VERSION 5.8 ;
BUSBITCHARS "[]" ;
DIVIDERCHAR "/" ;
UNITS
    DATABASE MICRONS 1000 ;
END UNITS

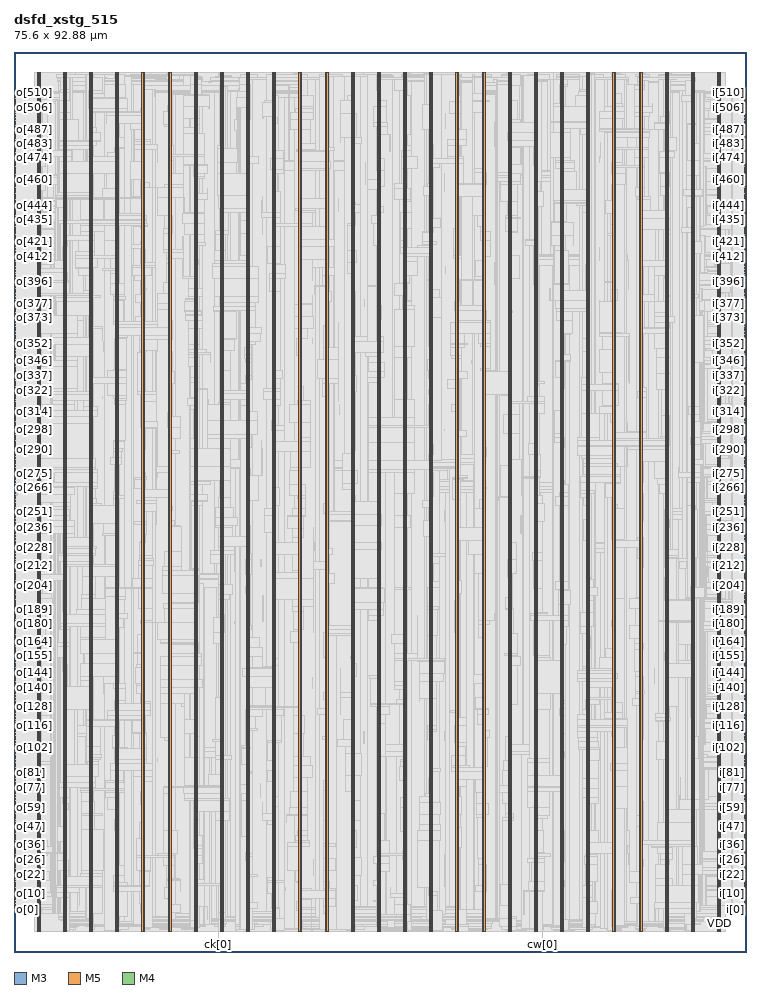
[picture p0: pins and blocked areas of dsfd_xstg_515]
MACRO dsfd_xstg_515
  FOREIGN dsfd_xstg_515 0 0 ;
  CLASS BLOCK ;
  SIZE 75.6 BY 92.88 ;
  PIN ck[0]
    DIRECTION INPUT ;
    USE SIGNAL ;
    PORT
      LAYER M3 ;
        RECT  21.06 0 21.078 0.144 ;
    END
  END ck[0]
  PIN cw[0]
    DIRECTION INPUT ;
    USE SIGNAL ;
    PORT
      LAYER M5 ;
        RECT  54.528 0 54.552 0.192 ;
    END
  END cw[0]
  PIN i[0]
    DIRECTION INPUT ;
    USE SIGNAL ;
    PORT
      LAYER M4 ;
        RECT  75.408 4.416 75.6 4.44 ;
    END
  END i[0]
  PIN i[100]
    DIRECTION INPUT ;
    USE SIGNAL ;
    PORT
      LAYER M4 ;
        RECT  75.408 20.784 75.6 20.808 ;
    END
  END i[100]
  PIN i[101]
    DIRECTION INPUT ;
    USE SIGNAL ;
    PORT
      LAYER M4 ;
        RECT  75.408 20.928 75.6 20.952 ;
    END
  END i[101]
  PIN i[102]
    DIRECTION INPUT ;
    USE SIGNAL ;
    PORT
      LAYER M4 ;
        RECT  75.408 21.12 75.6 21.144 ;
    END
  END i[102]
  PIN i[103]
    DIRECTION INPUT ;
    USE SIGNAL ;
    PORT
      LAYER M4 ;
        RECT  75.408 21.264 75.6 21.288 ;
    END
  END i[103]
  PIN i[104]
    DIRECTION INPUT ;
    USE SIGNAL ;
    PORT
      LAYER M4 ;
        RECT  75.408 21.408 75.6 21.432 ;
    END
  END i[104]
  PIN i[105]
    DIRECTION INPUT ;
    USE SIGNAL ;
    PORT
      LAYER M4 ;
        RECT  75.408 21.6 75.6 21.624 ;
    END
  END i[105]
  PIN i[106]
    DIRECTION INPUT ;
    USE SIGNAL ;
    PORT
      LAYER M4 ;
        RECT  75.408 21.744 75.6 21.768 ;
    END
  END i[106]
  PIN i[107]
    DIRECTION INPUT ;
    USE SIGNAL ;
    PORT
      LAYER M4 ;
        RECT  75.408 21.936 75.6 21.96 ;
    END
  END i[107]
  PIN i[108]
    DIRECTION INPUT ;
    USE SIGNAL ;
    PORT
      LAYER M4 ;
        RECT  75.408 22.08 75.6 22.104 ;
    END
  END i[108]
  PIN i[109]
    DIRECTION INPUT ;
    USE SIGNAL ;
    PORT
      LAYER M4 ;
        RECT  75.408 22.224 75.6 22.248 ;
    END
  END i[109]
  PIN i[10]
    DIRECTION INPUT ;
    USE SIGNAL ;
    PORT
      LAYER M4 ;
        RECT  75.408 6.048 75.6 6.072 ;
    END
  END i[10]
  PIN i[110]
    DIRECTION INPUT ;
    USE SIGNAL ;
    PORT
      LAYER M4 ;
        RECT  75.408 22.416 75.6 22.44 ;
    END
  END i[110]
  PIN i[111]
    DIRECTION INPUT ;
    USE SIGNAL ;
    PORT
      LAYER M4 ;
        RECT  75.408 22.56 75.6 22.584 ;
    END
  END i[111]
  PIN i[112]
    DIRECTION INPUT ;
    USE SIGNAL ;
    PORT
      LAYER M4 ;
        RECT  75.408 22.752 75.6 22.776 ;
    END
  END i[112]
  PIN i[113]
    DIRECTION INPUT ;
    USE SIGNAL ;
    PORT
      LAYER M4 ;
        RECT  75.408 22.896 75.6 22.92 ;
    END
  END i[113]
  PIN i[114]
    DIRECTION INPUT ;
    USE SIGNAL ;
    PORT
      LAYER M4 ;
        RECT  75.408 23.04 75.6 23.064 ;
    END
  END i[114]
  PIN i[115]
    DIRECTION INPUT ;
    USE SIGNAL ;
    PORT
      LAYER M4 ;
        RECT  75.408 23.232 75.6 23.256 ;
    END
  END i[115]
  PIN i[116]
    DIRECTION INPUT ;
    USE SIGNAL ;
    PORT
      LAYER M4 ;
        RECT  75.408 23.376 75.6 23.4 ;
    END
  END i[116]
  PIN i[117]
    DIRECTION INPUT ;
    USE SIGNAL ;
    PORT
      LAYER M4 ;
        RECT  75.408 23.568 75.6 23.592 ;
    END
  END i[117]
  PIN i[118]
    DIRECTION INPUT ;
    USE SIGNAL ;
    PORT
      LAYER M4 ;
        RECT  75.408 23.712 75.6 23.736 ;
    END
  END i[118]
  PIN i[119]
    DIRECTION INPUT ;
    USE SIGNAL ;
    PORT
      LAYER M4 ;
        RECT  75.408 23.856 75.6 23.88 ;
    END
  END i[119]
  PIN i[11]
    DIRECTION INPUT ;
    USE SIGNAL ;
    PORT
      LAYER M4 ;
        RECT  75.408 6.192 75.6 6.216 ;
    END
  END i[11]
  PIN i[120]
    DIRECTION INPUT ;
    USE SIGNAL ;
    PORT
      LAYER M4 ;
        RECT  75.408 24.048 75.6 24.072 ;
    END
  END i[120]
  PIN i[121]
    DIRECTION INPUT ;
    USE SIGNAL ;
    PORT
      LAYER M4 ;
        RECT  75.408 24.192 75.6 24.216 ;
    END
  END i[121]
  PIN i[122]
    DIRECTION INPUT ;
    USE SIGNAL ;
    PORT
      LAYER M4 ;
        RECT  75.408 24.384 75.6 24.408 ;
    END
  END i[122]
  PIN i[123]
    DIRECTION INPUT ;
    USE SIGNAL ;
    PORT
      LAYER M4 ;
        RECT  75.408 24.528 75.6 24.552 ;
    END
  END i[123]
  PIN i[124]
    DIRECTION INPUT ;
    USE SIGNAL ;
    PORT
      LAYER M4 ;
        RECT  75.408 24.72 75.6 24.744 ;
    END
  END i[124]
  PIN i[125]
    DIRECTION INPUT ;
    USE SIGNAL ;
    PORT
      LAYER M4 ;
        RECT  75.408 24.864 75.6 24.888 ;
    END
  END i[125]
  PIN i[126]
    DIRECTION INPUT ;
    USE SIGNAL ;
    PORT
      LAYER M4 ;
        RECT  75.408 25.008 75.6 25.032 ;
    END
  END i[126]
  PIN i[127]
    DIRECTION INPUT ;
    USE SIGNAL ;
    PORT
      LAYER M4 ;
        RECT  75.408 25.2 75.6 25.224 ;
    END
  END i[127]
  PIN i[128]
    DIRECTION INPUT ;
    USE SIGNAL ;
    PORT
      LAYER M4 ;
        RECT  75.408 25.344 75.6 25.368 ;
    END
  END i[128]
  PIN i[129]
    DIRECTION INPUT ;
    USE SIGNAL ;
    PORT
      LAYER M4 ;
        RECT  75.408 25.536 75.6 25.56 ;
    END
  END i[129]
  PIN i[12]
    DIRECTION INPUT ;
    USE SIGNAL ;
    PORT
      LAYER M4 ;
        RECT  75.408 6.384 75.6 6.408 ;
    END
  END i[12]
  PIN i[130]
    DIRECTION INPUT ;
    USE SIGNAL ;
    PORT
      LAYER M4 ;
        RECT  75.408 25.68 75.6 25.704 ;
    END
  END i[130]
  PIN i[131]
    DIRECTION INPUT ;
    USE SIGNAL ;
    PORT
      LAYER M4 ;
        RECT  75.408 25.824 75.6 25.848 ;
    END
  END i[131]
  PIN i[132]
    DIRECTION INPUT ;
    USE SIGNAL ;
    PORT
      LAYER M4 ;
        RECT  75.408 26.016 75.6 26.04 ;
    END
  END i[132]
  PIN i[133]
    DIRECTION INPUT ;
    USE SIGNAL ;
    PORT
      LAYER M4 ;
        RECT  75.408 26.16 75.6 26.184 ;
    END
  END i[133]
  PIN i[134]
    DIRECTION INPUT ;
    USE SIGNAL ;
    PORT
      LAYER M4 ;
        RECT  75.408 26.352 75.6 26.376 ;
    END
  END i[134]
  PIN i[135]
    DIRECTION INPUT ;
    USE SIGNAL ;
    PORT
      LAYER M4 ;
        RECT  75.408 26.496 75.6 26.52 ;
    END
  END i[135]
  PIN i[136]
    DIRECTION INPUT ;
    USE SIGNAL ;
    PORT
      LAYER M4 ;
        RECT  75.408 26.64 75.6 26.664 ;
    END
  END i[136]
  PIN i[137]
    DIRECTION INPUT ;
    USE SIGNAL ;
    PORT
      LAYER M4 ;
        RECT  75.408 26.832 75.6 26.856 ;
    END
  END i[137]
  PIN i[138]
    DIRECTION INPUT ;
    USE SIGNAL ;
    PORT
      LAYER M4 ;
        RECT  75.408 26.976 75.6 27 ;
    END
  END i[138]
  PIN i[139]
    DIRECTION INPUT ;
    USE SIGNAL ;
    PORT
      LAYER M4 ;
        RECT  75.408 27.168 75.6 27.192 ;
    END
  END i[139]
  PIN i[13]
    DIRECTION INPUT ;
    USE SIGNAL ;
    PORT
      LAYER M4 ;
        RECT  75.408 6.528 75.6 6.552 ;
    END
  END i[13]
  PIN i[140]
    DIRECTION INPUT ;
    USE SIGNAL ;
    PORT
      LAYER M4 ;
        RECT  75.408 27.312 75.6 27.336 ;
    END
  END i[140]
  PIN i[141]
    DIRECTION INPUT ;
    USE SIGNAL ;
    PORT
      LAYER M4 ;
        RECT  75.408 27.456 75.6 27.48 ;
    END
  END i[141]
  PIN i[142]
    DIRECTION INPUT ;
    USE SIGNAL ;
    PORT
      LAYER M4 ;
        RECT  75.408 27.648 75.6 27.672 ;
    END
  END i[142]
  PIN i[143]
    DIRECTION INPUT ;
    USE SIGNAL ;
    PORT
      LAYER M4 ;
        RECT  75.408 27.792 75.6 27.816 ;
    END
  END i[143]
  PIN i[144]
    DIRECTION INPUT ;
    USE SIGNAL ;
    PORT
      LAYER M4 ;
        RECT  75.408 27.984 75.6 28.008 ;
    END
  END i[144]
  PIN i[145]
    DIRECTION INPUT ;
    USE SIGNAL ;
    PORT
      LAYER M4 ;
        RECT  75.408 28.128 75.6 28.152 ;
    END
  END i[145]
  PIN i[146]
    DIRECTION INPUT ;
    USE SIGNAL ;
    PORT
      LAYER M4 ;
        RECT  75.408 28.272 75.6 28.296 ;
    END
  END i[146]
  PIN i[147]
    DIRECTION INPUT ;
    USE SIGNAL ;
    PORT
      LAYER M4 ;
        RECT  75.408 28.464 75.6 28.488 ;
    END
  END i[147]
  PIN i[148]
    DIRECTION INPUT ;
    USE SIGNAL ;
    PORT
      LAYER M4 ;
        RECT  75.408 28.608 75.6 28.632 ;
    END
  END i[148]
  PIN i[149]
    DIRECTION INPUT ;
    USE SIGNAL ;
    PORT
      LAYER M4 ;
        RECT  75.408 28.8 75.6 28.824 ;
    END
  END i[149]
  PIN i[14]
    DIRECTION INPUT ;
    USE SIGNAL ;
    PORT
      LAYER M4 ;
        RECT  75.408 6.72 75.6 6.744 ;
    END
  END i[14]
  PIN i[150]
    DIRECTION INPUT ;
    USE SIGNAL ;
    PORT
      LAYER M4 ;
        RECT  75.408 28.944 75.6 28.968 ;
    END
  END i[150]
  PIN i[151]
    DIRECTION INPUT ;
    USE SIGNAL ;
    PORT
      LAYER M4 ;
        RECT  75.408 29.136 75.6 29.16 ;
    END
  END i[151]
  PIN i[152]
    DIRECTION INPUT ;
    USE SIGNAL ;
    PORT
      LAYER M4 ;
        RECT  75.408 29.28 75.6 29.304 ;
    END
  END i[152]
  PIN i[153]
    DIRECTION INPUT ;
    USE SIGNAL ;
    PORT
      LAYER M4 ;
        RECT  75.408 29.424 75.6 29.448 ;
    END
  END i[153]
  PIN i[154]
    DIRECTION INPUT ;
    USE SIGNAL ;
    PORT
      LAYER M4 ;
        RECT  75.408 29.616 75.6 29.64 ;
    END
  END i[154]
  PIN i[155]
    DIRECTION INPUT ;
    USE SIGNAL ;
    PORT
      LAYER M4 ;
        RECT  75.408 29.76 75.6 29.784 ;
    END
  END i[155]
  PIN i[156]
    DIRECTION INPUT ;
    USE SIGNAL ;
    PORT
      LAYER M4 ;
        RECT  75.408 29.952 75.6 29.976 ;
    END
  END i[156]
  PIN i[157]
    DIRECTION INPUT ;
    USE SIGNAL ;
    PORT
      LAYER M4 ;
        RECT  75.408 30.096 75.6 30.12 ;
    END
  END i[157]
  PIN i[158]
    DIRECTION INPUT ;
    USE SIGNAL ;
    PORT
      LAYER M4 ;
        RECT  75.408 30.24 75.6 30.264 ;
    END
  END i[158]
  PIN i[159]
    DIRECTION INPUT ;
    USE SIGNAL ;
    PORT
      LAYER M4 ;
        RECT  75.408 30.432 75.6 30.456 ;
    END
  END i[159]
  PIN i[15]
    DIRECTION INPUT ;
    USE SIGNAL ;
    PORT
      LAYER M4 ;
        RECT  75.408 6.864 75.6 6.888 ;
    END
  END i[15]
  PIN i[160]
    DIRECTION INPUT ;
    USE SIGNAL ;
    PORT
      LAYER M4 ;
        RECT  75.408 30.576 75.6 30.6 ;
    END
  END i[160]
  PIN i[161]
    DIRECTION INPUT ;
    USE SIGNAL ;
    PORT
      LAYER M4 ;
        RECT  75.408 30.768 75.6 30.792 ;
    END
  END i[161]
  PIN i[162]
    DIRECTION INPUT ;
    USE SIGNAL ;
    PORT
      LAYER M4 ;
        RECT  75.408 30.912 75.6 30.936 ;
    END
  END i[162]
  PIN i[163]
    DIRECTION INPUT ;
    USE SIGNAL ;
    PORT
      LAYER M4 ;
        RECT  75.408 31.056 75.6 31.08 ;
    END
  END i[163]
  PIN i[164]
    DIRECTION INPUT ;
    USE SIGNAL ;
    PORT
      LAYER M4 ;
        RECT  75.408 31.248 75.6 31.272 ;
    END
  END i[164]
  PIN i[165]
    DIRECTION INPUT ;
    USE SIGNAL ;
    PORT
      LAYER M4 ;
        RECT  75.408 31.392 75.6 31.416 ;
    END
  END i[165]
  PIN i[166]
    DIRECTION INPUT ;
    USE SIGNAL ;
    PORT
      LAYER M4 ;
        RECT  75.408 31.584 75.6 31.608 ;
    END
  END i[166]
  PIN i[167]
    DIRECTION INPUT ;
    USE SIGNAL ;
    PORT
      LAYER M4 ;
        RECT  75.408 31.728 75.6 31.752 ;
    END
  END i[167]
  PIN i[168]
    DIRECTION INPUT ;
    USE SIGNAL ;
    PORT
      LAYER M4 ;
        RECT  75.408 31.872 75.6 31.896 ;
    END
  END i[168]
  PIN i[169]
    DIRECTION INPUT ;
    USE SIGNAL ;
    PORT
      LAYER M4 ;
        RECT  75.408 32.064 75.6 32.088 ;
    END
  END i[169]
  PIN i[16]
    DIRECTION INPUT ;
    USE SIGNAL ;
    PORT
      LAYER M4 ;
        RECT  75.408 7.008 75.6 7.032 ;
    END
  END i[16]
  PIN i[170]
    DIRECTION INPUT ;
    USE SIGNAL ;
    PORT
      LAYER M4 ;
        RECT  75.408 32.208 75.6 32.232 ;
    END
  END i[170]
  PIN i[171]
    DIRECTION INPUT ;
    USE SIGNAL ;
    PORT
      LAYER M4 ;
        RECT  75.408 32.4 75.6 32.424 ;
    END
  END i[171]
  PIN i[172]
    DIRECTION INPUT ;
    USE SIGNAL ;
    PORT
      LAYER M4 ;
        RECT  75.408 32.544 75.6 32.568 ;
    END
  END i[172]
  PIN i[173]
    DIRECTION INPUT ;
    USE SIGNAL ;
    PORT
      LAYER M4 ;
        RECT  75.408 32.688 75.6 32.712 ;
    END
  END i[173]
  PIN i[174]
    DIRECTION INPUT ;
    USE SIGNAL ;
    PORT
      LAYER M4 ;
        RECT  75.408 32.88 75.6 32.904 ;
    END
  END i[174]
  PIN i[175]
    DIRECTION INPUT ;
    USE SIGNAL ;
    PORT
      LAYER M4 ;
        RECT  75.408 33.024 75.6 33.048 ;
    END
  END i[175]
  PIN i[176]
    DIRECTION INPUT ;
    USE SIGNAL ;
    PORT
      LAYER M4 ;
        RECT  75.408 33.216 75.6 33.24 ;
    END
  END i[176]
  PIN i[177]
    DIRECTION INPUT ;
    USE SIGNAL ;
    PORT
      LAYER M4 ;
        RECT  75.408 33.36 75.6 33.384 ;
    END
  END i[177]
  PIN i[178]
    DIRECTION INPUT ;
    USE SIGNAL ;
    PORT
      LAYER M4 ;
        RECT  75.408 33.552 75.6 33.576 ;
    END
  END i[178]
  PIN i[179]
    DIRECTION INPUT ;
    USE SIGNAL ;
    PORT
      LAYER M4 ;
        RECT  75.408 33.696 75.6 33.72 ;
    END
  END i[179]
  PIN i[17]
    DIRECTION INPUT ;
    USE SIGNAL ;
    PORT
      LAYER M4 ;
        RECT  75.408 7.2 75.6 7.224 ;
    END
  END i[17]
  PIN i[180]
    DIRECTION INPUT ;
    USE SIGNAL ;
    PORT
      LAYER M4 ;
        RECT  75.408 33.84 75.6 33.864 ;
    END
  END i[180]
  PIN i[181]
    DIRECTION INPUT ;
    USE SIGNAL ;
    PORT
      LAYER M4 ;
        RECT  75.408 34.032 75.6 34.056 ;
    END
  END i[181]
  PIN i[182]
    DIRECTION INPUT ;
    USE SIGNAL ;
    PORT
      LAYER M4 ;
        RECT  75.408 34.176 75.6 34.2 ;
    END
  END i[182]
  PIN i[183]
    DIRECTION INPUT ;
    USE SIGNAL ;
    PORT
      LAYER M4 ;
        RECT  75.408 34.368 75.6 34.392 ;
    END
  END i[183]
  PIN i[184]
    DIRECTION INPUT ;
    USE SIGNAL ;
    PORT
      LAYER M4 ;
        RECT  75.408 34.512 75.6 34.536 ;
    END
  END i[184]
  PIN i[185]
    DIRECTION INPUT ;
    USE SIGNAL ;
    PORT
      LAYER M4 ;
        RECT  75.408 34.656 75.6 34.68 ;
    END
  END i[185]
  PIN i[186]
    DIRECTION INPUT ;
    USE SIGNAL ;
    PORT
      LAYER M4 ;
        RECT  75.408 34.848 75.6 34.872 ;
    END
  END i[186]
  PIN i[187]
    DIRECTION INPUT ;
    USE SIGNAL ;
    PORT
      LAYER M4 ;
        RECT  75.408 34.992 75.6 35.016 ;
    END
  END i[187]
  PIN i[188]
    DIRECTION INPUT ;
    USE SIGNAL ;
    PORT
      LAYER M4 ;
        RECT  75.408 35.184 75.6 35.208 ;
    END
  END i[188]
  PIN i[189]
    DIRECTION INPUT ;
    USE SIGNAL ;
    PORT
      LAYER M4 ;
        RECT  75.408 35.328 75.6 35.352 ;
    END
  END i[189]
  PIN i[18]
    DIRECTION INPUT ;
    USE SIGNAL ;
    PORT
      LAYER M4 ;
        RECT  75.408 7.344 75.6 7.368 ;
    END
  END i[18]
  PIN i[190]
    DIRECTION INPUT ;
    USE SIGNAL ;
    PORT
      LAYER M4 ;
        RECT  75.408 35.472 75.6 35.496 ;
    END
  END i[190]
  PIN i[191]
    DIRECTION INPUT ;
    USE SIGNAL ;
    PORT
      LAYER M4 ;
        RECT  75.408 35.664 75.6 35.688 ;
    END
  END i[191]
  PIN i[192]
    DIRECTION INPUT ;
    USE SIGNAL ;
    PORT
      LAYER M4 ;
        RECT  75.408 35.808 75.6 35.832 ;
    END
  END i[192]
  PIN i[193]
    DIRECTION INPUT ;
    USE SIGNAL ;
    PORT
      LAYER M4 ;
        RECT  75.408 36 75.6 36.024 ;
    END
  END i[193]
  PIN i[194]
    DIRECTION INPUT ;
    USE SIGNAL ;
    PORT
      LAYER M4 ;
        RECT  75.408 36.144 75.6 36.168 ;
    END
  END i[194]
  PIN i[195]
    DIRECTION INPUT ;
    USE SIGNAL ;
    PORT
      LAYER M4 ;
        RECT  75.408 36.288 75.6 36.312 ;
    END
  END i[195]
  PIN i[196]
    DIRECTION INPUT ;
    USE SIGNAL ;
    PORT
      LAYER M4 ;
        RECT  75.408 36.48 75.6 36.504 ;
    END
  END i[196]
  PIN i[197]
    DIRECTION INPUT ;
    USE SIGNAL ;
    PORT
      LAYER M4 ;
        RECT  75.408 36.624 75.6 36.648 ;
    END
  END i[197]
  PIN i[198]
    DIRECTION INPUT ;
    USE SIGNAL ;
    PORT
      LAYER M4 ;
        RECT  75.408 36.816 75.6 36.84 ;
    END
  END i[198]
  PIN i[199]
    DIRECTION INPUT ;
    USE SIGNAL ;
    PORT
      LAYER M4 ;
        RECT  75.408 36.96 75.6 36.984 ;
    END
  END i[199]
  PIN i[19]
    DIRECTION INPUT ;
    USE SIGNAL ;
    PORT
      LAYER M4 ;
        RECT  75.408 7.536 75.6 7.56 ;
    END
  END i[19]
  PIN i[1]
    DIRECTION INPUT ;
    USE SIGNAL ;
    PORT
      LAYER M4 ;
        RECT  75.408 4.56 75.6 4.584 ;
    END
  END i[1]
  PIN i[200]
    DIRECTION INPUT ;
    USE SIGNAL ;
    PORT
      LAYER M4 ;
        RECT  75.408 37.152 75.6 37.176 ;
    END
  END i[200]
  PIN i[201]
    DIRECTION INPUT ;
    USE SIGNAL ;
    PORT
      LAYER M4 ;
        RECT  75.408 37.296 75.6 37.32 ;
    END
  END i[201]
  PIN i[202]
    DIRECTION INPUT ;
    USE SIGNAL ;
    PORT
      LAYER M4 ;
        RECT  75.408 37.44 75.6 37.464 ;
    END
  END i[202]
  PIN i[203]
    DIRECTION INPUT ;
    USE SIGNAL ;
    PORT
      LAYER M4 ;
        RECT  75.408 37.632 75.6 37.656 ;
    END
  END i[203]
  PIN i[204]
    DIRECTION INPUT ;
    USE SIGNAL ;
    PORT
      LAYER M4 ;
        RECT  75.408 37.776 75.6 37.8 ;
    END
  END i[204]
  PIN i[205]
    DIRECTION INPUT ;
    USE SIGNAL ;
    PORT
      LAYER M4 ;
        RECT  75.408 37.968 75.6 37.992 ;
    END
  END i[205]
  PIN i[206]
    DIRECTION INPUT ;
    USE SIGNAL ;
    PORT
      LAYER M4 ;
        RECT  75.408 38.112 75.6 38.136 ;
    END
  END i[206]
  PIN i[207]
    DIRECTION INPUT ;
    USE SIGNAL ;
    PORT
      LAYER M4 ;
        RECT  75.408 38.256 75.6 38.28 ;
    END
  END i[207]
  PIN i[208]
    DIRECTION INPUT ;
    USE SIGNAL ;
    PORT
      LAYER M4 ;
        RECT  75.408 38.448 75.6 38.472 ;
    END
  END i[208]
  PIN i[209]
    DIRECTION INPUT ;
    USE SIGNAL ;
    PORT
      LAYER M4 ;
        RECT  75.408 38.592 75.6 38.616 ;
    END
  END i[209]
  PIN i[20]
    DIRECTION INPUT ;
    USE SIGNAL ;
    PORT
      LAYER M4 ;
        RECT  75.408 7.68 75.6 7.704 ;
    END
  END i[20]
  PIN i[210]
    DIRECTION INPUT ;
    USE SIGNAL ;
    PORT
      LAYER M4 ;
        RECT  75.408 38.784 75.6 38.808 ;
    END
  END i[210]
  PIN i[211]
    DIRECTION INPUT ;
    USE SIGNAL ;
    PORT
      LAYER M4 ;
        RECT  75.408 38.928 75.6 38.952 ;
    END
  END i[211]
  PIN i[212]
    DIRECTION INPUT ;
    USE SIGNAL ;
    PORT
      LAYER M4 ;
        RECT  75.408 39.072 75.6 39.096 ;
    END
  END i[212]
  PIN i[213]
    DIRECTION INPUT ;
    USE SIGNAL ;
    PORT
      LAYER M4 ;
        RECT  75.408 39.264 75.6 39.288 ;
    END
  END i[213]
  PIN i[214]
    DIRECTION INPUT ;
    USE SIGNAL ;
    PORT
      LAYER M4 ;
        RECT  75.408 39.408 75.6 39.432 ;
    END
  END i[214]
  PIN i[215]
    DIRECTION INPUT ;
    USE SIGNAL ;
    PORT
      LAYER M4 ;
        RECT  75.408 39.6 75.6 39.624 ;
    END
  END i[215]
  PIN i[216]
    DIRECTION INPUT ;
    USE SIGNAL ;
    PORT
      LAYER M4 ;
        RECT  75.408 39.744 75.6 39.768 ;
    END
  END i[216]
  PIN i[217]
    DIRECTION INPUT ;
    USE SIGNAL ;
    PORT
      LAYER M4 ;
        RECT  75.408 39.888 75.6 39.912 ;
    END
  END i[217]
  PIN i[218]
    DIRECTION INPUT ;
    USE SIGNAL ;
    PORT
      LAYER M4 ;
        RECT  75.408 40.08 75.6 40.104 ;
    END
  END i[218]
  PIN i[219]
    DIRECTION INPUT ;
    USE SIGNAL ;
    PORT
      LAYER M4 ;
        RECT  75.408 40.224 75.6 40.248 ;
    END
  END i[219]
  PIN i[21]
    DIRECTION INPUT ;
    USE SIGNAL ;
    PORT
      LAYER M4 ;
        RECT  75.408 7.872 75.6 7.896 ;
    END
  END i[21]
  PIN i[220]
    DIRECTION INPUT ;
    USE SIGNAL ;
    PORT
      LAYER M4 ;
        RECT  75.408 40.416 75.6 40.44 ;
    END
  END i[220]
  PIN i[221]
    DIRECTION INPUT ;
    USE SIGNAL ;
    PORT
      LAYER M4 ;
        RECT  75.408 40.56 75.6 40.584 ;
    END
  END i[221]
  PIN i[222]
    DIRECTION INPUT ;
    USE SIGNAL ;
    PORT
      LAYER M4 ;
        RECT  75.408 40.704 75.6 40.728 ;
    END
  END i[222]
  PIN i[223]
    DIRECTION INPUT ;
    USE SIGNAL ;
    PORT
      LAYER M4 ;
        RECT  75.408 40.896 75.6 40.92 ;
    END
  END i[223]
  PIN i[224]
    DIRECTION INPUT ;
    USE SIGNAL ;
    PORT
      LAYER M4 ;
        RECT  75.408 41.04 75.6 41.064 ;
    END
  END i[224]
  PIN i[225]
    DIRECTION INPUT ;
    USE SIGNAL ;
    PORT
      LAYER M4 ;
        RECT  75.408 41.232 75.6 41.256 ;
    END
  END i[225]
  PIN i[226]
    DIRECTION INPUT ;
    USE SIGNAL ;
    PORT
      LAYER M4 ;
        RECT  75.408 41.376 75.6 41.4 ;
    END
  END i[226]
  PIN i[227]
    DIRECTION INPUT ;
    USE SIGNAL ;
    PORT
      LAYER M4 ;
        RECT  75.408 41.568 75.6 41.592 ;
    END
  END i[227]
  PIN i[228]
    DIRECTION INPUT ;
    USE SIGNAL ;
    PORT
      LAYER M4 ;
        RECT  75.408 41.712 75.6 41.736 ;
    END
  END i[228]
  PIN i[229]
    DIRECTION INPUT ;
    USE SIGNAL ;
    PORT
      LAYER M4 ;
        RECT  75.408 41.856 75.6 41.88 ;
    END
  END i[229]
  PIN i[22]
    DIRECTION INPUT ;
    USE SIGNAL ;
    PORT
      LAYER M4 ;
        RECT  75.408 8.016 75.6 8.04 ;
    END
  END i[22]
  PIN i[230]
    DIRECTION INPUT ;
    USE SIGNAL ;
    PORT
      LAYER M4 ;
        RECT  75.408 42.048 75.6 42.072 ;
    END
  END i[230]
  PIN i[231]
    DIRECTION INPUT ;
    USE SIGNAL ;
    PORT
      LAYER M4 ;
        RECT  75.408 42.192 75.6 42.216 ;
    END
  END i[231]
  PIN i[232]
    DIRECTION INPUT ;
    USE SIGNAL ;
    PORT
      LAYER M4 ;
        RECT  75.408 42.384 75.6 42.408 ;
    END
  END i[232]
  PIN i[233]
    DIRECTION INPUT ;
    USE SIGNAL ;
    PORT
      LAYER M4 ;
        RECT  75.408 42.528 75.6 42.552 ;
    END
  END i[233]
  PIN i[234]
    DIRECTION INPUT ;
    USE SIGNAL ;
    PORT
      LAYER M4 ;
        RECT  75.408 42.672 75.6 42.696 ;
    END
  END i[234]
  PIN i[235]
    DIRECTION INPUT ;
    USE SIGNAL ;
    PORT
      LAYER M4 ;
        RECT  75.408 42.864 75.6 42.888 ;
    END
  END i[235]
  PIN i[236]
    DIRECTION INPUT ;
    USE SIGNAL ;
    PORT
      LAYER M4 ;
        RECT  75.408 43.008 75.6 43.032 ;
    END
  END i[236]
  PIN i[237]
    DIRECTION INPUT ;
    USE SIGNAL ;
    PORT
      LAYER M4 ;
        RECT  75.408 43.2 75.6 43.224 ;
    END
  END i[237]
  PIN i[238]
    DIRECTION INPUT ;
    USE SIGNAL ;
    PORT
      LAYER M4 ;
        RECT  75.408 43.344 75.6 43.368 ;
    END
  END i[238]
  PIN i[239]
    DIRECTION INPUT ;
    USE SIGNAL ;
    PORT
      LAYER M4 ;
        RECT  75.408 43.488 75.6 43.512 ;
    END
  END i[239]
  PIN i[23]
    DIRECTION INPUT ;
    USE SIGNAL ;
    PORT
      LAYER M4 ;
        RECT  75.408 8.16 75.6 8.184 ;
    END
  END i[23]
  PIN i[240]
    DIRECTION INPUT ;
    USE SIGNAL ;
    PORT
      LAYER M4 ;
        RECT  75.408 43.68 75.6 43.704 ;
    END
  END i[240]
  PIN i[241]
    DIRECTION INPUT ;
    USE SIGNAL ;
    PORT
      LAYER M4 ;
        RECT  75.408 43.824 75.6 43.848 ;
    END
  END i[241]
  PIN i[242]
    DIRECTION INPUT ;
    USE SIGNAL ;
    PORT
      LAYER M4 ;
        RECT  75.408 44.016 75.6 44.04 ;
    END
  END i[242]
  PIN i[243]
    DIRECTION INPUT ;
    USE SIGNAL ;
    PORT
      LAYER M4 ;
        RECT  75.408 44.16 75.6 44.184 ;
    END
  END i[243]
  PIN i[244]
    DIRECTION INPUT ;
    USE SIGNAL ;
    PORT
      LAYER M4 ;
        RECT  75.408 44.304 75.6 44.328 ;
    END
  END i[244]
  PIN i[245]
    DIRECTION INPUT ;
    USE SIGNAL ;
    PORT
      LAYER M4 ;
        RECT  75.408 44.496 75.6 44.52 ;
    END
  END i[245]
  PIN i[246]
    DIRECTION INPUT ;
    USE SIGNAL ;
    PORT
      LAYER M4 ;
        RECT  75.408 44.64 75.6 44.664 ;
    END
  END i[246]
  PIN i[247]
    DIRECTION INPUT ;
    USE SIGNAL ;
    PORT
      LAYER M4 ;
        RECT  75.408 44.832 75.6 44.856 ;
    END
  END i[247]
  PIN i[248]
    DIRECTION INPUT ;
    USE SIGNAL ;
    PORT
      LAYER M4 ;
        RECT  75.408 44.976 75.6 45 ;
    END
  END i[248]
  PIN i[249]
    DIRECTION INPUT ;
    USE SIGNAL ;
    PORT
      LAYER M4 ;
        RECT  75.408 45.12 75.6 45.144 ;
    END
  END i[249]
  PIN i[24]
    DIRECTION INPUT ;
    USE SIGNAL ;
    PORT
      LAYER M4 ;
        RECT  75.408 8.352 75.6 8.376 ;
    END
  END i[24]
  PIN i[250]
    DIRECTION INPUT ;
    USE SIGNAL ;
    PORT
      LAYER M4 ;
        RECT  75.408 45.312 75.6 45.336 ;
    END
  END i[250]
  PIN i[251]
    DIRECTION INPUT ;
    USE SIGNAL ;
    PORT
      LAYER M4 ;
        RECT  75.408 45.456 75.6 45.48 ;
    END
  END i[251]
  PIN i[252]
    DIRECTION INPUT ;
    USE SIGNAL ;
    PORT
      LAYER M4 ;
        RECT  75.408 45.648 75.6 45.672 ;
    END
  END i[252]
  PIN i[253]
    DIRECTION INPUT ;
    USE SIGNAL ;
    PORT
      LAYER M4 ;
        RECT  75.408 45.792 75.6 45.816 ;
    END
  END i[253]
  PIN i[254]
    DIRECTION INPUT ;
    USE SIGNAL ;
    PORT
      LAYER M4 ;
        RECT  75.408 45.984 75.6 46.008 ;
    END
  END i[254]
  PIN i[255]
    DIRECTION INPUT ;
    USE SIGNAL ;
    PORT
      LAYER M4 ;
        RECT  75.408 46.128 75.6 46.152 ;
    END
  END i[255]
  PIN i[256]
    DIRECTION INPUT ;
    USE SIGNAL ;
    PORT
      LAYER M4 ;
        RECT  75.408 46.272 75.6 46.296 ;
    END
  END i[256]
  PIN i[257]
    DIRECTION INPUT ;
    USE SIGNAL ;
    PORT
      LAYER M4 ;
        RECT  75.408 46.464 75.6 46.488 ;
    END
  END i[257]
  PIN i[258]
    DIRECTION INPUT ;
    USE SIGNAL ;
    PORT
      LAYER M4 ;
        RECT  75.408 46.608 75.6 46.632 ;
    END
  END i[258]
  PIN i[259]
    DIRECTION INPUT ;
    USE SIGNAL ;
    PORT
      LAYER M4 ;
        RECT  75.408 46.8 75.6 46.824 ;
    END
  END i[259]
  PIN i[25]
    DIRECTION INPUT ;
    USE SIGNAL ;
    PORT
      LAYER M4 ;
        RECT  75.408 8.496 75.6 8.52 ;
    END
  END i[25]
  PIN i[260]
    DIRECTION INPUT ;
    USE SIGNAL ;
    PORT
      LAYER M4 ;
        RECT  75.408 46.944 75.6 46.968 ;
    END
  END i[260]
  PIN i[261]
    DIRECTION INPUT ;
    USE SIGNAL ;
    PORT
      LAYER M4 ;
        RECT  75.408 47.088 75.6 47.112 ;
    END
  END i[261]
  PIN i[262]
    DIRECTION INPUT ;
    USE SIGNAL ;
    PORT
      LAYER M4 ;
        RECT  75.408 47.28 75.6 47.304 ;
    END
  END i[262]
  PIN i[263]
    DIRECTION INPUT ;
    USE SIGNAL ;
    PORT
      LAYER M4 ;
        RECT  75.408 47.424 75.6 47.448 ;
    END
  END i[263]
  PIN i[264]
    DIRECTION INPUT ;
    USE SIGNAL ;
    PORT
      LAYER M4 ;
        RECT  75.408 47.616 75.6 47.64 ;
    END
  END i[264]
  PIN i[265]
    DIRECTION INPUT ;
    USE SIGNAL ;
    PORT
      LAYER M4 ;
        RECT  75.408 47.76 75.6 47.784 ;
    END
  END i[265]
  PIN i[266]
    DIRECTION INPUT ;
    USE SIGNAL ;
    PORT
      LAYER M4 ;
        RECT  75.408 47.904 75.6 47.928 ;
    END
  END i[266]
  PIN i[267]
    DIRECTION INPUT ;
    USE SIGNAL ;
    PORT
      LAYER M4 ;
        RECT  75.408 48.096 75.6 48.12 ;
    END
  END i[267]
  PIN i[268]
    DIRECTION INPUT ;
    USE SIGNAL ;
    PORT
      LAYER M4 ;
        RECT  75.408 48.24 75.6 48.264 ;
    END
  END i[268]
  PIN i[269]
    DIRECTION INPUT ;
    USE SIGNAL ;
    PORT
      LAYER M4 ;
        RECT  75.408 48.432 75.6 48.456 ;
    END
  END i[269]
  PIN i[26]
    DIRECTION INPUT ;
    USE SIGNAL ;
    PORT
      LAYER M4 ;
        RECT  75.408 8.688 75.6 8.712 ;
    END
  END i[26]
  PIN i[270]
    DIRECTION INPUT ;
    USE SIGNAL ;
    PORT
      LAYER M4 ;
        RECT  75.408 48.576 75.6 48.6 ;
    END
  END i[270]
  PIN i[271]
    DIRECTION INPUT ;
    USE SIGNAL ;
    PORT
      LAYER M4 ;
        RECT  75.408 48.72 75.6 48.744 ;
    END
  END i[271]
  PIN i[272]
    DIRECTION INPUT ;
    USE SIGNAL ;
    PORT
      LAYER M4 ;
        RECT  75.408 48.912 75.6 48.936 ;
    END
  END i[272]
  PIN i[273]
    DIRECTION INPUT ;
    USE SIGNAL ;
    PORT
      LAYER M4 ;
        RECT  75.408 49.056 75.6 49.08 ;
    END
  END i[273]
  PIN i[274]
    DIRECTION INPUT ;
    USE SIGNAL ;
    PORT
      LAYER M4 ;
        RECT  75.408 49.248 75.6 49.272 ;
    END
  END i[274]
  PIN i[275]
    DIRECTION INPUT ;
    USE SIGNAL ;
    PORT
      LAYER M4 ;
        RECT  75.408 49.392 75.6 49.416 ;
    END
  END i[275]
  PIN i[276]
    DIRECTION INPUT ;
    USE SIGNAL ;
    PORT
      LAYER M4 ;
        RECT  75.408 49.536 75.6 49.56 ;
    END
  END i[276]
  PIN i[277]
    DIRECTION INPUT ;
    USE SIGNAL ;
    PORT
      LAYER M4 ;
        RECT  75.408 49.728 75.6 49.752 ;
    END
  END i[277]
  PIN i[278]
    DIRECTION INPUT ;
    USE SIGNAL ;
    PORT
      LAYER M4 ;
        RECT  75.408 49.872 75.6 49.896 ;
    END
  END i[278]
  PIN i[279]
    DIRECTION INPUT ;
    USE SIGNAL ;
    PORT
      LAYER M4 ;
        RECT  75.408 50.064 75.6 50.088 ;
    END
  END i[279]
  PIN i[27]
    DIRECTION INPUT ;
    USE SIGNAL ;
    PORT
      LAYER M4 ;
        RECT  75.408 8.832 75.6 8.856 ;
    END
  END i[27]
  PIN i[280]
    DIRECTION INPUT ;
    USE SIGNAL ;
    PORT
      LAYER M4 ;
        RECT  75.408 50.208 75.6 50.232 ;
    END
  END i[280]
  PIN i[281]
    DIRECTION INPUT ;
    USE SIGNAL ;
    PORT
      LAYER M4 ;
        RECT  75.408 50.4 75.6 50.424 ;
    END
  END i[281]
  PIN i[282]
    DIRECTION INPUT ;
    USE SIGNAL ;
    PORT
      LAYER M4 ;
        RECT  75.408 50.544 75.6 50.568 ;
    END
  END i[282]
  PIN i[283]
    DIRECTION INPUT ;
    USE SIGNAL ;
    PORT
      LAYER M4 ;
        RECT  75.408 50.688 75.6 50.712 ;
    END
  END i[283]
  PIN i[284]
    DIRECTION INPUT ;
    USE SIGNAL ;
    PORT
      LAYER M4 ;
        RECT  75.408 50.88 75.6 50.904 ;
    END
  END i[284]
  PIN i[285]
    DIRECTION INPUT ;
    USE SIGNAL ;
    PORT
      LAYER M4 ;
        RECT  75.408 51.024 75.6 51.048 ;
    END
  END i[285]
  PIN i[286]
    DIRECTION INPUT ;
    USE SIGNAL ;
    PORT
      LAYER M4 ;
        RECT  75.408 51.216 75.6 51.24 ;
    END
  END i[286]
  PIN i[287]
    DIRECTION INPUT ;
    USE SIGNAL ;
    PORT
      LAYER M4 ;
        RECT  75.408 51.36 75.6 51.384 ;
    END
  END i[287]
  PIN i[288]
    DIRECTION INPUT ;
    USE SIGNAL ;
    PORT
      LAYER M4 ;
        RECT  75.408 51.504 75.6 51.528 ;
    END
  END i[288]
  PIN i[289]
    DIRECTION INPUT ;
    USE SIGNAL ;
    PORT
      LAYER M4 ;
        RECT  75.408 51.696 75.6 51.72 ;
    END
  END i[289]
  PIN i[28]
    DIRECTION INPUT ;
    USE SIGNAL ;
    PORT
      LAYER M4 ;
        RECT  75.408 8.976 75.6 9 ;
    END
  END i[28]
  PIN i[290]
    DIRECTION INPUT ;
    USE SIGNAL ;
    PORT
      LAYER M4 ;
        RECT  75.408 51.84 75.6 51.864 ;
    END
  END i[290]
  PIN i[291]
    DIRECTION INPUT ;
    USE SIGNAL ;
    PORT
      LAYER M4 ;
        RECT  75.408 52.032 75.6 52.056 ;
    END
  END i[291]
  PIN i[292]
    DIRECTION INPUT ;
    USE SIGNAL ;
    PORT
      LAYER M4 ;
        RECT  75.408 52.176 75.6 52.2 ;
    END
  END i[292]
  PIN i[293]
    DIRECTION INPUT ;
    USE SIGNAL ;
    PORT
      LAYER M4 ;
        RECT  75.408 52.32 75.6 52.344 ;
    END
  END i[293]
  PIN i[294]
    DIRECTION INPUT ;
    USE SIGNAL ;
    PORT
      LAYER M4 ;
        RECT  75.408 52.512 75.6 52.536 ;
    END
  END i[294]
  PIN i[295]
    DIRECTION INPUT ;
    USE SIGNAL ;
    PORT
      LAYER M4 ;
        RECT  75.408 52.656 75.6 52.68 ;
    END
  END i[295]
  PIN i[296]
    DIRECTION INPUT ;
    USE SIGNAL ;
    PORT
      LAYER M4 ;
        RECT  75.408 52.848 75.6 52.872 ;
    END
  END i[296]
  PIN i[297]
    DIRECTION INPUT ;
    USE SIGNAL ;
    PORT
      LAYER M4 ;
        RECT  75.408 52.992 75.6 53.016 ;
    END
  END i[297]
  PIN i[298]
    DIRECTION INPUT ;
    USE SIGNAL ;
    PORT
      LAYER M4 ;
        RECT  75.408 53.136 75.6 53.16 ;
    END
  END i[298]
  PIN i[299]
    DIRECTION INPUT ;
    USE SIGNAL ;
    PORT
      LAYER M4 ;
        RECT  75.408 53.328 75.6 53.352 ;
    END
  END i[299]
  PIN i[29]
    DIRECTION INPUT ;
    USE SIGNAL ;
    PORT
      LAYER M4 ;
        RECT  75.408 9.168 75.6 9.192 ;
    END
  END i[29]
  PIN i[2]
    DIRECTION INPUT ;
    USE SIGNAL ;
    PORT
      LAYER M4 ;
        RECT  75.408 4.752 75.6 4.776 ;
    END
  END i[2]
  PIN i[300]
    DIRECTION INPUT ;
    USE SIGNAL ;
    PORT
      LAYER M4 ;
        RECT  75.408 53.472 75.6 53.496 ;
    END
  END i[300]
  PIN i[301]
    DIRECTION INPUT ;
    USE SIGNAL ;
    PORT
      LAYER M4 ;
        RECT  75.408 53.664 75.6 53.688 ;
    END
  END i[301]
  PIN i[302]
    DIRECTION INPUT ;
    USE SIGNAL ;
    PORT
      LAYER M4 ;
        RECT  75.408 53.808 75.6 53.832 ;
    END
  END i[302]
  PIN i[303]
    DIRECTION INPUT ;
    USE SIGNAL ;
    PORT
      LAYER M4 ;
        RECT  75.408 54 75.6 54.024 ;
    END
  END i[303]
  PIN i[304]
    DIRECTION INPUT ;
    USE SIGNAL ;
    PORT
      LAYER M4 ;
        RECT  75.408 54.144 75.6 54.168 ;
    END
  END i[304]
  PIN i[305]
    DIRECTION INPUT ;
    USE SIGNAL ;
    PORT
      LAYER M4 ;
        RECT  75.408 54.288 75.6 54.312 ;
    END
  END i[305]
  PIN i[306]
    DIRECTION INPUT ;
    USE SIGNAL ;
    PORT
      LAYER M4 ;
        RECT  75.408 54.48 75.6 54.504 ;
    END
  END i[306]
  PIN i[307]
    DIRECTION INPUT ;
    USE SIGNAL ;
    PORT
      LAYER M4 ;
        RECT  75.408 54.624 75.6 54.648 ;
    END
  END i[307]
  PIN i[308]
    DIRECTION INPUT ;
    USE SIGNAL ;
    PORT
      LAYER M4 ;
        RECT  75.408 54.816 75.6 54.84 ;
    END
  END i[308]
  PIN i[309]
    DIRECTION INPUT ;
    USE SIGNAL ;
    PORT
      LAYER M4 ;
        RECT  75.408 54.96 75.6 54.984 ;
    END
  END i[309]
  PIN i[30]
    DIRECTION INPUT ;
    USE SIGNAL ;
    PORT
      LAYER M4 ;
        RECT  75.408 9.312 75.6 9.336 ;
    END
  END i[30]
  PIN i[310]
    DIRECTION INPUT ;
    USE SIGNAL ;
    PORT
      LAYER M4 ;
        RECT  75.408 55.104 75.6 55.128 ;
    END
  END i[310]
  PIN i[311]
    DIRECTION INPUT ;
    USE SIGNAL ;
    PORT
      LAYER M4 ;
        RECT  75.408 55.296 75.6 55.32 ;
    END
  END i[311]
  PIN i[312]
    DIRECTION INPUT ;
    USE SIGNAL ;
    PORT
      LAYER M4 ;
        RECT  75.408 55.44 75.6 55.464 ;
    END
  END i[312]
  PIN i[313]
    DIRECTION INPUT ;
    USE SIGNAL ;
    PORT
      LAYER M4 ;
        RECT  75.408 55.632 75.6 55.656 ;
    END
  END i[313]
  PIN i[314]
    DIRECTION INPUT ;
    USE SIGNAL ;
    PORT
      LAYER M4 ;
        RECT  75.408 55.776 75.6 55.8 ;
    END
  END i[314]
  PIN i[315]
    DIRECTION INPUT ;
    USE SIGNAL ;
    PORT
      LAYER M4 ;
        RECT  75.408 55.92 75.6 55.944 ;
    END
  END i[315]
  PIN i[316]
    DIRECTION INPUT ;
    USE SIGNAL ;
    PORT
      LAYER M4 ;
        RECT  75.408 56.112 75.6 56.136 ;
    END
  END i[316]
  PIN i[317]
    DIRECTION INPUT ;
    USE SIGNAL ;
    PORT
      LAYER M4 ;
        RECT  75.408 56.256 75.6 56.28 ;
    END
  END i[317]
  PIN i[318]
    DIRECTION INPUT ;
    USE SIGNAL ;
    PORT
      LAYER M4 ;
        RECT  75.408 56.448 75.6 56.472 ;
    END
  END i[318]
  PIN i[319]
    DIRECTION INPUT ;
    USE SIGNAL ;
    PORT
      LAYER M4 ;
        RECT  75.408 56.592 75.6 56.616 ;
    END
  END i[319]
  PIN i[31]
    DIRECTION INPUT ;
    USE SIGNAL ;
    PORT
      LAYER M4 ;
        RECT  75.408 9.504 75.6 9.528 ;
    END
  END i[31]
  PIN i[320]
    DIRECTION INPUT ;
    USE SIGNAL ;
    PORT
      LAYER M4 ;
        RECT  75.408 56.736 75.6 56.76 ;
    END
  END i[320]
  PIN i[321]
    DIRECTION INPUT ;
    USE SIGNAL ;
    PORT
      LAYER M4 ;
        RECT  75.408 56.928 75.6 56.952 ;
    END
  END i[321]
  PIN i[322]
    DIRECTION INPUT ;
    USE SIGNAL ;
    PORT
      LAYER M4 ;
        RECT  75.408 57.072 75.6 57.096 ;
    END
  END i[322]
  PIN i[323]
    DIRECTION INPUT ;
    USE SIGNAL ;
    PORT
      LAYER M4 ;
        RECT  75.408 57.264 75.6 57.288 ;
    END
  END i[323]
  PIN i[324]
    DIRECTION INPUT ;
    USE SIGNAL ;
    PORT
      LAYER M4 ;
        RECT  75.408 57.408 75.6 57.432 ;
    END
  END i[324]
  PIN i[325]
    DIRECTION INPUT ;
    USE SIGNAL ;
    PORT
      LAYER M4 ;
        RECT  75.408 57.552 75.6 57.576 ;
    END
  END i[325]
  PIN i[326]
    DIRECTION INPUT ;
    USE SIGNAL ;
    PORT
      LAYER M4 ;
        RECT  75.408 57.744 75.6 57.768 ;
    END
  END i[326]
  PIN i[327]
    DIRECTION INPUT ;
    USE SIGNAL ;
    PORT
      LAYER M4 ;
        RECT  75.408 57.888 75.6 57.912 ;
    END
  END i[327]
  PIN i[328]
    DIRECTION INPUT ;
    USE SIGNAL ;
    PORT
      LAYER M4 ;
        RECT  75.408 58.08 75.6 58.104 ;
    END
  END i[328]
  PIN i[329]
    DIRECTION INPUT ;
    USE SIGNAL ;
    PORT
      LAYER M4 ;
        RECT  75.408 58.224 75.6 58.248 ;
    END
  END i[329]
  PIN i[32]
    DIRECTION INPUT ;
    USE SIGNAL ;
    PORT
      LAYER M4 ;
        RECT  75.408 9.648 75.6 9.672 ;
    END
  END i[32]
  PIN i[330]
    DIRECTION INPUT ;
    USE SIGNAL ;
    PORT
      LAYER M4 ;
        RECT  75.408 58.416 75.6 58.44 ;
    END
  END i[330]
  PIN i[331]
    DIRECTION INPUT ;
    USE SIGNAL ;
    PORT
      LAYER M4 ;
        RECT  75.408 58.56 75.6 58.584 ;
    END
  END i[331]
  PIN i[332]
    DIRECTION INPUT ;
    USE SIGNAL ;
    PORT
      LAYER M4 ;
        RECT  75.408 58.704 75.6 58.728 ;
    END
  END i[332]
  PIN i[333]
    DIRECTION INPUT ;
    USE SIGNAL ;
    PORT
      LAYER M4 ;
        RECT  75.408 58.896 75.6 58.92 ;
    END
  END i[333]
  PIN i[334]
    DIRECTION INPUT ;
    USE SIGNAL ;
    PORT
      LAYER M4 ;
        RECT  75.408 59.04 75.6 59.064 ;
    END
  END i[334]
  PIN i[335]
    DIRECTION INPUT ;
    USE SIGNAL ;
    PORT
      LAYER M4 ;
        RECT  75.408 59.232 75.6 59.256 ;
    END
  END i[335]
  PIN i[336]
    DIRECTION INPUT ;
    USE SIGNAL ;
    PORT
      LAYER M4 ;
        RECT  75.408 59.376 75.6 59.4 ;
    END
  END i[336]
  PIN i[337]
    DIRECTION INPUT ;
    USE SIGNAL ;
    PORT
      LAYER M4 ;
        RECT  75.408 59.52 75.6 59.544 ;
    END
  END i[337]
  PIN i[338]
    DIRECTION INPUT ;
    USE SIGNAL ;
    PORT
      LAYER M4 ;
        RECT  75.408 59.712 75.6 59.736 ;
    END
  END i[338]
  PIN i[339]
    DIRECTION INPUT ;
    USE SIGNAL ;
    PORT
      LAYER M4 ;
        RECT  75.408 59.856 75.6 59.88 ;
    END
  END i[339]
  PIN i[33]
    DIRECTION INPUT ;
    USE SIGNAL ;
    PORT
      LAYER M4 ;
        RECT  75.408 9.792 75.6 9.816 ;
    END
  END i[33]
  PIN i[340]
    DIRECTION INPUT ;
    USE SIGNAL ;
    PORT
      LAYER M4 ;
        RECT  75.408 60.048 75.6 60.072 ;
    END
  END i[340]
  PIN i[341]
    DIRECTION INPUT ;
    USE SIGNAL ;
    PORT
      LAYER M4 ;
        RECT  75.408 60.192 75.6 60.216 ;
    END
  END i[341]
  PIN i[342]
    DIRECTION INPUT ;
    USE SIGNAL ;
    PORT
      LAYER M4 ;
        RECT  75.408 60.336 75.6 60.36 ;
    END
  END i[342]
  PIN i[343]
    DIRECTION INPUT ;
    USE SIGNAL ;
    PORT
      LAYER M4 ;
        RECT  75.408 60.528 75.6 60.552 ;
    END
  END i[343]
  PIN i[344]
    DIRECTION INPUT ;
    USE SIGNAL ;
    PORT
      LAYER M4 ;
        RECT  75.408 60.672 75.6 60.696 ;
    END
  END i[344]
  PIN i[345]
    DIRECTION INPUT ;
    USE SIGNAL ;
    PORT
      LAYER M4 ;
        RECT  75.408 60.864 75.6 60.888 ;
    END
  END i[345]
  PIN i[346]
    DIRECTION INPUT ;
    USE SIGNAL ;
    PORT
      LAYER M4 ;
        RECT  75.408 61.008 75.6 61.032 ;
    END
  END i[346]
  PIN i[347]
    DIRECTION INPUT ;
    USE SIGNAL ;
    PORT
      LAYER M4 ;
        RECT  75.408 61.152 75.6 61.176 ;
    END
  END i[347]
  PIN i[348]
    DIRECTION INPUT ;
    USE SIGNAL ;
    PORT
      LAYER M4 ;
        RECT  75.408 61.344 75.6 61.368 ;
    END
  END i[348]
  PIN i[349]
    DIRECTION INPUT ;
    USE SIGNAL ;
    PORT
      LAYER M4 ;
        RECT  75.408 61.488 75.6 61.512 ;
    END
  END i[349]
  PIN i[34]
    DIRECTION INPUT ;
    USE SIGNAL ;
    PORT
      LAYER M4 ;
        RECT  75.408 9.984 75.6 10.008 ;
    END
  END i[34]
  PIN i[350]
    DIRECTION INPUT ;
    USE SIGNAL ;
    PORT
      LAYER M4 ;
        RECT  75.408 61.68 75.6 61.704 ;
    END
  END i[350]
  PIN i[351]
    DIRECTION INPUT ;
    USE SIGNAL ;
    PORT
      LAYER M4 ;
        RECT  75.408 61.824 75.6 61.848 ;
    END
  END i[351]
  PIN i[352]
    DIRECTION INPUT ;
    USE SIGNAL ;
    PORT
      LAYER M4 ;
        RECT  75.408 61.968 75.6 61.992 ;
    END
  END i[352]
  PIN i[353]
    DIRECTION INPUT ;
    USE SIGNAL ;
    PORT
      LAYER M4 ;
        RECT  75.408 62.16 75.6 62.184 ;
    END
  END i[353]
  PIN i[354]
    DIRECTION INPUT ;
    USE SIGNAL ;
    PORT
      LAYER M4 ;
        RECT  75.408 62.304 75.6 62.328 ;
    END
  END i[354]
  PIN i[355]
    DIRECTION INPUT ;
    USE SIGNAL ;
    PORT
      LAYER M4 ;
        RECT  75.408 62.496 75.6 62.52 ;
    END
  END i[355]
  PIN i[356]
    DIRECTION INPUT ;
    USE SIGNAL ;
    PORT
      LAYER M4 ;
        RECT  75.408 62.64 75.6 62.664 ;
    END
  END i[356]
  PIN i[357]
    DIRECTION INPUT ;
    USE SIGNAL ;
    PORT
      LAYER M4 ;
        RECT  75.408 62.832 75.6 62.856 ;
    END
  END i[357]
  PIN i[358]
    DIRECTION INPUT ;
    USE SIGNAL ;
    PORT
      LAYER M4 ;
        RECT  75.408 62.976 75.6 63 ;
    END
  END i[358]
  PIN i[359]
    DIRECTION INPUT ;
    USE SIGNAL ;
    PORT
      LAYER M4 ;
        RECT  75.408 63.12 75.6 63.144 ;
    END
  END i[359]
  PIN i[35]
    DIRECTION INPUT ;
    USE SIGNAL ;
    PORT
      LAYER M4 ;
        RECT  75.408 10.128 75.6 10.152 ;
    END
  END i[35]
  PIN i[360]
    DIRECTION INPUT ;
    USE SIGNAL ;
    PORT
      LAYER M4 ;
        RECT  75.408 63.312 75.6 63.336 ;
    END
  END i[360]
  PIN i[361]
    DIRECTION INPUT ;
    USE SIGNAL ;
    PORT
      LAYER M4 ;
        RECT  75.408 63.456 75.6 63.48 ;
    END
  END i[361]
  PIN i[362]
    DIRECTION INPUT ;
    USE SIGNAL ;
    PORT
      LAYER M4 ;
        RECT  75.408 63.648 75.6 63.672 ;
    END
  END i[362]
  PIN i[363]
    DIRECTION INPUT ;
    USE SIGNAL ;
    PORT
      LAYER M4 ;
        RECT  75.408 63.792 75.6 63.816 ;
    END
  END i[363]
  PIN i[364]
    DIRECTION INPUT ;
    USE SIGNAL ;
    PORT
      LAYER M4 ;
        RECT  75.408 63.936 75.6 63.96 ;
    END
  END i[364]
  PIN i[365]
    DIRECTION INPUT ;
    USE SIGNAL ;
    PORT
      LAYER M4 ;
        RECT  75.408 64.128 75.6 64.152 ;
    END
  END i[365]
  PIN i[366]
    DIRECTION INPUT ;
    USE SIGNAL ;
    PORT
      LAYER M4 ;
        RECT  75.408 64.272 75.6 64.296 ;
    END
  END i[366]
  PIN i[367]
    DIRECTION INPUT ;
    USE SIGNAL ;
    PORT
      LAYER M4 ;
        RECT  75.408 64.464 75.6 64.488 ;
    END
  END i[367]
  PIN i[368]
    DIRECTION INPUT ;
    USE SIGNAL ;
    PORT
      LAYER M4 ;
        RECT  75.408 64.608 75.6 64.632 ;
    END
  END i[368]
  PIN i[369]
    DIRECTION INPUT ;
    USE SIGNAL ;
    PORT
      LAYER M4 ;
        RECT  75.408 64.752 75.6 64.776 ;
    END
  END i[369]
  PIN i[36]
    DIRECTION INPUT ;
    USE SIGNAL ;
    PORT
      LAYER M4 ;
        RECT  75.408 10.32 75.6 10.344 ;
    END
  END i[36]
  PIN i[370]
    DIRECTION INPUT ;
    USE SIGNAL ;
    PORT
      LAYER M4 ;
        RECT  75.408 64.944 75.6 64.968 ;
    END
  END i[370]
  PIN i[371]
    DIRECTION INPUT ;
    USE SIGNAL ;
    PORT
      LAYER M4 ;
        RECT  75.408 65.088 75.6 65.112 ;
    END
  END i[371]
  PIN i[372]
    DIRECTION INPUT ;
    USE SIGNAL ;
    PORT
      LAYER M4 ;
        RECT  75.408 65.28 75.6 65.304 ;
    END
  END i[372]
  PIN i[373]
    DIRECTION INPUT ;
    USE SIGNAL ;
    PORT
      LAYER M4 ;
        RECT  75.408 65.424 75.6 65.448 ;
    END
  END i[373]
  PIN i[374]
    DIRECTION INPUT ;
    USE SIGNAL ;
    PORT
      LAYER M4 ;
        RECT  75.408 65.568 75.6 65.592 ;
    END
  END i[374]
  PIN i[375]
    DIRECTION INPUT ;
    USE SIGNAL ;
    PORT
      LAYER M4 ;
        RECT  75.408 65.76 75.6 65.784 ;
    END
  END i[375]
  PIN i[376]
    DIRECTION INPUT ;
    USE SIGNAL ;
    PORT
      LAYER M4 ;
        RECT  75.408 65.904 75.6 65.928 ;
    END
  END i[376]
  PIN i[377]
    DIRECTION INPUT ;
    USE SIGNAL ;
    PORT
      LAYER M4 ;
        RECT  75.408 66.096 75.6 66.12 ;
    END
  END i[377]
  PIN i[378]
    DIRECTION INPUT ;
    USE SIGNAL ;
    PORT
      LAYER M4 ;
        RECT  75.408 66.24 75.6 66.264 ;
    END
  END i[378]
  PIN i[379]
    DIRECTION INPUT ;
    USE SIGNAL ;
    PORT
      LAYER M4 ;
        RECT  75.408 66.384 75.6 66.408 ;
    END
  END i[379]
  PIN i[37]
    DIRECTION INPUT ;
    USE SIGNAL ;
    PORT
      LAYER M4 ;
        RECT  75.408 10.464 75.6 10.488 ;
    END
  END i[37]
  PIN i[380]
    DIRECTION INPUT ;
    USE SIGNAL ;
    PORT
      LAYER M4 ;
        RECT  75.408 66.576 75.6 66.6 ;
    END
  END i[380]
  PIN i[381]
    DIRECTION INPUT ;
    USE SIGNAL ;
    PORT
      LAYER M4 ;
        RECT  75.408 66.72 75.6 66.744 ;
    END
  END i[381]
  PIN i[382]
    DIRECTION INPUT ;
    USE SIGNAL ;
    PORT
      LAYER M4 ;
        RECT  75.408 66.912 75.6 66.936 ;
    END
  END i[382]
  PIN i[383]
    DIRECTION INPUT ;
    USE SIGNAL ;
    PORT
      LAYER M4 ;
        RECT  75.408 67.056 75.6 67.08 ;
    END
  END i[383]
  PIN i[384]
    DIRECTION INPUT ;
    USE SIGNAL ;
    PORT
      LAYER M4 ;
        RECT  75.408 67.248 75.6 67.272 ;
    END
  END i[384]
  PIN i[385]
    DIRECTION INPUT ;
    USE SIGNAL ;
    PORT
      LAYER M4 ;
        RECT  75.408 67.392 75.6 67.416 ;
    END
  END i[385]
  PIN i[386]
    DIRECTION INPUT ;
    USE SIGNAL ;
    PORT
      LAYER M4 ;
        RECT  75.408 67.536 75.6 67.56 ;
    END
  END i[386]
  PIN i[387]
    DIRECTION INPUT ;
    USE SIGNAL ;
    PORT
      LAYER M4 ;
        RECT  75.408 67.728 75.6 67.752 ;
    END
  END i[387]
  PIN i[388]
    DIRECTION INPUT ;
    USE SIGNAL ;
    PORT
      LAYER M4 ;
        RECT  75.408 67.872 75.6 67.896 ;
    END
  END i[388]
  PIN i[389]
    DIRECTION INPUT ;
    USE SIGNAL ;
    PORT
      LAYER M4 ;
        RECT  75.408 68.064 75.6 68.088 ;
    END
  END i[389]
  PIN i[38]
    DIRECTION INPUT ;
    USE SIGNAL ;
    PORT
      LAYER M4 ;
        RECT  75.408 10.608 75.6 10.632 ;
    END
  END i[38]
  PIN i[390]
    DIRECTION INPUT ;
    USE SIGNAL ;
    PORT
      LAYER M4 ;
        RECT  75.408 68.208 75.6 68.232 ;
    END
  END i[390]
  PIN i[391]
    DIRECTION INPUT ;
    USE SIGNAL ;
    PORT
      LAYER M4 ;
        RECT  75.408 68.352 75.6 68.376 ;
    END
  END i[391]
  PIN i[392]
    DIRECTION INPUT ;
    USE SIGNAL ;
    PORT
      LAYER M4 ;
        RECT  75.408 68.544 75.6 68.568 ;
    END
  END i[392]
  PIN i[393]
    DIRECTION INPUT ;
    USE SIGNAL ;
    PORT
      LAYER M4 ;
        RECT  75.408 68.688 75.6 68.712 ;
    END
  END i[393]
  PIN i[394]
    DIRECTION INPUT ;
    USE SIGNAL ;
    PORT
      LAYER M4 ;
        RECT  75.408 68.88 75.6 68.904 ;
    END
  END i[394]
  PIN i[395]
    DIRECTION INPUT ;
    USE SIGNAL ;
    PORT
      LAYER M4 ;
        RECT  75.408 69.024 75.6 69.048 ;
    END
  END i[395]
  PIN i[396]
    DIRECTION INPUT ;
    USE SIGNAL ;
    PORT
      LAYER M4 ;
        RECT  75.408 69.168 75.6 69.192 ;
    END
  END i[396]
  PIN i[397]
    DIRECTION INPUT ;
    USE SIGNAL ;
    PORT
      LAYER M4 ;
        RECT  75.408 69.36 75.6 69.384 ;
    END
  END i[397]
  PIN i[398]
    DIRECTION INPUT ;
    USE SIGNAL ;
    PORT
      LAYER M4 ;
        RECT  75.408 69.504 75.6 69.528 ;
    END
  END i[398]
  PIN i[399]
    DIRECTION INPUT ;
    USE SIGNAL ;
    PORT
      LAYER M4 ;
        RECT  75.408 69.696 75.6 69.72 ;
    END
  END i[399]
  PIN i[39]
    DIRECTION INPUT ;
    USE SIGNAL ;
    PORT
      LAYER M4 ;
        RECT  75.408 10.8 75.6 10.824 ;
    END
  END i[39]
  PIN i[3]
    DIRECTION INPUT ;
    USE SIGNAL ;
    PORT
      LAYER M4 ;
        RECT  75.408 4.896 75.6 4.92 ;
    END
  END i[3]
  PIN i[400]
    DIRECTION INPUT ;
    USE SIGNAL ;
    PORT
      LAYER M4 ;
        RECT  75.408 69.84 75.6 69.864 ;
    END
  END i[400]
  PIN i[401]
    DIRECTION INPUT ;
    USE SIGNAL ;
    PORT
      LAYER M4 ;
        RECT  75.408 69.984 75.6 70.008 ;
    END
  END i[401]
  PIN i[402]
    DIRECTION INPUT ;
    USE SIGNAL ;
    PORT
      LAYER M4 ;
        RECT  75.408 70.176 75.6 70.2 ;
    END
  END i[402]
  PIN i[403]
    DIRECTION INPUT ;
    USE SIGNAL ;
    PORT
      LAYER M4 ;
        RECT  75.408 70.32 75.6 70.344 ;
    END
  END i[403]
  PIN i[404]
    DIRECTION INPUT ;
    USE SIGNAL ;
    PORT
      LAYER M4 ;
        RECT  75.408 70.512 75.6 70.536 ;
    END
  END i[404]
  PIN i[405]
    DIRECTION INPUT ;
    USE SIGNAL ;
    PORT
      LAYER M4 ;
        RECT  75.408 70.656 75.6 70.68 ;
    END
  END i[405]
  PIN i[406]
    DIRECTION INPUT ;
    USE SIGNAL ;
    PORT
      LAYER M4 ;
        RECT  75.408 70.848 75.6 70.872 ;
    END
  END i[406]
  PIN i[407]
    DIRECTION INPUT ;
    USE SIGNAL ;
    PORT
      LAYER M4 ;
        RECT  75.408 70.992 75.6 71.016 ;
    END
  END i[407]
  PIN i[408]
    DIRECTION INPUT ;
    USE SIGNAL ;
    PORT
      LAYER M4 ;
        RECT  75.408 71.136 75.6 71.16 ;
    END
  END i[408]
  PIN i[409]
    DIRECTION INPUT ;
    USE SIGNAL ;
    PORT
      LAYER M4 ;
        RECT  75.408 71.328 75.6 71.352 ;
    END
  END i[409]
  PIN i[40]
    DIRECTION INPUT ;
    USE SIGNAL ;
    PORT
      LAYER M4 ;
        RECT  75.408 10.944 75.6 10.968 ;
    END
  END i[40]
  PIN i[410]
    DIRECTION INPUT ;
    USE SIGNAL ;
    PORT
      LAYER M4 ;
        RECT  75.408 71.472 75.6 71.496 ;
    END
  END i[410]
  PIN i[411]
    DIRECTION INPUT ;
    USE SIGNAL ;
    PORT
      LAYER M4 ;
        RECT  75.408 71.664 75.6 71.688 ;
    END
  END i[411]
  PIN i[412]
    DIRECTION INPUT ;
    USE SIGNAL ;
    PORT
      LAYER M4 ;
        RECT  75.408 71.808 75.6 71.832 ;
    END
  END i[412]
  PIN i[413]
    DIRECTION INPUT ;
    USE SIGNAL ;
    PORT
      LAYER M4 ;
        RECT  75.408 71.952 75.6 71.976 ;
    END
  END i[413]
  PIN i[414]
    DIRECTION INPUT ;
    USE SIGNAL ;
    PORT
      LAYER M4 ;
        RECT  75.408 72.144 75.6 72.168 ;
    END
  END i[414]
  PIN i[415]
    DIRECTION INPUT ;
    USE SIGNAL ;
    PORT
      LAYER M4 ;
        RECT  75.408 72.288 75.6 72.312 ;
    END
  END i[415]
  PIN i[416]
    DIRECTION INPUT ;
    USE SIGNAL ;
    PORT
      LAYER M4 ;
        RECT  75.408 72.48 75.6 72.504 ;
    END
  END i[416]
  PIN i[417]
    DIRECTION INPUT ;
    USE SIGNAL ;
    PORT
      LAYER M4 ;
        RECT  75.408 72.624 75.6 72.648 ;
    END
  END i[417]
  PIN i[418]
    DIRECTION INPUT ;
    USE SIGNAL ;
    PORT
      LAYER M4 ;
        RECT  75.408 72.768 75.6 72.792 ;
    END
  END i[418]
  PIN i[419]
    DIRECTION INPUT ;
    USE SIGNAL ;
    PORT
      LAYER M4 ;
        RECT  75.408 72.96 75.6 72.984 ;
    END
  END i[419]
  PIN i[41]
    DIRECTION INPUT ;
    USE SIGNAL ;
    PORT
      LAYER M4 ;
        RECT  75.408 11.136 75.6 11.16 ;
    END
  END i[41]
  PIN i[420]
    DIRECTION INPUT ;
    USE SIGNAL ;
    PORT
      LAYER M4 ;
        RECT  75.408 73.104 75.6 73.128 ;
    END
  END i[420]
  PIN i[421]
    DIRECTION INPUT ;
    USE SIGNAL ;
    PORT
      LAYER M4 ;
        RECT  75.408 73.296 75.6 73.32 ;
    END
  END i[421]
  PIN i[422]
    DIRECTION INPUT ;
    USE SIGNAL ;
    PORT
      LAYER M4 ;
        RECT  75.408 73.44 75.6 73.464 ;
    END
  END i[422]
  PIN i[423]
    DIRECTION INPUT ;
    USE SIGNAL ;
    PORT
      LAYER M4 ;
        RECT  75.408 73.584 75.6 73.608 ;
    END
  END i[423]
  PIN i[424]
    DIRECTION INPUT ;
    USE SIGNAL ;
    PORT
      LAYER M4 ;
        RECT  75.408 73.776 75.6 73.8 ;
    END
  END i[424]
  PIN i[425]
    DIRECTION INPUT ;
    USE SIGNAL ;
    PORT
      LAYER M4 ;
        RECT  75.408 73.92 75.6 73.944 ;
    END
  END i[425]
  PIN i[426]
    DIRECTION INPUT ;
    USE SIGNAL ;
    PORT
      LAYER M4 ;
        RECT  75.408 74.112 75.6 74.136 ;
    END
  END i[426]
  PIN i[427]
    DIRECTION INPUT ;
    USE SIGNAL ;
    PORT
      LAYER M4 ;
        RECT  75.408 74.256 75.6 74.28 ;
    END
  END i[427]
  PIN i[428]
    DIRECTION INPUT ;
    USE SIGNAL ;
    PORT
      LAYER M4 ;
        RECT  75.408 74.4 75.6 74.424 ;
    END
  END i[428]
  PIN i[429]
    DIRECTION INPUT ;
    USE SIGNAL ;
    PORT
      LAYER M4 ;
        RECT  75.408 74.592 75.6 74.616 ;
    END
  END i[429]
  PIN i[42]
    DIRECTION INPUT ;
    USE SIGNAL ;
    PORT
      LAYER M4 ;
        RECT  75.408 11.28 75.6 11.304 ;
    END
  END i[42]
  PIN i[430]
    DIRECTION INPUT ;
    USE SIGNAL ;
    PORT
      LAYER M4 ;
        RECT  75.408 74.736 75.6 74.76 ;
    END
  END i[430]
  PIN i[431]
    DIRECTION INPUT ;
    USE SIGNAL ;
    PORT
      LAYER M4 ;
        RECT  75.408 74.928 75.6 74.952 ;
    END
  END i[431]
  PIN i[432]
    DIRECTION INPUT ;
    USE SIGNAL ;
    PORT
      LAYER M4 ;
        RECT  75.408 75.072 75.6 75.096 ;
    END
  END i[432]
  PIN i[433]
    DIRECTION INPUT ;
    USE SIGNAL ;
    PORT
      LAYER M4 ;
        RECT  75.408 75.264 75.6 75.288 ;
    END
  END i[433]
  PIN i[434]
    DIRECTION INPUT ;
    USE SIGNAL ;
    PORT
      LAYER M4 ;
        RECT  75.408 75.408 75.6 75.432 ;
    END
  END i[434]
  PIN i[435]
    DIRECTION INPUT ;
    USE SIGNAL ;
    PORT
      LAYER M4 ;
        RECT  75.408 75.552 75.6 75.576 ;
    END
  END i[435]
  PIN i[436]
    DIRECTION INPUT ;
    USE SIGNAL ;
    PORT
      LAYER M4 ;
        RECT  75.408 75.744 75.6 75.768 ;
    END
  END i[436]
  PIN i[437]
    DIRECTION INPUT ;
    USE SIGNAL ;
    PORT
      LAYER M4 ;
        RECT  75.408 75.888 75.6 75.912 ;
    END
  END i[437]
  PIN i[438]
    DIRECTION INPUT ;
    USE SIGNAL ;
    PORT
      LAYER M4 ;
        RECT  75.408 76.08 75.6 76.104 ;
    END
  END i[438]
  PIN i[439]
    DIRECTION INPUT ;
    USE SIGNAL ;
    PORT
      LAYER M4 ;
        RECT  75.408 76.224 75.6 76.248 ;
    END
  END i[439]
  PIN i[43]
    DIRECTION INPUT ;
    USE SIGNAL ;
    PORT
      LAYER M4 ;
        RECT  75.408 11.424 75.6 11.448 ;
    END
  END i[43]
  PIN i[440]
    DIRECTION INPUT ;
    USE SIGNAL ;
    PORT
      LAYER M4 ;
        RECT  75.408 76.368 75.6 76.392 ;
    END
  END i[440]
  PIN i[441]
    DIRECTION INPUT ;
    USE SIGNAL ;
    PORT
      LAYER M4 ;
        RECT  75.408 76.56 75.6 76.584 ;
    END
  END i[441]
  PIN i[442]
    DIRECTION INPUT ;
    USE SIGNAL ;
    PORT
      LAYER M4 ;
        RECT  75.408 76.704 75.6 76.728 ;
    END
  END i[442]
  PIN i[443]
    DIRECTION INPUT ;
    USE SIGNAL ;
    PORT
      LAYER M4 ;
        RECT  75.408 76.896 75.6 76.92 ;
    END
  END i[443]
  PIN i[444]
    DIRECTION INPUT ;
    USE SIGNAL ;
    PORT
      LAYER M4 ;
        RECT  75.408 77.04 75.6 77.064 ;
    END
  END i[444]
  PIN i[445]
    DIRECTION INPUT ;
    USE SIGNAL ;
    PORT
      LAYER M4 ;
        RECT  75.408 77.184 75.6 77.208 ;
    END
  END i[445]
  PIN i[446]
    DIRECTION INPUT ;
    USE SIGNAL ;
    PORT
      LAYER M4 ;
        RECT  75.408 77.376 75.6 77.4 ;
    END
  END i[446]
  PIN i[447]
    DIRECTION INPUT ;
    USE SIGNAL ;
    PORT
      LAYER M4 ;
        RECT  75.408 77.52 75.6 77.544 ;
    END
  END i[447]
  PIN i[448]
    DIRECTION INPUT ;
    USE SIGNAL ;
    PORT
      LAYER M4 ;
        RECT  75.408 77.712 75.6 77.736 ;
    END
  END i[448]
  PIN i[449]
    DIRECTION INPUT ;
    USE SIGNAL ;
    PORT
      LAYER M4 ;
        RECT  75.408 77.856 75.6 77.88 ;
    END
  END i[449]
  PIN i[44]
    DIRECTION INPUT ;
    USE SIGNAL ;
    PORT
      LAYER M4 ;
        RECT  75.408 11.616 75.6 11.64 ;
    END
  END i[44]
  PIN i[450]
    DIRECTION INPUT ;
    USE SIGNAL ;
    PORT
      LAYER M4 ;
        RECT  75.408 78 75.6 78.024 ;
    END
  END i[450]
  PIN i[451]
    DIRECTION INPUT ;
    USE SIGNAL ;
    PORT
      LAYER M4 ;
        RECT  75.408 78.192 75.6 78.216 ;
    END
  END i[451]
  PIN i[452]
    DIRECTION INPUT ;
    USE SIGNAL ;
    PORT
      LAYER M4 ;
        RECT  75.408 78.336 75.6 78.36 ;
    END
  END i[452]
  PIN i[453]
    DIRECTION INPUT ;
    USE SIGNAL ;
    PORT
      LAYER M4 ;
        RECT  75.408 78.528 75.6 78.552 ;
    END
  END i[453]
  PIN i[454]
    DIRECTION INPUT ;
    USE SIGNAL ;
    PORT
      LAYER M4 ;
        RECT  75.408 78.672 75.6 78.696 ;
    END
  END i[454]
  PIN i[455]
    DIRECTION INPUT ;
    USE SIGNAL ;
    PORT
      LAYER M4 ;
        RECT  75.408 78.816 75.6 78.84 ;
    END
  END i[455]
  PIN i[456]
    DIRECTION INPUT ;
    USE SIGNAL ;
    PORT
      LAYER M4 ;
        RECT  75.408 79.008 75.6 79.032 ;
    END
  END i[456]
  PIN i[457]
    DIRECTION INPUT ;
    USE SIGNAL ;
    PORT
      LAYER M4 ;
        RECT  75.408 79.152 75.6 79.176 ;
    END
  END i[457]
  PIN i[458]
    DIRECTION INPUT ;
    USE SIGNAL ;
    PORT
      LAYER M4 ;
        RECT  75.408 79.344 75.6 79.368 ;
    END
  END i[458]
  PIN i[459]
    DIRECTION INPUT ;
    USE SIGNAL ;
    PORT
      LAYER M4 ;
        RECT  75.408 79.488 75.6 79.512 ;
    END
  END i[459]
  PIN i[45]
    DIRECTION INPUT ;
    USE SIGNAL ;
    PORT
      LAYER M4 ;
        RECT  75.408 11.76 75.6 11.784 ;
    END
  END i[45]
  PIN i[460]
    DIRECTION INPUT ;
    USE SIGNAL ;
    PORT
      LAYER M4 ;
        RECT  75.408 79.68 75.6 79.704 ;
    END
  END i[460]
  PIN i[461]
    DIRECTION INPUT ;
    USE SIGNAL ;
    PORT
      LAYER M4 ;
        RECT  75.408 79.824 75.6 79.848 ;
    END
  END i[461]
  PIN i[462]
    DIRECTION INPUT ;
    USE SIGNAL ;
    PORT
      LAYER M4 ;
        RECT  75.408 79.968 75.6 79.992 ;
    END
  END i[462]
  PIN i[463]
    DIRECTION INPUT ;
    USE SIGNAL ;
    PORT
      LAYER M4 ;
        RECT  75.408 80.16 75.6 80.184 ;
    END
  END i[463]
  PIN i[464]
    DIRECTION INPUT ;
    USE SIGNAL ;
    PORT
      LAYER M4 ;
        RECT  75.408 80.304 75.6 80.328 ;
    END
  END i[464]
  PIN i[465]
    DIRECTION INPUT ;
    USE SIGNAL ;
    PORT
      LAYER M4 ;
        RECT  75.408 80.496 75.6 80.52 ;
    END
  END i[465]
  PIN i[466]
    DIRECTION INPUT ;
    USE SIGNAL ;
    PORT
      LAYER M4 ;
        RECT  75.408 80.64 75.6 80.664 ;
    END
  END i[466]
  PIN i[467]
    DIRECTION INPUT ;
    USE SIGNAL ;
    PORT
      LAYER M4 ;
        RECT  75.408 80.784 75.6 80.808 ;
    END
  END i[467]
  PIN i[468]
    DIRECTION INPUT ;
    USE SIGNAL ;
    PORT
      LAYER M4 ;
        RECT  75.408 80.976 75.6 81 ;
    END
  END i[468]
  PIN i[469]
    DIRECTION INPUT ;
    USE SIGNAL ;
    PORT
      LAYER M4 ;
        RECT  75.408 81.12 75.6 81.144 ;
    END
  END i[469]
  PIN i[46]
    DIRECTION INPUT ;
    USE SIGNAL ;
    PORT
      LAYER M4 ;
        RECT  75.408 11.952 75.6 11.976 ;
    END
  END i[46]
  PIN i[470]
    DIRECTION INPUT ;
    USE SIGNAL ;
    PORT
      LAYER M4 ;
        RECT  75.408 81.312 75.6 81.336 ;
    END
  END i[470]
  PIN i[471]
    DIRECTION INPUT ;
    USE SIGNAL ;
    PORT
      LAYER M4 ;
        RECT  75.408 81.456 75.6 81.48 ;
    END
  END i[471]
  PIN i[472]
    DIRECTION INPUT ;
    USE SIGNAL ;
    PORT
      LAYER M4 ;
        RECT  75.408 81.6 75.6 81.624 ;
    END
  END i[472]
  PIN i[473]
    DIRECTION INPUT ;
    USE SIGNAL ;
    PORT
      LAYER M4 ;
        RECT  75.408 81.792 75.6 81.816 ;
    END
  END i[473]
  PIN i[474]
    DIRECTION INPUT ;
    USE SIGNAL ;
    PORT
      LAYER M4 ;
        RECT  75.408 81.936 75.6 81.96 ;
    END
  END i[474]
  PIN i[475]
    DIRECTION INPUT ;
    USE SIGNAL ;
    PORT
      LAYER M4 ;
        RECT  75.408 82.128 75.6 82.152 ;
    END
  END i[475]
  PIN i[476]
    DIRECTION INPUT ;
    USE SIGNAL ;
    PORT
      LAYER M4 ;
        RECT  75.408 82.272 75.6 82.296 ;
    END
  END i[476]
  PIN i[477]
    DIRECTION INPUT ;
    USE SIGNAL ;
    PORT
      LAYER M4 ;
        RECT  75.408 82.416 75.6 82.44 ;
    END
  END i[477]
  PIN i[478]
    DIRECTION INPUT ;
    USE SIGNAL ;
    PORT
      LAYER M4 ;
        RECT  75.408 82.608 75.6 82.632 ;
    END
  END i[478]
  PIN i[479]
    DIRECTION INPUT ;
    USE SIGNAL ;
    PORT
      LAYER M4 ;
        RECT  75.408 82.752 75.6 82.776 ;
    END
  END i[479]
  PIN i[47]
    DIRECTION INPUT ;
    USE SIGNAL ;
    PORT
      LAYER M4 ;
        RECT  75.408 12.096 75.6 12.12 ;
    END
  END i[47]
  PIN i[480]
    DIRECTION INPUT ;
    USE SIGNAL ;
    PORT
      LAYER M4 ;
        RECT  75.408 82.944 75.6 82.968 ;
    END
  END i[480]
  PIN i[481]
    DIRECTION INPUT ;
    USE SIGNAL ;
    PORT
      LAYER M4 ;
        RECT  75.408 83.088 75.6 83.112 ;
    END
  END i[481]
  PIN i[482]
    DIRECTION INPUT ;
    USE SIGNAL ;
    PORT
      LAYER M4 ;
        RECT  75.408 83.232 75.6 83.256 ;
    END
  END i[482]
  PIN i[483]
    DIRECTION INPUT ;
    USE SIGNAL ;
    PORT
      LAYER M4 ;
        RECT  75.408 83.424 75.6 83.448 ;
    END
  END i[483]
  PIN i[484]
    DIRECTION INPUT ;
    USE SIGNAL ;
    PORT
      LAYER M4 ;
        RECT  75.408 83.568 75.6 83.592 ;
    END
  END i[484]
  PIN i[485]
    DIRECTION INPUT ;
    USE SIGNAL ;
    PORT
      LAYER M4 ;
        RECT  75.408 83.76 75.6 83.784 ;
    END
  END i[485]
  PIN i[486]
    DIRECTION INPUT ;
    USE SIGNAL ;
    PORT
      LAYER M4 ;
        RECT  75.408 83.904 75.6 83.928 ;
    END
  END i[486]
  PIN i[487]
    DIRECTION INPUT ;
    USE SIGNAL ;
    PORT
      LAYER M4 ;
        RECT  75.408 84.096 75.6 84.12 ;
    END
  END i[487]
  PIN i[488]
    DIRECTION INPUT ;
    USE SIGNAL ;
    PORT
      LAYER M4 ;
        RECT  75.408 84.24 75.6 84.264 ;
    END
  END i[488]
  PIN i[489]
    DIRECTION INPUT ;
    USE SIGNAL ;
    PORT
      LAYER M4 ;
        RECT  75.408 84.384 75.6 84.408 ;
    END
  END i[489]
  PIN i[48]
    DIRECTION INPUT ;
    USE SIGNAL ;
    PORT
      LAYER M4 ;
        RECT  75.408 12.288 75.6 12.312 ;
    END
  END i[48]
  PIN i[490]
    DIRECTION INPUT ;
    USE SIGNAL ;
    PORT
      LAYER M4 ;
        RECT  75.408 84.576 75.6 84.6 ;
    END
  END i[490]
  PIN i[491]
    DIRECTION INPUT ;
    USE SIGNAL ;
    PORT
      LAYER M4 ;
        RECT  75.408 84.72 75.6 84.744 ;
    END
  END i[491]
  PIN i[492]
    DIRECTION INPUT ;
    USE SIGNAL ;
    PORT
      LAYER M4 ;
        RECT  75.408 84.912 75.6 84.936 ;
    END
  END i[492]
  PIN i[493]
    DIRECTION INPUT ;
    USE SIGNAL ;
    PORT
      LAYER M4 ;
        RECT  75.408 85.056 75.6 85.08 ;
    END
  END i[493]
  PIN i[494]
    DIRECTION INPUT ;
    USE SIGNAL ;
    PORT
      LAYER M4 ;
        RECT  75.408 85.2 75.6 85.224 ;
    END
  END i[494]
  PIN i[495]
    DIRECTION INPUT ;
    USE SIGNAL ;
    PORT
      LAYER M4 ;
        RECT  75.408 85.392 75.6 85.416 ;
    END
  END i[495]
  PIN i[496]
    DIRECTION INPUT ;
    USE SIGNAL ;
    PORT
      LAYER M4 ;
        RECT  75.408 85.536 75.6 85.56 ;
    END
  END i[496]
  PIN i[497]
    DIRECTION INPUT ;
    USE SIGNAL ;
    PORT
      LAYER M4 ;
        RECT  75.408 85.728 75.6 85.752 ;
    END
  END i[497]
  PIN i[498]
    DIRECTION INPUT ;
    USE SIGNAL ;
    PORT
      LAYER M4 ;
        RECT  75.408 85.872 75.6 85.896 ;
    END
  END i[498]
  PIN i[499]
    DIRECTION INPUT ;
    USE SIGNAL ;
    PORT
      LAYER M4 ;
        RECT  75.408 86.016 75.6 86.04 ;
    END
  END i[499]
  PIN i[49]
    DIRECTION INPUT ;
    USE SIGNAL ;
    PORT
      LAYER M4 ;
        RECT  75.408 12.432 75.6 12.456 ;
    END
  END i[49]
  PIN i[4]
    DIRECTION INPUT ;
    USE SIGNAL ;
    PORT
      LAYER M4 ;
        RECT  75.408 5.088 75.6 5.112 ;
    END
  END i[4]
  PIN i[500]
    DIRECTION INPUT ;
    USE SIGNAL ;
    PORT
      LAYER M4 ;
        RECT  75.408 86.208 75.6 86.232 ;
    END
  END i[500]
  PIN i[501]
    DIRECTION INPUT ;
    USE SIGNAL ;
    PORT
      LAYER M4 ;
        RECT  75.408 86.352 75.6 86.376 ;
    END
  END i[501]
  PIN i[502]
    DIRECTION INPUT ;
    USE SIGNAL ;
    PORT
      LAYER M4 ;
        RECT  75.408 86.544 75.6 86.568 ;
    END
  END i[502]
  PIN i[503]
    DIRECTION INPUT ;
    USE SIGNAL ;
    PORT
      LAYER M4 ;
        RECT  75.408 86.688 75.6 86.712 ;
    END
  END i[503]
  PIN i[504]
    DIRECTION INPUT ;
    USE SIGNAL ;
    PORT
      LAYER M4 ;
        RECT  75.408 86.832 75.6 86.856 ;
    END
  END i[504]
  PIN i[505]
    DIRECTION INPUT ;
    USE SIGNAL ;
    PORT
      LAYER M4 ;
        RECT  75.408 87.024 75.6 87.048 ;
    END
  END i[505]
  PIN i[506]
    DIRECTION INPUT ;
    USE SIGNAL ;
    PORT
      LAYER M4 ;
        RECT  75.408 87.168 75.6 87.192 ;
    END
  END i[506]
  PIN i[507]
    DIRECTION INPUT ;
    USE SIGNAL ;
    PORT
      LAYER M4 ;
        RECT  75.408 87.36 75.6 87.384 ;
    END
  END i[507]
  PIN i[508]
    DIRECTION INPUT ;
    USE SIGNAL ;
    PORT
      LAYER M4 ;
        RECT  75.408 87.504 75.6 87.528 ;
    END
  END i[508]
  PIN i[509]
    DIRECTION INPUT ;
    USE SIGNAL ;
    PORT
      LAYER M4 ;
        RECT  75.408 87.696 75.6 87.72 ;
    END
  END i[509]
  PIN i[50]
    DIRECTION INPUT ;
    USE SIGNAL ;
    PORT
      LAYER M4 ;
        RECT  75.408 12.576 75.6 12.6 ;
    END
  END i[50]
  PIN i[510]
    DIRECTION INPUT ;
    USE SIGNAL ;
    PORT
      LAYER M4 ;
        RECT  75.408 87.84 75.6 87.864 ;
    END
  END i[510]
  PIN i[511]
    DIRECTION INPUT ;
    USE SIGNAL ;
    PORT
      LAYER M4 ;
        RECT  75.408 87.984 75.6 88.008 ;
    END
  END i[511]
  PIN i[512]
    DIRECTION INPUT ;
    USE SIGNAL ;
    PORT
      LAYER M4 ;
        RECT  75.408 88.176 75.6 88.2 ;
    END
  END i[512]
  PIN i[513]
    DIRECTION INPUT ;
    USE SIGNAL ;
    PORT
      LAYER M4 ;
        RECT  75.408 88.32 75.6 88.344 ;
    END
  END i[513]
  PIN i[514]
    DIRECTION INPUT ;
    USE SIGNAL ;
    PORT
      LAYER M4 ;
        RECT  75.408 88.512 75.6 88.536 ;
    END
  END i[514]
  PIN i[51]
    DIRECTION INPUT ;
    USE SIGNAL ;
    PORT
      LAYER M4 ;
        RECT  75.408 12.768 75.6 12.792 ;
    END
  END i[51]
  PIN i[52]
    DIRECTION INPUT ;
    USE SIGNAL ;
    PORT
      LAYER M4 ;
        RECT  75.408 12.912 75.6 12.936 ;
    END
  END i[52]
  PIN i[53]
    DIRECTION INPUT ;
    USE SIGNAL ;
    PORT
      LAYER M4 ;
        RECT  75.408 13.104 75.6 13.128 ;
    END
  END i[53]
  PIN i[54]
    DIRECTION INPUT ;
    USE SIGNAL ;
    PORT
      LAYER M4 ;
        RECT  75.408 13.248 75.6 13.272 ;
    END
  END i[54]
  PIN i[55]
    DIRECTION INPUT ;
    USE SIGNAL ;
    PORT
      LAYER M4 ;
        RECT  75.408 13.392 75.6 13.416 ;
    END
  END i[55]
  PIN i[56]
    DIRECTION INPUT ;
    USE SIGNAL ;
    PORT
      LAYER M4 ;
        RECT  75.408 13.584 75.6 13.608 ;
    END
  END i[56]
  PIN i[57]
    DIRECTION INPUT ;
    USE SIGNAL ;
    PORT
      LAYER M4 ;
        RECT  75.408 13.728 75.6 13.752 ;
    END
  END i[57]
  PIN i[58]
    DIRECTION INPUT ;
    USE SIGNAL ;
    PORT
      LAYER M4 ;
        RECT  75.408 13.92 75.6 13.944 ;
    END
  END i[58]
  PIN i[59]
    DIRECTION INPUT ;
    USE SIGNAL ;
    PORT
      LAYER M4 ;
        RECT  75.408 14.064 75.6 14.088 ;
    END
  END i[59]
  PIN i[5]
    DIRECTION INPUT ;
    USE SIGNAL ;
    PORT
      LAYER M4 ;
        RECT  75.408 5.232 75.6 5.256 ;
    END
  END i[5]
  PIN i[60]
    DIRECTION INPUT ;
    USE SIGNAL ;
    PORT
      LAYER M4 ;
        RECT  75.408 14.208 75.6 14.232 ;
    END
  END i[60]
  PIN i[61]
    DIRECTION INPUT ;
    USE SIGNAL ;
    PORT
      LAYER M4 ;
        RECT  75.408 14.4 75.6 14.424 ;
    END
  END i[61]
  PIN i[62]
    DIRECTION INPUT ;
    USE SIGNAL ;
    PORT
      LAYER M4 ;
        RECT  75.408 14.544 75.6 14.568 ;
    END
  END i[62]
  PIN i[63]
    DIRECTION INPUT ;
    USE SIGNAL ;
    PORT
      LAYER M4 ;
        RECT  75.408 14.736 75.6 14.76 ;
    END
  END i[63]
  PIN i[64]
    DIRECTION INPUT ;
    USE SIGNAL ;
    PORT
      LAYER M4 ;
        RECT  75.408 14.88 75.6 14.904 ;
    END
  END i[64]
  PIN i[65]
    DIRECTION INPUT ;
    USE SIGNAL ;
    PORT
      LAYER M4 ;
        RECT  75.408 15.024 75.6 15.048 ;
    END
  END i[65]
  PIN i[66]
    DIRECTION INPUT ;
    USE SIGNAL ;
    PORT
      LAYER M4 ;
        RECT  75.408 15.216 75.6 15.24 ;
    END
  END i[66]
  PIN i[67]
    DIRECTION INPUT ;
    USE SIGNAL ;
    PORT
      LAYER M4 ;
        RECT  75.408 15.36 75.6 15.384 ;
    END
  END i[67]
  PIN i[68]
    DIRECTION INPUT ;
    USE SIGNAL ;
    PORT
      LAYER M4 ;
        RECT  75.408 15.552 75.6 15.576 ;
    END
  END i[68]
  PIN i[69]
    DIRECTION INPUT ;
    USE SIGNAL ;
    PORT
      LAYER M4 ;
        RECT  75.408 15.696 75.6 15.72 ;
    END
  END i[69]
  PIN i[6]
    DIRECTION INPUT ;
    USE SIGNAL ;
    PORT
      LAYER M4 ;
        RECT  75.408 5.376 75.6 5.4 ;
    END
  END i[6]
  PIN i[70]
    DIRECTION INPUT ;
    USE SIGNAL ;
    PORT
      LAYER M4 ;
        RECT  75.408 15.84 75.6 15.864 ;
    END
  END i[70]
  PIN i[71]
    DIRECTION INPUT ;
    USE SIGNAL ;
    PORT
      LAYER M4 ;
        RECT  75.408 16.032 75.6 16.056 ;
    END
  END i[71]
  PIN i[72]
    DIRECTION INPUT ;
    USE SIGNAL ;
    PORT
      LAYER M4 ;
        RECT  75.408 16.176 75.6 16.2 ;
    END
  END i[72]
  PIN i[73]
    DIRECTION INPUT ;
    USE SIGNAL ;
    PORT
      LAYER M4 ;
        RECT  75.408 16.368 75.6 16.392 ;
    END
  END i[73]
  PIN i[74]
    DIRECTION INPUT ;
    USE SIGNAL ;
    PORT
      LAYER M4 ;
        RECT  75.408 16.512 75.6 16.536 ;
    END
  END i[74]
  PIN i[75]
    DIRECTION INPUT ;
    USE SIGNAL ;
    PORT
      LAYER M4 ;
        RECT  75.408 16.704 75.6 16.728 ;
    END
  END i[75]
  PIN i[76]
    DIRECTION INPUT ;
    USE SIGNAL ;
    PORT
      LAYER M4 ;
        RECT  75.408 16.848 75.6 16.872 ;
    END
  END i[76]
  PIN i[77]
    DIRECTION INPUT ;
    USE SIGNAL ;
    PORT
      LAYER M4 ;
        RECT  75.408 16.992 75.6 17.016 ;
    END
  END i[77]
  PIN i[78]
    DIRECTION INPUT ;
    USE SIGNAL ;
    PORT
      LAYER M4 ;
        RECT  75.408 17.184 75.6 17.208 ;
    END
  END i[78]
  PIN i[79]
    DIRECTION INPUT ;
    USE SIGNAL ;
    PORT
      LAYER M4 ;
        RECT  75.408 17.328 75.6 17.352 ;
    END
  END i[79]
  PIN i[7]
    DIRECTION INPUT ;
    USE SIGNAL ;
    PORT
      LAYER M4 ;
        RECT  75.408 5.568 75.6 5.592 ;
    END
  END i[7]
  PIN i[80]
    DIRECTION INPUT ;
    USE SIGNAL ;
    PORT
      LAYER M4 ;
        RECT  75.408 17.52 75.6 17.544 ;
    END
  END i[80]
  PIN i[81]
    DIRECTION INPUT ;
    USE SIGNAL ;
    PORT
      LAYER M4 ;
        RECT  75.408 17.664 75.6 17.688 ;
    END
  END i[81]
  PIN i[82]
    DIRECTION INPUT ;
    USE SIGNAL ;
    PORT
      LAYER M4 ;
        RECT  75.408 17.808 75.6 17.832 ;
    END
  END i[82]
  PIN i[83]
    DIRECTION INPUT ;
    USE SIGNAL ;
    PORT
      LAYER M4 ;
        RECT  75.408 18 75.6 18.024 ;
    END
  END i[83]
  PIN i[84]
    DIRECTION INPUT ;
    USE SIGNAL ;
    PORT
      LAYER M4 ;
        RECT  75.408 18.144 75.6 18.168 ;
    END
  END i[84]
  PIN i[85]
    DIRECTION INPUT ;
    USE SIGNAL ;
    PORT
      LAYER M4 ;
        RECT  75.408 18.336 75.6 18.36 ;
    END
  END i[85]
  PIN i[86]
    DIRECTION INPUT ;
    USE SIGNAL ;
    PORT
      LAYER M4 ;
        RECT  75.408 18.48 75.6 18.504 ;
    END
  END i[86]
  PIN i[87]
    DIRECTION INPUT ;
    USE SIGNAL ;
    PORT
      LAYER M4 ;
        RECT  75.408 18.624 75.6 18.648 ;
    END
  END i[87]
  PIN i[88]
    DIRECTION INPUT ;
    USE SIGNAL ;
    PORT
      LAYER M4 ;
        RECT  75.408 18.816 75.6 18.84 ;
    END
  END i[88]
  PIN i[89]
    DIRECTION INPUT ;
    USE SIGNAL ;
    PORT
      LAYER M4 ;
        RECT  75.408 18.96 75.6 18.984 ;
    END
  END i[89]
  PIN i[8]
    DIRECTION INPUT ;
    USE SIGNAL ;
    PORT
      LAYER M4 ;
        RECT  75.408 5.712 75.6 5.736 ;
    END
  END i[8]
  PIN i[90]
    DIRECTION INPUT ;
    USE SIGNAL ;
    PORT
      LAYER M4 ;
        RECT  75.408 19.152 75.6 19.176 ;
    END
  END i[90]
  PIN i[91]
    DIRECTION INPUT ;
    USE SIGNAL ;
    PORT
      LAYER M4 ;
        RECT  75.408 19.296 75.6 19.32 ;
    END
  END i[91]
  PIN i[92]
    DIRECTION INPUT ;
    USE SIGNAL ;
    PORT
      LAYER M4 ;
        RECT  75.408 19.44 75.6 19.464 ;
    END
  END i[92]
  PIN i[93]
    DIRECTION INPUT ;
    USE SIGNAL ;
    PORT
      LAYER M4 ;
        RECT  75.408 19.632 75.6 19.656 ;
    END
  END i[93]
  PIN i[94]
    DIRECTION INPUT ;
    USE SIGNAL ;
    PORT
      LAYER M4 ;
        RECT  75.408 19.776 75.6 19.8 ;
    END
  END i[94]
  PIN i[95]
    DIRECTION INPUT ;
    USE SIGNAL ;
    PORT
      LAYER M4 ;
        RECT  75.408 19.968 75.6 19.992 ;
    END
  END i[95]
  PIN i[96]
    DIRECTION INPUT ;
    USE SIGNAL ;
    PORT
      LAYER M4 ;
        RECT  75.408 20.112 75.6 20.136 ;
    END
  END i[96]
  PIN i[97]
    DIRECTION INPUT ;
    USE SIGNAL ;
    PORT
      LAYER M4 ;
        RECT  75.408 20.304 75.6 20.328 ;
    END
  END i[97]
  PIN i[98]
    DIRECTION INPUT ;
    USE SIGNAL ;
    PORT
      LAYER M4 ;
        RECT  75.408 20.448 75.6 20.472 ;
    END
  END i[98]
  PIN i[99]
    DIRECTION INPUT ;
    USE SIGNAL ;
    PORT
      LAYER M4 ;
        RECT  75.408 20.592 75.6 20.616 ;
    END
  END i[99]
  PIN i[9]
    DIRECTION INPUT ;
    USE SIGNAL ;
    PORT
      LAYER M4 ;
        RECT  75.408 5.904 75.6 5.928 ;
    END
  END i[9]
  PIN o[0]
    DIRECTION OUTPUT ;
    USE SIGNAL ;
    PORT
      LAYER M4 ;
        RECT  0 4.416 0.192 4.44 ;
    END
  END o[0]
  PIN o[100]
    DIRECTION OUTPUT ;
    USE SIGNAL ;
    PORT
      LAYER M4 ;
        RECT  0 20.784 0.192 20.808 ;
    END
  END o[100]
  PIN o[101]
    DIRECTION OUTPUT ;
    USE SIGNAL ;
    PORT
      LAYER M4 ;
        RECT  0 20.928 0.192 20.952 ;
    END
  END o[101]
  PIN o[102]
    DIRECTION OUTPUT ;
    USE SIGNAL ;
    PORT
      LAYER M4 ;
        RECT  0 21.12 0.192 21.144 ;
    END
  END o[102]
  PIN o[103]
    DIRECTION OUTPUT ;
    USE SIGNAL ;
    PORT
      LAYER M4 ;
        RECT  0 21.264 0.192 21.288 ;
    END
  END o[103]
  PIN o[104]
    DIRECTION OUTPUT ;
    USE SIGNAL ;
    PORT
      LAYER M4 ;
        RECT  0 21.408 0.192 21.432 ;
    END
  END o[104]
  PIN o[105]
    DIRECTION OUTPUT ;
    USE SIGNAL ;
    PORT
      LAYER M4 ;
        RECT  0 21.6 0.192 21.624 ;
    END
  END o[105]
  PIN o[106]
    DIRECTION OUTPUT ;
    USE SIGNAL ;
    PORT
      LAYER M4 ;
        RECT  0 21.744 0.192 21.768 ;
    END
  END o[106]
  PIN o[107]
    DIRECTION OUTPUT ;
    USE SIGNAL ;
    PORT
      LAYER M4 ;
        RECT  0 21.936 0.192 21.96 ;
    END
  END o[107]
  PIN o[108]
    DIRECTION OUTPUT ;
    USE SIGNAL ;
    PORT
      LAYER M4 ;
        RECT  0 22.08 0.192 22.104 ;
    END
  END o[108]
  PIN o[109]
    DIRECTION OUTPUT ;
    USE SIGNAL ;
    PORT
      LAYER M4 ;
        RECT  0 22.224 0.192 22.248 ;
    END
  END o[109]
  PIN o[10]
    DIRECTION OUTPUT ;
    USE SIGNAL ;
    PORT
      LAYER M4 ;
        RECT  0 6.048 0.192 6.072 ;
    END
  END o[10]
  PIN o[110]
    DIRECTION OUTPUT ;
    USE SIGNAL ;
    PORT
      LAYER M4 ;
        RECT  0 22.416 0.192 22.44 ;
    END
  END o[110]
  PIN o[111]
    DIRECTION OUTPUT ;
    USE SIGNAL ;
    PORT
      LAYER M4 ;
        RECT  0 22.56 0.192 22.584 ;
    END
  END o[111]
  PIN o[112]
    DIRECTION OUTPUT ;
    USE SIGNAL ;
    PORT
      LAYER M4 ;
        RECT  0 22.752 0.192 22.776 ;
    END
  END o[112]
  PIN o[113]
    DIRECTION OUTPUT ;
    USE SIGNAL ;
    PORT
      LAYER M4 ;
        RECT  0 22.896 0.192 22.92 ;
    END
  END o[113]
  PIN o[114]
    DIRECTION OUTPUT ;
    USE SIGNAL ;
    PORT
      LAYER M4 ;
        RECT  0 23.04 0.192 23.064 ;
    END
  END o[114]
  PIN o[115]
    DIRECTION OUTPUT ;
    USE SIGNAL ;
    PORT
      LAYER M4 ;
        RECT  0 23.232 0.192 23.256 ;
    END
  END o[115]
  PIN o[116]
    DIRECTION OUTPUT ;
    USE SIGNAL ;
    PORT
      LAYER M4 ;
        RECT  0 23.376 0.192 23.4 ;
    END
  END o[116]
  PIN o[117]
    DIRECTION OUTPUT ;
    USE SIGNAL ;
    PORT
      LAYER M4 ;
        RECT  0 23.568 0.192 23.592 ;
    END
  END o[117]
  PIN o[118]
    DIRECTION OUTPUT ;
    USE SIGNAL ;
    PORT
      LAYER M4 ;
        RECT  0 23.712 0.192 23.736 ;
    END
  END o[118]
  PIN o[119]
    DIRECTION OUTPUT ;
    USE SIGNAL ;
    PORT
      LAYER M4 ;
        RECT  0 23.856 0.192 23.88 ;
    END
  END o[119]
  PIN o[11]
    DIRECTION OUTPUT ;
    USE SIGNAL ;
    PORT
      LAYER M4 ;
        RECT  0 6.192 0.192 6.216 ;
    END
  END o[11]
  PIN o[120]
    DIRECTION OUTPUT ;
    USE SIGNAL ;
    PORT
      LAYER M4 ;
        RECT  0 24.048 0.192 24.072 ;
    END
  END o[120]
  PIN o[121]
    DIRECTION OUTPUT ;
    USE SIGNAL ;
    PORT
      LAYER M4 ;
        RECT  0 24.192 0.192 24.216 ;
    END
  END o[121]
  PIN o[122]
    DIRECTION OUTPUT ;
    USE SIGNAL ;
    PORT
      LAYER M4 ;
        RECT  0 24.384 0.192 24.408 ;
    END
  END o[122]
  PIN o[123]
    DIRECTION OUTPUT ;
    USE SIGNAL ;
    PORT
      LAYER M4 ;
        RECT  0 24.528 0.192 24.552 ;
    END
  END o[123]
  PIN o[124]
    DIRECTION OUTPUT ;
    USE SIGNAL ;
    PORT
      LAYER M4 ;
        RECT  0 24.72 0.192 24.744 ;
    END
  END o[124]
  PIN o[125]
    DIRECTION OUTPUT ;
    USE SIGNAL ;
    PORT
      LAYER M4 ;
        RECT  0 24.864 0.192 24.888 ;
    END
  END o[125]
  PIN o[126]
    DIRECTION OUTPUT ;
    USE SIGNAL ;
    PORT
      LAYER M4 ;
        RECT  0 25.008 0.192 25.032 ;
    END
  END o[126]
  PIN o[127]
    DIRECTION OUTPUT ;
    USE SIGNAL ;
    PORT
      LAYER M4 ;
        RECT  0 25.2 0.192 25.224 ;
    END
  END o[127]
  PIN o[128]
    DIRECTION OUTPUT ;
    USE SIGNAL ;
    PORT
      LAYER M4 ;
        RECT  0 25.344 0.192 25.368 ;
    END
  END o[128]
  PIN o[129]
    DIRECTION OUTPUT ;
    USE SIGNAL ;
    PORT
      LAYER M4 ;
        RECT  0 25.536 0.192 25.56 ;
    END
  END o[129]
  PIN o[12]
    DIRECTION OUTPUT ;
    USE SIGNAL ;
    PORT
      LAYER M4 ;
        RECT  0 6.384 0.192 6.408 ;
    END
  END o[12]
  PIN o[130]
    DIRECTION OUTPUT ;
    USE SIGNAL ;
    PORT
      LAYER M4 ;
        RECT  0 25.68 0.192 25.704 ;
    END
  END o[130]
  PIN o[131]
    DIRECTION OUTPUT ;
    USE SIGNAL ;
    PORT
      LAYER M4 ;
        RECT  0 25.824 0.192 25.848 ;
    END
  END o[131]
  PIN o[132]
    DIRECTION OUTPUT ;
    USE SIGNAL ;
    PORT
      LAYER M4 ;
        RECT  0 26.016 0.192 26.04 ;
    END
  END o[132]
  PIN o[133]
    DIRECTION OUTPUT ;
    USE SIGNAL ;
    PORT
      LAYER M4 ;
        RECT  0 26.16 0.192 26.184 ;
    END
  END o[133]
  PIN o[134]
    DIRECTION OUTPUT ;
    USE SIGNAL ;
    PORT
      LAYER M4 ;
        RECT  0 26.352 0.192 26.376 ;
    END
  END o[134]
  PIN o[135]
    DIRECTION OUTPUT ;
    USE SIGNAL ;
    PORT
      LAYER M4 ;
        RECT  0 26.496 0.192 26.52 ;
    END
  END o[135]
  PIN o[136]
    DIRECTION OUTPUT ;
    USE SIGNAL ;
    PORT
      LAYER M4 ;
        RECT  0 26.64 0.192 26.664 ;
    END
  END o[136]
  PIN o[137]
    DIRECTION OUTPUT ;
    USE SIGNAL ;
    PORT
      LAYER M4 ;
        RECT  0 26.832 0.192 26.856 ;
    END
  END o[137]
  PIN o[138]
    DIRECTION OUTPUT ;
    USE SIGNAL ;
    PORT
      LAYER M4 ;
        RECT  0 26.976 0.192 27 ;
    END
  END o[138]
  PIN o[139]
    DIRECTION OUTPUT ;
    USE SIGNAL ;
    PORT
      LAYER M4 ;
        RECT  0 27.168 0.192 27.192 ;
    END
  END o[139]
  PIN o[13]
    DIRECTION OUTPUT ;
    USE SIGNAL ;
    PORT
      LAYER M4 ;
        RECT  0 6.528 0.192 6.552 ;
    END
  END o[13]
  PIN o[140]
    DIRECTION OUTPUT ;
    USE SIGNAL ;
    PORT
      LAYER M4 ;
        RECT  0 27.312 0.192 27.336 ;
    END
  END o[140]
  PIN o[141]
    DIRECTION OUTPUT ;
    USE SIGNAL ;
    PORT
      LAYER M4 ;
        RECT  0 27.456 0.192 27.48 ;
    END
  END o[141]
  PIN o[142]
    DIRECTION OUTPUT ;
    USE SIGNAL ;
    PORT
      LAYER M4 ;
        RECT  0 27.648 0.192 27.672 ;
    END
  END o[142]
  PIN o[143]
    DIRECTION OUTPUT ;
    USE SIGNAL ;
    PORT
      LAYER M4 ;
        RECT  0 27.792 0.192 27.816 ;
    END
  END o[143]
  PIN o[144]
    DIRECTION OUTPUT ;
    USE SIGNAL ;
    PORT
      LAYER M4 ;
        RECT  0 27.984 0.192 28.008 ;
    END
  END o[144]
  PIN o[145]
    DIRECTION OUTPUT ;
    USE SIGNAL ;
    PORT
      LAYER M4 ;
        RECT  0 28.128 0.192 28.152 ;
    END
  END o[145]
  PIN o[146]
    DIRECTION OUTPUT ;
    USE SIGNAL ;
    PORT
      LAYER M4 ;
        RECT  0 28.272 0.192 28.296 ;
    END
  END o[146]
  PIN o[147]
    DIRECTION OUTPUT ;
    USE SIGNAL ;
    PORT
      LAYER M4 ;
        RECT  0 28.464 0.192 28.488 ;
    END
  END o[147]
  PIN o[148]
    DIRECTION OUTPUT ;
    USE SIGNAL ;
    PORT
      LAYER M4 ;
        RECT  0 28.608 0.192 28.632 ;
    END
  END o[148]
  PIN o[149]
    DIRECTION OUTPUT ;
    USE SIGNAL ;
    PORT
      LAYER M4 ;
        RECT  0 28.8 0.192 28.824 ;
    END
  END o[149]
  PIN o[14]
    DIRECTION OUTPUT ;
    USE SIGNAL ;
    PORT
      LAYER M4 ;
        RECT  0 6.72 0.192 6.744 ;
    END
  END o[14]
  PIN o[150]
    DIRECTION OUTPUT ;
    USE SIGNAL ;
    PORT
      LAYER M4 ;
        RECT  0 28.944 0.192 28.968 ;
    END
  END o[150]
  PIN o[151]
    DIRECTION OUTPUT ;
    USE SIGNAL ;
    PORT
      LAYER M4 ;
        RECT  0 29.136 0.192 29.16 ;
    END
  END o[151]
  PIN o[152]
    DIRECTION OUTPUT ;
    USE SIGNAL ;
    PORT
      LAYER M4 ;
        RECT  0 29.28 0.192 29.304 ;
    END
  END o[152]
  PIN o[153]
    DIRECTION OUTPUT ;
    USE SIGNAL ;
    PORT
      LAYER M4 ;
        RECT  0 29.424 0.192 29.448 ;
    END
  END o[153]
  PIN o[154]
    DIRECTION OUTPUT ;
    USE SIGNAL ;
    PORT
      LAYER M4 ;
        RECT  0 29.616 0.192 29.64 ;
    END
  END o[154]
  PIN o[155]
    DIRECTION OUTPUT ;
    USE SIGNAL ;
    PORT
      LAYER M4 ;
        RECT  0 29.76 0.192 29.784 ;
    END
  END o[155]
  PIN o[156]
    DIRECTION OUTPUT ;
    USE SIGNAL ;
    PORT
      LAYER M4 ;
        RECT  0 29.952 0.192 29.976 ;
    END
  END o[156]
  PIN o[157]
    DIRECTION OUTPUT ;
    USE SIGNAL ;
    PORT
      LAYER M4 ;
        RECT  0 30.096 0.192 30.12 ;
    END
  END o[157]
  PIN o[158]
    DIRECTION OUTPUT ;
    USE SIGNAL ;
    PORT
      LAYER M4 ;
        RECT  0 30.24 0.192 30.264 ;
    END
  END o[158]
  PIN o[159]
    DIRECTION OUTPUT ;
    USE SIGNAL ;
    PORT
      LAYER M4 ;
        RECT  0 30.432 0.192 30.456 ;
    END
  END o[159]
  PIN o[15]
    DIRECTION OUTPUT ;
    USE SIGNAL ;
    PORT
      LAYER M4 ;
        RECT  0 6.864 0.192 6.888 ;
    END
  END o[15]
  PIN o[160]
    DIRECTION OUTPUT ;
    USE SIGNAL ;
    PORT
      LAYER M4 ;
        RECT  0 30.576 0.192 30.6 ;
    END
  END o[160]
  PIN o[161]
    DIRECTION OUTPUT ;
    USE SIGNAL ;
    PORT
      LAYER M4 ;
        RECT  0 30.768 0.192 30.792 ;
    END
  END o[161]
  PIN o[162]
    DIRECTION OUTPUT ;
    USE SIGNAL ;
    PORT
      LAYER M4 ;
        RECT  0 30.912 0.192 30.936 ;
    END
  END o[162]
  PIN o[163]
    DIRECTION OUTPUT ;
    USE SIGNAL ;
    PORT
      LAYER M4 ;
        RECT  0 31.056 0.192 31.08 ;
    END
  END o[163]
  PIN o[164]
    DIRECTION OUTPUT ;
    USE SIGNAL ;
    PORT
      LAYER M4 ;
        RECT  0 31.248 0.192 31.272 ;
    END
  END o[164]
  PIN o[165]
    DIRECTION OUTPUT ;
    USE SIGNAL ;
    PORT
      LAYER M4 ;
        RECT  0 31.392 0.192 31.416 ;
    END
  END o[165]
  PIN o[166]
    DIRECTION OUTPUT ;
    USE SIGNAL ;
    PORT
      LAYER M4 ;
        RECT  0 31.584 0.192 31.608 ;
    END
  END o[166]
  PIN o[167]
    DIRECTION OUTPUT ;
    USE SIGNAL ;
    PORT
      LAYER M4 ;
        RECT  0 31.728 0.192 31.752 ;
    END
  END o[167]
  PIN o[168]
    DIRECTION OUTPUT ;
    USE SIGNAL ;
    PORT
      LAYER M4 ;
        RECT  0 31.872 0.192 31.896 ;
    END
  END o[168]
  PIN o[169]
    DIRECTION OUTPUT ;
    USE SIGNAL ;
    PORT
      LAYER M4 ;
        RECT  0 32.064 0.192 32.088 ;
    END
  END o[169]
  PIN o[16]
    DIRECTION OUTPUT ;
    USE SIGNAL ;
    PORT
      LAYER M4 ;
        RECT  0 7.008 0.192 7.032 ;
    END
  END o[16]
  PIN o[170]
    DIRECTION OUTPUT ;
    USE SIGNAL ;
    PORT
      LAYER M4 ;
        RECT  0 32.208 0.192 32.232 ;
    END
  END o[170]
  PIN o[171]
    DIRECTION OUTPUT ;
    USE SIGNAL ;
    PORT
      LAYER M4 ;
        RECT  0 32.4 0.192 32.424 ;
    END
  END o[171]
  PIN o[172]
    DIRECTION OUTPUT ;
    USE SIGNAL ;
    PORT
      LAYER M4 ;
        RECT  0 32.544 0.192 32.568 ;
    END
  END o[172]
  PIN o[173]
    DIRECTION OUTPUT ;
    USE SIGNAL ;
    PORT
      LAYER M4 ;
        RECT  0 32.688 0.192 32.712 ;
    END
  END o[173]
  PIN o[174]
    DIRECTION OUTPUT ;
    USE SIGNAL ;
    PORT
      LAYER M4 ;
        RECT  0 32.88 0.192 32.904 ;
    END
  END o[174]
  PIN o[175]
    DIRECTION OUTPUT ;
    USE SIGNAL ;
    PORT
      LAYER M4 ;
        RECT  0 33.024 0.192 33.048 ;
    END
  END o[175]
  PIN o[176]
    DIRECTION OUTPUT ;
    USE SIGNAL ;
    PORT
      LAYER M4 ;
        RECT  0 33.216 0.192 33.24 ;
    END
  END o[176]
  PIN o[177]
    DIRECTION OUTPUT ;
    USE SIGNAL ;
    PORT
      LAYER M4 ;
        RECT  0 33.36 0.192 33.384 ;
    END
  END o[177]
  PIN o[178]
    DIRECTION OUTPUT ;
    USE SIGNAL ;
    PORT
      LAYER M4 ;
        RECT  0 33.552 0.192 33.576 ;
    END
  END o[178]
  PIN o[179]
    DIRECTION OUTPUT ;
    USE SIGNAL ;
    PORT
      LAYER M4 ;
        RECT  0 33.696 0.192 33.72 ;
    END
  END o[179]
  PIN o[17]
    DIRECTION OUTPUT ;
    USE SIGNAL ;
    PORT
      LAYER M4 ;
        RECT  0 7.2 0.192 7.224 ;
    END
  END o[17]
  PIN o[180]
    DIRECTION OUTPUT ;
    USE SIGNAL ;
    PORT
      LAYER M4 ;
        RECT  0 33.84 0.192 33.864 ;
    END
  END o[180]
  PIN o[181]
    DIRECTION OUTPUT ;
    USE SIGNAL ;
    PORT
      LAYER M4 ;
        RECT  0 34.032 0.192 34.056 ;
    END
  END o[181]
  PIN o[182]
    DIRECTION OUTPUT ;
    USE SIGNAL ;
    PORT
      LAYER M4 ;
        RECT  0 34.176 0.192 34.2 ;
    END
  END o[182]
  PIN o[183]
    DIRECTION OUTPUT ;
    USE SIGNAL ;
    PORT
      LAYER M4 ;
        RECT  0 34.368 0.192 34.392 ;
    END
  END o[183]
  PIN o[184]
    DIRECTION OUTPUT ;
    USE SIGNAL ;
    PORT
      LAYER M4 ;
        RECT  0 34.512 0.192 34.536 ;
    END
  END o[184]
  PIN o[185]
    DIRECTION OUTPUT ;
    USE SIGNAL ;
    PORT
      LAYER M4 ;
        RECT  0 34.656 0.192 34.68 ;
    END
  END o[185]
  PIN o[186]
    DIRECTION OUTPUT ;
    USE SIGNAL ;
    PORT
      LAYER M4 ;
        RECT  0 34.848 0.192 34.872 ;
    END
  END o[186]
  PIN o[187]
    DIRECTION OUTPUT ;
    USE SIGNAL ;
    PORT
      LAYER M4 ;
        RECT  0 34.992 0.192 35.016 ;
    END
  END o[187]
  PIN o[188]
    DIRECTION OUTPUT ;
    USE SIGNAL ;
    PORT
      LAYER M4 ;
        RECT  0 35.184 0.192 35.208 ;
    END
  END o[188]
  PIN o[189]
    DIRECTION OUTPUT ;
    USE SIGNAL ;
    PORT
      LAYER M4 ;
        RECT  0 35.328 0.192 35.352 ;
    END
  END o[189]
  PIN o[18]
    DIRECTION OUTPUT ;
    USE SIGNAL ;
    PORT
      LAYER M4 ;
        RECT  0 7.344 0.192 7.368 ;
    END
  END o[18]
  PIN o[190]
    DIRECTION OUTPUT ;
    USE SIGNAL ;
    PORT
      LAYER M4 ;
        RECT  0 35.472 0.192 35.496 ;
    END
  END o[190]
  PIN o[191]
    DIRECTION OUTPUT ;
    USE SIGNAL ;
    PORT
      LAYER M4 ;
        RECT  0 35.664 0.192 35.688 ;
    END
  END o[191]
  PIN o[192]
    DIRECTION OUTPUT ;
    USE SIGNAL ;
    PORT
      LAYER M4 ;
        RECT  0 35.808 0.192 35.832 ;
    END
  END o[192]
  PIN o[193]
    DIRECTION OUTPUT ;
    USE SIGNAL ;
    PORT
      LAYER M4 ;
        RECT  0 36 0.192 36.024 ;
    END
  END o[193]
  PIN o[194]
    DIRECTION OUTPUT ;
    USE SIGNAL ;
    PORT
      LAYER M4 ;
        RECT  0 36.144 0.192 36.168 ;
    END
  END o[194]
  PIN o[195]
    DIRECTION OUTPUT ;
    USE SIGNAL ;
    PORT
      LAYER M4 ;
        RECT  0 36.288 0.192 36.312 ;
    END
  END o[195]
  PIN o[196]
    DIRECTION OUTPUT ;
    USE SIGNAL ;
    PORT
      LAYER M4 ;
        RECT  0 36.48 0.192 36.504 ;
    END
  END o[196]
  PIN o[197]
    DIRECTION OUTPUT ;
    USE SIGNAL ;
    PORT
      LAYER M4 ;
        RECT  0 36.624 0.192 36.648 ;
    END
  END o[197]
  PIN o[198]
    DIRECTION OUTPUT ;
    USE SIGNAL ;
    PORT
      LAYER M4 ;
        RECT  0 36.816 0.192 36.84 ;
    END
  END o[198]
  PIN o[199]
    DIRECTION OUTPUT ;
    USE SIGNAL ;
    PORT
      LAYER M4 ;
        RECT  0 36.96 0.192 36.984 ;
    END
  END o[199]
  PIN o[19]
    DIRECTION OUTPUT ;
    USE SIGNAL ;
    PORT
      LAYER M4 ;
        RECT  0 7.536 0.192 7.56 ;
    END
  END o[19]
  PIN o[1]
    DIRECTION OUTPUT ;
    USE SIGNAL ;
    PORT
      LAYER M4 ;
        RECT  0 4.56 0.192 4.584 ;
    END
  END o[1]
  PIN o[200]
    DIRECTION OUTPUT ;
    USE SIGNAL ;
    PORT
      LAYER M4 ;
        RECT  0 37.152 0.192 37.176 ;
    END
  END o[200]
  PIN o[201]
    DIRECTION OUTPUT ;
    USE SIGNAL ;
    PORT
      LAYER M4 ;
        RECT  0 37.296 0.192 37.32 ;
    END
  END o[201]
  PIN o[202]
    DIRECTION OUTPUT ;
    USE SIGNAL ;
    PORT
      LAYER M4 ;
        RECT  0 37.44 0.192 37.464 ;
    END
  END o[202]
  PIN o[203]
    DIRECTION OUTPUT ;
    USE SIGNAL ;
    PORT
      LAYER M4 ;
        RECT  0 37.632 0.192 37.656 ;
    END
  END o[203]
  PIN o[204]
    DIRECTION OUTPUT ;
    USE SIGNAL ;
    PORT
      LAYER M4 ;
        RECT  0 37.776 0.192 37.8 ;
    END
  END o[204]
  PIN o[205]
    DIRECTION OUTPUT ;
    USE SIGNAL ;
    PORT
      LAYER M4 ;
        RECT  0 37.968 0.192 37.992 ;
    END
  END o[205]
  PIN o[206]
    DIRECTION OUTPUT ;
    USE SIGNAL ;
    PORT
      LAYER M4 ;
        RECT  0 38.112 0.192 38.136 ;
    END
  END o[206]
  PIN o[207]
    DIRECTION OUTPUT ;
    USE SIGNAL ;
    PORT
      LAYER M4 ;
        RECT  0 38.256 0.192 38.28 ;
    END
  END o[207]
  PIN o[208]
    DIRECTION OUTPUT ;
    USE SIGNAL ;
    PORT
      LAYER M4 ;
        RECT  0 38.448 0.192 38.472 ;
    END
  END o[208]
  PIN o[209]
    DIRECTION OUTPUT ;
    USE SIGNAL ;
    PORT
      LAYER M4 ;
        RECT  0 38.592 0.192 38.616 ;
    END
  END o[209]
  PIN o[20]
    DIRECTION OUTPUT ;
    USE SIGNAL ;
    PORT
      LAYER M4 ;
        RECT  0 7.68 0.192 7.704 ;
    END
  END o[20]
  PIN o[210]
    DIRECTION OUTPUT ;
    USE SIGNAL ;
    PORT
      LAYER M4 ;
        RECT  0 38.784 0.192 38.808 ;
    END
  END o[210]
  PIN o[211]
    DIRECTION OUTPUT ;
    USE SIGNAL ;
    PORT
      LAYER M4 ;
        RECT  0 38.928 0.192 38.952 ;
    END
  END o[211]
  PIN o[212]
    DIRECTION OUTPUT ;
    USE SIGNAL ;
    PORT
      LAYER M4 ;
        RECT  0 39.072 0.192 39.096 ;
    END
  END o[212]
  PIN o[213]
    DIRECTION OUTPUT ;
    USE SIGNAL ;
    PORT
      LAYER M4 ;
        RECT  0 39.264 0.192 39.288 ;
    END
  END o[213]
  PIN o[214]
    DIRECTION OUTPUT ;
    USE SIGNAL ;
    PORT
      LAYER M4 ;
        RECT  0 39.408 0.192 39.432 ;
    END
  END o[214]
  PIN o[215]
    DIRECTION OUTPUT ;
    USE SIGNAL ;
    PORT
      LAYER M4 ;
        RECT  0 39.6 0.192 39.624 ;
    END
  END o[215]
  PIN o[216]
    DIRECTION OUTPUT ;
    USE SIGNAL ;
    PORT
      LAYER M4 ;
        RECT  0 39.744 0.192 39.768 ;
    END
  END o[216]
  PIN o[217]
    DIRECTION OUTPUT ;
    USE SIGNAL ;
    PORT
      LAYER M4 ;
        RECT  0 39.888 0.192 39.912 ;
    END
  END o[217]
  PIN o[218]
    DIRECTION OUTPUT ;
    USE SIGNAL ;
    PORT
      LAYER M4 ;
        RECT  0 40.08 0.192 40.104 ;
    END
  END o[218]
  PIN o[219]
    DIRECTION OUTPUT ;
    USE SIGNAL ;
    PORT
      LAYER M4 ;
        RECT  0 40.224 0.192 40.248 ;
    END
  END o[219]
  PIN o[21]
    DIRECTION OUTPUT ;
    USE SIGNAL ;
    PORT
      LAYER M4 ;
        RECT  0 7.872 0.192 7.896 ;
    END
  END o[21]
  PIN o[220]
    DIRECTION OUTPUT ;
    USE SIGNAL ;
    PORT
      LAYER M4 ;
        RECT  0 40.416 0.192 40.44 ;
    END
  END o[220]
  PIN o[221]
    DIRECTION OUTPUT ;
    USE SIGNAL ;
    PORT
      LAYER M4 ;
        RECT  0 40.56 0.192 40.584 ;
    END
  END o[221]
  PIN o[222]
    DIRECTION OUTPUT ;
    USE SIGNAL ;
    PORT
      LAYER M4 ;
        RECT  0 40.704 0.192 40.728 ;
    END
  END o[222]
  PIN o[223]
    DIRECTION OUTPUT ;
    USE SIGNAL ;
    PORT
      LAYER M4 ;
        RECT  0 40.896 0.192 40.92 ;
    END
  END o[223]
  PIN o[224]
    DIRECTION OUTPUT ;
    USE SIGNAL ;
    PORT
      LAYER M4 ;
        RECT  0 41.04 0.192 41.064 ;
    END
  END o[224]
  PIN o[225]
    DIRECTION OUTPUT ;
    USE SIGNAL ;
    PORT
      LAYER M4 ;
        RECT  0 41.232 0.192 41.256 ;
    END
  END o[225]
  PIN o[226]
    DIRECTION OUTPUT ;
    USE SIGNAL ;
    PORT
      LAYER M4 ;
        RECT  0 41.376 0.192 41.4 ;
    END
  END o[226]
  PIN o[227]
    DIRECTION OUTPUT ;
    USE SIGNAL ;
    PORT
      LAYER M4 ;
        RECT  0 41.568 0.192 41.592 ;
    END
  END o[227]
  PIN o[228]
    DIRECTION OUTPUT ;
    USE SIGNAL ;
    PORT
      LAYER M4 ;
        RECT  0 41.712 0.192 41.736 ;
    END
  END o[228]
  PIN o[229]
    DIRECTION OUTPUT ;
    USE SIGNAL ;
    PORT
      LAYER M4 ;
        RECT  0 41.856 0.192 41.88 ;
    END
  END o[229]
  PIN o[22]
    DIRECTION OUTPUT ;
    USE SIGNAL ;
    PORT
      LAYER M4 ;
        RECT  0 8.016 0.192 8.04 ;
    END
  END o[22]
  PIN o[230]
    DIRECTION OUTPUT ;
    USE SIGNAL ;
    PORT
      LAYER M4 ;
        RECT  0 42.048 0.192 42.072 ;
    END
  END o[230]
  PIN o[231]
    DIRECTION OUTPUT ;
    USE SIGNAL ;
    PORT
      LAYER M4 ;
        RECT  0 42.192 0.192 42.216 ;
    END
  END o[231]
  PIN o[232]
    DIRECTION OUTPUT ;
    USE SIGNAL ;
    PORT
      LAYER M4 ;
        RECT  0 42.384 0.192 42.408 ;
    END
  END o[232]
  PIN o[233]
    DIRECTION OUTPUT ;
    USE SIGNAL ;
    PORT
      LAYER M4 ;
        RECT  0 42.528 0.192 42.552 ;
    END
  END o[233]
  PIN o[234]
    DIRECTION OUTPUT ;
    USE SIGNAL ;
    PORT
      LAYER M4 ;
        RECT  0 42.672 0.192 42.696 ;
    END
  END o[234]
  PIN o[235]
    DIRECTION OUTPUT ;
    USE SIGNAL ;
    PORT
      LAYER M4 ;
        RECT  0 42.864 0.192 42.888 ;
    END
  END o[235]
  PIN o[236]
    DIRECTION OUTPUT ;
    USE SIGNAL ;
    PORT
      LAYER M4 ;
        RECT  0 43.008 0.192 43.032 ;
    END
  END o[236]
  PIN o[237]
    DIRECTION OUTPUT ;
    USE SIGNAL ;
    PORT
      LAYER M4 ;
        RECT  0 43.2 0.192 43.224 ;
    END
  END o[237]
  PIN o[238]
    DIRECTION OUTPUT ;
    USE SIGNAL ;
    PORT
      LAYER M4 ;
        RECT  0 43.344 0.192 43.368 ;
    END
  END o[238]
  PIN o[239]
    DIRECTION OUTPUT ;
    USE SIGNAL ;
    PORT
      LAYER M4 ;
        RECT  0 43.488 0.192 43.512 ;
    END
  END o[239]
  PIN o[23]
    DIRECTION OUTPUT ;
    USE SIGNAL ;
    PORT
      LAYER M4 ;
        RECT  0 8.16 0.192 8.184 ;
    END
  END o[23]
  PIN o[240]
    DIRECTION OUTPUT ;
    USE SIGNAL ;
    PORT
      LAYER M4 ;
        RECT  0 43.68 0.192 43.704 ;
    END
  END o[240]
  PIN o[241]
    DIRECTION OUTPUT ;
    USE SIGNAL ;
    PORT
      LAYER M4 ;
        RECT  0 43.824 0.192 43.848 ;
    END
  END o[241]
  PIN o[242]
    DIRECTION OUTPUT ;
    USE SIGNAL ;
    PORT
      LAYER M4 ;
        RECT  0 44.016 0.192 44.04 ;
    END
  END o[242]
  PIN o[243]
    DIRECTION OUTPUT ;
    USE SIGNAL ;
    PORT
      LAYER M4 ;
        RECT  0 44.16 0.192 44.184 ;
    END
  END o[243]
  PIN o[244]
    DIRECTION OUTPUT ;
    USE SIGNAL ;
    PORT
      LAYER M4 ;
        RECT  0 44.304 0.192 44.328 ;
    END
  END o[244]
  PIN o[245]
    DIRECTION OUTPUT ;
    USE SIGNAL ;
    PORT
      LAYER M4 ;
        RECT  0 44.496 0.192 44.52 ;
    END
  END o[245]
  PIN o[246]
    DIRECTION OUTPUT ;
    USE SIGNAL ;
    PORT
      LAYER M4 ;
        RECT  0 44.64 0.192 44.664 ;
    END
  END o[246]
  PIN o[247]
    DIRECTION OUTPUT ;
    USE SIGNAL ;
    PORT
      LAYER M4 ;
        RECT  0 44.832 0.192 44.856 ;
    END
  END o[247]
  PIN o[248]
    DIRECTION OUTPUT ;
    USE SIGNAL ;
    PORT
      LAYER M4 ;
        RECT  0 44.976 0.192 45 ;
    END
  END o[248]
  PIN o[249]
    DIRECTION OUTPUT ;
    USE SIGNAL ;
    PORT
      LAYER M4 ;
        RECT  0 45.12 0.192 45.144 ;
    END
  END o[249]
  PIN o[24]
    DIRECTION OUTPUT ;
    USE SIGNAL ;
    PORT
      LAYER M4 ;
        RECT  0 8.352 0.192 8.376 ;
    END
  END o[24]
  PIN o[250]
    DIRECTION OUTPUT ;
    USE SIGNAL ;
    PORT
      LAYER M4 ;
        RECT  0 45.312 0.192 45.336 ;
    END
  END o[250]
  PIN o[251]
    DIRECTION OUTPUT ;
    USE SIGNAL ;
    PORT
      LAYER M4 ;
        RECT  0 45.456 0.192 45.48 ;
    END
  END o[251]
  PIN o[252]
    DIRECTION OUTPUT ;
    USE SIGNAL ;
    PORT
      LAYER M4 ;
        RECT  0 45.648 0.192 45.672 ;
    END
  END o[252]
  PIN o[253]
    DIRECTION OUTPUT ;
    USE SIGNAL ;
    PORT
      LAYER M4 ;
        RECT  0 45.792 0.192 45.816 ;
    END
  END o[253]
  PIN o[254]
    DIRECTION OUTPUT ;
    USE SIGNAL ;
    PORT
      LAYER M4 ;
        RECT  0 45.984 0.192 46.008 ;
    END
  END o[254]
  PIN o[255]
    DIRECTION OUTPUT ;
    USE SIGNAL ;
    PORT
      LAYER M4 ;
        RECT  0 46.128 0.192 46.152 ;
    END
  END o[255]
  PIN o[256]
    DIRECTION OUTPUT ;
    USE SIGNAL ;
    PORT
      LAYER M4 ;
        RECT  0 46.272 0.192 46.296 ;
    END
  END o[256]
  PIN o[257]
    DIRECTION OUTPUT ;
    USE SIGNAL ;
    PORT
      LAYER M4 ;
        RECT  0 46.464 0.192 46.488 ;
    END
  END o[257]
  PIN o[258]
    DIRECTION OUTPUT ;
    USE SIGNAL ;
    PORT
      LAYER M4 ;
        RECT  0 46.608 0.192 46.632 ;
    END
  END o[258]
  PIN o[259]
    DIRECTION OUTPUT ;
    USE SIGNAL ;
    PORT
      LAYER M4 ;
        RECT  0 46.8 0.192 46.824 ;
    END
  END o[259]
  PIN o[25]
    DIRECTION OUTPUT ;
    USE SIGNAL ;
    PORT
      LAYER M4 ;
        RECT  0 8.496 0.192 8.52 ;
    END
  END o[25]
  PIN o[260]
    DIRECTION OUTPUT ;
    USE SIGNAL ;
    PORT
      LAYER M4 ;
        RECT  0 46.944 0.192 46.968 ;
    END
  END o[260]
  PIN o[261]
    DIRECTION OUTPUT ;
    USE SIGNAL ;
    PORT
      LAYER M4 ;
        RECT  0 47.088 0.192 47.112 ;
    END
  END o[261]
  PIN o[262]
    DIRECTION OUTPUT ;
    USE SIGNAL ;
    PORT
      LAYER M4 ;
        RECT  0 47.28 0.192 47.304 ;
    END
  END o[262]
  PIN o[263]
    DIRECTION OUTPUT ;
    USE SIGNAL ;
    PORT
      LAYER M4 ;
        RECT  0 47.424 0.192 47.448 ;
    END
  END o[263]
  PIN o[264]
    DIRECTION OUTPUT ;
    USE SIGNAL ;
    PORT
      LAYER M4 ;
        RECT  0 47.616 0.192 47.64 ;
    END
  END o[264]
  PIN o[265]
    DIRECTION OUTPUT ;
    USE SIGNAL ;
    PORT
      LAYER M4 ;
        RECT  0 47.76 0.192 47.784 ;
    END
  END o[265]
  PIN o[266]
    DIRECTION OUTPUT ;
    USE SIGNAL ;
    PORT
      LAYER M4 ;
        RECT  0 47.904 0.192 47.928 ;
    END
  END o[266]
  PIN o[267]
    DIRECTION OUTPUT ;
    USE SIGNAL ;
    PORT
      LAYER M4 ;
        RECT  0 48.096 0.192 48.12 ;
    END
  END o[267]
  PIN o[268]
    DIRECTION OUTPUT ;
    USE SIGNAL ;
    PORT
      LAYER M4 ;
        RECT  0 48.24 0.192 48.264 ;
    END
  END o[268]
  PIN o[269]
    DIRECTION OUTPUT ;
    USE SIGNAL ;
    PORT
      LAYER M4 ;
        RECT  0 48.432 0.192 48.456 ;
    END
  END o[269]
  PIN o[26]
    DIRECTION OUTPUT ;
    USE SIGNAL ;
    PORT
      LAYER M4 ;
        RECT  0 8.688 0.192 8.712 ;
    END
  END o[26]
  PIN o[270]
    DIRECTION OUTPUT ;
    USE SIGNAL ;
    PORT
      LAYER M4 ;
        RECT  0 48.576 0.192 48.6 ;
    END
  END o[270]
  PIN o[271]
    DIRECTION OUTPUT ;
    USE SIGNAL ;
    PORT
      LAYER M4 ;
        RECT  0 48.72 0.192 48.744 ;
    END
  END o[271]
  PIN o[272]
    DIRECTION OUTPUT ;
    USE SIGNAL ;
    PORT
      LAYER M4 ;
        RECT  0 48.912 0.192 48.936 ;
    END
  END o[272]
  PIN o[273]
    DIRECTION OUTPUT ;
    USE SIGNAL ;
    PORT
      LAYER M4 ;
        RECT  0 49.056 0.192 49.08 ;
    END
  END o[273]
  PIN o[274]
    DIRECTION OUTPUT ;
    USE SIGNAL ;
    PORT
      LAYER M4 ;
        RECT  0 49.248 0.192 49.272 ;
    END
  END o[274]
  PIN o[275]
    DIRECTION OUTPUT ;
    USE SIGNAL ;
    PORT
      LAYER M4 ;
        RECT  0 49.392 0.192 49.416 ;
    END
  END o[275]
  PIN o[276]
    DIRECTION OUTPUT ;
    USE SIGNAL ;
    PORT
      LAYER M4 ;
        RECT  0 49.536 0.192 49.56 ;
    END
  END o[276]
  PIN o[277]
    DIRECTION OUTPUT ;
    USE SIGNAL ;
    PORT
      LAYER M4 ;
        RECT  0 49.728 0.192 49.752 ;
    END
  END o[277]
  PIN o[278]
    DIRECTION OUTPUT ;
    USE SIGNAL ;
    PORT
      LAYER M4 ;
        RECT  0 49.872 0.192 49.896 ;
    END
  END o[278]
  PIN o[279]
    DIRECTION OUTPUT ;
    USE SIGNAL ;
    PORT
      LAYER M4 ;
        RECT  0 50.064 0.192 50.088 ;
    END
  END o[279]
  PIN o[27]
    DIRECTION OUTPUT ;
    USE SIGNAL ;
    PORT
      LAYER M4 ;
        RECT  0 8.832 0.192 8.856 ;
    END
  END o[27]
  PIN o[280]
    DIRECTION OUTPUT ;
    USE SIGNAL ;
    PORT
      LAYER M4 ;
        RECT  0 50.208 0.192 50.232 ;
    END
  END o[280]
  PIN o[281]
    DIRECTION OUTPUT ;
    USE SIGNAL ;
    PORT
      LAYER M4 ;
        RECT  0 50.4 0.192 50.424 ;
    END
  END o[281]
  PIN o[282]
    DIRECTION OUTPUT ;
    USE SIGNAL ;
    PORT
      LAYER M4 ;
        RECT  0 50.544 0.192 50.568 ;
    END
  END o[282]
  PIN o[283]
    DIRECTION OUTPUT ;
    USE SIGNAL ;
    PORT
      LAYER M4 ;
        RECT  0 50.688 0.192 50.712 ;
    END
  END o[283]
  PIN o[284]
    DIRECTION OUTPUT ;
    USE SIGNAL ;
    PORT
      LAYER M4 ;
        RECT  0 50.88 0.192 50.904 ;
    END
  END o[284]
  PIN o[285]
    DIRECTION OUTPUT ;
    USE SIGNAL ;
    PORT
      LAYER M4 ;
        RECT  0 51.024 0.192 51.048 ;
    END
  END o[285]
  PIN o[286]
    DIRECTION OUTPUT ;
    USE SIGNAL ;
    PORT
      LAYER M4 ;
        RECT  0 51.216 0.192 51.24 ;
    END
  END o[286]
  PIN o[287]
    DIRECTION OUTPUT ;
    USE SIGNAL ;
    PORT
      LAYER M4 ;
        RECT  0 51.36 0.192 51.384 ;
    END
  END o[287]
  PIN o[288]
    DIRECTION OUTPUT ;
    USE SIGNAL ;
    PORT
      LAYER M4 ;
        RECT  0 51.504 0.192 51.528 ;
    END
  END o[288]
  PIN o[289]
    DIRECTION OUTPUT ;
    USE SIGNAL ;
    PORT
      LAYER M4 ;
        RECT  0 51.696 0.192 51.72 ;
    END
  END o[289]
  PIN o[28]
    DIRECTION OUTPUT ;
    USE SIGNAL ;
    PORT
      LAYER M4 ;
        RECT  0 8.976 0.192 9 ;
    END
  END o[28]
  PIN o[290]
    DIRECTION OUTPUT ;
    USE SIGNAL ;
    PORT
      LAYER M4 ;
        RECT  0 51.84 0.192 51.864 ;
    END
  END o[290]
  PIN o[291]
    DIRECTION OUTPUT ;
    USE SIGNAL ;
    PORT
      LAYER M4 ;
        RECT  0 52.032 0.192 52.056 ;
    END
  END o[291]
  PIN o[292]
    DIRECTION OUTPUT ;
    USE SIGNAL ;
    PORT
      LAYER M4 ;
        RECT  0 52.176 0.192 52.2 ;
    END
  END o[292]
  PIN o[293]
    DIRECTION OUTPUT ;
    USE SIGNAL ;
    PORT
      LAYER M4 ;
        RECT  0 52.32 0.192 52.344 ;
    END
  END o[293]
  PIN o[294]
    DIRECTION OUTPUT ;
    USE SIGNAL ;
    PORT
      LAYER M4 ;
        RECT  0 52.512 0.192 52.536 ;
    END
  END o[294]
  PIN o[295]
    DIRECTION OUTPUT ;
    USE SIGNAL ;
    PORT
      LAYER M4 ;
        RECT  0 52.656 0.192 52.68 ;
    END
  END o[295]
  PIN o[296]
    DIRECTION OUTPUT ;
    USE SIGNAL ;
    PORT
      LAYER M4 ;
        RECT  0 52.848 0.192 52.872 ;
    END
  END o[296]
  PIN o[297]
    DIRECTION OUTPUT ;
    USE SIGNAL ;
    PORT
      LAYER M4 ;
        RECT  0 52.992 0.192 53.016 ;
    END
  END o[297]
  PIN o[298]
    DIRECTION OUTPUT ;
    USE SIGNAL ;
    PORT
      LAYER M4 ;
        RECT  0 53.136 0.192 53.16 ;
    END
  END o[298]
  PIN o[299]
    DIRECTION OUTPUT ;
    USE SIGNAL ;
    PORT
      LAYER M4 ;
        RECT  0 53.328 0.192 53.352 ;
    END
  END o[299]
  PIN o[29]
    DIRECTION OUTPUT ;
    USE SIGNAL ;
    PORT
      LAYER M4 ;
        RECT  0 9.168 0.192 9.192 ;
    END
  END o[29]
  PIN o[2]
    DIRECTION OUTPUT ;
    USE SIGNAL ;
    PORT
      LAYER M4 ;
        RECT  0 4.752 0.192 4.776 ;
    END
  END o[2]
  PIN o[300]
    DIRECTION OUTPUT ;
    USE SIGNAL ;
    PORT
      LAYER M4 ;
        RECT  0 53.472 0.192 53.496 ;
    END
  END o[300]
  PIN o[301]
    DIRECTION OUTPUT ;
    USE SIGNAL ;
    PORT
      LAYER M4 ;
        RECT  0 53.664 0.192 53.688 ;
    END
  END o[301]
  PIN o[302]
    DIRECTION OUTPUT ;
    USE SIGNAL ;
    PORT
      LAYER M4 ;
        RECT  0 53.808 0.192 53.832 ;
    END
  END o[302]
  PIN o[303]
    DIRECTION OUTPUT ;
    USE SIGNAL ;
    PORT
      LAYER M4 ;
        RECT  0 54 0.192 54.024 ;
    END
  END o[303]
  PIN o[304]
    DIRECTION OUTPUT ;
    USE SIGNAL ;
    PORT
      LAYER M4 ;
        RECT  0 54.144 0.192 54.168 ;
    END
  END o[304]
  PIN o[305]
    DIRECTION OUTPUT ;
    USE SIGNAL ;
    PORT
      LAYER M4 ;
        RECT  0 54.288 0.192 54.312 ;
    END
  END o[305]
  PIN o[306]
    DIRECTION OUTPUT ;
    USE SIGNAL ;
    PORT
      LAYER M4 ;
        RECT  0 54.48 0.192 54.504 ;
    END
  END o[306]
  PIN o[307]
    DIRECTION OUTPUT ;
    USE SIGNAL ;
    PORT
      LAYER M4 ;
        RECT  0 54.624 0.192 54.648 ;
    END
  END o[307]
  PIN o[308]
    DIRECTION OUTPUT ;
    USE SIGNAL ;
    PORT
      LAYER M4 ;
        RECT  0 54.816 0.192 54.84 ;
    END
  END o[308]
  PIN o[309]
    DIRECTION OUTPUT ;
    USE SIGNAL ;
    PORT
      LAYER M4 ;
        RECT  0 54.96 0.192 54.984 ;
    END
  END o[309]
  PIN o[30]
    DIRECTION OUTPUT ;
    USE SIGNAL ;
    PORT
      LAYER M4 ;
        RECT  0 9.312 0.192 9.336 ;
    END
  END o[30]
  PIN o[310]
    DIRECTION OUTPUT ;
    USE SIGNAL ;
    PORT
      LAYER M4 ;
        RECT  0 55.104 0.192 55.128 ;
    END
  END o[310]
  PIN o[311]
    DIRECTION OUTPUT ;
    USE SIGNAL ;
    PORT
      LAYER M4 ;
        RECT  0 55.296 0.192 55.32 ;
    END
  END o[311]
  PIN o[312]
    DIRECTION OUTPUT ;
    USE SIGNAL ;
    PORT
      LAYER M4 ;
        RECT  0 55.44 0.192 55.464 ;
    END
  END o[312]
  PIN o[313]
    DIRECTION OUTPUT ;
    USE SIGNAL ;
    PORT
      LAYER M4 ;
        RECT  0 55.632 0.192 55.656 ;
    END
  END o[313]
  PIN o[314]
    DIRECTION OUTPUT ;
    USE SIGNAL ;
    PORT
      LAYER M4 ;
        RECT  0 55.776 0.192 55.8 ;
    END
  END o[314]
  PIN o[315]
    DIRECTION OUTPUT ;
    USE SIGNAL ;
    PORT
      LAYER M4 ;
        RECT  0 55.92 0.192 55.944 ;
    END
  END o[315]
  PIN o[316]
    DIRECTION OUTPUT ;
    USE SIGNAL ;
    PORT
      LAYER M4 ;
        RECT  0 56.112 0.192 56.136 ;
    END
  END o[316]
  PIN o[317]
    DIRECTION OUTPUT ;
    USE SIGNAL ;
    PORT
      LAYER M4 ;
        RECT  0 56.256 0.192 56.28 ;
    END
  END o[317]
  PIN o[318]
    DIRECTION OUTPUT ;
    USE SIGNAL ;
    PORT
      LAYER M4 ;
        RECT  0 56.448 0.192 56.472 ;
    END
  END o[318]
  PIN o[319]
    DIRECTION OUTPUT ;
    USE SIGNAL ;
    PORT
      LAYER M4 ;
        RECT  0 56.592 0.192 56.616 ;
    END
  END o[319]
  PIN o[31]
    DIRECTION OUTPUT ;
    USE SIGNAL ;
    PORT
      LAYER M4 ;
        RECT  0 9.504 0.192 9.528 ;
    END
  END o[31]
  PIN o[320]
    DIRECTION OUTPUT ;
    USE SIGNAL ;
    PORT
      LAYER M4 ;
        RECT  0 56.736 0.192 56.76 ;
    END
  END o[320]
  PIN o[321]
    DIRECTION OUTPUT ;
    USE SIGNAL ;
    PORT
      LAYER M4 ;
        RECT  0 56.928 0.192 56.952 ;
    END
  END o[321]
  PIN o[322]
    DIRECTION OUTPUT ;
    USE SIGNAL ;
    PORT
      LAYER M4 ;
        RECT  0 57.072 0.192 57.096 ;
    END
  END o[322]
  PIN o[323]
    DIRECTION OUTPUT ;
    USE SIGNAL ;
    PORT
      LAYER M4 ;
        RECT  0 57.264 0.192 57.288 ;
    END
  END o[323]
  PIN o[324]
    DIRECTION OUTPUT ;
    USE SIGNAL ;
    PORT
      LAYER M4 ;
        RECT  0 57.408 0.192 57.432 ;
    END
  END o[324]
  PIN o[325]
    DIRECTION OUTPUT ;
    USE SIGNAL ;
    PORT
      LAYER M4 ;
        RECT  0 57.552 0.192 57.576 ;
    END
  END o[325]
  PIN o[326]
    DIRECTION OUTPUT ;
    USE SIGNAL ;
    PORT
      LAYER M4 ;
        RECT  0 57.744 0.192 57.768 ;
    END
  END o[326]
  PIN o[327]
    DIRECTION OUTPUT ;
    USE SIGNAL ;
    PORT
      LAYER M4 ;
        RECT  0 57.888 0.192 57.912 ;
    END
  END o[327]
  PIN o[328]
    DIRECTION OUTPUT ;
    USE SIGNAL ;
    PORT
      LAYER M4 ;
        RECT  0 58.08 0.192 58.104 ;
    END
  END o[328]
  PIN o[329]
    DIRECTION OUTPUT ;
    USE SIGNAL ;
    PORT
      LAYER M4 ;
        RECT  0 58.224 0.192 58.248 ;
    END
  END o[329]
  PIN o[32]
    DIRECTION OUTPUT ;
    USE SIGNAL ;
    PORT
      LAYER M4 ;
        RECT  0 9.648 0.192 9.672 ;
    END
  END o[32]
  PIN o[330]
    DIRECTION OUTPUT ;
    USE SIGNAL ;
    PORT
      LAYER M4 ;
        RECT  0 58.416 0.192 58.44 ;
    END
  END o[330]
  PIN o[331]
    DIRECTION OUTPUT ;
    USE SIGNAL ;
    PORT
      LAYER M4 ;
        RECT  0 58.56 0.192 58.584 ;
    END
  END o[331]
  PIN o[332]
    DIRECTION OUTPUT ;
    USE SIGNAL ;
    PORT
      LAYER M4 ;
        RECT  0 58.704 0.192 58.728 ;
    END
  END o[332]
  PIN o[333]
    DIRECTION OUTPUT ;
    USE SIGNAL ;
    PORT
      LAYER M4 ;
        RECT  0 58.896 0.192 58.92 ;
    END
  END o[333]
  PIN o[334]
    DIRECTION OUTPUT ;
    USE SIGNAL ;
    PORT
      LAYER M4 ;
        RECT  0 59.04 0.192 59.064 ;
    END
  END o[334]
  PIN o[335]
    DIRECTION OUTPUT ;
    USE SIGNAL ;
    PORT
      LAYER M4 ;
        RECT  0 59.232 0.192 59.256 ;
    END
  END o[335]
  PIN o[336]
    DIRECTION OUTPUT ;
    USE SIGNAL ;
    PORT
      LAYER M4 ;
        RECT  0 59.376 0.192 59.4 ;
    END
  END o[336]
  PIN o[337]
    DIRECTION OUTPUT ;
    USE SIGNAL ;
    PORT
      LAYER M4 ;
        RECT  0 59.52 0.192 59.544 ;
    END
  END o[337]
  PIN o[338]
    DIRECTION OUTPUT ;
    USE SIGNAL ;
    PORT
      LAYER M4 ;
        RECT  0 59.712 0.192 59.736 ;
    END
  END o[338]
  PIN o[339]
    DIRECTION OUTPUT ;
    USE SIGNAL ;
    PORT
      LAYER M4 ;
        RECT  0 59.856 0.192 59.88 ;
    END
  END o[339]
  PIN o[33]
    DIRECTION OUTPUT ;
    USE SIGNAL ;
    PORT
      LAYER M4 ;
        RECT  0 9.792 0.192 9.816 ;
    END
  END o[33]
  PIN o[340]
    DIRECTION OUTPUT ;
    USE SIGNAL ;
    PORT
      LAYER M4 ;
        RECT  0 60.048 0.192 60.072 ;
    END
  END o[340]
  PIN o[341]
    DIRECTION OUTPUT ;
    USE SIGNAL ;
    PORT
      LAYER M4 ;
        RECT  0 60.192 0.192 60.216 ;
    END
  END o[341]
  PIN o[342]
    DIRECTION OUTPUT ;
    USE SIGNAL ;
    PORT
      LAYER M4 ;
        RECT  0 60.336 0.192 60.36 ;
    END
  END o[342]
  PIN o[343]
    DIRECTION OUTPUT ;
    USE SIGNAL ;
    PORT
      LAYER M4 ;
        RECT  0 60.528 0.192 60.552 ;
    END
  END o[343]
  PIN o[344]
    DIRECTION OUTPUT ;
    USE SIGNAL ;
    PORT
      LAYER M4 ;
        RECT  0 60.672 0.192 60.696 ;
    END
  END o[344]
  PIN o[345]
    DIRECTION OUTPUT ;
    USE SIGNAL ;
    PORT
      LAYER M4 ;
        RECT  0 60.864 0.192 60.888 ;
    END
  END o[345]
  PIN o[346]
    DIRECTION OUTPUT ;
    USE SIGNAL ;
    PORT
      LAYER M4 ;
        RECT  0 61.008 0.192 61.032 ;
    END
  END o[346]
  PIN o[347]
    DIRECTION OUTPUT ;
    USE SIGNAL ;
    PORT
      LAYER M4 ;
        RECT  0 61.152 0.192 61.176 ;
    END
  END o[347]
  PIN o[348]
    DIRECTION OUTPUT ;
    USE SIGNAL ;
    PORT
      LAYER M4 ;
        RECT  0 61.344 0.192 61.368 ;
    END
  END o[348]
  PIN o[349]
    DIRECTION OUTPUT ;
    USE SIGNAL ;
    PORT
      LAYER M4 ;
        RECT  0 61.488 0.192 61.512 ;
    END
  END o[349]
  PIN o[34]
    DIRECTION OUTPUT ;
    USE SIGNAL ;
    PORT
      LAYER M4 ;
        RECT  0 9.984 0.192 10.008 ;
    END
  END o[34]
  PIN o[350]
    DIRECTION OUTPUT ;
    USE SIGNAL ;
    PORT
      LAYER M4 ;
        RECT  0 61.68 0.192 61.704 ;
    END
  END o[350]
  PIN o[351]
    DIRECTION OUTPUT ;
    USE SIGNAL ;
    PORT
      LAYER M4 ;
        RECT  0 61.824 0.192 61.848 ;
    END
  END o[351]
  PIN o[352]
    DIRECTION OUTPUT ;
    USE SIGNAL ;
    PORT
      LAYER M4 ;
        RECT  0 61.968 0.192 61.992 ;
    END
  END o[352]
  PIN o[353]
    DIRECTION OUTPUT ;
    USE SIGNAL ;
    PORT
      LAYER M4 ;
        RECT  0 62.16 0.192 62.184 ;
    END
  END o[353]
  PIN o[354]
    DIRECTION OUTPUT ;
    USE SIGNAL ;
    PORT
      LAYER M4 ;
        RECT  0 62.304 0.192 62.328 ;
    END
  END o[354]
  PIN o[355]
    DIRECTION OUTPUT ;
    USE SIGNAL ;
    PORT
      LAYER M4 ;
        RECT  0 62.496 0.192 62.52 ;
    END
  END o[355]
  PIN o[356]
    DIRECTION OUTPUT ;
    USE SIGNAL ;
    PORT
      LAYER M4 ;
        RECT  0 62.64 0.192 62.664 ;
    END
  END o[356]
  PIN o[357]
    DIRECTION OUTPUT ;
    USE SIGNAL ;
    PORT
      LAYER M4 ;
        RECT  0 62.832 0.192 62.856 ;
    END
  END o[357]
  PIN o[358]
    DIRECTION OUTPUT ;
    USE SIGNAL ;
    PORT
      LAYER M4 ;
        RECT  0 62.976 0.192 63 ;
    END
  END o[358]
  PIN o[359]
    DIRECTION OUTPUT ;
    USE SIGNAL ;
    PORT
      LAYER M4 ;
        RECT  0 63.12 0.192 63.144 ;
    END
  END o[359]
  PIN o[35]
    DIRECTION OUTPUT ;
    USE SIGNAL ;
    PORT
      LAYER M4 ;
        RECT  0 10.128 0.192 10.152 ;
    END
  END o[35]
  PIN o[360]
    DIRECTION OUTPUT ;
    USE SIGNAL ;
    PORT
      LAYER M4 ;
        RECT  0 63.312 0.192 63.336 ;
    END
  END o[360]
  PIN o[361]
    DIRECTION OUTPUT ;
    USE SIGNAL ;
    PORT
      LAYER M4 ;
        RECT  0 63.456 0.192 63.48 ;
    END
  END o[361]
  PIN o[362]
    DIRECTION OUTPUT ;
    USE SIGNAL ;
    PORT
      LAYER M4 ;
        RECT  0 63.648 0.192 63.672 ;
    END
  END o[362]
  PIN o[363]
    DIRECTION OUTPUT ;
    USE SIGNAL ;
    PORT
      LAYER M4 ;
        RECT  0 63.792 0.192 63.816 ;
    END
  END o[363]
  PIN o[364]
    DIRECTION OUTPUT ;
    USE SIGNAL ;
    PORT
      LAYER M4 ;
        RECT  0 63.936 0.192 63.96 ;
    END
  END o[364]
  PIN o[365]
    DIRECTION OUTPUT ;
    USE SIGNAL ;
    PORT
      LAYER M4 ;
        RECT  0 64.128 0.192 64.152 ;
    END
  END o[365]
  PIN o[366]
    DIRECTION OUTPUT ;
    USE SIGNAL ;
    PORT
      LAYER M4 ;
        RECT  0 64.272 0.192 64.296 ;
    END
  END o[366]
  PIN o[367]
    DIRECTION OUTPUT ;
    USE SIGNAL ;
    PORT
      LAYER M4 ;
        RECT  0 64.464 0.192 64.488 ;
    END
  END o[367]
  PIN o[368]
    DIRECTION OUTPUT ;
    USE SIGNAL ;
    PORT
      LAYER M4 ;
        RECT  0 64.608 0.192 64.632 ;
    END
  END o[368]
  PIN o[369]
    DIRECTION OUTPUT ;
    USE SIGNAL ;
    PORT
      LAYER M4 ;
        RECT  0 64.752 0.192 64.776 ;
    END
  END o[369]
  PIN o[36]
    DIRECTION OUTPUT ;
    USE SIGNAL ;
    PORT
      LAYER M4 ;
        RECT  0 10.32 0.192 10.344 ;
    END
  END o[36]
  PIN o[370]
    DIRECTION OUTPUT ;
    USE SIGNAL ;
    PORT
      LAYER M4 ;
        RECT  0 64.944 0.192 64.968 ;
    END
  END o[370]
  PIN o[371]
    DIRECTION OUTPUT ;
    USE SIGNAL ;
    PORT
      LAYER M4 ;
        RECT  0 65.088 0.192 65.112 ;
    END
  END o[371]
  PIN o[372]
    DIRECTION OUTPUT ;
    USE SIGNAL ;
    PORT
      LAYER M4 ;
        RECT  0 65.28 0.192 65.304 ;
    END
  END o[372]
  PIN o[373]
    DIRECTION OUTPUT ;
    USE SIGNAL ;
    PORT
      LAYER M4 ;
        RECT  0 65.424 0.192 65.448 ;
    END
  END o[373]
  PIN o[374]
    DIRECTION OUTPUT ;
    USE SIGNAL ;
    PORT
      LAYER M4 ;
        RECT  0 65.568 0.192 65.592 ;
    END
  END o[374]
  PIN o[375]
    DIRECTION OUTPUT ;
    USE SIGNAL ;
    PORT
      LAYER M4 ;
        RECT  0 65.76 0.192 65.784 ;
    END
  END o[375]
  PIN o[376]
    DIRECTION OUTPUT ;
    USE SIGNAL ;
    PORT
      LAYER M4 ;
        RECT  0 65.904 0.192 65.928 ;
    END
  END o[376]
  PIN o[377]
    DIRECTION OUTPUT ;
    USE SIGNAL ;
    PORT
      LAYER M4 ;
        RECT  0 66.096 0.192 66.12 ;
    END
  END o[377]
  PIN o[378]
    DIRECTION OUTPUT ;
    USE SIGNAL ;
    PORT
      LAYER M4 ;
        RECT  0 66.24 0.192 66.264 ;
    END
  END o[378]
  PIN o[379]
    DIRECTION OUTPUT ;
    USE SIGNAL ;
    PORT
      LAYER M4 ;
        RECT  0 66.384 0.192 66.408 ;
    END
  END o[379]
  PIN o[37]
    DIRECTION OUTPUT ;
    USE SIGNAL ;
    PORT
      LAYER M4 ;
        RECT  0 10.464 0.192 10.488 ;
    END
  END o[37]
  PIN o[380]
    DIRECTION OUTPUT ;
    USE SIGNAL ;
    PORT
      LAYER M4 ;
        RECT  0 66.576 0.192 66.6 ;
    END
  END o[380]
  PIN o[381]
    DIRECTION OUTPUT ;
    USE SIGNAL ;
    PORT
      LAYER M4 ;
        RECT  0 66.72 0.192 66.744 ;
    END
  END o[381]
  PIN o[382]
    DIRECTION OUTPUT ;
    USE SIGNAL ;
    PORT
      LAYER M4 ;
        RECT  0 66.912 0.192 66.936 ;
    END
  END o[382]
  PIN o[383]
    DIRECTION OUTPUT ;
    USE SIGNAL ;
    PORT
      LAYER M4 ;
        RECT  0 67.056 0.192 67.08 ;
    END
  END o[383]
  PIN o[384]
    DIRECTION OUTPUT ;
    USE SIGNAL ;
    PORT
      LAYER M4 ;
        RECT  0 67.248 0.192 67.272 ;
    END
  END o[384]
  PIN o[385]
    DIRECTION OUTPUT ;
    USE SIGNAL ;
    PORT
      LAYER M4 ;
        RECT  0 67.392 0.192 67.416 ;
    END
  END o[385]
  PIN o[386]
    DIRECTION OUTPUT ;
    USE SIGNAL ;
    PORT
      LAYER M4 ;
        RECT  0 67.536 0.192 67.56 ;
    END
  END o[386]
  PIN o[387]
    DIRECTION OUTPUT ;
    USE SIGNAL ;
    PORT
      LAYER M4 ;
        RECT  0 67.728 0.192 67.752 ;
    END
  END o[387]
  PIN o[388]
    DIRECTION OUTPUT ;
    USE SIGNAL ;
    PORT
      LAYER M4 ;
        RECT  0 67.872 0.192 67.896 ;
    END
  END o[388]
  PIN o[389]
    DIRECTION OUTPUT ;
    USE SIGNAL ;
    PORT
      LAYER M4 ;
        RECT  0 68.064 0.192 68.088 ;
    END
  END o[389]
  PIN o[38]
    DIRECTION OUTPUT ;
    USE SIGNAL ;
    PORT
      LAYER M4 ;
        RECT  0 10.608 0.192 10.632 ;
    END
  END o[38]
  PIN o[390]
    DIRECTION OUTPUT ;
    USE SIGNAL ;
    PORT
      LAYER M4 ;
        RECT  0 68.208 0.192 68.232 ;
    END
  END o[390]
  PIN o[391]
    DIRECTION OUTPUT ;
    USE SIGNAL ;
    PORT
      LAYER M4 ;
        RECT  0 68.352 0.192 68.376 ;
    END
  END o[391]
  PIN o[392]
    DIRECTION OUTPUT ;
    USE SIGNAL ;
    PORT
      LAYER M4 ;
        RECT  0 68.544 0.192 68.568 ;
    END
  END o[392]
  PIN o[393]
    DIRECTION OUTPUT ;
    USE SIGNAL ;
    PORT
      LAYER M4 ;
        RECT  0 68.688 0.192 68.712 ;
    END
  END o[393]
  PIN o[394]
    DIRECTION OUTPUT ;
    USE SIGNAL ;
    PORT
      LAYER M4 ;
        RECT  0 68.88 0.192 68.904 ;
    END
  END o[394]
  PIN o[395]
    DIRECTION OUTPUT ;
    USE SIGNAL ;
    PORT
      LAYER M4 ;
        RECT  0 69.024 0.192 69.048 ;
    END
  END o[395]
  PIN o[396]
    DIRECTION OUTPUT ;
    USE SIGNAL ;
    PORT
      LAYER M4 ;
        RECT  0 69.168 0.192 69.192 ;
    END
  END o[396]
  PIN o[397]
    DIRECTION OUTPUT ;
    USE SIGNAL ;
    PORT
      LAYER M4 ;
        RECT  0 69.36 0.192 69.384 ;
    END
  END o[397]
  PIN o[398]
    DIRECTION OUTPUT ;
    USE SIGNAL ;
    PORT
      LAYER M4 ;
        RECT  0 69.504 0.192 69.528 ;
    END
  END o[398]
  PIN o[399]
    DIRECTION OUTPUT ;
    USE SIGNAL ;
    PORT
      LAYER M4 ;
        RECT  0 69.696 0.192 69.72 ;
    END
  END o[399]
  PIN o[39]
    DIRECTION OUTPUT ;
    USE SIGNAL ;
    PORT
      LAYER M4 ;
        RECT  0 10.8 0.192 10.824 ;
    END
  END o[39]
  PIN o[3]
    DIRECTION OUTPUT ;
    USE SIGNAL ;
    PORT
      LAYER M4 ;
        RECT  0 4.896 0.192 4.92 ;
    END
  END o[3]
  PIN o[400]
    DIRECTION OUTPUT ;
    USE SIGNAL ;
    PORT
      LAYER M4 ;
        RECT  0 69.84 0.192 69.864 ;
    END
  END o[400]
  PIN o[401]
    DIRECTION OUTPUT ;
    USE SIGNAL ;
    PORT
      LAYER M4 ;
        RECT  0 69.984 0.192 70.008 ;
    END
  END o[401]
  PIN o[402]
    DIRECTION OUTPUT ;
    USE SIGNAL ;
    PORT
      LAYER M4 ;
        RECT  0 70.176 0.192 70.2 ;
    END
  END o[402]
  PIN o[403]
    DIRECTION OUTPUT ;
    USE SIGNAL ;
    PORT
      LAYER M4 ;
        RECT  0 70.32 0.192 70.344 ;
    END
  END o[403]
  PIN o[404]
    DIRECTION OUTPUT ;
    USE SIGNAL ;
    PORT
      LAYER M4 ;
        RECT  0 70.512 0.192 70.536 ;
    END
  END o[404]
  PIN o[405]
    DIRECTION OUTPUT ;
    USE SIGNAL ;
    PORT
      LAYER M4 ;
        RECT  0 70.656 0.192 70.68 ;
    END
  END o[405]
  PIN o[406]
    DIRECTION OUTPUT ;
    USE SIGNAL ;
    PORT
      LAYER M4 ;
        RECT  0 70.848 0.192 70.872 ;
    END
  END o[406]
  PIN o[407]
    DIRECTION OUTPUT ;
    USE SIGNAL ;
    PORT
      LAYER M4 ;
        RECT  0 70.992 0.192 71.016 ;
    END
  END o[407]
  PIN o[408]
    DIRECTION OUTPUT ;
    USE SIGNAL ;
    PORT
      LAYER M4 ;
        RECT  0 71.136 0.192 71.16 ;
    END
  END o[408]
  PIN o[409]
    DIRECTION OUTPUT ;
    USE SIGNAL ;
    PORT
      LAYER M4 ;
        RECT  0 71.328 0.192 71.352 ;
    END
  END o[409]
  PIN o[40]
    DIRECTION OUTPUT ;
    USE SIGNAL ;
    PORT
      LAYER M4 ;
        RECT  0 10.944 0.192 10.968 ;
    END
  END o[40]
  PIN o[410]
    DIRECTION OUTPUT ;
    USE SIGNAL ;
    PORT
      LAYER M4 ;
        RECT  0 71.472 0.192 71.496 ;
    END
  END o[410]
  PIN o[411]
    DIRECTION OUTPUT ;
    USE SIGNAL ;
    PORT
      LAYER M4 ;
        RECT  0 71.664 0.192 71.688 ;
    END
  END o[411]
  PIN o[412]
    DIRECTION OUTPUT ;
    USE SIGNAL ;
    PORT
      LAYER M4 ;
        RECT  0 71.808 0.192 71.832 ;
    END
  END o[412]
  PIN o[413]
    DIRECTION OUTPUT ;
    USE SIGNAL ;
    PORT
      LAYER M4 ;
        RECT  0 71.952 0.192 71.976 ;
    END
  END o[413]
  PIN o[414]
    DIRECTION OUTPUT ;
    USE SIGNAL ;
    PORT
      LAYER M4 ;
        RECT  0 72.144 0.192 72.168 ;
    END
  END o[414]
  PIN o[415]
    DIRECTION OUTPUT ;
    USE SIGNAL ;
    PORT
      LAYER M4 ;
        RECT  0 72.288 0.192 72.312 ;
    END
  END o[415]
  PIN o[416]
    DIRECTION OUTPUT ;
    USE SIGNAL ;
    PORT
      LAYER M4 ;
        RECT  0 72.48 0.192 72.504 ;
    END
  END o[416]
  PIN o[417]
    DIRECTION OUTPUT ;
    USE SIGNAL ;
    PORT
      LAYER M4 ;
        RECT  0 72.624 0.192 72.648 ;
    END
  END o[417]
  PIN o[418]
    DIRECTION OUTPUT ;
    USE SIGNAL ;
    PORT
      LAYER M4 ;
        RECT  0 72.768 0.192 72.792 ;
    END
  END o[418]
  PIN o[419]
    DIRECTION OUTPUT ;
    USE SIGNAL ;
    PORT
      LAYER M4 ;
        RECT  0 72.96 0.192 72.984 ;
    END
  END o[419]
  PIN o[41]
    DIRECTION OUTPUT ;
    USE SIGNAL ;
    PORT
      LAYER M4 ;
        RECT  0 11.136 0.192 11.16 ;
    END
  END o[41]
  PIN o[420]
    DIRECTION OUTPUT ;
    USE SIGNAL ;
    PORT
      LAYER M4 ;
        RECT  0 73.104 0.192 73.128 ;
    END
  END o[420]
  PIN o[421]
    DIRECTION OUTPUT ;
    USE SIGNAL ;
    PORT
      LAYER M4 ;
        RECT  0 73.296 0.192 73.32 ;
    END
  END o[421]
  PIN o[422]
    DIRECTION OUTPUT ;
    USE SIGNAL ;
    PORT
      LAYER M4 ;
        RECT  0 73.44 0.192 73.464 ;
    END
  END o[422]
  PIN o[423]
    DIRECTION OUTPUT ;
    USE SIGNAL ;
    PORT
      LAYER M4 ;
        RECT  0 73.584 0.192 73.608 ;
    END
  END o[423]
  PIN o[424]
    DIRECTION OUTPUT ;
    USE SIGNAL ;
    PORT
      LAYER M4 ;
        RECT  0 73.776 0.192 73.8 ;
    END
  END o[424]
  PIN o[425]
    DIRECTION OUTPUT ;
    USE SIGNAL ;
    PORT
      LAYER M4 ;
        RECT  0 73.92 0.192 73.944 ;
    END
  END o[425]
  PIN o[426]
    DIRECTION OUTPUT ;
    USE SIGNAL ;
    PORT
      LAYER M4 ;
        RECT  0 74.112 0.192 74.136 ;
    END
  END o[426]
  PIN o[427]
    DIRECTION OUTPUT ;
    USE SIGNAL ;
    PORT
      LAYER M4 ;
        RECT  0 74.256 0.192 74.28 ;
    END
  END o[427]
  PIN o[428]
    DIRECTION OUTPUT ;
    USE SIGNAL ;
    PORT
      LAYER M4 ;
        RECT  0 74.4 0.192 74.424 ;
    END
  END o[428]
  PIN o[429]
    DIRECTION OUTPUT ;
    USE SIGNAL ;
    PORT
      LAYER M4 ;
        RECT  0 74.592 0.192 74.616 ;
    END
  END o[429]
  PIN o[42]
    DIRECTION OUTPUT ;
    USE SIGNAL ;
    PORT
      LAYER M4 ;
        RECT  0 11.28 0.192 11.304 ;
    END
  END o[42]
  PIN o[430]
    DIRECTION OUTPUT ;
    USE SIGNAL ;
    PORT
      LAYER M4 ;
        RECT  0 74.736 0.192 74.76 ;
    END
  END o[430]
  PIN o[431]
    DIRECTION OUTPUT ;
    USE SIGNAL ;
    PORT
      LAYER M4 ;
        RECT  0 74.928 0.192 74.952 ;
    END
  END o[431]
  PIN o[432]
    DIRECTION OUTPUT ;
    USE SIGNAL ;
    PORT
      LAYER M4 ;
        RECT  0 75.072 0.192 75.096 ;
    END
  END o[432]
  PIN o[433]
    DIRECTION OUTPUT ;
    USE SIGNAL ;
    PORT
      LAYER M4 ;
        RECT  0 75.264 0.192 75.288 ;
    END
  END o[433]
  PIN o[434]
    DIRECTION OUTPUT ;
    USE SIGNAL ;
    PORT
      LAYER M4 ;
        RECT  0 75.408 0.192 75.432 ;
    END
  END o[434]
  PIN o[435]
    DIRECTION OUTPUT ;
    USE SIGNAL ;
    PORT
      LAYER M4 ;
        RECT  0 75.552 0.192 75.576 ;
    END
  END o[435]
  PIN o[436]
    DIRECTION OUTPUT ;
    USE SIGNAL ;
    PORT
      LAYER M4 ;
        RECT  0 75.744 0.192 75.768 ;
    END
  END o[436]
  PIN o[437]
    DIRECTION OUTPUT ;
    USE SIGNAL ;
    PORT
      LAYER M4 ;
        RECT  0 75.888 0.192 75.912 ;
    END
  END o[437]
  PIN o[438]
    DIRECTION OUTPUT ;
    USE SIGNAL ;
    PORT
      LAYER M4 ;
        RECT  0 76.08 0.192 76.104 ;
    END
  END o[438]
  PIN o[439]
    DIRECTION OUTPUT ;
    USE SIGNAL ;
    PORT
      LAYER M4 ;
        RECT  0 76.224 0.192 76.248 ;
    END
  END o[439]
  PIN o[43]
    DIRECTION OUTPUT ;
    USE SIGNAL ;
    PORT
      LAYER M4 ;
        RECT  0 11.424 0.192 11.448 ;
    END
  END o[43]
  PIN o[440]
    DIRECTION OUTPUT ;
    USE SIGNAL ;
    PORT
      LAYER M4 ;
        RECT  0 76.368 0.192 76.392 ;
    END
  END o[440]
  PIN o[441]
    DIRECTION OUTPUT ;
    USE SIGNAL ;
    PORT
      LAYER M4 ;
        RECT  0 76.56 0.192 76.584 ;
    END
  END o[441]
  PIN o[442]
    DIRECTION OUTPUT ;
    USE SIGNAL ;
    PORT
      LAYER M4 ;
        RECT  0 76.704 0.192 76.728 ;
    END
  END o[442]
  PIN o[443]
    DIRECTION OUTPUT ;
    USE SIGNAL ;
    PORT
      LAYER M4 ;
        RECT  0 76.896 0.192 76.92 ;
    END
  END o[443]
  PIN o[444]
    DIRECTION OUTPUT ;
    USE SIGNAL ;
    PORT
      LAYER M4 ;
        RECT  0 77.04 0.192 77.064 ;
    END
  END o[444]
  PIN o[445]
    DIRECTION OUTPUT ;
    USE SIGNAL ;
    PORT
      LAYER M4 ;
        RECT  0 77.184 0.192 77.208 ;
    END
  END o[445]
  PIN o[446]
    DIRECTION OUTPUT ;
    USE SIGNAL ;
    PORT
      LAYER M4 ;
        RECT  0 77.376 0.192 77.4 ;
    END
  END o[446]
  PIN o[447]
    DIRECTION OUTPUT ;
    USE SIGNAL ;
    PORT
      LAYER M4 ;
        RECT  0 77.52 0.192 77.544 ;
    END
  END o[447]
  PIN o[448]
    DIRECTION OUTPUT ;
    USE SIGNAL ;
    PORT
      LAYER M4 ;
        RECT  0 77.712 0.192 77.736 ;
    END
  END o[448]
  PIN o[449]
    DIRECTION OUTPUT ;
    USE SIGNAL ;
    PORT
      LAYER M4 ;
        RECT  0 77.856 0.192 77.88 ;
    END
  END o[449]
  PIN o[44]
    DIRECTION OUTPUT ;
    USE SIGNAL ;
    PORT
      LAYER M4 ;
        RECT  0 11.616 0.192 11.64 ;
    END
  END o[44]
  PIN o[450]
    DIRECTION OUTPUT ;
    USE SIGNAL ;
    PORT
      LAYER M4 ;
        RECT  0 78 0.192 78.024 ;
    END
  END o[450]
  PIN o[451]
    DIRECTION OUTPUT ;
    USE SIGNAL ;
    PORT
      LAYER M4 ;
        RECT  0 78.192 0.192 78.216 ;
    END
  END o[451]
  PIN o[452]
    DIRECTION OUTPUT ;
    USE SIGNAL ;
    PORT
      LAYER M4 ;
        RECT  0 78.336 0.192 78.36 ;
    END
  END o[452]
  PIN o[453]
    DIRECTION OUTPUT ;
    USE SIGNAL ;
    PORT
      LAYER M4 ;
        RECT  0 78.528 0.192 78.552 ;
    END
  END o[453]
  PIN o[454]
    DIRECTION OUTPUT ;
    USE SIGNAL ;
    PORT
      LAYER M4 ;
        RECT  0 78.672 0.192 78.696 ;
    END
  END o[454]
  PIN o[455]
    DIRECTION OUTPUT ;
    USE SIGNAL ;
    PORT
      LAYER M4 ;
        RECT  0 78.816 0.192 78.84 ;
    END
  END o[455]
  PIN o[456]
    DIRECTION OUTPUT ;
    USE SIGNAL ;
    PORT
      LAYER M4 ;
        RECT  0 79.008 0.192 79.032 ;
    END
  END o[456]
  PIN o[457]
    DIRECTION OUTPUT ;
    USE SIGNAL ;
    PORT
      LAYER M4 ;
        RECT  0 79.152 0.192 79.176 ;
    END
  END o[457]
  PIN o[458]
    DIRECTION OUTPUT ;
    USE SIGNAL ;
    PORT
      LAYER M4 ;
        RECT  0 79.344 0.192 79.368 ;
    END
  END o[458]
  PIN o[459]
    DIRECTION OUTPUT ;
    USE SIGNAL ;
    PORT
      LAYER M4 ;
        RECT  0 79.488 0.192 79.512 ;
    END
  END o[459]
  PIN o[45]
    DIRECTION OUTPUT ;
    USE SIGNAL ;
    PORT
      LAYER M4 ;
        RECT  0 11.76 0.192 11.784 ;
    END
  END o[45]
  PIN o[460]
    DIRECTION OUTPUT ;
    USE SIGNAL ;
    PORT
      LAYER M4 ;
        RECT  0 79.68 0.192 79.704 ;
    END
  END o[460]
  PIN o[461]
    DIRECTION OUTPUT ;
    USE SIGNAL ;
    PORT
      LAYER M4 ;
        RECT  0 79.824 0.192 79.848 ;
    END
  END o[461]
  PIN o[462]
    DIRECTION OUTPUT ;
    USE SIGNAL ;
    PORT
      LAYER M4 ;
        RECT  0 79.968 0.192 79.992 ;
    END
  END o[462]
  PIN o[463]
    DIRECTION OUTPUT ;
    USE SIGNAL ;
    PORT
      LAYER M4 ;
        RECT  0 80.16 0.192 80.184 ;
    END
  END o[463]
  PIN o[464]
    DIRECTION OUTPUT ;
    USE SIGNAL ;
    PORT
      LAYER M4 ;
        RECT  0 80.304 0.192 80.328 ;
    END
  END o[464]
  PIN o[465]
    DIRECTION OUTPUT ;
    USE SIGNAL ;
    PORT
      LAYER M4 ;
        RECT  0 80.496 0.192 80.52 ;
    END
  END o[465]
  PIN o[466]
    DIRECTION OUTPUT ;
    USE SIGNAL ;
    PORT
      LAYER M4 ;
        RECT  0 80.64 0.192 80.664 ;
    END
  END o[466]
  PIN o[467]
    DIRECTION OUTPUT ;
    USE SIGNAL ;
    PORT
      LAYER M4 ;
        RECT  0 80.784 0.192 80.808 ;
    END
  END o[467]
  PIN o[468]
    DIRECTION OUTPUT ;
    USE SIGNAL ;
    PORT
      LAYER M4 ;
        RECT  0 80.976 0.192 81 ;
    END
  END o[468]
  PIN o[469]
    DIRECTION OUTPUT ;
    USE SIGNAL ;
    PORT
      LAYER M4 ;
        RECT  0 81.12 0.192 81.144 ;
    END
  END o[469]
  PIN o[46]
    DIRECTION OUTPUT ;
    USE SIGNAL ;
    PORT
      LAYER M4 ;
        RECT  0 11.952 0.192 11.976 ;
    END
  END o[46]
  PIN o[470]
    DIRECTION OUTPUT ;
    USE SIGNAL ;
    PORT
      LAYER M4 ;
        RECT  0 81.312 0.192 81.336 ;
    END
  END o[470]
  PIN o[471]
    DIRECTION OUTPUT ;
    USE SIGNAL ;
    PORT
      LAYER M4 ;
        RECT  0 81.456 0.192 81.48 ;
    END
  END o[471]
  PIN o[472]
    DIRECTION OUTPUT ;
    USE SIGNAL ;
    PORT
      LAYER M4 ;
        RECT  0 81.6 0.192 81.624 ;
    END
  END o[472]
  PIN o[473]
    DIRECTION OUTPUT ;
    USE SIGNAL ;
    PORT
      LAYER M4 ;
        RECT  0 81.792 0.192 81.816 ;
    END
  END o[473]
  PIN o[474]
    DIRECTION OUTPUT ;
    USE SIGNAL ;
    PORT
      LAYER M4 ;
        RECT  0 81.936 0.192 81.96 ;
    END
  END o[474]
  PIN o[475]
    DIRECTION OUTPUT ;
    USE SIGNAL ;
    PORT
      LAYER M4 ;
        RECT  0 82.128 0.192 82.152 ;
    END
  END o[475]
  PIN o[476]
    DIRECTION OUTPUT ;
    USE SIGNAL ;
    PORT
      LAYER M4 ;
        RECT  0 82.272 0.192 82.296 ;
    END
  END o[476]
  PIN o[477]
    DIRECTION OUTPUT ;
    USE SIGNAL ;
    PORT
      LAYER M4 ;
        RECT  0 82.416 0.192 82.44 ;
    END
  END o[477]
  PIN o[478]
    DIRECTION OUTPUT ;
    USE SIGNAL ;
    PORT
      LAYER M4 ;
        RECT  0 82.608 0.192 82.632 ;
    END
  END o[478]
  PIN o[479]
    DIRECTION OUTPUT ;
    USE SIGNAL ;
    PORT
      LAYER M4 ;
        RECT  0 82.752 0.192 82.776 ;
    END
  END o[479]
  PIN o[47]
    DIRECTION OUTPUT ;
    USE SIGNAL ;
    PORT
      LAYER M4 ;
        RECT  0 12.096 0.192 12.12 ;
    END
  END o[47]
  PIN o[480]
    DIRECTION OUTPUT ;
    USE SIGNAL ;
    PORT
      LAYER M4 ;
        RECT  0 82.944 0.192 82.968 ;
    END
  END o[480]
  PIN o[481]
    DIRECTION OUTPUT ;
    USE SIGNAL ;
    PORT
      LAYER M4 ;
        RECT  0 83.088 0.192 83.112 ;
    END
  END o[481]
  PIN o[482]
    DIRECTION OUTPUT ;
    USE SIGNAL ;
    PORT
      LAYER M4 ;
        RECT  0 83.232 0.192 83.256 ;
    END
  END o[482]
  PIN o[483]
    DIRECTION OUTPUT ;
    USE SIGNAL ;
    PORT
      LAYER M4 ;
        RECT  0 83.424 0.192 83.448 ;
    END
  END o[483]
  PIN o[484]
    DIRECTION OUTPUT ;
    USE SIGNAL ;
    PORT
      LAYER M4 ;
        RECT  0 83.568 0.192 83.592 ;
    END
  END o[484]
  PIN o[485]
    DIRECTION OUTPUT ;
    USE SIGNAL ;
    PORT
      LAYER M4 ;
        RECT  0 83.76 0.192 83.784 ;
    END
  END o[485]
  PIN o[486]
    DIRECTION OUTPUT ;
    USE SIGNAL ;
    PORT
      LAYER M4 ;
        RECT  0 83.904 0.192 83.928 ;
    END
  END o[486]
  PIN o[487]
    DIRECTION OUTPUT ;
    USE SIGNAL ;
    PORT
      LAYER M4 ;
        RECT  0 84.096 0.192 84.12 ;
    END
  END o[487]
  PIN o[488]
    DIRECTION OUTPUT ;
    USE SIGNAL ;
    PORT
      LAYER M4 ;
        RECT  0 84.24 0.192 84.264 ;
    END
  END o[488]
  PIN o[489]
    DIRECTION OUTPUT ;
    USE SIGNAL ;
    PORT
      LAYER M4 ;
        RECT  0 84.384 0.192 84.408 ;
    END
  END o[489]
  PIN o[48]
    DIRECTION OUTPUT ;
    USE SIGNAL ;
    PORT
      LAYER M4 ;
        RECT  0 12.288 0.192 12.312 ;
    END
  END o[48]
  PIN o[490]
    DIRECTION OUTPUT ;
    USE SIGNAL ;
    PORT
      LAYER M4 ;
        RECT  0 84.576 0.192 84.6 ;
    END
  END o[490]
  PIN o[491]
    DIRECTION OUTPUT ;
    USE SIGNAL ;
    PORT
      LAYER M4 ;
        RECT  0 84.72 0.192 84.744 ;
    END
  END o[491]
  PIN o[492]
    DIRECTION OUTPUT ;
    USE SIGNAL ;
    PORT
      LAYER M4 ;
        RECT  0 84.912 0.192 84.936 ;
    END
  END o[492]
  PIN o[493]
    DIRECTION OUTPUT ;
    USE SIGNAL ;
    PORT
      LAYER M4 ;
        RECT  0 85.056 0.192 85.08 ;
    END
  END o[493]
  PIN o[494]
    DIRECTION OUTPUT ;
    USE SIGNAL ;
    PORT
      LAYER M4 ;
        RECT  0 85.2 0.192 85.224 ;
    END
  END o[494]
  PIN o[495]
    DIRECTION OUTPUT ;
    USE SIGNAL ;
    PORT
      LAYER M4 ;
        RECT  0 85.392 0.192 85.416 ;
    END
  END o[495]
  PIN o[496]
    DIRECTION OUTPUT ;
    USE SIGNAL ;
    PORT
      LAYER M4 ;
        RECT  0 85.536 0.192 85.56 ;
    END
  END o[496]
  PIN o[497]
    DIRECTION OUTPUT ;
    USE SIGNAL ;
    PORT
      LAYER M4 ;
        RECT  0 85.728 0.192 85.752 ;
    END
  END o[497]
  PIN o[498]
    DIRECTION OUTPUT ;
    USE SIGNAL ;
    PORT
      LAYER M4 ;
        RECT  0 85.872 0.192 85.896 ;
    END
  END o[498]
  PIN o[499]
    DIRECTION OUTPUT ;
    USE SIGNAL ;
    PORT
      LAYER M4 ;
        RECT  0 86.016 0.192 86.04 ;
    END
  END o[499]
  PIN o[49]
    DIRECTION OUTPUT ;
    USE SIGNAL ;
    PORT
      LAYER M4 ;
        RECT  0 12.432 0.192 12.456 ;
    END
  END o[49]
  PIN o[4]
    DIRECTION OUTPUT ;
    USE SIGNAL ;
    PORT
      LAYER M4 ;
        RECT  0 5.088 0.192 5.112 ;
    END
  END o[4]
  PIN o[500]
    DIRECTION OUTPUT ;
    USE SIGNAL ;
    PORT
      LAYER M4 ;
        RECT  0 86.208 0.192 86.232 ;
    END
  END o[500]
  PIN o[501]
    DIRECTION OUTPUT ;
    USE SIGNAL ;
    PORT
      LAYER M4 ;
        RECT  0 86.352 0.192 86.376 ;
    END
  END o[501]
  PIN o[502]
    DIRECTION OUTPUT ;
    USE SIGNAL ;
    PORT
      LAYER M4 ;
        RECT  0 86.544 0.192 86.568 ;
    END
  END o[502]
  PIN o[503]
    DIRECTION OUTPUT ;
    USE SIGNAL ;
    PORT
      LAYER M4 ;
        RECT  0 86.688 0.192 86.712 ;
    END
  END o[503]
  PIN o[504]
    DIRECTION OUTPUT ;
    USE SIGNAL ;
    PORT
      LAYER M4 ;
        RECT  0 86.832 0.192 86.856 ;
    END
  END o[504]
  PIN o[505]
    DIRECTION OUTPUT ;
    USE SIGNAL ;
    PORT
      LAYER M4 ;
        RECT  0 87.024 0.192 87.048 ;
    END
  END o[505]
  PIN o[506]
    DIRECTION OUTPUT ;
    USE SIGNAL ;
    PORT
      LAYER M4 ;
        RECT  0 87.168 0.192 87.192 ;
    END
  END o[506]
  PIN o[507]
    DIRECTION OUTPUT ;
    USE SIGNAL ;
    PORT
      LAYER M4 ;
        RECT  0 87.36 0.192 87.384 ;
    END
  END o[507]
  PIN o[508]
    DIRECTION OUTPUT ;
    USE SIGNAL ;
    PORT
      LAYER M4 ;
        RECT  0 87.504 0.192 87.528 ;
    END
  END o[508]
  PIN o[509]
    DIRECTION OUTPUT ;
    USE SIGNAL ;
    PORT
      LAYER M4 ;
        RECT  0 87.696 0.192 87.72 ;
    END
  END o[509]
  PIN o[50]
    DIRECTION OUTPUT ;
    USE SIGNAL ;
    PORT
      LAYER M4 ;
        RECT  0 12.576 0.192 12.6 ;
    END
  END o[50]
  PIN o[510]
    DIRECTION OUTPUT ;
    USE SIGNAL ;
    PORT
      LAYER M4 ;
        RECT  0 87.84 0.192 87.864 ;
    END
  END o[510]
  PIN o[511]
    DIRECTION OUTPUT ;
    USE SIGNAL ;
    PORT
      LAYER M4 ;
        RECT  0 87.984 0.192 88.008 ;
    END
  END o[511]
  PIN o[512]
    DIRECTION OUTPUT ;
    USE SIGNAL ;
    PORT
      LAYER M4 ;
        RECT  0 88.176 0.192 88.2 ;
    END
  END o[512]
  PIN o[513]
    DIRECTION OUTPUT ;
    USE SIGNAL ;
    PORT
      LAYER M4 ;
        RECT  0 88.32 0.192 88.344 ;
    END
  END o[513]
  PIN o[514]
    DIRECTION OUTPUT ;
    USE SIGNAL ;
    PORT
      LAYER M4 ;
        RECT  0 88.512 0.192 88.536 ;
    END
  END o[514]
  PIN o[51]
    DIRECTION OUTPUT ;
    USE SIGNAL ;
    PORT
      LAYER M4 ;
        RECT  0 12.768 0.192 12.792 ;
    END
  END o[51]
  PIN o[52]
    DIRECTION OUTPUT ;
    USE SIGNAL ;
    PORT
      LAYER M4 ;
        RECT  0 12.912 0.192 12.936 ;
    END
  END o[52]
  PIN o[53]
    DIRECTION OUTPUT ;
    USE SIGNAL ;
    PORT
      LAYER M4 ;
        RECT  0 13.104 0.192 13.128 ;
    END
  END o[53]
  PIN o[54]
    DIRECTION OUTPUT ;
    USE SIGNAL ;
    PORT
      LAYER M4 ;
        RECT  0 13.248 0.192 13.272 ;
    END
  END o[54]
  PIN o[55]
    DIRECTION OUTPUT ;
    USE SIGNAL ;
    PORT
      LAYER M4 ;
        RECT  0 13.392 0.192 13.416 ;
    END
  END o[55]
  PIN o[56]
    DIRECTION OUTPUT ;
    USE SIGNAL ;
    PORT
      LAYER M4 ;
        RECT  0 13.584 0.192 13.608 ;
    END
  END o[56]
  PIN o[57]
    DIRECTION OUTPUT ;
    USE SIGNAL ;
    PORT
      LAYER M4 ;
        RECT  0 13.728 0.192 13.752 ;
    END
  END o[57]
  PIN o[58]
    DIRECTION OUTPUT ;
    USE SIGNAL ;
    PORT
      LAYER M4 ;
        RECT  0 13.92 0.192 13.944 ;
    END
  END o[58]
  PIN o[59]
    DIRECTION OUTPUT ;
    USE SIGNAL ;
    PORT
      LAYER M4 ;
        RECT  0 14.064 0.192 14.088 ;
    END
  END o[59]
  PIN o[5]
    DIRECTION OUTPUT ;
    USE SIGNAL ;
    PORT
      LAYER M4 ;
        RECT  0 5.232 0.192 5.256 ;
    END
  END o[5]
  PIN o[60]
    DIRECTION OUTPUT ;
    USE SIGNAL ;
    PORT
      LAYER M4 ;
        RECT  0 14.208 0.192 14.232 ;
    END
  END o[60]
  PIN o[61]
    DIRECTION OUTPUT ;
    USE SIGNAL ;
    PORT
      LAYER M4 ;
        RECT  0 14.4 0.192 14.424 ;
    END
  END o[61]
  PIN o[62]
    DIRECTION OUTPUT ;
    USE SIGNAL ;
    PORT
      LAYER M4 ;
        RECT  0 14.544 0.192 14.568 ;
    END
  END o[62]
  PIN o[63]
    DIRECTION OUTPUT ;
    USE SIGNAL ;
    PORT
      LAYER M4 ;
        RECT  0 14.736 0.192 14.76 ;
    END
  END o[63]
  PIN o[64]
    DIRECTION OUTPUT ;
    USE SIGNAL ;
    PORT
      LAYER M4 ;
        RECT  0 14.88 0.192 14.904 ;
    END
  END o[64]
  PIN o[65]
    DIRECTION OUTPUT ;
    USE SIGNAL ;
    PORT
      LAYER M4 ;
        RECT  0 15.024 0.192 15.048 ;
    END
  END o[65]
  PIN o[66]
    DIRECTION OUTPUT ;
    USE SIGNAL ;
    PORT
      LAYER M4 ;
        RECT  0 15.216 0.192 15.24 ;
    END
  END o[66]
  PIN o[67]
    DIRECTION OUTPUT ;
    USE SIGNAL ;
    PORT
      LAYER M4 ;
        RECT  0 15.36 0.192 15.384 ;
    END
  END o[67]
  PIN o[68]
    DIRECTION OUTPUT ;
    USE SIGNAL ;
    PORT
      LAYER M4 ;
        RECT  0 15.552 0.192 15.576 ;
    END
  END o[68]
  PIN o[69]
    DIRECTION OUTPUT ;
    USE SIGNAL ;
    PORT
      LAYER M4 ;
        RECT  0 15.696 0.192 15.72 ;
    END
  END o[69]
  PIN o[6]
    DIRECTION OUTPUT ;
    USE SIGNAL ;
    PORT
      LAYER M4 ;
        RECT  0 5.376 0.192 5.4 ;
    END
  END o[6]
  PIN o[70]
    DIRECTION OUTPUT ;
    USE SIGNAL ;
    PORT
      LAYER M4 ;
        RECT  0 15.84 0.192 15.864 ;
    END
  END o[70]
  PIN o[71]
    DIRECTION OUTPUT ;
    USE SIGNAL ;
    PORT
      LAYER M4 ;
        RECT  0 16.032 0.192 16.056 ;
    END
  END o[71]
  PIN o[72]
    DIRECTION OUTPUT ;
    USE SIGNAL ;
    PORT
      LAYER M4 ;
        RECT  0 16.176 0.192 16.2 ;
    END
  END o[72]
  PIN o[73]
    DIRECTION OUTPUT ;
    USE SIGNAL ;
    PORT
      LAYER M4 ;
        RECT  0 16.368 0.192 16.392 ;
    END
  END o[73]
  PIN o[74]
    DIRECTION OUTPUT ;
    USE SIGNAL ;
    PORT
      LAYER M4 ;
        RECT  0 16.512 0.192 16.536 ;
    END
  END o[74]
  PIN o[75]
    DIRECTION OUTPUT ;
    USE SIGNAL ;
    PORT
      LAYER M4 ;
        RECT  0 16.704 0.192 16.728 ;
    END
  END o[75]
  PIN o[76]
    DIRECTION OUTPUT ;
    USE SIGNAL ;
    PORT
      LAYER M4 ;
        RECT  0 16.848 0.192 16.872 ;
    END
  END o[76]
  PIN o[77]
    DIRECTION OUTPUT ;
    USE SIGNAL ;
    PORT
      LAYER M4 ;
        RECT  0 16.992 0.192 17.016 ;
    END
  END o[77]
  PIN o[78]
    DIRECTION OUTPUT ;
    USE SIGNAL ;
    PORT
      LAYER M4 ;
        RECT  0 17.184 0.192 17.208 ;
    END
  END o[78]
  PIN o[79]
    DIRECTION OUTPUT ;
    USE SIGNAL ;
    PORT
      LAYER M4 ;
        RECT  0 17.328 0.192 17.352 ;
    END
  END o[79]
  PIN o[7]
    DIRECTION OUTPUT ;
    USE SIGNAL ;
    PORT
      LAYER M4 ;
        RECT  0 5.568 0.192 5.592 ;
    END
  END o[7]
  PIN o[80]
    DIRECTION OUTPUT ;
    USE SIGNAL ;
    PORT
      LAYER M4 ;
        RECT  0 17.52 0.192 17.544 ;
    END
  END o[80]
  PIN o[81]
    DIRECTION OUTPUT ;
    USE SIGNAL ;
    PORT
      LAYER M4 ;
        RECT  0 17.664 0.192 17.688 ;
    END
  END o[81]
  PIN o[82]
    DIRECTION OUTPUT ;
    USE SIGNAL ;
    PORT
      LAYER M4 ;
        RECT  0 17.808 0.192 17.832 ;
    END
  END o[82]
  PIN o[83]
    DIRECTION OUTPUT ;
    USE SIGNAL ;
    PORT
      LAYER M4 ;
        RECT  0 18 0.192 18.024 ;
    END
  END o[83]
  PIN o[84]
    DIRECTION OUTPUT ;
    USE SIGNAL ;
    PORT
      LAYER M4 ;
        RECT  0 18.144 0.192 18.168 ;
    END
  END o[84]
  PIN o[85]
    DIRECTION OUTPUT ;
    USE SIGNAL ;
    PORT
      LAYER M4 ;
        RECT  0 18.336 0.192 18.36 ;
    END
  END o[85]
  PIN o[86]
    DIRECTION OUTPUT ;
    USE SIGNAL ;
    PORT
      LAYER M4 ;
        RECT  0 18.48 0.192 18.504 ;
    END
  END o[86]
  PIN o[87]
    DIRECTION OUTPUT ;
    USE SIGNAL ;
    PORT
      LAYER M4 ;
        RECT  0 18.624 0.192 18.648 ;
    END
  END o[87]
  PIN o[88]
    DIRECTION OUTPUT ;
    USE SIGNAL ;
    PORT
      LAYER M4 ;
        RECT  0 18.816 0.192 18.84 ;
    END
  END o[88]
  PIN o[89]
    DIRECTION OUTPUT ;
    USE SIGNAL ;
    PORT
      LAYER M4 ;
        RECT  0 18.96 0.192 18.984 ;
    END
  END o[89]
  PIN o[8]
    DIRECTION OUTPUT ;
    USE SIGNAL ;
    PORT
      LAYER M4 ;
        RECT  0 5.712 0.192 5.736 ;
    END
  END o[8]
  PIN o[90]
    DIRECTION OUTPUT ;
    USE SIGNAL ;
    PORT
      LAYER M4 ;
        RECT  0 19.152 0.192 19.176 ;
    END
  END o[90]
  PIN o[91]
    DIRECTION OUTPUT ;
    USE SIGNAL ;
    PORT
      LAYER M4 ;
        RECT  0 19.296 0.192 19.32 ;
    END
  END o[91]
  PIN o[92]
    DIRECTION OUTPUT ;
    USE SIGNAL ;
    PORT
      LAYER M4 ;
        RECT  0 19.44 0.192 19.464 ;
    END
  END o[92]
  PIN o[93]
    DIRECTION OUTPUT ;
    USE SIGNAL ;
    PORT
      LAYER M4 ;
        RECT  0 19.632 0.192 19.656 ;
    END
  END o[93]
  PIN o[94]
    DIRECTION OUTPUT ;
    USE SIGNAL ;
    PORT
      LAYER M4 ;
        RECT  0 19.776 0.192 19.8 ;
    END
  END o[94]
  PIN o[95]
    DIRECTION OUTPUT ;
    USE SIGNAL ;
    PORT
      LAYER M4 ;
        RECT  0 19.968 0.192 19.992 ;
    END
  END o[95]
  PIN o[96]
    DIRECTION OUTPUT ;
    USE SIGNAL ;
    PORT
      LAYER M4 ;
        RECT  0 20.112 0.192 20.136 ;
    END
  END o[96]
  PIN o[97]
    DIRECTION OUTPUT ;
    USE SIGNAL ;
    PORT
      LAYER M4 ;
        RECT  0 20.304 0.192 20.328 ;
    END
  END o[97]
  PIN o[98]
    DIRECTION OUTPUT ;
    USE SIGNAL ;
    PORT
      LAYER M4 ;
        RECT  0 20.448 0.192 20.472 ;
    END
  END o[98]
  PIN o[99]
    DIRECTION OUTPUT ;
    USE SIGNAL ;
    PORT
      LAYER M4 ;
        RECT  0 20.592 0.192 20.616 ;
    END
  END o[99]
  PIN o[9]
    DIRECTION OUTPUT ;
    USE SIGNAL ;
    PORT
      LAYER M4 ;
        RECT  0 5.904 0.192 5.928 ;
    END
  END o[9]
  PIN VDD
    DIRECTION INOUT ;
    USE POWER ;
    PORT
      LAYER M5 ;
        RECT  72.792 2.151 72.912 90.729 ;
        RECT  70.092 2.151 70.212 90.729 ;
        RECT  67.392 2.151 67.512 90.729 ;
        RECT  64.692 2.151 64.812 90.729 ;
        RECT  61.992 2.151 62.112 90.729 ;
        RECT  59.292 2.151 59.412 90.729 ;
        RECT  56.592 2.151 56.712 90.729 ;
        RECT  53.892 2.151 54.012 90.729 ;
        RECT  51.192 2.151 51.312 90.729 ;
        RECT  48.492 2.151 48.612 90.729 ;
        RECT  45.792 2.151 45.912 90.729 ;
        RECT  43.092 2.151 43.212 90.729 ;
        RECT  40.392 2.151 40.512 90.729 ;
        RECT  37.692 2.151 37.812 90.729 ;
        RECT  34.992 2.151 35.112 90.729 ;
        RECT  32.292 2.151 32.412 90.729 ;
        RECT  29.592 2.151 29.712 90.729 ;
        RECT  26.892 2.151 27.012 90.729 ;
        RECT  24.192 2.151 24.312 90.729 ;
        RECT  21.492 2.151 21.612 90.729 ;
        RECT  18.792 2.151 18.912 90.729 ;
        RECT  16.092 2.151 16.212 90.729 ;
        RECT  13.392 2.151 13.512 90.729 ;
        RECT  10.692 2.151 10.812 90.729 ;
        RECT  7.992 2.151 8.112 90.729 ;
        RECT  5.292 2.151 5.412 90.729 ;
        RECT  2.592 2.151 2.712 90.729 ;
    END
  END VDD
  PIN VSS
    DIRECTION INOUT ;
    USE GROUND ;
    PORT
      LAYER M5 ;
        RECT  72.6 2.137 72.72 90.743 ;
        RECT  69.9 2.137 70.02 90.743 ;
        RECT  67.2 2.137 67.32 90.743 ;
        RECT  64.5 2.137 64.62 90.743 ;
        RECT  61.8 2.137 61.92 90.743 ;
        RECT  59.1 2.137 59.22 90.743 ;
        RECT  56.4 2.137 56.52 90.743 ;
        RECT  53.7 2.137 53.82 90.743 ;
        RECT  51 2.137 51.12 90.743 ;
        RECT  48.3 2.137 48.42 90.743 ;
        RECT  45.6 2.137 45.72 90.743 ;
        RECT  42.9 2.137 43.02 90.743 ;
        RECT  40.2 2.137 40.32 90.743 ;
        RECT  37.5 2.137 37.62 90.743 ;
        RECT  34.8 2.137 34.92 90.743 ;
        RECT  32.1 2.137 32.22 90.743 ;
        RECT  29.4 2.137 29.52 90.743 ;
        RECT  26.7 2.137 26.82 90.743 ;
        RECT  24 2.137 24.12 90.743 ;
        RECT  21.3 2.137 21.42 90.743 ;
        RECT  18.6 2.137 18.72 90.743 ;
        RECT  15.9 2.137 16.02 90.743 ;
        RECT  13.2 2.137 13.32 90.743 ;
        RECT  10.5 2.137 10.62 90.743 ;
        RECT  7.8 2.137 7.92 90.743 ;
        RECT  5.1 2.137 5.22 90.743 ;
        RECT  2.4 2.137 2.52 90.743 ;
    END
  END VSS
  OBS
    LAYER RVTN ;
     RECT  2.16 2.16 73.44 2.295 ;
     RECT  2.16 2.565 73.44 2.835 ;
     RECT  2.16 3.105 73.44 3.375 ;
     RECT  2.16 3.645 73.44 3.915 ;
     RECT  2.16 4.185 73.44 4.455 ;
     RECT  2.16 4.725 73.44 4.995 ;
     RECT  2.16 5.265 73.44 5.535 ;
     RECT  2.16 5.805 73.44 6.075 ;
     RECT  2.16 6.345 73.44 6.615 ;
     RECT  2.16 6.885 73.44 7.155 ;
     RECT  2.16 7.425 73.44 7.695 ;
     RECT  2.16 7.965 73.44 8.235 ;
     RECT  2.16 8.505 73.44 8.775 ;
     RECT  2.16 9.045 73.44 9.315 ;
     RECT  2.16 9.585 73.44 9.855 ;
     RECT  2.16 10.125 73.44 10.395 ;
     RECT  2.16 10.665 73.44 10.935 ;
     RECT  2.16 11.205 73.44 11.475 ;
     RECT  2.16 11.745 73.44 12.015 ;
     RECT  2.16 12.285 73.44 12.555 ;
     RECT  2.16 12.825 73.44 13.095 ;
     RECT  2.16 13.365 73.44 13.635 ;
     RECT  2.16 13.905 73.44 14.175 ;
     RECT  2.16 14.445 73.44 14.715 ;
     RECT  2.16 14.985 73.44 15.255 ;
     RECT  2.16 15.525 73.44 15.795 ;
     RECT  2.16 16.065 73.44 16.335 ;
     RECT  2.16 16.605 73.44 16.875 ;
     RECT  2.16 17.145 73.44 17.415 ;
     RECT  2.16 17.685 73.44 17.955 ;
     RECT  2.16 18.225 73.44 18.495 ;
     RECT  2.16 18.765 73.44 19.035 ;
     RECT  2.16 19.305 73.44 19.575 ;
     RECT  2.16 19.845 73.44 20.115 ;
     RECT  2.16 20.385 73.44 20.655 ;
     RECT  2.16 20.925 73.44 21.195 ;
     RECT  2.16 21.465 73.44 21.735 ;
     RECT  2.16 22.005 73.44 22.275 ;
     RECT  2.16 22.545 73.44 22.815 ;
     RECT  2.16 23.085 73.44 23.355 ;
     RECT  2.16 23.625 73.44 23.895 ;
     RECT  2.16 24.165 73.44 24.435 ;
     RECT  2.16 24.705 73.44 24.975 ;
     RECT  2.16 25.245 73.44 25.515 ;
     RECT  2.16 25.785 73.44 26.055 ;
     RECT  2.16 26.325 73.44 26.595 ;
     RECT  2.16 26.865 73.44 27.135 ;
     RECT  2.16 27.405 73.44 27.675 ;
     RECT  2.16 27.945 73.44 28.215 ;
     RECT  2.16 28.485 73.44 28.755 ;
     RECT  2.16 29.025 73.44 29.295 ;
     RECT  2.16 29.565 73.44 29.835 ;
     RECT  2.16 30.105 73.44 30.375 ;
     RECT  2.16 30.645 73.44 30.915 ;
     RECT  2.16 31.185 73.44 31.455 ;
     RECT  2.16 31.725 73.44 31.995 ;
     RECT  2.16 32.265 73.44 32.535 ;
     RECT  2.16 32.805 73.44 33.075 ;
     RECT  2.16 33.345 73.44 33.615 ;
     RECT  2.16 33.885 73.44 34.155 ;
     RECT  2.16 34.425 73.44 34.695 ;
     RECT  2.16 34.965 73.44 35.235 ;
     RECT  2.16 35.505 73.44 35.775 ;
     RECT  2.16 36.045 73.44 36.315 ;
     RECT  2.16 36.585 73.44 36.855 ;
     RECT  2.16 37.125 73.44 37.395 ;
     RECT  2.16 37.665 73.44 37.935 ;
     RECT  2.16 38.205 73.44 38.475 ;
     RECT  2.16 38.745 73.44 39.015 ;
     RECT  2.16 39.285 73.44 39.555 ;
     RECT  2.16 39.825 73.44 40.095 ;
     RECT  2.16 40.365 73.44 40.635 ;
     RECT  2.16 40.905 73.44 41.175 ;
     RECT  2.16 41.445 73.44 41.715 ;
     RECT  2.16 41.985 73.44 42.255 ;
     RECT  2.16 42.525 73.44 42.795 ;
     RECT  2.16 43.065 73.44 43.335 ;
     RECT  2.16 43.605 73.44 43.875 ;
     RECT  2.16 44.145 73.44 44.415 ;
     RECT  2.16 44.685 73.44 44.955 ;
     RECT  2.16 45.225 73.44 45.495 ;
     RECT  2.16 45.765 73.44 46.035 ;
     RECT  2.16 46.305 73.44 46.575 ;
     RECT  2.16 46.845 73.44 47.115 ;
     RECT  2.16 47.385 73.44 47.655 ;
     RECT  2.16 47.925 73.44 48.195 ;
     RECT  2.16 48.465 73.44 48.735 ;
     RECT  2.16 49.005 73.44 49.275 ;
     RECT  2.16 49.545 73.44 49.815 ;
     RECT  2.16 50.085 73.44 50.355 ;
     RECT  2.16 50.625 73.44 50.895 ;
     RECT  2.16 51.165 73.44 51.435 ;
     RECT  2.16 51.705 73.44 51.975 ;
     RECT  2.16 52.245 73.44 52.515 ;
     RECT  2.16 52.785 73.44 53.055 ;
     RECT  2.16 53.325 73.44 53.595 ;
     RECT  2.16 53.865 73.44 54.135 ;
     RECT  2.16 54.405 73.44 54.675 ;
     RECT  2.16 54.945 73.44 55.215 ;
     RECT  2.16 55.485 73.44 55.755 ;
     RECT  2.16 56.025 73.44 56.295 ;
     RECT  2.16 56.565 73.44 56.835 ;
     RECT  2.16 57.105 73.44 57.375 ;
     RECT  2.16 57.645 73.44 57.915 ;
     RECT  2.16 58.185 73.44 58.455 ;
     RECT  2.16 58.725 73.44 58.995 ;
     RECT  2.16 59.265 73.44 59.535 ;
     RECT  2.16 59.805 73.44 60.075 ;
     RECT  2.16 60.345 73.44 60.615 ;
     RECT  2.16 60.885 73.44 61.155 ;
     RECT  2.16 61.425 73.44 61.695 ;
     RECT  2.16 61.965 73.44 62.235 ;
     RECT  2.16 62.505 73.44 62.775 ;
     RECT  2.16 63.045 73.44 63.315 ;
     RECT  2.16 63.585 73.44 63.855 ;
     RECT  2.16 64.125 73.44 64.395 ;
     RECT  2.16 64.665 73.44 64.935 ;
     RECT  2.16 65.205 73.44 65.475 ;
     RECT  2.16 65.745 73.44 66.015 ;
     RECT  2.16 66.285 73.44 66.555 ;
     RECT  2.16 66.825 73.44 67.095 ;
     RECT  2.16 67.365 73.44 67.635 ;
     RECT  2.16 67.905 73.44 68.175 ;
     RECT  2.16 68.445 73.44 68.715 ;
     RECT  2.16 68.985 73.44 69.255 ;
     RECT  2.16 69.525 73.44 69.795 ;
     RECT  2.16 70.065 73.44 70.335 ;
     RECT  2.16 70.605 73.44 70.875 ;
     RECT  2.16 71.145 73.44 71.415 ;
     RECT  2.16 71.685 73.44 71.955 ;
     RECT  2.16 72.225 73.44 72.495 ;
     RECT  2.16 72.765 73.44 73.035 ;
     RECT  2.16 73.305 73.44 73.575 ;
     RECT  2.16 73.845 73.44 74.115 ;
     RECT  2.16 74.385 73.44 74.655 ;
     RECT  2.16 74.925 73.44 75.195 ;
     RECT  2.16 75.465 73.44 75.735 ;
     RECT  2.16 76.005 73.44 76.275 ;
     RECT  2.16 76.545 73.44 76.815 ;
     RECT  2.16 77.085 73.44 77.355 ;
     RECT  2.16 77.625 73.44 77.895 ;
     RECT  2.16 78.165 73.44 78.435 ;
     RECT  2.16 78.705 73.44 78.975 ;
     RECT  2.16 79.245 73.44 79.515 ;
     RECT  2.16 79.785 73.44 80.055 ;
     RECT  2.16 80.325 73.44 80.595 ;
     RECT  2.16 80.865 73.44 81.135 ;
     RECT  2.16 81.405 73.44 81.675 ;
     RECT  2.16 81.945 73.44 82.215 ;
     RECT  2.16 82.485 73.44 82.755 ;
     RECT  2.16 83.025 73.44 83.295 ;
     RECT  2.16 83.565 73.44 83.835 ;
     RECT  2.16 84.105 73.44 84.375 ;
     RECT  2.16 84.645 73.44 84.915 ;
     RECT  2.16 85.185 73.44 85.455 ;
     RECT  2.16 85.725 73.44 85.995 ;
     RECT  2.16 86.265 73.44 86.535 ;
     RECT  2.16 86.805 73.44 87.075 ;
     RECT  2.16 87.345 73.44 87.615 ;
     RECT  2.16 87.885 73.44 88.155 ;
     RECT  2.16 88.425 73.44 88.695 ;
     RECT  2.16 88.965 73.44 89.235 ;
     RECT  2.16 89.505 73.44 89.775 ;
     RECT  2.16 90.045 73.44 90.315 ;
     RECT  2.16 90.585 73.44 90.72 ;
    LAYER RVTP ;
     RECT  2.16 2.295 73.44 2.565 ;
     RECT  2.16 2.835 73.44 3.105 ;
     RECT  2.16 3.375 73.44 3.645 ;
     RECT  2.16 3.915 73.44 4.185 ;
     RECT  2.16 4.455 73.44 4.725 ;
     RECT  2.16 4.995 73.44 5.265 ;
     RECT  2.16 5.535 73.44 5.805 ;
     RECT  2.16 6.075 73.44 6.345 ;
     RECT  2.16 6.615 73.44 6.885 ;
     RECT  2.16 7.155 73.44 7.425 ;
     RECT  2.16 7.695 73.44 7.965 ;
     RECT  2.16 8.235 73.44 8.505 ;
     RECT  2.16 8.775 73.44 9.045 ;
     RECT  2.16 9.315 73.44 9.585 ;
     RECT  2.16 9.855 73.44 10.125 ;
     RECT  2.16 10.395 73.44 10.665 ;
     RECT  2.16 10.935 73.44 11.205 ;
     RECT  2.16 11.475 73.44 11.745 ;
     RECT  2.16 12.015 73.44 12.285 ;
     RECT  2.16 12.555 73.44 12.825 ;
     RECT  2.16 13.095 73.44 13.365 ;
     RECT  2.16 13.635 73.44 13.905 ;
     RECT  2.16 14.175 73.44 14.445 ;
     RECT  2.16 14.715 73.44 14.985 ;
     RECT  2.16 15.255 73.44 15.525 ;
     RECT  2.16 15.795 73.44 16.065 ;
     RECT  2.16 16.335 73.44 16.605 ;
     RECT  2.16 16.875 73.44 17.145 ;
     RECT  2.16 17.415 73.44 17.685 ;
     RECT  2.16 17.955 73.44 18.225 ;
     RECT  2.16 18.495 73.44 18.765 ;
     RECT  2.16 19.035 73.44 19.305 ;
     RECT  2.16 19.575 73.44 19.845 ;
     RECT  2.16 20.115 73.44 20.385 ;
     RECT  2.16 20.655 73.44 20.925 ;
     RECT  2.16 21.195 73.44 21.465 ;
     RECT  2.16 21.735 73.44 22.005 ;
     RECT  2.16 22.275 73.44 22.545 ;
     RECT  2.16 22.815 73.44 23.085 ;
     RECT  2.16 23.355 73.44 23.625 ;
     RECT  2.16 23.895 73.44 24.165 ;
     RECT  2.16 24.435 73.44 24.705 ;
     RECT  2.16 24.975 73.44 25.245 ;
     RECT  2.16 25.515 73.44 25.785 ;
     RECT  2.16 26.055 73.44 26.325 ;
     RECT  2.16 26.595 73.44 26.865 ;
     RECT  2.16 27.135 73.44 27.405 ;
     RECT  2.16 27.675 73.44 27.945 ;
     RECT  2.16 28.215 73.44 28.485 ;
     RECT  2.16 28.755 73.44 29.025 ;
     RECT  2.16 29.295 73.44 29.565 ;
     RECT  2.16 29.835 73.44 30.105 ;
     RECT  2.16 30.375 73.44 30.645 ;
     RECT  2.16 30.915 73.44 31.185 ;
     RECT  2.16 31.455 73.44 31.725 ;
     RECT  2.16 31.995 73.44 32.265 ;
     RECT  2.16 32.535 73.44 32.805 ;
     RECT  2.16 33.075 73.44 33.345 ;
     RECT  2.16 33.615 73.44 33.885 ;
     RECT  2.16 34.155 73.44 34.425 ;
     RECT  2.16 34.695 73.44 34.965 ;
     RECT  2.16 35.235 73.44 35.505 ;
     RECT  2.16 35.775 73.44 36.045 ;
     RECT  2.16 36.315 73.44 36.585 ;
     RECT  2.16 36.855 73.44 37.125 ;
     RECT  2.16 37.395 73.44 37.665 ;
     RECT  2.16 37.935 73.44 38.205 ;
     RECT  2.16 38.475 73.44 38.745 ;
     RECT  2.16 39.015 73.44 39.285 ;
     RECT  2.16 39.555 73.44 39.825 ;
     RECT  2.16 40.095 73.44 40.365 ;
     RECT  2.16 40.635 73.44 40.905 ;
     RECT  2.16 41.175 73.44 41.445 ;
     RECT  2.16 41.715 73.44 41.985 ;
     RECT  2.16 42.255 73.44 42.525 ;
     RECT  2.16 42.795 73.44 43.065 ;
     RECT  2.16 43.335 73.44 43.605 ;
     RECT  2.16 43.875 73.44 44.145 ;
     RECT  2.16 44.415 73.44 44.685 ;
     RECT  2.16 44.955 73.44 45.225 ;
     RECT  2.16 45.495 73.44 45.765 ;
     RECT  2.16 46.035 73.44 46.305 ;
     RECT  2.16 46.575 73.44 46.845 ;
     RECT  2.16 47.115 73.44 47.385 ;
     RECT  2.16 47.655 73.44 47.925 ;
     RECT  2.16 48.195 73.44 48.465 ;
     RECT  2.16 48.735 73.44 49.005 ;
     RECT  2.16 49.275 73.44 49.545 ;
     RECT  2.16 49.815 73.44 50.085 ;
     RECT  2.16 50.355 73.44 50.625 ;
     RECT  2.16 50.895 73.44 51.165 ;
     RECT  2.16 51.435 73.44 51.705 ;
     RECT  2.16 51.975 73.44 52.245 ;
     RECT  2.16 52.515 73.44 52.785 ;
     RECT  2.16 53.055 73.44 53.325 ;
     RECT  2.16 53.595 73.44 53.865 ;
     RECT  2.16 54.135 73.44 54.405 ;
     RECT  2.16 54.675 73.44 54.945 ;
     RECT  2.16 55.215 73.44 55.485 ;
     RECT  2.16 55.755 73.44 56.025 ;
     RECT  2.16 56.295 73.44 56.565 ;
     RECT  2.16 56.835 73.44 57.105 ;
     RECT  2.16 57.375 73.44 57.645 ;
     RECT  2.16 57.915 73.44 58.185 ;
     RECT  2.16 58.455 73.44 58.725 ;
     RECT  2.16 58.995 73.44 59.265 ;
     RECT  2.16 59.535 73.44 59.805 ;
     RECT  2.16 60.075 73.44 60.345 ;
     RECT  2.16 60.615 73.44 60.885 ;
     RECT  2.16 61.155 73.44 61.425 ;
     RECT  2.16 61.695 73.44 61.965 ;
     RECT  2.16 62.235 73.44 62.505 ;
     RECT  2.16 62.775 73.44 63.045 ;
     RECT  2.16 63.315 73.44 63.585 ;
     RECT  2.16 63.855 73.44 64.125 ;
     RECT  2.16 64.395 73.44 64.665 ;
     RECT  2.16 64.935 73.44 65.205 ;
     RECT  2.16 65.475 73.44 65.745 ;
     RECT  2.16 66.015 73.44 66.285 ;
     RECT  2.16 66.555 73.44 66.825 ;
     RECT  2.16 67.095 73.44 67.365 ;
     RECT  2.16 67.635 73.44 67.905 ;
     RECT  2.16 68.175 73.44 68.445 ;
     RECT  2.16 68.715 73.44 68.985 ;
     RECT  2.16 69.255 73.44 69.525 ;
     RECT  2.16 69.795 73.44 70.065 ;
     RECT  2.16 70.335 73.44 70.605 ;
     RECT  2.16 70.875 73.44 71.145 ;
     RECT  2.16 71.415 73.44 71.685 ;
     RECT  2.16 71.955 73.44 72.225 ;
     RECT  2.16 72.495 73.44 72.765 ;
     RECT  2.16 73.035 73.44 73.305 ;
     RECT  2.16 73.575 73.44 73.845 ;
     RECT  2.16 74.115 73.44 74.385 ;
     RECT  2.16 74.655 73.44 74.925 ;
     RECT  2.16 75.195 73.44 75.465 ;
     RECT  2.16 75.735 73.44 76.005 ;
     RECT  2.16 76.275 73.44 76.545 ;
     RECT  2.16 76.815 73.44 77.085 ;
     RECT  2.16 77.355 73.44 77.625 ;
     RECT  2.16 77.895 73.44 78.165 ;
     RECT  2.16 78.435 73.44 78.705 ;
     RECT  2.16 78.975 73.44 79.245 ;
     RECT  2.16 79.515 73.44 79.785 ;
     RECT  2.16 80.055 73.44 80.325 ;
     RECT  2.16 80.595 73.44 80.865 ;
     RECT  2.16 81.135 73.44 81.405 ;
     RECT  2.16 81.675 73.44 81.945 ;
     RECT  2.16 82.215 73.44 82.485 ;
     RECT  2.16 82.755 73.44 83.025 ;
     RECT  2.16 83.295 73.44 83.565 ;
     RECT  2.16 83.835 73.44 84.105 ;
     RECT  2.16 84.375 73.44 84.645 ;
     RECT  2.16 84.915 73.44 85.185 ;
     RECT  2.16 85.455 73.44 85.725 ;
     RECT  2.16 85.995 73.44 86.265 ;
     RECT  2.16 86.535 73.44 86.805 ;
     RECT  2.16 87.075 73.44 87.345 ;
     RECT  2.16 87.615 73.44 87.885 ;
     RECT  2.16 88.155 73.44 88.425 ;
     RECT  2.16 88.695 73.44 88.965 ;
     RECT  2.16 89.235 73.44 89.505 ;
     RECT  2.16 89.775 73.44 90.045 ;
     RECT  2.16 90.315 73.44 90.585 ;
    LAYER M1 ;
     RECT  2.16 2.151 73.44 90.729 ;
    LAYER M2 ;
     RECT  0.463 47.628 0.499 47.646 ;
     RECT  0.211 8.406 0.535 8.424 ;
     RECT  0.211 12.996 0.535 13.014 ;
     RECT  0.211 18.666 0.535 18.684 ;
     RECT  0.499 47.286 0.535 47.646 ;
     RECT  0.499 53.136 0.535 53.154 ;
     RECT  0.211 57.276 0.535 57.294 ;
     RECT  0.499 72.666 0.535 72.684 ;
     RECT  0.211 83.196 0.535 83.214 ;
     RECT  0.211 6.786 2.16 6.804 ;
     RECT  0.535 7.776 2.16 8.766 ;
     RECT  0.535 12.528 2.16 13.464 ;
     RECT  0.535 17.622 2.16 18.684 ;
     RECT  0.535 22.086 2.16 22.104 ;
     RECT  0.535 23.13 2.16 23.148 ;
     RECT  0.211 24.336 2.16 24.354 ;
     RECT  0.535 25.866 2.16 25.884 ;
     RECT  0.535 26.676 2.16 26.694 ;
     RECT  0.535 32.346 2.16 32.364 ;
     RECT  0.211 37.566 2.16 37.584 ;
     RECT  0.211 42.156 2.16 42.174 ;
     RECT  0.211 43.848 2.16 43.866 ;
     RECT  0.535 47.196 2.16 48.186 ;
     RECT  0.211 48.978 2.16 48.996 ;
     RECT  0.535 53.136 2.16 54.054 ;
     RECT  0.535 57.276 2.16 58.554 ;
     RECT  0.211 59.778 2.16 59.796 ;
     RECT  0.211 62.676 2.16 62.694 ;
     RECT  0.211 66.456 2.16 66.474 ;
     RECT  0.211 68.958 2.16 68.976 ;
     RECT  0.535 71.118 2.16 71.136 ;
     RECT  0.535 72.666 2.16 72.756 ;
     RECT  0.211 74.016 2.16 74.034 ;
     RECT  0.211 78.606 2.16 79.704 ;
     RECT  0.211 80.838 2.16 80.856 ;
     RECT  0.535 83.196 2.16 83.664 ;
     RECT  2.16 2.151 55.723 90.729 ;
     RECT  55.723 2.106 56.867 90.729 ;
     RECT  56.867 2.151 73.44 90.729 ;
     RECT  73.44 4.464 73.751 88.794 ;
     RECT  73.751 9.288 73.823 60.138 ;
     RECT  73.751 61.2 73.823 88.794 ;
     RECT  73.823 9.288 74.003 19.836 ;
     RECT  73.823 20.628 74.003 60.138 ;
     RECT  73.823 61.398 74.003 88.794 ;
     RECT  73.751 4.464 74.111 8.496 ;
     RECT  74.003 9.288 74.111 19.026 ;
     RECT  74.003 21.978 74.111 53.856 ;
     RECT  74.003 54.648 74.111 60.138 ;
     RECT  74.003 61.398 74.111 70.866 ;
     RECT  74.003 71.658 74.111 80.316 ;
     RECT  74.003 81.108 74.111 88.794 ;
     RECT  74.111 6.318 74.147 8.496 ;
     RECT  74.111 9.288 74.147 14.976 ;
     RECT  74.111 29.844 74.147 34.956 ;
     RECT  74.111 36.558 74.147 53.01 ;
     RECT  74.111 59.778 74.147 60.138 ;
     RECT  74.111 61.398 74.147 63.846 ;
     RECT  74.111 64.638 74.147 66.276 ;
     RECT  74.111 67.068 74.147 70.866 ;
     RECT  74.111 71.73 74.147 74.646 ;
     RECT  74.111 75.438 74.147 76.068 ;
     RECT  74.111 76.86 74.147 79.776 ;
     RECT  74.111 81.108 74.147 83.052 ;
     RECT  74.111 17.658 74.183 19.026 ;
     RECT  74.147 67.338 74.183 70.866 ;
     RECT  74.147 72 74.183 72.252 ;
     RECT  74.111 84.078 74.183 88.686 ;
     RECT  74.183 84.078 74.435 86.256 ;
     RECT  74.111 21.978 74.543 28.206 ;
     RECT  74.111 4.5 74.579 5.256 ;
     RECT  74.147 7.398 74.579 8.496 ;
     RECT  74.147 10.098 74.579 11.196 ;
     RECT  74.147 11.952 74.579 14.976 ;
     RECT  74.111 15.768 74.579 16.866 ;
     RECT  74.183 17.658 74.579 18.756 ;
     RECT  74.003 19.818 74.579 19.836 ;
     RECT  74.543 21.978 74.579 27.36 ;
     RECT  74.543 28.188 74.579 28.206 ;
     RECT  74.111 28.998 74.579 29.016 ;
     RECT  74.147 29.844 74.579 34.416 ;
     RECT  74.147 36.558 74.579 46.566 ;
     RECT  74.147 47.358 74.579 49.536 ;
     RECT  74.147 50.328 74.579 53.01 ;
     RECT  74.111 54.648 74.579 59.022 ;
     RECT  74.147 59.778 74.579 59.796 ;
     RECT  74.147 61.398 74.579 62.226 ;
     RECT  74.183 67.338 74.579 70.596 ;
     RECT  74.147 73.008 74.579 74.646 ;
     RECT  74.147 75.438 74.579 75.456 ;
     RECT  74.147 77.598 74.579 77.616 ;
     RECT  74.147 78.948 74.579 79.776 ;
     RECT  74.435 84.078 74.579 84.906 ;
     RECT  74.435 85.698 74.579 86.256 ;
     RECT  74.183 87.588 74.579 88.686 ;
     RECT  74.579 36.558 74.615 38.7 ;
     RECT  74.579 4.5 74.651 4.518 ;
     RECT  74.147 6.318 74.651 6.336 ;
     RECT  74.579 7.668 74.651 8.226 ;
     RECT  74.147 9.288 74.651 9.306 ;
     RECT  74.579 11.952 74.651 13.932 ;
     RECT  74.579 14.688 74.651 14.706 ;
     RECT  74.579 16.848 74.651 16.866 ;
     RECT  74.579 18.468 74.651 18.486 ;
     RECT  74.003 20.628 74.651 21.186 ;
     RECT  74.579 22.212 74.651 23.652 ;
     RECT  74.579 24.948 74.651 25.308 ;
     RECT  74.579 26.604 74.651 27.36 ;
     RECT  74.579 31.158 74.651 32.49 ;
     RECT  74.579 33.588 74.651 33.984 ;
     RECT  74.111 35.748 74.651 35.766 ;
     RECT  74.615 36.558 74.651 38.466 ;
     RECT  74.579 39.87 74.651 40.626 ;
     RECT  74.579 43.812 74.651 45.594 ;
     RECT  74.579 48.24 74.651 49.266 ;
     RECT  74.579 51.246 74.651 53.01 ;
     RECT  74.111 53.838 74.651 53.856 ;
     RECT  74.579 55.188 74.651 55.206 ;
     RECT  74.579 55.998 74.651 58.14 ;
     RECT  74.579 61.47 74.651 62.226 ;
     RECT  74.147 63.252 74.651 63.846 ;
     RECT  74.147 64.638 74.651 64.656 ;
     RECT  74.147 65.484 74.651 66.276 ;
     RECT  74.579 67.338 74.651 68.4 ;
     RECT  74.579 73.008 74.651 73.494 ;
     RECT  74.579 74.358 74.651 74.646 ;
     RECT  74.579 78.948 74.651 79.614 ;
     RECT  74.147 81.108 74.651 81.666 ;
     RECT  74.579 85.806 74.651 85.986 ;
     RECT  74.579 87.588 74.651 88.146 ;
     RECT  74.579 11.016 74.687 11.034 ;
     RECT  74.651 12.834 74.687 13.392 ;
     RECT  74.579 16.038 74.687 16.056 ;
     RECT  74.651 20.628 74.687 20.718 ;
     RECT  74.651 23.634 74.687 23.652 ;
     RECT  74.651 25.29 74.687 25.308 ;
     RECT  74.651 26.604 74.687 26.622 ;
     RECT  74.579 29.844 74.687 29.862 ;
     RECT  74.651 31.158 74.687 31.176 ;
     RECT  74.651 36.558 74.687 36.882 ;
     RECT  74.651 37.98 74.687 37.998 ;
     RECT  74.579 41.454 74.687 42.894 ;
     RECT  74.651 44.694 74.687 45.594 ;
     RECT  74.579 46.548 74.687 46.566 ;
     RECT  74.579 47.43 74.687 47.448 ;
     RECT  74.651 48.24 74.687 48.834 ;
     RECT  74.651 51.246 74.687 52.578 ;
     RECT  74.651 55.998 74.687 57.438 ;
     RECT  74.579 59.004 74.687 59.022 ;
     RECT  74.651 61.47 74.687 61.956 ;
     RECT  74.651 65.484 74.687 65.502 ;
     RECT  74.651 67.338 74.687 67.698 ;
     RECT  74.579 69.336 74.687 69.354 ;
     RECT  74.651 73.476 74.687 73.494 ;
     RECT  74.651 74.358 74.687 74.376 ;
     RECT  74.651 79.524 74.687 79.614 ;
     RECT  74.147 83.034 74.687 83.052 ;
     RECT  74.651 85.806 74.687 85.824 ;
     RECT  74.651 87.588 74.687 87.876 ;
     RECT  74.687 36.864 74.723 36.882 ;
     RECT  74.687 41.688 74.723 41.706 ;
     RECT  74.687 44.694 74.723 44.748 ;
     RECT  74.687 57.078 74.723 57.438 ;
     RECT  74.687 61.74 74.723 61.758 ;
     RECT  74.687 67.68 74.723 67.698 ;
     RECT  74.687 79.524 74.723 79.542 ;
     RECT  74.723 44.73 74.759 44.748 ;
     RECT  74.723 57.078 74.759 57.096 ;
     RECT  74.183 72.234 74.759 72.252 ;
    LAYER M3 ;
     RECT  21.06 0.108 21.078 0.173 ;
     RECT  55.728 2.101 55.746 2.143 ;
     RECT  56.844 2.101 56.862 2.143 ;
     RECT  48.315 2.143 48.405 2.191 ;
     RECT  51.015 2.143 51.105 2.191 ;
     RECT  55.728 2.143 56.862 2.191 ;
     RECT  59.115 2.143 59.205 2.191 ;
     RECT  61.815 2.143 61.905 2.191 ;
     RECT  64.515 2.143 64.605 2.191 ;
     RECT  5.115 2.143 5.205 2.227 ;
     RECT  26.715 2.143 26.805 2.227 ;
     RECT  27.828 2.191 27.846 2.227 ;
     RECT  34.815 2.143 34.905 2.227 ;
     RECT  40.215 2.143 40.305 2.227 ;
     RECT  42.915 2.143 43.005 2.227 ;
     RECT  52.74 2.191 52.758 2.227 ;
     RECT  61.815 2.191 62.154 2.227 ;
     RECT  67.215 2.143 67.305 2.227 ;
     RECT  9.54 2.191 9.558 2.24 ;
     RECT  37.515 2.143 37.605 2.24 ;
     RECT  10.515 2.143 10.605 2.251 ;
     RECT  47.232 2.227 47.25 2.251 ;
     RECT  48.315 2.191 48.474 2.251 ;
     RECT  52.74 2.227 52.902 2.251 ;
     RECT  10.44 2.251 10.605 2.263 ;
     RECT  18.615 2.143 18.705 2.263 ;
     RECT  24.015 2.143 24.105 2.263 ;
     RECT  39.744 2.227 40.305 2.263 ;
     RECT  41.688 2.227 43.005 2.263 ;
     RECT  51.015 2.191 51.462 2.263 ;
     RECT  53.715 2.143 53.805 2.263 ;
     RECT  64.515 2.191 65.142 2.263 ;
     RECT  67.215 2.227 67.77 2.263 ;
     RECT  69.156 2.227 69.174 2.263 ;
     RECT  69.915 2.143 70.005 2.263 ;
     RECT  6.12 2.227 6.138 2.299 ;
     RECT  7.815 2.143 7.905 2.299 ;
     RECT  15.915 2.143 16.005 2.299 ;
     RECT  22.896 2.263 22.914 2.299 ;
     RECT  23.94 2.263 24.105 2.299 ;
     RECT  26.715 2.227 27.846 2.299 ;
     RECT  34.272 2.227 34.905 2.299 ;
     RECT  53.715 2.263 54.378 2.299 ;
     RECT  22.896 2.299 24.786 2.335 ;
     RECT  29.415 2.143 29.505 2.335 ;
     RECT  50.724 2.263 51.462 2.335 ;
     RECT  52.236 2.251 52.902 2.335 ;
     RECT  53.715 2.299 54.522 2.335 ;
     RECT  55.728 2.191 56.898 2.335 ;
     RECT  59.115 2.191 59.49 2.335 ;
     RECT  61.272 2.227 62.73 2.335 ;
     RECT  64.332 2.263 65.142 2.335 ;
     RECT  67.104 2.263 67.77 2.335 ;
     RECT  30.708 2.227 30.726 2.347 ;
     RECT  32.115 2.143 32.205 2.347 ;
     RECT  5.115 2.227 5.346 2.371 ;
     RECT  6.12 2.299 6.318 2.371 ;
     RECT  7.815 2.299 8.334 2.371 ;
     RECT  9.396 2.24 9.558 2.371 ;
     RECT  10.44 2.263 10.962 2.371 ;
     RECT  13.215 2.143 13.305 2.371 ;
     RECT  15.588 2.299 16.005 2.371 ;
     RECT  17.676 2.227 17.694 2.371 ;
     RECT  18.504 2.263 18.705 2.371 ;
     RECT  26.46 2.299 27.846 2.371 ;
     RECT  28.584 2.335 29.505 2.371 ;
     RECT  30.24 2.347 30.726 2.371 ;
     RECT  32.115 2.347 32.454 2.371 ;
     RECT  34.272 2.299 35.262 2.371 ;
     RECT  37.515 2.24 38.286 2.371 ;
     RECT  39.348 2.263 40.554 2.371 ;
     RECT  41.616 2.263 43.005 2.371 ;
     RECT  44.136 2.251 44.154 2.371 ;
     RECT  45.615 2.143 45.705 2.371 ;
     RECT  46.908 2.251 47.25 2.371 ;
     RECT  48.024 2.251 48.474 2.371 ;
     RECT  50.724 2.335 54.522 2.371 ;
     RECT  55.476 2.335 56.898 2.371 ;
     RECT  57.852 2.203 57.87 2.371 ;
     RECT  59.115 2.335 59.706 2.371 ;
     RECT  67.068 2.335 67.77 2.371 ;
     RECT  69.156 2.263 70.005 2.371 ;
     RECT  2.415 2.143 2.505 2.413 ;
     RECT  15.048 2.371 16.005 2.413 ;
     RECT  17.28 2.371 18.705 2.413 ;
     RECT  21.315 2.143 21.405 2.413 ;
     RECT  26.46 2.371 29.505 2.413 ;
     RECT  30.24 2.371 32.454 2.413 ;
     RECT  37.515 2.371 43.074 2.413 ;
     RECT  45.108 2.371 45.705 2.413 ;
     RECT  67.068 2.371 70.005 2.413 ;
     RECT  72.615 2.143 72.705 2.413 ;
     RECT  61.128 2.335 62.73 2.443 ;
     RECT  13.215 2.371 13.986 2.461 ;
     RECT  15.048 2.413 16.197 2.461 ;
     RECT  21.315 2.413 21.597 2.461 ;
     RECT  46.908 2.371 48.87 2.461 ;
     RECT  64.188 2.335 65.142 2.461 ;
     RECT  17.28 2.413 18.897 2.488 ;
     RECT  5.115 2.371 6.39 2.491 ;
     RECT  67.068 2.413 70.197 2.491 ;
     RECT  15.048 2.461 16.254 2.497 ;
     RECT  17.28 2.488 19.17 2.497 ;
     RECT  55.476 2.371 59.706 2.497 ;
     RECT  60.552 2.443 62.73 2.497 ;
     RECT  37.515 2.413 43.197 2.525 ;
     RECT  55.476 2.497 62.73 2.533 ;
     RECT  66.996 2.491 70.197 2.533 ;
     RECT  44.136 2.371 44.334 2.569 ;
     RECT  45.108 2.413 45.897 2.569 ;
     RECT  55.476 2.533 63.342 2.569 ;
     RECT  5.115 2.491 6.462 2.605 ;
     RECT  7.74 2.371 8.334 2.605 ;
     RECT  9.396 2.371 11.79 2.605 ;
     RECT  21.276 2.461 21.597 2.605 ;
     RECT  37.515 2.525 38.574 2.605 ;
     RECT  39.312 2.525 43.197 2.605 ;
     RECT  55.404 2.569 63.342 2.605 ;
     RECT  64.188 2.461 65.322 2.605 ;
     RECT  66.492 2.533 70.197 2.605 ;
     RECT  5.115 2.605 6.57 2.641 ;
     RECT  7.74 2.605 8.586 2.641 ;
     RECT  9.396 2.605 12.366 2.641 ;
     RECT  13.215 2.461 14.058 2.641 ;
     RECT  15.048 2.497 19.17 2.641 ;
     RECT  22.824 2.335 24.786 2.641 ;
     RECT  26.46 2.413 32.454 2.641 ;
     RECT  33.3 2.299 33.318 2.641 ;
     RECT  34.272 2.371 36.126 2.641 ;
     RECT  37.08 2.605 38.574 2.641 ;
     RECT  39.312 2.605 43.218 2.641 ;
     RECT  44.136 2.569 45.897 2.641 ;
     RECT  46.908 2.461 49.302 2.641 ;
     RECT  50.292 2.371 54.666 2.641 ;
     RECT  55.404 2.605 63.414 2.641 ;
     RECT  72.615 2.413 72.897 2.641 ;
     RECT  5.115 2.641 6.642 2.731 ;
     RECT  7.416 2.641 19.746 2.731 ;
     RECT  50.292 2.641 63.414 2.767 ;
     RECT  64.188 2.605 70.197 2.767 ;
     RECT  5.115 2.731 19.746 2.803 ;
     RECT  20.664 2.605 21.798 2.803 ;
     RECT  50.292 2.767 70.197 2.803 ;
     RECT  22.824 2.641 25.722 2.839 ;
     RECT  26.46 2.641 38.574 2.839 ;
     RECT  5.115 2.803 21.798 2.911 ;
     RECT  39.312 2.641 49.302 2.911 ;
     RECT  50.292 2.803 70.83 2.911 ;
     RECT  5.115 2.911 21.906 3.145 ;
     RECT  22.824 2.839 38.574 3.145 ;
     RECT  50.292 2.911 70.866 3.145 ;
     RECT  39.312 2.911 49.374 3.181 ;
     RECT  50.292 3.145 71.154 3.181 ;
     RECT  5.115 3.145 38.574 3.271 ;
     RECT  39.312 3.181 71.154 3.271 ;
     RECT  4.824 3.271 71.154 3.343 ;
     RECT  4.572 3.343 71.154 3.577 ;
     RECT  4.572 3.577 71.262 3.685 ;
     RECT  72 2.641 72.897 3.685 ;
     RECT  2.415 2.413 2.697 3.979 ;
     RECT  3.492 3.955 3.51 3.979 ;
     RECT  2.415 3.979 3.51 3.991 ;
     RECT  4.572 3.685 72.897 3.991 ;
     RECT  2.415 3.991 72.897 4.423 ;
     RECT  74.088 4.411 74.106 4.487 ;
     RECT  2.415 4.423 72.954 4.555 ;
     RECT  74.556 4.495 74.646 4.589 ;
     RECT  2.304 4.555 72.954 4.891 ;
     RECT  73.692 4.747 73.71 4.891 ;
     RECT  2.304 4.891 73.71 4.919 ;
     RECT  72.072 4.919 73.71 4.928 ;
     RECT  74.556 4.589 74.574 5.261 ;
     RECT  72.396 4.928 73.71 5.371 ;
     RECT  2.304 4.919 71.154 5.701 ;
     RECT  72.396 5.371 73.746 5.701 ;
     RECT  2.304 5.701 73.746 5.707 ;
     RECT  2.304 5.707 74.106 6.313 ;
     RECT  2.304 6.313 74.646 6.413 ;
     RECT  2.304 6.413 74.574 6.719 ;
     RECT  2.304 6.719 73.818 6.845 ;
     RECT  0.216 6.781 0.234 6.893 ;
     RECT  74.556 6.719 74.574 7.339 ;
     RECT  2.304 6.845 73.026 7.675 ;
     RECT  73.8 6.845 73.818 7.675 ;
     RECT  2.304 7.675 73.818 7.867 ;
     RECT  74.556 7.339 74.646 7.867 ;
     RECT  2.304 7.867 74.646 7.961 ;
     RECT  74.556 7.961 74.646 8.231 ;
     RECT  2.304 7.961 73.674 8.381 ;
     RECT  0.54 7.771 0.558 8.401 ;
     RECT  74.556 8.231 74.574 8.501 ;
     RECT  2.412 8.381 73.674 8.683 ;
     RECT  0.216 8.401 0.558 8.717 ;
     RECT  0.54 8.717 0.558 9.197 ;
     RECT  74.628 9.283 74.646 9.341 ;
     RECT  2.412 8.683 73.746 9.499 ;
     RECT  2.412 9.499 74.574 9.643 ;
     RECT  0.216 10.699 0.234 10.829 ;
     RECT  2.304 9.643 74.574 10.939 ;
     RECT  2.304 10.939 74.682 11.039 ;
     RECT  2.304 11.039 74.646 11.813 ;
     RECT  74.628 11.813 74.646 12.091 ;
     RECT  2.304 11.813 73.674 12.181 ;
     RECT  2.268 12.181 73.674 12.461 ;
     RECT  74.628 12.091 74.682 12.571 ;
     RECT  0.54 12.523 0.558 12.605 ;
     RECT  2.304 12.461 73.674 13.085 ;
     RECT  2.412 13.085 73.674 13.099 ;
     RECT  74.556 12.571 74.682 13.099 ;
     RECT  0.216 12.991 0.234 13.133 ;
     RECT  2.412 13.099 74.682 13.361 ;
     RECT  74.556 13.361 74.682 13.397 ;
     RECT  2.412 13.361 73.818 13.915 ;
     RECT  0.54 13.441 0.558 13.949 ;
     RECT  2.268 13.915 73.818 14.093 ;
     RECT  2.304 14.093 73.818 14.243 ;
     RECT  74.556 13.397 74.646 14.711 ;
     RECT  2.304 14.243 73.746 15.019 ;
     RECT  74.556 14.711 74.574 15.019 ;
     RECT  2.304 15.019 74.574 15.323 ;
     RECT  73.656 15.323 74.574 15.835 ;
     RECT  73.656 15.835 74.682 16.061 ;
     RECT  2.304 15.323 72.897 16.141 ;
     RECT  73.656 16.061 74.646 16.141 ;
     RECT  2.304 16.141 74.646 16.295 ;
     RECT  68.58 16.295 74.646 16.871 ;
     RECT  2.304 16.295 67.842 17.041 ;
     RECT  68.58 16.871 74.574 17.041 ;
     RECT  0.54 17.617 0.558 17.803 ;
     RECT  0.216 17.803 0.558 17.933 ;
     RECT  2.304 17.041 74.574 18.173 ;
     RECT  74.16 18.173 74.574 18.331 ;
     RECT  0.54 17.933 0.558 18.365 ;
     RECT  74.16 18.331 74.646 18.491 ;
     RECT  74.16 18.491 74.574 18.761 ;
     RECT  0.216 18.661 0.234 18.845 ;
     RECT  2.304 18.173 73.314 18.869 ;
     RECT  11.916 18.869 73.314 18.955 ;
     RECT  74.16 18.761 74.178 18.955 ;
     RECT  11.916 18.955 74.178 19.031 ;
     RECT  11.916 19.031 73.998 19.571 ;
     RECT  2.304 18.869 11.178 19.651 ;
     RECT  11.916 19.571 73.818 19.651 ;
     RECT  74.556 19.771 74.574 19.841 ;
     RECT  2.304 19.651 73.818 20.687 ;
     RECT  74.664 20.443 74.682 20.779 ;
     RECT  2.304 20.687 73.71 21.595 ;
     RECT  74.556 20.779 74.682 21.595 ;
     RECT  2.304 21.595 74.682 21.965 ;
     RECT  0.54 22.081 0.558 22.253 ;
     RECT  2.304 21.965 74.646 22.541 ;
     RECT  74.628 22.541 74.646 22.891 ;
     RECT  0.54 23.125 0.558 23.227 ;
     RECT  0.252 23.227 0.558 23.357 ;
     RECT  74.628 22.891 74.682 23.371 ;
     RECT  0.54 23.357 0.558 23.405 ;
     RECT  2.304 22.541 73.746 23.563 ;
     RECT  74.556 23.371 74.682 23.563 ;
     RECT  2.304 23.563 74.682 23.657 ;
     RECT  2.304 23.657 74.574 23.693 ;
     RECT  74.412 23.693 74.574 23.891 ;
     RECT  74.52 23.891 74.574 24.431 ;
     RECT  2.304 23.693 73.674 24.503 ;
     RECT  74.556 24.431 74.574 24.523 ;
     RECT  0.216 24.331 0.234 24.557 ;
     RECT  74.556 24.523 74.646 25.003 ;
     RECT  74.556 25.003 74.682 25.313 ;
     RECT  2.304 24.503 73.386 25.339 ;
     RECT  2.304 25.339 73.638 25.583 ;
     RECT  2.304 25.583 38.106 25.619 ;
     RECT  38.916 25.583 73.638 26.011 ;
     RECT  74.556 25.313 74.574 26.011 ;
     RECT  38.916 26.011 74.574 26.155 ;
     RECT  2.412 25.619 38.106 26.401 ;
     RECT  38.916 26.155 74.682 26.401 ;
     RECT  2.412 26.401 74.682 26.627 ;
     RECT  2.412 26.627 74.646 26.825 ;
     RECT  0.54 25.861 0.558 26.861 ;
     RECT  2.412 26.825 73.818 26.941 ;
     RECT  1.152 26.971 1.17 27.101 ;
     RECT  2.304 26.941 73.818 27.203 ;
     RECT  74.628 26.825 74.646 27.365 ;
     RECT  74.556 27.643 74.574 27.787 ;
     RECT  2.304 27.203 73.782 27.979 ;
     RECT  74.52 27.787 74.574 27.979 ;
     RECT  2.304 27.979 74.574 28.211 ;
     RECT  2.304 28.211 74.106 28.939 ;
     RECT  2.304 28.939 74.574 28.973 ;
     RECT  2.412 28.973 74.574 29.219 ;
     RECT  0.252 29.131 0.27 29.261 ;
     RECT  73.656 29.219 74.574 29.419 ;
     RECT  2.412 29.219 72.897 29.731 ;
     RECT  73.656 29.419 74.682 29.867 ;
     RECT  73.656 29.867 74.574 29.903 ;
     RECT  73.656 29.903 73.674 30.137 ;
     RECT  2.304 29.731 72.897 30.235 ;
     RECT  0.252 30.763 0.27 30.893 ;
     RECT  2.304 30.235 73.602 30.907 ;
     RECT  2.304 30.907 73.674 31.037 ;
     RECT  52.776 31.037 73.674 31.051 ;
     RECT  74.412 29.903 74.574 31.051 ;
     RECT  2.304 31.037 52.002 31.109 ;
     RECT  52.776 31.051 74.574 31.109 ;
     RECT  52.92 31.109 74.574 31.153 ;
     RECT  2.304 31.109 51.966 31.181 ;
     RECT  52.92 31.153 74.682 31.181 ;
     RECT  52.992 31.181 74.682 31.253 ;
     RECT  0.216 31.147 0.234 31.277 ;
     RECT  74.556 31.253 74.682 31.613 ;
     RECT  2.304 31.181 51.93 31.927 ;
     RECT  2.304 31.927 52.074 32.071 ;
     RECT  52.992 31.253 73.674 32.071 ;
     RECT  2.304 32.071 73.674 32.459 ;
     RECT  74.556 31.613 74.646 32.495 ;
     RECT  0.54 32.341 0.558 32.573 ;
     RECT  27.972 32.459 73.674 32.683 ;
     RECT  74.556 32.495 74.574 32.683 ;
     RECT  27.972 32.683 74.574 32.909 ;
     RECT  2.304 32.459 27.09 33.313 ;
     RECT  27.972 32.909 73.314 33.313 ;
     RECT  74.052 32.909 74.574 33.355 ;
     RECT  74.052 33.355 74.646 33.449 ;
     RECT  2.304 33.313 73.314 33.691 ;
     RECT  74.556 33.449 74.646 33.989 ;
     RECT  74.556 33.989 74.574 34.421 ;
     RECT  2.304 33.691 73.71 34.507 ;
     RECT  2.304 34.507 74.142 34.591 ;
     RECT  2.196 34.591 74.142 34.685 ;
     RECT  2.304 34.685 74.142 35.323 ;
     RECT  2.304 35.323 74.646 36.139 ;
     RECT  2.304 36.139 74.682 36.383 ;
     RECT  74.124 36.383 74.682 36.475 ;
     RECT  2.304 36.383 73.314 36.509 ;
     RECT  74.124 36.475 74.718 36.887 ;
     RECT  74.124 36.887 74.682 37.147 ;
     RECT  74.088 37.147 74.682 37.193 ;
     RECT  0.252 37.291 0.27 37.421 ;
     RECT  2.304 36.509 73.026 37.471 ;
     RECT  2.304 37.471 73.098 37.625 ;
     RECT  0.216 37.561 0.234 37.661 ;
     RECT  74.124 37.193 74.682 37.963 ;
     RECT  73.728 37.963 74.682 38.003 ;
     RECT  2.304 37.625 72.918 38.435 ;
     RECT  73.728 38.003 74.646 38.471 ;
     RECT  3.852 38.435 72.918 38.587 ;
     RECT  73.728 38.471 74.61 38.705 ;
     RECT  2.304 38.435 3.078 38.849 ;
     RECT  3.852 38.587 72.99 38.923 ;
     RECT  73.728 38.705 74.574 38.923 ;
     RECT  0.252 38.923 0.27 39.053 ;
     RECT  3.852 38.923 74.574 39.083 ;
     RECT  3.852 39.083 73.818 39.289 ;
     RECT  3.744 39.289 73.818 39.389 ;
     RECT  74.556 39.083 74.574 39.551 ;
     RECT  3.744 39.389 68.634 39.631 ;
     RECT  2.304 38.849 2.826 39.691 ;
     RECT  3.6 39.631 68.634 39.691 ;
     RECT  74.628 39.865 74.646 39.883 ;
     RECT  74.628 39.883 74.718 40.013 ;
     RECT  69.408 39.389 73.818 40.163 ;
     RECT  2.304 39.691 68.634 40.261 ;
     RECT  69.408 40.163 73.746 40.261 ;
     RECT  74.628 40.013 74.646 40.699 ;
     RECT  2.304 40.261 73.746 40.703 ;
     RECT  0.252 40.699 0.27 40.877 ;
     RECT  74.556 40.699 74.646 40.891 ;
     RECT  2.304 40.703 73.71 40.901 ;
     RECT  74.556 40.891 74.682 41.171 ;
     RECT  74.628 41.171 74.682 41.371 ;
     RECT  2.304 40.901 72.918 41.683 ;
     RECT  73.692 40.901 73.71 41.683 ;
     RECT  74.628 41.371 74.718 41.711 ;
     RECT  2.304 41.683 73.71 42.187 ;
     RECT  74.628 41.711 74.682 42.187 ;
     RECT  0.216 42.151 0.234 42.221 ;
     RECT  2.304 42.187 74.682 42.571 ;
     RECT  2.268 42.571 74.682 42.701 ;
     RECT  2.304 42.701 74.682 42.755 ;
     RECT  74.412 42.755 74.682 42.899 ;
     RECT  0.396 42.859 0.414 43.003 ;
     RECT  0.216 43.003 0.414 43.037 ;
     RECT  2.304 42.755 73.602 43.637 ;
     RECT  74.412 42.899 74.574 43.672 ;
     RECT  74.088 43.672 74.574 43.709 ;
     RECT  74.628 43.807 74.646 44.011 ;
     RECT  0.216 43.037 0.234 44.491 ;
     RECT  2.304 43.637 73.242 44.491 ;
     RECT  0.216 44.491 0.414 44.669 ;
     RECT  74.628 44.011 74.754 44.753 ;
     RECT  0.216 44.669 0.234 44.765 ;
     RECT  74.628 44.753 74.682 44.971 ;
     RECT  2.304 44.491 73.746 45.115 ;
     RECT  2.304 45.115 73.818 45.491 ;
     RECT  74.556 44.971 74.682 45.677 ;
     RECT  2.304 45.491 71.226 46.309 ;
     RECT  2.304 46.309 71.298 46.381 ;
     RECT  72.072 45.491 73.818 46.381 ;
     RECT  74.556 45.677 74.574 46.459 ;
     RECT  2.304 46.381 73.818 46.603 ;
     RECT  74.556 46.459 74.682 46.603 ;
     RECT  2.304 46.603 74.682 47.117 ;
     RECT  0.54 47.191 0.558 47.281 ;
     RECT  2.412 47.117 74.682 47.357 ;
     RECT  0.504 47.281 0.558 47.623 ;
     RECT  2.415 47.357 74.682 47.723 ;
     RECT  2.415 47.723 73.062 48.091 ;
     RECT  2.304 48.091 73.062 48.541 ;
     RECT  0.468 47.623 0.558 48.605 ;
     RECT  74.088 47.723 74.682 48.839 ;
     RECT  2.304 48.541 73.134 48.973 ;
     RECT  2.268 48.973 73.134 49.051 ;
     RECT  74.088 48.839 74.646 49.051 ;
     RECT  0.216 48.973 0.234 49.085 ;
     RECT  2.268 49.051 74.646 49.109 ;
     RECT  2.304 49.109 74.646 49.271 ;
     RECT  2.304 49.271 74.574 49.883 ;
     RECT  2.304 49.883 73.818 50.009 ;
     RECT  33.876 50.009 73.818 50.153 ;
     RECT  33.876 50.153 73.746 50.549 ;
     RECT  2.304 50.009 33.102 50.899 ;
     RECT  33.876 50.549 49.014 50.899 ;
     RECT  74.556 49.883 74.574 51.211 ;
     RECT  49.752 50.549 73.746 51.233 ;
     RECT  74.556 51.211 74.682 51.355 ;
     RECT  49.752 51.233 73.242 51.359 ;
     RECT  2.304 50.899 49.014 51.367 ;
     RECT  49.752 51.359 73.134 51.367 ;
     RECT  2.304 51.367 73.134 51.431 ;
     RECT  22.32 51.431 73.134 52.171 ;
     RECT  73.98 51.355 74.682 52.171 ;
     RECT  2.304 51.431 21.597 52.213 ;
     RECT  22.32 52.171 74.682 52.213 ;
     RECT  2.304 52.213 74.682 52.843 ;
     RECT  2.268 52.843 74.682 53.165 ;
     RECT  0.504 53.131 0.522 53.293 ;
     RECT  2.268 53.165 74.646 53.501 ;
     RECT  2.268 53.501 73.062 53.699 ;
     RECT  73.8 53.501 74.646 53.861 ;
     RECT  0.504 53.293 0.558 54.029 ;
     RECT  0.54 54.029 0.558 54.173 ;
     RECT  73.8 53.861 74.574 54.473 ;
     RECT  2.304 53.699 73.062 54.509 ;
     RECT  2.304 54.509 72.954 54.635 ;
     RECT  49.644 54.635 72.954 54.707 ;
     RECT  74.088 54.473 74.574 54.811 ;
     RECT  74.088 54.811 74.646 55.291 ;
     RECT  73.656 55.291 74.646 55.553 ;
     RECT  2.304 54.635 48.906 55.627 ;
     RECT  2.232 55.627 48.906 55.651 ;
     RECT  49.644 54.707 72.897 55.651 ;
     RECT  2.232 55.651 72.897 55.751 ;
     RECT  73.692 55.553 74.646 55.771 ;
     RECT  73.692 55.771 74.682 55.823 ;
     RECT  73.692 55.823 73.818 56.093 ;
     RECT  73.692 56.093 73.71 56.363 ;
     RECT  2.304 55.751 72.897 56.587 ;
     RECT  2.304 56.587 73.026 56.731 ;
     RECT  2.232 56.731 73.026 56.831 ;
     RECT  74.556 55.823 74.682 56.923 ;
     RECT  74.556 56.923 74.718 57.067 ;
     RECT  74.556 57.067 74.754 57.107 ;
     RECT  74.556 57.107 74.718 57.259 ;
     RECT  2.268 56.831 73.026 57.307 ;
     RECT  2.268 57.307 73.242 57.371 ;
     RECT  74.124 57.259 74.718 57.443 ;
     RECT  74.124 57.443 74.646 57.547 ;
     RECT  2.304 57.371 73.242 57.569 ;
     RECT  74.088 57.547 74.646 57.713 ;
     RECT  2.304 57.569 72.897 57.875 ;
     RECT  0.216 57.271 0.234 57.917 ;
     RECT  18.216 57.875 72.897 58.411 ;
     RECT  73.656 57.739 73.674 58.411 ;
     RECT  74.556 57.713 74.646 58.555 ;
     RECT  2.304 57.875 17.442 58.651 ;
     RECT  18.216 58.411 73.674 58.651 ;
     RECT  2.304 58.651 73.674 58.693 ;
     RECT  74.556 58.555 74.682 58.693 ;
     RECT  0.54 57.991 0.558 58.733 ;
     RECT  2.304 58.693 74.682 59.027 ;
     RECT  0.252 59.371 0.27 59.501 ;
     RECT  2.304 59.027 74.574 59.801 ;
     RECT  0.216 59.773 0.234 59.885 ;
     RECT  2.304 59.801 74.142 60.043 ;
     RECT  2.196 60.043 74.142 60.143 ;
     RECT  2.196 60.143 73.818 60.179 ;
     RECT  2.232 60.179 73.818 60.611 ;
     RECT  2.268 60.611 73.818 60.683 ;
     RECT  2.268 60.683 73.026 60.719 ;
     RECT  74.556 60.859 74.574 61.003 ;
     RECT  2.268 60.719 71.838 61.079 ;
     RECT  73.8 60.683 73.818 61.223 ;
     RECT  74.556 61.003 74.682 61.339 ;
     RECT  2.304 61.079 71.838 61.349 ;
     RECT  72.576 60.719 73.026 61.421 ;
     RECT  74.556 61.339 74.718 61.483 ;
     RECT  0.252 61.387 0.27 61.517 ;
     RECT  72.576 61.421 72.897 61.591 ;
     RECT  74.124 61.483 74.718 61.763 ;
     RECT  2.304 61.349 71.262 61.889 ;
     RECT  2.304 61.889 42.066 61.925 ;
     RECT  74.124 61.763 74.682 61.961 ;
     RECT  74.124 61.961 74.646 61.963 ;
     RECT  42.876 61.889 71.262 62.107 ;
     RECT  72.072 61.591 72.897 62.107 ;
     RECT  73.692 61.963 74.646 62.231 ;
     RECT  42.876 62.107 72.897 62.311 ;
     RECT  73.692 62.231 74.142 62.311 ;
     RECT  0.252 62.539 0.27 62.668 ;
     RECT  0.216 62.668 0.27 62.669 ;
     RECT  2.304 61.925 41.994 62.707 ;
     RECT  42.876 62.311 74.142 62.707 ;
     RECT  0.216 62.669 0.234 62.861 ;
     RECT  2.304 62.707 74.142 63.115 ;
     RECT  2.304 63.115 74.646 63.851 ;
     RECT  2.304 63.851 74.106 64.603 ;
     RECT  2.304 64.603 74.646 64.741 ;
     RECT  2.268 64.741 74.646 64.781 ;
     RECT  2.304 64.781 74.646 64.939 ;
     RECT  2.304 64.939 74.682 64.967 ;
     RECT  20.484 64.967 74.682 65.309 ;
     RECT  74.628 65.309 74.682 65.507 ;
     RECT  2.304 64.967 19.71 65.749 ;
     RECT  20.484 65.309 73.71 65.749 ;
     RECT  2.304 65.749 73.71 65.849 ;
     RECT  72.036 65.849 73.71 66.011 ;
     RECT  2.304 65.849 71.298 66.209 ;
     RECT  72.072 66.011 73.71 66.571 ;
     RECT  74.628 65.507 74.646 66.571 ;
     RECT  0.216 65.899 0.234 66.749 ;
     RECT  72.072 66.571 74.646 66.893 ;
     RECT  74.124 66.893 74.646 66.907 ;
     RECT  72.072 66.893 73.026 67.091 ;
     RECT  74.124 66.907 74.682 67.243 ;
     RECT  2.304 66.209 71.262 67.261 ;
     RECT  72.072 67.091 72.897 67.261 ;
     RECT  74.124 67.243 74.718 67.703 ;
     RECT  74.124 67.703 74.646 67.723 ;
     RECT  2.304 67.261 72.897 67.981 ;
     RECT  2.304 67.981 73.242 68.059 ;
     RECT  74.088 67.723 74.646 68.059 ;
     RECT  2.304 68.059 74.646 68.237 ;
     RECT  74.556 68.237 74.646 68.405 ;
     RECT  2.304 68.237 73.566 68.783 ;
     RECT  2.304 68.783 73.242 68.819 ;
     RECT  2.304 68.819 73.134 68.909 ;
     RECT  0.216 68.953 0.234 69.053 ;
     RECT  74.556 68.405 74.574 69.163 ;
     RECT  2.304 68.909 72.99 69.251 ;
     RECT  73.98 69.163 74.574 69.331 ;
     RECT  73.98 69.331 74.682 69.725 ;
     RECT  73.98 69.725 74.574 69.791 ;
     RECT  2.304 69.251 72.954 69.979 ;
     RECT  74.124 69.791 74.574 70.601 ;
     RECT  2.304 69.979 73.026 70.651 ;
     RECT  74.124 70.601 74.178 70.651 ;
     RECT  2.304 70.651 74.178 70.709 ;
     RECT  72.324 70.709 74.178 70.871 ;
     RECT  72.324 70.871 74.142 70.943 ;
     RECT  0.54 71.113 0.558 71.357 ;
     RECT  2.304 70.709 71.442 71.491 ;
     RECT  72.324 70.943 72.99 71.491 ;
     RECT  73.728 70.943 74.142 71.659 ;
     RECT  2.304 71.491 72.99 71.761 ;
     RECT  73.728 71.659 74.178 71.761 ;
     RECT  2.304 71.761 74.178 71.788 ;
     RECT  2.268 71.788 74.178 71.803 ;
     RECT  2.268 71.803 74.682 71.879 ;
     RECT  2.304 71.879 74.682 71.947 ;
     RECT  2.304 71.947 74.754 72.257 ;
     RECT  0.504 72.661 0.522 72.733 ;
     RECT  0.504 72.733 0.558 72.989 ;
     RECT  0.504 72.989 0.522 73.133 ;
     RECT  2.304 72.257 74.646 73.409 ;
     RECT  74.088 73.409 74.646 73.435 ;
     RECT  74.088 73.435 74.682 73.499 ;
     RECT  0.216 74.011 0.234 74.141 ;
     RECT  74.088 73.499 74.574 74.251 ;
     RECT  74.088 74.251 74.682 74.381 ;
     RECT  2.304 73.409 72.897 74.587 ;
     RECT  74.088 74.381 74.646 74.587 ;
     RECT  2.304 74.587 74.646 74.621 ;
     RECT  2.412 74.621 74.646 74.651 ;
     RECT  0.216 75.067 0.234 75.197 ;
     RECT  2.412 74.651 74.574 75.389 ;
     RECT  58.32 75.389 74.574 75.461 ;
     RECT  58.32 75.461 74.142 75.533 ;
     RECT  2.412 75.389 57.582 75.547 ;
     RECT  58.356 75.533 74.142 75.767 ;
     RECT  58.356 75.767 71.766 76.199 ;
     RECT  2.304 75.547 57.582 76.315 ;
     RECT  58.356 76.199 71.586 76.315 ;
     RECT  0.216 76.363 0.234 76.493 ;
     RECT  72.612 75.767 74.142 76.621 ;
     RECT  2.304 76.315 71.586 76.981 ;
     RECT  72.432 76.621 74.142 76.981 ;
     RECT  2.304 76.981 74.142 77.081 ;
     RECT  2.304 77.081 73.71 77.423 ;
     RECT  2.304 77.423 32.562 77.521 ;
     RECT  74.556 77.179 74.574 77.621 ;
     RECT  2.268 77.521 32.562 77.741 ;
     RECT  33.336 77.423 73.71 77.851 ;
     RECT  2.304 77.741 32.562 78.205 ;
     RECT  33.336 77.851 74.142 78.205 ;
     RECT  2.304 78.205 74.142 78.665 ;
     RECT  74.556 78.667 74.646 78.811 ;
     RECT  74.556 78.811 74.718 79.547 ;
     RECT  74.556 79.547 74.682 79.853 ;
     RECT  2.304 78.665 73.746 79.963 ;
     RECT  0.216 78.601 0.234 79.997 ;
     RECT  2.304 79.963 73.818 80.155 ;
     RECT  2.304 80.155 74.106 80.591 ;
     RECT  0.216 80.833 0.234 80.971 ;
     RECT  0.216 80.971 0.27 81.197 ;
     RECT  0.216 81.197 0.234 81.485 ;
     RECT  2.304 80.591 73.818 81.595 ;
     RECT  74.628 80.779 74.646 81.595 ;
     RECT  2.304 81.595 74.646 81.671 ;
     RECT  2.304 81.671 74.142 81.905 ;
     RECT  2.304 81.905 41.886 82.588 ;
     RECT  42.696 81.905 74.142 82.603 ;
     RECT  2.268 82.588 41.886 82.679 ;
     RECT  42.696 82.603 74.682 83.057 ;
     RECT  2.304 82.679 41.886 83.065 ;
     RECT  42.696 83.057 74.574 83.065 ;
     RECT  0.216 83.191 0.234 83.261 ;
     RECT  2.304 83.065 74.574 83.561 ;
     RECT  2.304 83.561 73.818 83.633 ;
     RECT  2.304 83.633 73.782 83.669 ;
     RECT  0.54 83.641 0.558 83.933 ;
     RECT  2.304 83.669 73.71 84.181 ;
     RECT  2.268 84.181 73.71 84.272 ;
     RECT  74.556 83.561 74.574 84.37 ;
     RECT  2.304 84.272 73.71 84.712 ;
     RECT  74.52 84.37 74.574 84.712 ;
     RECT  2.304 84.712 74.574 85.085 ;
     RECT  2.412 85.085 74.574 85.451 ;
     RECT  74.556 85.451 74.574 85.531 ;
     RECT  74.556 85.531 74.646 85.723 ;
     RECT  74.556 85.723 74.682 85.829 ;
     RECT  2.412 85.451 73.746 85.867 ;
     RECT  74.556 85.829 74.646 85.991 ;
     RECT  2.304 85.867 73.746 86.063 ;
     RECT  74.556 85.991 74.574 86.203 ;
     RECT  73.98 86.203 74.574 86.261 ;
     RECT  2.304 86.063 73.062 86.827 ;
     RECT  73.98 86.261 74.178 86.827 ;
     RECT  2.304 86.827 74.178 87.035 ;
     RECT  60.192 87.035 74.178 87.071 ;
     RECT  72.615 87.071 74.178 87.163 ;
     RECT  72.615 87.163 74.682 87.413 ;
     RECT  2.304 87.035 59.454 87.781 ;
     RECT  60.192 87.071 71.874 87.781 ;
     RECT  74.556 87.413 74.682 87.881 ;
     RECT  2.304 87.781 71.874 87.961 ;
     RECT  72.615 87.413 73.602 87.961 ;
     RECT  74.556 87.881 74.646 88.151 ;
     RECT  2.304 87.961 73.602 88.171 ;
     RECT  74.556 88.151 74.574 88.171 ;
     RECT  2.304 88.171 74.574 88.619 ;
     RECT  2.415 88.619 74.574 88.655 ;
     RECT  3.924 88.655 74.574 88.691 ;
     RECT  3.924 88.691 74.106 88.763 ;
     RECT  4.572 88.763 73.026 88.799 ;
     RECT  74.088 88.763 74.106 88.799 ;
     RECT  4.572 88.799 71.298 88.889 ;
     RECT  72.615 88.799 73.026 88.889 ;
     RECT  71.28 88.889 71.298 88.925 ;
     RECT  4.572 88.889 70.218 89.465 ;
     RECT  64.224 89.465 70.218 89.501 ;
     RECT  4.572 89.465 63.45 89.843 ;
     RECT  4.572 89.843 19.494 89.851 ;
     RECT  64.296 89.501 70.218 89.851 ;
     RECT  4.5 89.851 19.494 89.969 ;
     RECT  20.268 89.843 63.45 89.969 ;
     RECT  52.056 89.969 63.378 90.005 ;
     RECT  52.92 90.005 63.378 90.077 ;
     RECT  4.5 89.969 19.422 90.149 ;
     RECT  4.5 90.149 9.558 90.235 ;
     RECT  4.356 90.235 9.558 90.239 ;
     RECT  10.332 90.149 19.422 90.239 ;
     RECT  20.268 89.969 51.297 90.239 ;
     RECT  52.056 90.005 52.074 90.239 ;
     RECT  56.016 90.077 63.378 90.239 ;
     RECT  64.296 89.851 70.362 90.239 ;
     RECT  9.252 90.239 9.378 90.275 ;
     RECT  20.268 90.239 22.446 90.275 ;
     RECT  23.328 90.239 30.438 90.275 ;
     RECT  31.536 90.239 46.17 90.275 ;
     RECT  47.34 90.239 49.518 90.275 ;
     RECT  59.115 90.239 63.234 90.275 ;
     RECT  66.528 90.239 70.254 90.275 ;
     RECT  56.016 90.239 58.374 90.317 ;
     RECT  10.332 90.239 19.386 90.347 ;
     RECT  20.772 90.275 22.446 90.347 ;
     RECT  39.96 90.275 46.17 90.347 ;
     RECT  31.536 90.275 39.186 90.383 ;
     RECT  47.34 90.275 49.266 90.383 ;
     RECT  64.296 90.239 65.538 90.391 ;
     RECT  10.332 90.347 19.062 90.419 ;
     RECT  21.06 90.347 22.446 90.419 ;
     RECT  37.476 90.383 39.186 90.419 ;
     RECT  39.996 90.347 46.17 90.419 ;
     RECT  2.415 88.655 2.697 90.467 ;
     RECT  12.06 90.419 18.897 90.467 ;
     RECT  21.06 90.419 21.597 90.467 ;
     RECT  39.996 90.419 43.197 90.467 ;
     RECT  50.292 90.239 51.297 90.467 ;
     RECT  66.528 90.275 70.197 90.467 ;
     RECT  72.615 88.889 72.897 90.467 ;
     RECT  4.356 90.239 8.334 90.509 ;
     RECT  9.252 90.275 9.342 90.509 ;
     RECT  10.332 90.419 11.322 90.509 ;
     RECT  12.06 90.467 18.705 90.509 ;
     RECT  23.328 90.275 25.11 90.509 ;
     RECT  26.1 90.275 30.294 90.509 ;
     RECT  31.536 90.383 33.894 90.509 ;
     RECT  34.815 90.383 36.702 90.509 ;
     RECT  37.476 90.419 38.97 90.509 ;
     RECT  44.424 90.419 46.17 90.509 ;
     RECT  47.34 90.383 47.502 90.509 ;
     RECT  48.276 90.383 49.266 90.509 ;
     RECT  50.292 90.467 51.174 90.509 ;
     RECT  52.992 90.077 55.278 90.509 ;
     RECT  56.016 90.317 58.338 90.509 ;
     RECT  59.115 90.275 60.822 90.509 ;
     RECT  61.632 90.275 63.09 90.509 ;
     RECT  66.528 90.467 70.005 90.509 ;
     RECT  17.064 90.509 17.082 90.515 ;
     RECT  18.144 90.509 18.705 90.515 ;
     RECT  4.356 90.509 4.374 90.545 ;
     RECT  5.115 90.509 6.318 90.545 ;
     RECT  9.252 90.509 9.27 90.545 ;
     RECT  10.332 90.509 10.962 90.545 ;
     RECT  15.444 90.509 16.005 90.545 ;
     RECT  21.06 90.467 21.474 90.545 ;
     RECT  28.656 90.509 30.222 90.545 ;
     RECT  32.115 90.509 33.57 90.545 ;
     RECT  34.815 90.509 36.558 90.545 ;
     RECT  39.996 90.467 43.005 90.545 ;
     RECT  44.424 90.509 44.442 90.545 ;
     RECT  45.615 90.509 46.17 90.545 ;
     RECT  47.34 90.509 47.358 90.545 ;
     RECT  48.315 90.509 49.05 90.545 ;
     RECT  50.436 90.509 51.174 90.545 ;
     RECT  52.992 90.509 53.805 90.545 ;
     RECT  57.24 90.509 57.402 90.545 ;
     RECT  59.115 90.509 60.678 90.545 ;
     RECT  61.668 90.509 63.018 90.545 ;
     RECT  64.152 90.391 65.538 90.545 ;
     RECT  7.416 90.509 7.905 90.557 ;
     RECT  12.636 90.509 14.13 90.557 ;
     RECT  26.1 90.509 27.414 90.557 ;
     RECT  37.515 90.509 37.674 90.557 ;
     RECT  12.636 90.557 13.305 90.568 ;
     RECT  26.1 90.557 26.805 90.568 ;
     RECT  36.036 90.545 36.558 90.568 ;
     RECT  24.015 90.509 25.074 90.581 ;
     RECT  57.24 90.545 57.258 90.581 ;
     RECT  67.215 90.509 68.13 90.581 ;
     RECT  6.3 90.545 6.318 90.617 ;
     RECT  14.112 90.557 14.13 90.617 ;
     RECT  15.732 90.545 16.005 90.617 ;
     RECT  28.836 90.545 29.505 90.617 ;
     RECT  32.115 90.545 32.526 90.617 ;
     RECT  36.036 90.568 36.054 90.617 ;
     RECT  42.3 90.545 43.005 90.617 ;
     RECT  50.796 90.545 51.174 90.617 ;
     RECT  61.668 90.545 62.55 90.617 ;
     RECT  64.515 90.545 65.214 90.617 ;
     RECT  40.215 90.545 40.914 90.653 ;
     RECT  21.06 90.545 21.405 90.689 ;
     RECT  59.115 90.545 59.922 90.689 ;
     RECT  67.215 90.581 67.878 90.689 ;
     RECT  2.415 90.467 2.505 90.737 ;
     RECT  5.115 90.545 5.205 90.737 ;
     RECT  7.815 90.557 7.905 90.737 ;
     RECT  10.515 90.545 10.605 90.737 ;
     RECT  13.215 90.568 13.305 90.737 ;
     RECT  15.915 90.617 16.005 90.737 ;
     RECT  18.615 90.515 18.705 90.737 ;
     RECT  21.315 90.689 21.405 90.737 ;
     RECT  24.015 90.581 24.105 90.737 ;
     RECT  26.715 90.568 26.805 90.737 ;
     RECT  29.415 90.617 29.505 90.737 ;
     RECT  32.115 90.617 32.205 90.737 ;
     RECT  34.815 90.545 34.905 90.737 ;
     RECT  37.515 90.557 37.605 90.737 ;
     RECT  40.215 90.653 40.305 90.737 ;
     RECT  42.915 90.617 43.005 90.737 ;
     RECT  45.615 90.545 45.705 90.737 ;
     RECT  48.315 90.545 48.405 90.737 ;
     RECT  51.015 90.617 51.105 90.737 ;
     RECT  53.715 90.545 53.805 90.737 ;
     RECT  56.415 90.509 56.505 90.737 ;
     RECT  59.115 90.689 59.205 90.737 ;
     RECT  61.815 90.617 61.905 90.737 ;
     RECT  64.515 90.617 64.605 90.737 ;
     RECT  67.215 90.689 67.305 90.737 ;
     RECT  69.915 90.509 70.005 90.737 ;
     RECT  72.615 90.467 72.705 90.737 ;
    LAYER M4 ;
     RECT  0.156 4.416 2.408 88.536 ;
     RECT  2.408 2.148 2.512 90.732 ;
     RECT  2.512 2.418 2.704 90.462 ;
     RECT  2.704 3.984 2.765 20.328 ;
     RECT  2.704 21.36 2.801 87.864 ;
     RECT  2.765 3.984 2.837 4.44 ;
     RECT  2.765 20.304 2.837 20.328 ;
     RECT  2.801 21.36 2.837 87.576 ;
     RECT  2.837 72.096 2.873 75.24 ;
     RECT  2.837 76.416 2.981 87.576 ;
     RECT  2.981 77.856 3.449 87.576 ;
     RECT  2.765 6.096 3.769 19.32 ;
     RECT  2.837 21.36 3.805 23.112 ;
     RECT  2.837 24.384 3.805 38.424 ;
     RECT  2.837 39.696 3.805 70.92 ;
     RECT  3.769 6.096 3.841 20.04 ;
     RECT  3.805 21.36 3.877 38.424 ;
     RECT  3.805 39.456 3.877 70.92 ;
     RECT  2.837 3.984 3.925 4.008 ;
     RECT  3.841 5.856 3.925 20.232 ;
     RECT  3.925 3.984 4.057 20.232 ;
     RECT  3.877 21.36 4.057 70.92 ;
     RECT  3.449 77.856 4.057 79.224 ;
     RECT  2.873 72.096 4.201 73.8 ;
     RECT  2.873 75.168 4.201 75.24 ;
     RECT  4.057 3.984 4.213 70.92 ;
     RECT  4.201 72.096 4.213 75.24 ;
     RECT  4.213 3.984 4.273 75.24 ;
     RECT  2.981 76.416 4.273 76.728 ;
     RECT  4.057 77.76 4.273 79.224 ;
     RECT  3.449 80.256 4.309 87.576 ;
     RECT  4.273 3.984 4.453 79.224 ;
     RECT  4.309 80.256 4.453 87.912 ;
     RECT  4.453 3.984 4.561 87.912 ;
     RECT  4.561 3.936 4.693 87.912 ;
     RECT  4.693 3.936 4.748 88.728 ;
     RECT  4.345 90.24 4.748 90.264 ;
     RECT  4.748 3.936 5.108 90.264 ;
     RECT  5.108 2.148 5.212 90.732 ;
     RECT  5.212 2.256 5.404 90.462 ;
     RECT  5.404 2.256 5.699 90.264 ;
     RECT  5.699 4.224 5.825 90.264 ;
     RECT  5.825 66.24 6.077 90.264 ;
     RECT  5.699 2.496 6.473 2.52 ;
     RECT  5.825 4.224 6.509 65.208 ;
     RECT  6.509 23.328 7.153 65.208 ;
     RECT  6.077 66.24 7.153 88.728 ;
     RECT  6.509 4.224 7.333 22.2 ;
     RECT  7.153 23.328 7.405 88.728 ;
     RECT  6.077 89.808 7.405 90.264 ;
     RECT  7.333 3.408 7.477 22.2 ;
     RECT  7.405 23.328 7.477 90.552 ;
     RECT  7.477 3.408 7.808 90.552 ;
     RECT  7.808 2.148 7.912 90.732 ;
     RECT  7.912 2.418 8.104 90.552 ;
     RECT  8.104 2.64 8.243 90.552 ;
     RECT  8.243 2.88 9.385 90.552 ;
     RECT  9.385 2.256 9.389 90.552 ;
     RECT  9.389 2.256 10.508 89.496 ;
     RECT  9.389 90.528 10.508 90.552 ;
     RECT  10.508 2.148 10.612 90.732 ;
     RECT  10.612 2.418 10.804 90.552 ;
     RECT  10.804 2.832 10.931 90.552 ;
     RECT  10.931 3.12 11.411 90.552 ;
     RECT  11.411 3.12 12.161 90.36 ;
     RECT  12.161 3.12 12.337 89.496 ;
     RECT  12.337 2.832 13.208 89.496 ;
     RECT  12.625 90.528 13.208 90.552 ;
     RECT  13.208 2.148 13.312 90.732 ;
     RECT  13.312 2.418 13.504 90.552 ;
     RECT  13.504 90.528 13.925 90.552 ;
     RECT  13.504 2.496 14.321 88.968 ;
     RECT  14.321 3.648 14.579 88.968 ;
     RECT  14.641 90.048 15.721 90.072 ;
     RECT  14.321 2.496 15.901 2.52 ;
     RECT  14.579 3.648 15.901 88.728 ;
     RECT  15.901 2.496 15.908 88.728 ;
     RECT  15.721 90.048 15.908 90.36 ;
     RECT  15.908 2.148 16.012 90.732 ;
     RECT  16.012 2.418 16.204 90.462 ;
     RECT  16.204 3.312 16.697 88.488 ;
     RECT  16.204 90.048 17.053 90.462 ;
     RECT  17.053 90.048 17.521 90.504 ;
     RECT  17.665 2.496 17.989 2.52 ;
     RECT  17.989 2.496 18.097 2.856 ;
     RECT  16.697 3.984 18.097 88.488 ;
     RECT  18.097 2.496 18.181 88.488 ;
     RECT  17.521 89.472 18.181 90.504 ;
     RECT  18.181 2.496 18.608 90.504 ;
     RECT  18.608 2.148 18.712 90.732 ;
     RECT  18.712 2.418 18.904 90.462 ;
     RECT  18.904 2.496 19.145 88.92 ;
     RECT  19.145 2.496 19.181 37.992 ;
     RECT  18.904 90.048 19.389 90.072 ;
     RECT  19.145 39.072 19.433 88.92 ;
     RECT  19.181 2.832 19.541 37.992 ;
     RECT  19.541 2.832 19.685 37.608 ;
     RECT  19.685 2.832 20.189 20.088 ;
     RECT  20.189 2.88 20.333 20.088 ;
     RECT  20.113 89.76 20.333 89.784 ;
     RECT  19.433 39.072 20.653 88.68 ;
     RECT  20.333 3.408 20.905 20.088 ;
     RECT  19.685 21.12 20.905 37.608 ;
     RECT  21.02 0.144 21.107 0.168 ;
     RECT  20.653 39.024 21.157 88.68 ;
     RECT  20.905 3.408 21.308 37.608 ;
     RECT  21.157 39.024 21.308 89.544 ;
     RECT  21.308 2.148 21.412 90.732 ;
     RECT  21.412 2.418 21.604 90.462 ;
     RECT  21.604 3.408 21.837 89.304 ;
     RECT  21.837 3.648 22.061 89.304 ;
     RECT  22.061 3.648 22.349 88.776 ;
     RECT  22.349 3.648 22.813 49.848 ;
     RECT  22.349 50.832 23.18 88.776 ;
     RECT  22.813 2.832 23.317 49.848 ;
     RECT  23.18 50.832 23.317 89.112 ;
     RECT  23.137 90.192 23.317 90.216 ;
     RECT  23.317 2.304 23.353 49.848 ;
     RECT  23.317 50.832 23.353 90.216 ;
     RECT  23.353 2.304 24.008 90.216 ;
     RECT  24.008 2.148 24.112 90.732 ;
     RECT  24.112 2.304 24.304 90.462 ;
     RECT  24.304 2.304 24.617 90.072 ;
     RECT  24.617 2.304 24.797 2.904 ;
     RECT  24.797 2.832 25.049 2.904 ;
     RECT  25.049 2.88 25.121 2.904 ;
     RECT  24.617 4.224 26.089 90.072 ;
     RECT  26.053 3.12 26.449 3.144 ;
     RECT  26.449 2.304 26.708 3.144 ;
     RECT  26.089 4.224 26.708 90.552 ;
     RECT  26.708 2.148 26.812 90.732 ;
     RECT  26.812 2.256 27.004 90.552 ;
     RECT  27.004 2.256 27.281 88.44 ;
     RECT  27.004 90.528 27.425 90.552 ;
     RECT  27.281 2.256 27.923 88.2 ;
     RECT  27.923 2.448 27.929 88.2 ;
     RECT  27.929 81.648 28.309 88.2 ;
     RECT  27.004 89.472 28.309 89.496 ;
     RECT  28.309 81.648 28.396 89.496 ;
     RECT  27.929 2.448 28.897 80.664 ;
     RECT  28.396 81.648 28.897 88.2 ;
     RECT  28.897 2.448 29.408 88.2 ;
     RECT  28.396 89.232 29.408 89.496 ;
     RECT  29.408 2.148 29.512 90.732 ;
     RECT  29.512 2.352 29.704 90.462 ;
     RECT  29.704 2.352 29.729 3.096 ;
     RECT  29.729 2.352 30.697 2.376 ;
     RECT  30.697 2.256 30.781 2.376 ;
     RECT  30.668 3.552 31.093 3.576 ;
     RECT  29.704 4.608 31.093 90.072 ;
     RECT  31.093 3.552 31.525 90.072 ;
     RECT  30.781 2.352 31.561 2.376 ;
     RECT  31.525 3.552 31.561 90.36 ;
     RECT  31.561 2.352 32.108 90.36 ;
     RECT  32.108 2.148 32.212 90.732 ;
     RECT  32.212 2.352 32.404 90.462 ;
     RECT  32.404 33.6 32.465 90.36 ;
     RECT  32.465 33.648 32.573 90.36 ;
     RECT  32.573 45.456 32.609 90.36 ;
     RECT  32.609 45.504 33.005 90.36 ;
     RECT  33.005 45.504 33.077 80.664 ;
     RECT  32.404 2.352 33.289 32.616 ;
     RECT  33.077 50.736 34.153 80.664 ;
     RECT  33.005 81.648 34.153 90.36 ;
     RECT  33.289 2.304 34.808 32.616 ;
     RECT  32.573 33.648 34.808 44.472 ;
     RECT  33.077 45.504 34.808 49.656 ;
     RECT  34.153 50.736 34.808 90.36 ;
     RECT  34.808 2.148 34.912 90.732 ;
     RECT  34.912 2.352 35.104 90.462 ;
     RECT  35.104 2.352 35.273 2.856 ;
     RECT  35.104 4.656 35.741 90.36 ;
     RECT  35.273 2.64 35.993 2.856 ;
     RECT  35.741 4.704 36.461 90.36 ;
     RECT  36.461 79.728 36.529 90.36 ;
     RECT  36.461 4.704 37.381 78.696 ;
     RECT  35.993 2.64 37.508 2.664 ;
     RECT  37.381 3.84 37.508 78.696 ;
     RECT  36.529 79.728 37.508 90.552 ;
     RECT  37.508 2.148 37.612 90.732 ;
     RECT  37.612 2.256 37.685 90.552 ;
     RECT  37.685 2.256 37.804 90.462 ;
     RECT  37.804 3.888 38.339 49.608 ;
     RECT  38.339 3.888 38.405 20.184 ;
     RECT  37.804 51.024 39.085 90.072 ;
     RECT  38.405 3.888 39.517 20.136 ;
     RECT  38.339 21.408 39.805 49.608 ;
     RECT  39.085 50.832 39.805 90.072 ;
     RECT  37.804 2.256 40.208 2.28 ;
     RECT  39.517 3.648 40.208 20.136 ;
     RECT  39.805 21.408 40.208 90.072 ;
     RECT  40.208 2.148 40.312 90.732 ;
     RECT  40.312 2.256 40.504 90.462 ;
     RECT  40.504 2.256 40.565 90.072 ;
     RECT  40.565 2.256 41.02 89.88 ;
     RECT  41.02 3.648 41.069 89.88 ;
     RECT  41.069 3.648 42.073 3.672 ;
     RECT  41.069 4.704 42.397 89.88 ;
     RECT  42.073 3.36 42.541 3.672 ;
     RECT  42.397 4.704 42.541 90.552 ;
     RECT  41.02 2.256 42.908 2.28 ;
     RECT  42.541 3.36 42.908 90.552 ;
     RECT  42.908 2.148 43.012 90.732 ;
     RECT  43.012 2.418 43.204 90.552 ;
     RECT  43.204 3.888 43.913 49.656 ;
     RECT  43.204 2.418 44.108 2.856 ;
     RECT  43.204 50.736 44.165 90.552 ;
     RECT  44.108 2.256 44.195 2.856 ;
     RECT  43.913 3.888 44.489 47.448 ;
     RECT  44.195 2.832 44.521 2.856 ;
     RECT  43.913 48.72 44.737 49.656 ;
     RECT  44.489 4.704 44.917 47.448 ;
     RECT  44.737 48.72 44.917 49.848 ;
     RECT  44.917 4.704 45.601 49.848 ;
     RECT  44.165 50.832 45.601 90.552 ;
     RECT  44.521 2.832 45.608 3.384 ;
     RECT  45.601 4.704 45.608 90.552 ;
     RECT  45.608 2.148 45.712 90.732 ;
     RECT  45.712 2.418 45.904 90.552 ;
     RECT  45.904 3.84 46.019 90.552 ;
     RECT  46.019 3.84 46.029 90.072 ;
     RECT  46.029 3.84 46.073 50.328 ;
     RECT  46.029 51.312 46.109 90.072 ;
     RECT  46.109 51.312 46.145 89.784 ;
     RECT  46.073 3.84 46.739 47.448 ;
     RECT  45.904 2.832 46.897 2.856 ;
     RECT  46.897 2.256 46.937 2.856 ;
     RECT  46.145 51.312 47.329 89.736 ;
     RECT  46.739 4.368 47.401 47.448 ;
     RECT  46.073 48.672 47.401 50.328 ;
     RECT  47.401 4.368 47.509 50.328 ;
     RECT  47.329 51.312 47.509 90.264 ;
     RECT  46.937 2.256 48.308 2.28 ;
     RECT  47.509 4.368 48.308 90.264 ;
     RECT  48.308 2.148 48.412 90.732 ;
     RECT  48.412 2.418 48.604 90.462 ;
     RECT  48.604 89.712 49.529 90.264 ;
     RECT  48.604 3.408 49.705 88.488 ;
     RECT  49.705 3.408 49.813 88.728 ;
     RECT  49.529 89.712 49.813 90.024 ;
     RECT  49.813 3.408 49.853 90.024 ;
     RECT  49.853 80.496 49.889 90.024 ;
     RECT  49.853 3.408 50.101 79.464 ;
     RECT  49.889 80.496 51.001 89.544 ;
     RECT  50.101 2.64 51.008 79.464 ;
     RECT  51.001 80.496 51.008 90.072 ;
     RECT  51.008 2.148 51.112 90.732 ;
     RECT  51.112 2.256 51.304 90.462 ;
     RECT  51.304 80.4 52.213 90.462 ;
     RECT  51.304 2.256 52.265 2.28 ;
     RECT  51.304 3.264 52.405 20.424 ;
     RECT  52.213 80.4 52.412 90.504 ;
     RECT  51.304 21.456 52.441 79.224 ;
     RECT  52.412 80.352 52.441 90.504 ;
     RECT  52.441 21.456 52.625 90.504 ;
     RECT  52.405 2.448 53.233 20.424 ;
     RECT  52.625 21.456 53.233 84.36 ;
     RECT  53.233 2.448 53.708 84.36 ;
     RECT  52.625 85.44 53.708 90.504 ;
     RECT  53.708 2.148 53.812 90.732 ;
     RECT  53.812 2.418 54.004 90.462 ;
     RECT  54.004 2.784 54.245 70.872 ;
     RECT  54.245 2.784 54.317 47.448 ;
     RECT  54.004 72 54.389 89.832 ;
     RECT  54.389 80.64 55.069 89.832 ;
     RECT  54.389 72 55.357 79.464 ;
     RECT  55.069 80.64 55.357 90.072 ;
     RECT  54.317 2.832 55.609 47.448 ;
     RECT  54.245 48.48 55.609 70.872 ;
     RECT  55.609 2.832 55.645 70.872 ;
     RECT  55.357 72 55.645 90.072 ;
     RECT  55.645 2.832 55.717 90.072 ;
     RECT  55.717 2.784 56.408 90.072 ;
     RECT  56.408 2.148 56.512 90.732 ;
     RECT  56.512 2.208 56.704 90.462 ;
     RECT  56.704 2.208 56.909 90.072 ;
     RECT  56.909 2.208 57.377 70.872 ;
     RECT  57.377 2.208 57.881 2.232 ;
     RECT  56.909 72 58.345 90.072 ;
     RECT  57.377 3.312 58.381 70.872 ;
     RECT  58.345 72 58.381 90.312 ;
     RECT  58.381 3.312 58.705 90.312 ;
     RECT  58.705 2.544 59.108 90.312 ;
     RECT  59.108 2.148 59.212 90.732 ;
     RECT  59.212 2.418 59.404 90.6 ;
     RECT  59.404 2.544 59.573 90.6 ;
     RECT  59.573 2.64 59.933 90.6 ;
     RECT  59.933 2.64 59.969 90.024 ;
     RECT  59.969 2.64 60.541 41.256 ;
     RECT  60.541 2.448 60.973 41.256 ;
     RECT  59.969 42.24 60.973 90.024 ;
     RECT  60.973 2.448 61.261 90.024 ;
     RECT  61.261 2.256 61.808 90.024 ;
     RECT  61.808 2.148 61.912 90.732 ;
     RECT  61.912 2.418 62.104 90.462 ;
     RECT  62.104 2.784 62.993 90.072 ;
     RECT  62.993 3.12 63.245 90.072 ;
     RECT  63.245 3.12 64.268 89.544 ;
     RECT  64.268 2.64 64.508 89.544 ;
     RECT  64.508 2.148 64.612 90.732 ;
     RECT  64.612 2.418 64.804 90.462 ;
     RECT  64.804 3.12 65.477 89.928 ;
     RECT  65.477 3.12 66.517 89.736 ;
     RECT  66.517 3.12 66.985 90.072 ;
     RECT  66.985 2.496 67.208 90.072 ;
     RECT  67.208 2.148 67.312 90.732 ;
     RECT  67.312 2.418 67.504 90.462 ;
     RECT  67.504 41.568 67.709 90.072 ;
     RECT  67.709 41.568 67.997 88.728 ;
     RECT  67.504 3.936 68.387 40.584 ;
     RECT  67.709 90.048 68.393 90.072 ;
     RECT  68.387 4.224 68.533 40.584 ;
     RECT  67.997 41.568 68.533 44.664 ;
     RECT  68.533 4.224 68.579 44.664 ;
     RECT  67.997 45.744 68.713 88.728 ;
     RECT  68.579 40.56 68.965 44.664 ;
     RECT  68.713 45.744 68.965 88.92 ;
     RECT  67.504 2.496 69.145 2.904 ;
     RECT  69.145 2.256 69.205 2.904 ;
     RECT  69.205 2.256 69.349 3.144 ;
     RECT  68.579 4.224 69.349 39.576 ;
     RECT  68.965 40.56 69.361 88.92 ;
     RECT  69.349 2.256 69.541 39.576 ;
     RECT  69.361 40.56 69.541 88.968 ;
     RECT  69.541 2.256 69.908 88.968 ;
     RECT  69.301 89.952 69.908 89.976 ;
     RECT  69.908 2.148 70.012 90.732 ;
     RECT  70.012 2.418 70.204 90.462 ;
     RECT  70.204 3.408 70.481 88.728 ;
     RECT  70.481 4.176 70.697 88.728 ;
     RECT  70.697 4.176 70.733 68.52 ;
     RECT  70.733 4.176 70.877 66.072 ;
     RECT  70.697 70.08 70.877 88.728 ;
     RECT  70.877 4.752 70.949 66.072 ;
     RECT  70.733 67.104 70.985 68.52 ;
     RECT  70.949 4.752 71.021 52.488 ;
     RECT  70.949 53.52 71.021 66.072 ;
     RECT  70.985 67.344 71.021 68.52 ;
     RECT  71.021 4.752 71.027 9.384 ;
     RECT  71.027 9.072 71.057 9.384 ;
     RECT  71.021 53.904 71.057 66.072 ;
     RECT  71.021 10.416 71.129 52.488 ;
     RECT  71.057 53.904 71.129 61.128 ;
     RECT  70.877 74.88 71.129 88.728 ;
     RECT  71.129 20.112 71.201 48.936 ;
     RECT  71.129 74.928 71.201 88.728 ;
     RECT  71.201 21.408 71.237 33.096 ;
     RECT  71.201 34.128 71.237 48.936 ;
     RECT  70.877 70.08 71.237 73.896 ;
     RECT  71.129 10.416 71.273 18.792 ;
     RECT  71.129 54.624 71.273 61.128 ;
     RECT  71.237 71.424 71.273 73.896 ;
     RECT  71.201 82.416 71.273 88.728 ;
     RECT  71.237 34.128 71.309 45.048 ;
     RECT  71.057 62.112 71.309 66.072 ;
     RECT  71.273 82.416 71.309 84.984 ;
     RECT  71.273 86.016 71.309 88.728 ;
     RECT  71.309 36.48 71.315 45.048 ;
     RECT  71.237 21.408 71.345 23.064 ;
     RECT  71.237 24.096 71.345 33.096 ;
     RECT  71.129 50.112 71.345 52.488 ;
     RECT  71.273 72.144 71.345 73.896 ;
     RECT  71.027 4.752 71.381 7.992 ;
     RECT  71.315 36.576 71.381 45.048 ;
     RECT  71.345 72.144 71.381 73.8 ;
     RECT  71.201 74.928 71.381 81.096 ;
     RECT  71.309 88.176 71.381 88.728 ;
     RECT  71.345 24.096 71.417 25.512 ;
     RECT  71.381 41.376 71.417 45.048 ;
     RECT  71.237 46.8 71.417 48.936 ;
     RECT  71.309 62.112 71.417 62.136 ;
     RECT  71.381 75.12 71.453 81.096 ;
     RECT  71.381 4.752 71.489 7.752 ;
     RECT  71.057 9.312 71.489 9.384 ;
     RECT  71.381 36.576 71.489 39.768 ;
     RECT  71.453 75.12 71.489 78.12 ;
     RECT  71.345 26.544 71.525 33.096 ;
     RECT  71.417 41.376 71.525 43.08 ;
     RECT  71.417 46.848 71.525 48.936 ;
     RECT  71.273 54.624 71.525 60.264 ;
     RECT  71.309 63.504 71.525 66.072 ;
     RECT  71.237 70.08 71.525 70.44 ;
     RECT  71.201 20.112 71.561 20.424 ;
     RECT  71.525 26.592 71.597 33.096 ;
     RECT  71.273 15.744 71.633 18.792 ;
     RECT  71.489 38.112 71.633 39.768 ;
     RECT  71.525 70.272 71.633 70.44 ;
     RECT  71.309 86.016 71.633 86.856 ;
     RECT  71.489 4.752 72.608 5.736 ;
     RECT  71.489 6.816 72.608 7.752 ;
     RECT  71.489 9.36 72.608 9.384 ;
     RECT  71.273 10.416 72.608 14.664 ;
     RECT  71.633 16.08 72.608 18.792 ;
     RECT  71.561 20.112 72.608 20.136 ;
     RECT  71.345 21.6 72.608 23.064 ;
     RECT  71.417 24.096 72.608 24.648 ;
     RECT  71.597 27.456 72.608 33.096 ;
     RECT  71.309 34.128 72.608 35.448 ;
     RECT  71.489 36.576 72.608 36.888 ;
     RECT  71.633 38.112 72.608 39.72 ;
     RECT  71.525 41.376 72.608 43.032 ;
     RECT  71.417 44.112 72.608 45.048 ;
     RECT  71.525 46.848 72.608 48.264 ;
     RECT  71.345 50.304 72.608 52.488 ;
     RECT  71.525 54.912 72.608 60.264 ;
     RECT  71.525 63.504 72.608 63.864 ;
     RECT  71.525 65.184 72.608 66.072 ;
     RECT  71.021 67.344 72.608 68.376 ;
     RECT  71.633 70.272 72.608 70.344 ;
     RECT  71.381 72.24 72.608 73.8 ;
     RECT  71.489 75.12 72.608 76.056 ;
     RECT  71.489 77.088 72.608 78.12 ;
     RECT  71.453 79.488 72.608 80.904 ;
     RECT  71.309 82.416 72.608 84.36 ;
     RECT  71.633 86.832 72.608 86.856 ;
     RECT  71.381 88.704 72.608 88.728 ;
     RECT  72.608 2.148 72.712 90.732 ;
     RECT  72.712 2.418 72.904 90.462 ;
     RECT  72.904 48.432 73.969 50.904 ;
     RECT  72.904 52.176 73.969 56.616 ;
     RECT  72.904 68.064 73.969 71.016 ;
     RECT  72.904 4.752 74.077 36.024 ;
     RECT  72.904 37.968 74.077 43.368 ;
     RECT  72.904 44.496 74.077 47.448 ;
     RECT  73.969 48.432 74.077 56.616 ;
     RECT  72.904 57.744 74.077 67.08 ;
     RECT  73.969 68.064 74.077 71.16 ;
     RECT  72.904 72.144 74.077 73.32 ;
     RECT  72.904 74.592 74.077 88.536 ;
     RECT  74.077 4.416 74.113 36.024 ;
     RECT  74.077 37.152 74.113 88.536 ;
     RECT  74.113 4.416 75.42 88.536 ;
    LAYER M5 ;
     RECT  21.072 0.133 21.096 2.137 ;
     RECT  54.528 0.144 54.552 2.137 ;
     RECT  2.4 2.137 2.52 2.151 ;
     RECT  5.1 2.137 5.22 2.151 ;
     RECT  7.8 2.137 7.92 2.151 ;
     RECT  10.5 2.137 10.62 2.151 ;
     RECT  13.2 2.137 13.32 2.151 ;
     RECT  15.9 2.137 16.02 2.151 ;
     RECT  18.6 2.137 18.72 2.151 ;
     RECT  21.072 2.137 21.42 2.151 ;
     RECT  24 2.137 24.12 2.151 ;
     RECT  26.7 2.137 26.82 2.151 ;
     RECT  29.4 2.137 29.52 2.151 ;
     RECT  32.1 2.137 32.22 2.151 ;
     RECT  34.8 2.137 34.92 2.151 ;
     RECT  37.5 2.137 37.62 2.151 ;
     RECT  40.2 2.137 40.32 2.151 ;
     RECT  42.9 2.137 43.02 2.151 ;
     RECT  45.6 2.137 45.72 2.151 ;
     RECT  48.3 2.137 48.42 2.151 ;
     RECT  51 2.137 51.12 2.151 ;
     RECT  56.4 2.137 56.52 2.151 ;
     RECT  59.1 2.137 59.22 2.151 ;
     RECT  61.8 2.137 61.92 2.151 ;
     RECT  64.5 2.137 64.62 2.151 ;
     RECT  67.2 2.137 67.32 2.151 ;
     RECT  69.9 2.137 70.02 2.151 ;
     RECT  72.6 2.137 72.72 2.151 ;
     RECT  56.4 2.151 56.712 2.197 ;
     RECT  5.1 2.151 5.412 2.245 ;
     RECT  26.7 2.151 27.012 2.245 ;
     RECT  42.9 2.151 43.212 2.245 ;
     RECT  51 2.151 51.312 2.245 ;
     RECT  69.9 2.151 70.212 2.245 ;
     RECT  18.6 2.151 18.912 2.485 ;
     RECT  7.8 2.151 8.112 2.629 ;
     RECT  37.5 2.151 37.812 2.629 ;
     RECT  51 2.245 51.864 2.629 ;
     RECT  61.8 2.151 62.112 2.629 ;
     RECT  64.5 2.151 64.812 2.629 ;
     RECT  10.5 2.151 10.812 2.821 ;
     RECT  45.6 2.151 45.912 2.821 ;
     RECT  59.1 2.151 59.412 2.821 ;
     RECT  69.36 2.245 70.212 2.869 ;
     RECT  40.2 2.151 40.512 3.157 ;
     RECT  18.24 2.485 18.912 3.299 ;
     RECT  56.4 2.197 57.192 3.347 ;
     RECT  21.072 2.151 21.612 3.397 ;
     RECT  26.7 2.245 27.912 3.443 ;
     RECT  50.112 2.629 51.864 3.443 ;
     RECT  51 3.443 51.864 3.683 ;
     RECT  10.5 2.821 10.92 3.685 ;
     RECT  37.392 2.629 37.812 3.875 ;
     RECT  40.2 3.157 40.968 3.877 ;
     RECT  66.144 3.301 66.168 3.877 ;
     RECT  7.8 2.629 8.232 3.925 ;
     RECT  67.2 2.151 67.512 3.925 ;
     RECT  69.216 2.869 70.212 3.925 ;
     RECT  13.2 2.151 13.512 3.973 ;
     RECT  32.1 2.151 32.412 3.973 ;
     RECT  59.1 2.821 59.976 3.973 ;
     RECT  21.072 3.397 21.816 4.115 ;
     RECT  15.9 2.151 16.212 4.117 ;
     RECT  29.4 2.151 29.712 4.261 ;
     RECT  42.9 2.245 44.184 4.307 ;
     RECT  45.6 2.821 46.728 4.403 ;
     RECT  66.144 3.877 66.216 4.453 ;
     RECT  67.2 3.925 70.212 4.453 ;
     RECT  24 2.151 24.312 4.501 ;
     RECT  26.7 3.443 27.384 4.501 ;
     RECT  26.592 4.501 27.384 4.547 ;
     RECT  18.6 3.299 18.912 4.645 ;
     RECT  19.92 3.397 19.944 4.645 ;
     RECT  31.968 3.973 32.412 4.645 ;
     RECT  18.6 4.645 19.944 4.691 ;
     RECT  51 3.683 51.312 4.789 ;
     RECT  3.936 3.973 3.96 4.931 ;
     RECT  15.9 4.117 17.16 4.931 ;
     RECT  39.312 3.877 40.968 4.931 ;
     RECT  13.104 3.973 13.512 5.029 ;
     RECT  64.32 2.629 64.812 5.029 ;
     RECT  24 4.501 25.08 5.075 ;
     RECT  66.144 4.453 70.212 5.075 ;
     RECT  66.192 5.075 70.212 5.077 ;
     RECT  29.136 4.261 29.712 5.171 ;
     RECT  59.1 3.973 60.216 5.171 ;
     RECT  37.5 3.875 37.812 5.221 ;
     RECT  37.056 5.221 37.812 5.363 ;
     RECT  34.8 2.151 35.112 5.365 ;
     RECT  15.9 4.931 16.212 5.461 ;
     RECT  29.4 5.171 29.712 5.461 ;
     RECT  30.72 2.245 30.744 5.461 ;
     RECT  15.792 5.461 16.212 5.557 ;
     RECT  29.4 5.461 30.744 5.557 ;
     RECT  31.968 4.645 33.192 5.557 ;
     RECT  63.648 5.029 64.812 5.603 ;
     RECT  39.312 4.931 40.512 5.605 ;
     RECT  5.1 2.245 5.688 5.653 ;
     RECT  59.1 5.171 59.688 5.653 ;
     RECT  42.9 4.307 43.656 5.845 ;
     RECT  38.88 5.605 40.512 5.987 ;
     RECT  26.592 4.547 27.012 6.037 ;
     RECT  4.368 5.653 5.688 6.133 ;
     RECT  6.72 4.837 6.744 6.133 ;
     RECT  10.5 3.685 11.736 6.229 ;
     RECT  12.912 5.029 13.512 6.229 ;
     RECT  48.3 2.151 48.612 6.229 ;
     RECT  52.608 3.877 52.632 6.229 ;
     RECT  53.7 2.137 54.552 6.229 ;
     RECT  42.768 5.845 43.656 6.275 ;
     RECT  52.608 6.229 54.552 6.277 ;
     RECT  29.4 5.557 33.192 6.323 ;
     RECT  52.608 6.277 54.792 6.323 ;
     RECT  61.632 2.629 62.112 6.323 ;
     RECT  29.4 6.323 30.696 6.515 ;
     RECT  31.968 6.323 33.192 6.563 ;
     RECT  15.552 5.557 16.212 6.611 ;
     RECT  28.032 6.373 28.056 6.611 ;
     RECT  42.768 6.275 43.212 6.613 ;
     RECT  38.88 5.987 38.904 6.659 ;
     RECT  4.368 6.133 6.744 6.661 ;
     RECT  7.8 3.925 9.096 6.661 ;
     RECT  42.432 6.613 43.212 6.661 ;
     RECT  10.224 6.229 13.512 6.805 ;
     RECT  40.2 5.987 40.512 6.805 ;
     RECT  56.4 3.347 56.712 6.805 ;
     RECT  4.368 6.661 9.096 6.851 ;
     RECT  10.224 6.805 13.992 6.851 ;
     RECT  47.616 6.229 48.744 6.851 ;
     RECT  58.656 5.653 59.688 6.851 ;
     RECT  66.192 5.077 70.68 6.851 ;
     RECT  37.5 5.363 37.812 6.853 ;
     RECT  34.8 5.365 35.4 6.899 ;
     RECT  18.6 4.691 19.656 6.901 ;
     RECT  21.072 4.115 21.612 6.901 ;
     RECT  50.16 4.789 51.312 6.947 ;
     RECT  18.6 6.901 21.612 7.091 ;
     RECT  10.224 6.851 11.736 7.187 ;
     RECT  26.208 6.037 27.012 7.189 ;
     RECT  29.4 6.515 29.712 7.189 ;
     RECT  64.5 5.603 64.812 7.189 ;
     RECT  53.136 6.323 54.792 7.235 ;
     RECT  29.184 7.189 29.712 7.237 ;
     RECT  58.992 6.851 59.688 7.237 ;
     RECT  31.968 6.563 32.52 7.283 ;
     RECT  56.4 6.805 56.808 7.333 ;
     RECT  26.208 7.189 27.864 7.379 ;
     RECT  37.056 6.853 37.812 7.379 ;
     RECT  2.4 2.151 2.712 7.381 ;
     RECT  15.744 6.611 16.212 7.381 ;
     RECT  17.184 6.229 17.208 7.381 ;
     RECT  15.744 7.381 17.208 7.475 ;
     RECT  18.6 7.091 19.656 7.475 ;
     RECT  15.744 7.475 17.112 7.571 ;
     RECT  66.192 6.851 67.992 7.619 ;
     RECT  26.208 7.379 27.012 7.715 ;
     RECT  5.1 6.851 9.096 7.811 ;
     RECT  24 5.075 24.312 7.813 ;
     RECT  10.224 7.187 11.4 7.859 ;
     RECT  34.8 6.899 35.112 7.909 ;
     RECT  24 7.813 25.128 7.955 ;
     RECT  45.6 4.403 45.912 7.957 ;
     RECT  68.976 6.851 70.68 7.957 ;
     RECT  6.816 7.811 9.096 8.147 ;
     RECT  2.4 7.381 3.624 8.291 ;
     RECT  63.504 7.189 64.812 8.291 ;
     RECT  12.912 6.851 13.992 8.293 ;
     RECT  37.5 7.379 37.812 8.293 ;
     RECT  5.1 7.811 5.64 8.389 ;
     RECT  6.96 8.147 9.096 8.389 ;
     RECT  12.912 8.293 14.04 8.389 ;
     RECT  29.088 7.237 29.712 8.437 ;
     RECT  31.968 7.283 32.412 8.437 ;
     RECT  64.5 8.291 64.812 8.773 ;
     RECT  10.5 7.859 11.4 8.963 ;
     RECT  15.744 7.571 16.536 8.965 ;
     RECT  47.904 6.851 48.744 9.011 ;
     RECT  66.192 7.619 67.512 9.011 ;
     RECT  68.976 7.957 71.016 9.011 ;
     RECT  45.6 7.957 46.008 9.059 ;
     RECT  58.992 7.237 60.168 9.061 ;
     RECT  63.504 8.291 63.528 9.061 ;
     RECT  66.672 9.011 67.512 9.061 ;
     RECT  18.6 7.475 19.176 9.109 ;
     RECT  37.5 8.293 38.76 9.109 ;
     RECT  53.376 7.235 54.792 9.205 ;
     RECT  56.4 7.333 56.904 9.299 ;
     RECT  4.512 8.389 5.64 9.395 ;
     RECT  40.2 6.805 40.632 9.491 ;
     RECT  24 7.955 24.312 9.493 ;
     RECT  30.912 7.909 30.936 9.539 ;
     RECT  40.2 9.491 40.512 9.541 ;
     RECT  64.5 8.773 64.968 9.587 ;
     RECT  66.672 9.061 67.608 9.589 ;
     RECT  53.04 9.205 54.792 9.635 ;
     RECT  31.968 8.437 33.144 9.637 ;
     RECT  47.904 9.011 48.612 9.637 ;
     RECT  34.8 7.909 35.88 9.779 ;
     RECT  12.672 8.389 14.04 9.781 ;
     RECT  15.408 8.965 16.536 9.781 ;
     RECT  37.056 9.109 38.76 9.827 ;
     RECT  58.896 9.061 60.168 9.827 ;
     RECT  53.7 9.635 54.792 9.829 ;
     RECT  23.904 9.493 24.312 9.877 ;
     RECT  2.4 8.291 2.712 9.925 ;
     RECT  18.6 9.109 19.416 9.925 ;
     RECT  12.672 9.781 16.536 9.971 ;
     RECT  37.5 9.827 38.76 9.973 ;
     RECT  40.08 9.541 40.512 9.973 ;
     RECT  58.992 9.827 60.168 10.019 ;
     RECT  44.448 6.805 44.472 10.067 ;
     RECT  53.7 9.829 55.416 10.115 ;
     RECT  63.456 9.061 63.528 10.117 ;
     RECT  14.832 9.971 16.536 10.163 ;
     RECT  23.904 9.877 24.6 10.163 ;
     RECT  37.5 9.973 40.512 10.163 ;
     RECT  2.4 9.925 3.48 10.165 ;
     RECT  4.512 9.395 5.412 10.165 ;
     RECT  15.408 10.163 16.536 10.165 ;
     RECT  59.1 10.019 60.168 10.213 ;
     RECT  61.8 6.323 62.112 10.213 ;
     RECT  66.672 9.589 67.944 10.213 ;
     RECT  53.7 10.115 54.792 10.259 ;
     RECT  2.4 10.165 5.412 10.307 ;
     RECT  23.904 10.163 24.312 10.307 ;
     RECT  40.08 10.163 40.512 10.355 ;
     RECT  18.6 9.925 19.464 10.693 ;
     RECT  34.8 9.779 35.112 10.741 ;
     RECT  45.6 9.059 45.912 10.741 ;
     RECT  66.384 10.213 67.944 10.789 ;
     RECT  2.4 10.307 4.008 10.883 ;
     RECT  65.808 10.789 67.944 10.885 ;
     RECT  68.976 9.011 70.584 10.885 ;
     RECT  31.968 9.637 33.24 10.931 ;
     RECT  65.808 10.885 70.584 10.931 ;
     RECT  28.176 8.437 29.712 10.933 ;
     RECT  18.48 10.693 19.464 10.979 ;
     RECT  63.264 10.117 63.528 11.027 ;
     RECT  64.5 9.587 64.812 11.077 ;
     RECT  65.808 10.931 70.212 11.077 ;
     RECT  31.968 10.931 33.144 11.171 ;
     RECT  28.176 10.933 30.504 11.267 ;
     RECT  59.1 10.213 62.112 11.267 ;
     RECT  5.1 10.307 5.412 11.365 ;
     RECT  2.4 10.883 3.48 11.459 ;
     RECT  29.088 11.267 30.504 11.459 ;
     RECT  37.5 10.163 38.76 11.459 ;
     RECT  64.5 11.077 70.212 11.459 ;
     RECT  41.616 6.661 43.212 11.509 ;
     RECT  12.672 9.971 13.512 11.747 ;
     RECT  24 10.307 24.312 11.941 ;
     RECT  18.48 10.979 19.416 12.035 ;
     RECT  29.088 11.459 30.264 12.035 ;
     RECT  40.2 10.355 40.512 12.469 ;
     RECT  29.28 12.035 30.264 12.515 ;
     RECT  53.7 10.259 54.648 12.515 ;
     RECT  56.4 9.299 56.808 12.515 ;
     RECT  63.504 11.027 63.528 12.517 ;
     RECT  15.408 10.165 16.824 12.563 ;
     RECT  34.8 10.741 35.352 12.563 ;
     RECT  41.616 11.509 44.04 12.563 ;
     RECT  59.1 11.267 60.36 12.563 ;
     RECT  63.264 12.517 63.528 12.563 ;
     RECT  10.5 8.963 10.812 12.565 ;
     RECT  6.96 8.389 9.24 12.611 ;
     RECT  45.6 10.741 46.152 12.803 ;
     RECT  64.5 11.459 64.92 12.901 ;
     RECT  4.512 11.365 5.412 12.947 ;
     RECT  41.856 12.563 44.04 13.139 ;
     RECT  26.7 7.715 27.012 13.141 ;
     RECT  12.912 11.747 13.512 13.331 ;
     RECT  66.384 11.459 70.212 13.379 ;
     RECT  20.832 7.091 21.612 13.573 ;
     RECT  26.208 13.141 27.012 13.573 ;
     RECT  31.968 11.171 32.412 13.573 ;
     RECT  34.8 12.563 35.112 13.573 ;
     RECT  50.4 6.947 51.312 13.573 ;
     RECT  18.48 12.035 18.912 13.669 ;
     RECT  10.368 12.565 10.812 13.715 ;
     RECT  53.7 12.515 54.552 13.813 ;
     RECT  50.4 13.573 51.576 13.907 ;
     RECT  47.856 9.637 48.612 13.909 ;
     RECT  64.272 12.901 64.92 14.099 ;
     RECT  6.96 12.611 8.328 14.101 ;
     RECT  28.08 13.333 28.104 14.101 ;
     RECT  29.4 12.515 30.264 14.101 ;
     RECT  53.7 13.813 55.08 14.101 ;
     RECT  63.264 12.563 63.288 14.101 ;
     RECT  64.5 14.099 64.92 14.101 ;
     RECT  47.712 13.909 48.612 14.149 ;
     RECT  28.08 14.101 30.264 14.195 ;
     RECT  41.856 13.139 43.212 14.197 ;
     RECT  45.6 12.803 46.104 14.197 ;
     RECT  6.96 14.101 9.144 14.243 ;
     RECT  37.5 11.459 38.232 14.243 ;
     RECT  50.688 13.907 51.576 14.243 ;
     RECT  25.632 13.573 27.012 14.291 ;
     RECT  18.48 13.669 19.128 14.485 ;
     RECT  20.832 13.573 22.2 14.485 ;
     RECT  67.2 13.379 70.212 14.675 ;
     RECT  5.1 12.947 5.412 14.725 ;
     RECT  10.5 13.715 10.812 14.725 ;
     RECT  68.64 14.675 70.212 14.725 ;
     RECT  61.8 11.267 62.112 14.773 ;
     RECT  63.264 14.101 63.336 14.773 ;
     RECT  64.5 14.101 64.968 14.867 ;
     RECT  39.936 12.469 40.512 14.869 ;
     RECT  53.7 14.101 55.272 14.917 ;
     RECT  28.464 14.195 30.264 14.963 ;
     RECT  26.7 14.291 27.012 14.965 ;
     RECT  13.2 13.331 13.512 15.205 ;
     RECT  5.1 14.725 5.64 15.301 ;
     RECT  47.712 14.149 48.984 15.347 ;
     RECT  5.1 15.301 5.688 15.349 ;
     RECT  50.688 14.243 51.312 15.349 ;
     RECT  59.1 12.563 59.412 15.349 ;
     RECT  25.632 14.291 25.656 15.395 ;
     RECT  41.856 14.197 43.992 15.395 ;
     RECT  6.96 14.243 8.328 15.491 ;
     RECT  64.5 14.867 64.92 15.491 ;
     RECT  34.8 13.573 35.736 15.587 ;
     RECT  18.48 14.485 22.2 15.589 ;
     RECT  23.52 11.941 24.312 15.685 ;
     RECT  68.64 14.725 70.728 15.731 ;
     RECT  17.568 15.589 22.2 15.875 ;
     RECT  9.696 14.725 10.812 15.925 ;
     RECT  39.888 14.869 40.512 15.971 ;
     RECT  4.992 15.349 5.688 15.973 ;
     RECT  59.1 15.349 60.36 15.973 ;
     RECT  26.7 14.965 27.336 16.019 ;
     RECT  41.856 15.395 43.212 16.019 ;
     RECT  45.6 14.197 46.2 16.019 ;
     RECT  68.64 15.731 68.76 16.115 ;
     RECT  42.432 16.019 43.212 16.307 ;
     RECT  17.568 15.875 21.612 16.357 ;
     RECT  23.472 15.685 24.312 16.357 ;
     RECT  15.408 12.563 16.212 16.403 ;
     RECT  47.712 15.347 48.612 16.453 ;
     RECT  6.96 15.491 8.232 16.501 ;
     RECT  9.456 15.925 10.812 16.501 ;
     RECT  50.4 15.349 51.312 16.501 ;
     RECT  34.8 15.587 35.112 16.549 ;
     RECT  52.992 14.917 55.272 16.549 ;
     RECT  56.4 12.515 56.712 16.549 ;
     RECT  13.056 15.205 13.512 16.595 ;
     RECT  28.512 14.963 30.264 16.595 ;
     RECT  31.92 13.573 32.412 16.691 ;
     RECT  6.864 16.501 8.232 16.693 ;
     RECT  9.456 16.501 11.4 16.693 ;
     RECT  58.656 15.973 60.36 16.835 ;
     RECT  6.864 16.693 11.4 16.883 ;
     RECT  4.704 15.973 5.688 16.933 ;
     RECT  6.864 16.883 8.424 16.933 ;
     RECT  15.456 16.403 16.212 16.933 ;
     RECT  17.472 16.357 21.612 16.933 ;
     RECT  52.992 16.549 56.712 16.981 ;
     RECT  61.8 14.773 63.336 17.075 ;
     RECT  45.6 16.019 46.008 17.077 ;
     RECT  15.456 16.933 21.612 17.123 ;
     RECT  52.944 16.981 56.712 17.123 ;
     RECT  50.112 16.501 51.312 17.171 ;
     RECT  17.568 17.123 21.612 17.219 ;
     RECT  23.376 16.357 24.312 17.267 ;
     RECT  25.44 15.973 25.464 17.363 ;
     RECT  9.456 16.883 11.4 17.459 ;
     RECT  4.704 16.933 8.424 17.507 ;
     RECT  13.2 16.595 13.512 17.605 ;
     RECT  26.7 16.019 27.012 17.605 ;
     RECT  9.456 17.459 11.256 17.651 ;
     RECT  40.2 15.971 40.512 17.653 ;
     RECT  31.968 16.691 32.412 17.699 ;
     RECT  45.6 17.077 46.68 17.845 ;
     RECT  47.664 16.453 48.612 17.845 ;
     RECT  42.768 16.307 43.212 17.939 ;
     RECT  58.704 16.835 60.36 17.939 ;
     RECT  68.736 16.115 68.76 17.987 ;
     RECT  28.8 16.595 30.264 18.037 ;
     RECT  5.1 17.507 8.424 18.133 ;
     RECT  13.2 17.605 14.28 18.133 ;
     RECT  52.992 17.123 56.712 18.179 ;
     RECT  34.176 16.549 35.112 18.181 ;
     RECT  44.496 16.501 44.52 18.227 ;
     RECT  20.112 17.219 21.612 18.275 ;
     RECT  24 17.267 24.312 18.421 ;
     RECT  24 18.421 24.504 18.611 ;
     RECT  42.9 17.939 43.212 18.661 ;
     RECT  45.6 17.845 48.612 18.661 ;
     RECT  26.208 17.605 27.012 18.709 ;
     RECT  50.4 17.171 51.312 18.755 ;
     RECT  9.936 17.651 11.256 18.757 ;
     RECT  12.288 18.133 14.28 18.757 ;
     RECT  61.8 17.075 63.288 18.757 ;
     RECT  42.9 18.661 43.992 18.899 ;
     RECT  45.12 18.661 48.612 19.043 ;
     RECT  39.792 17.653 40.512 19.139 ;
     RECT  48.3 19.043 48.612 19.141 ;
     RECT  45.12 19.043 46.968 19.235 ;
     RECT  28.8 18.037 30.792 19.283 ;
     RECT  5.1 18.133 8.76 19.331 ;
     RECT  24 18.611 24.312 19.381 ;
     RECT  9.936 18.757 14.28 19.427 ;
     RECT  61.536 18.757 63.288 19.427 ;
     RECT  10.32 19.427 14.28 19.475 ;
     RECT  52.992 18.179 55.272 19.571 ;
     RECT  4.032 18.181 4.056 19.619 ;
     RECT  7.632 19.331 8.76 19.619 ;
     RECT  39.888 19.139 40.512 19.621 ;
     RECT  26.064 18.709 27.012 19.763 ;
     RECT  59.1 17.939 60.36 19.765 ;
     RECT  50.544 18.755 51.312 19.811 ;
     RECT  10.32 19.475 13.656 19.859 ;
     RECT  7.8 19.619 8.76 19.861 ;
     RECT  39.888 19.621 40.632 19.907 ;
     RECT  20.832 18.275 21.612 19.909 ;
     RECT  67.2 14.675 67.512 19.909 ;
     RECT  14.784 19.621 14.808 20.003 ;
     RECT  53.04 19.571 55.272 20.003 ;
     RECT  69.9 15.731 70.728 20.003 ;
     RECT  7.8 19.861 8.904 20.053 ;
     RECT  56.4 18.179 56.712 20.053 ;
     RECT  17.568 17.219 19.128 20.099 ;
     RECT  28.8 19.283 30.648 20.147 ;
     RECT  37.5 14.243 37.812 20.149 ;
     RECT  20.832 19.909 22.488 20.291 ;
     RECT  45.12 19.235 46.632 20.291 ;
     RECT  7.8 20.053 9.048 20.339 ;
     RECT  40.2 19.907 40.632 20.339 ;
     RECT  34.176 18.181 35.88 20.531 ;
     RECT  56.4 20.053 56.808 20.675 ;
     RECT  59.1 19.765 60.408 20.869 ;
     RECT  10.368 19.859 13.656 20.963 ;
     RECT  23.472 19.381 24.312 20.965 ;
     RECT  10.368 20.963 11.688 21.013 ;
     RECT  10.176 21.013 11.688 21.155 ;
     RECT  23.472 20.965 24.408 21.155 ;
     RECT  58.224 20.869 60.408 21.155 ;
     RECT  61.8 19.427 63.288 21.155 ;
     RECT  7.8 20.339 8.952 21.253 ;
     RECT  34.176 20.531 35.112 21.253 ;
     RECT  45.6 20.291 46.632 21.253 ;
     RECT  23.472 21.155 24.312 21.299 ;
     RECT  26.208 19.763 27.012 21.637 ;
     RECT  45.6 21.253 46.68 21.637 ;
     RECT  58.224 21.155 60.36 21.683 ;
     RECT  66.288 19.909 67.512 21.683 ;
     RECT  20.832 20.291 21.612 21.685 ;
     RECT  26.208 21.637 27.624 21.779 ;
     RECT  15.9 17.123 16.212 21.877 ;
     RECT  32.1 17.699 32.412 21.925 ;
     RECT  42.9 18.899 43.212 21.925 ;
     RECT  64.5 15.491 64.812 21.925 ;
     RECT  20.496 21.685 21.612 21.971 ;
     RECT  33.408 21.253 35.112 21.971 ;
     RECT  15.504 21.877 16.212 22.165 ;
     RECT  48.3 19.141 48.888 22.165 ;
     RECT  58.224 21.683 60.216 22.165 ;
     RECT  61.8 21.155 62.112 22.213 ;
     RECT  18.6 20.099 19.128 22.259 ;
     RECT  31.872 21.925 32.412 22.259 ;
     RECT  50.688 19.811 51.312 22.259 ;
     RECT  69.9 20.003 70.68 22.259 ;
     RECT  10.176 21.155 10.812 22.355 ;
     RECT  28.8 20.147 29.832 22.501 ;
     RECT  56.4 20.675 56.712 22.549 ;
     RECT  12.912 20.963 13.656 22.597 ;
     RECT  17.568 20.099 17.592 22.597 ;
     RECT  18.6 22.259 18.912 22.597 ;
     RECT  12.24 22.597 13.656 22.691 ;
     RECT  44.4 21.829 44.424 22.739 ;
     RECT  42.72 21.925 43.212 22.741 ;
     RECT  58.128 22.165 60.216 22.741 ;
     RECT  61.68 22.213 62.112 22.741 ;
     RECT  36.096 21.541 36.12 22.787 ;
     RECT  68.592 21.541 68.616 22.787 ;
     RECT  42.72 22.741 43.608 22.789 ;
     RECT  48.3 22.165 49.08 22.883 ;
     RECT  23.904 21.299 24.312 22.885 ;
     RECT  42.576 22.789 43.608 22.931 ;
     RECT  23.904 22.885 25.128 23.075 ;
     RECT  58.128 22.741 62.112 23.125 ;
     RECT  63.264 21.155 63.288 23.125 ;
     RECT  7.488 21.253 8.952 23.317 ;
     RECT  10.368 22.355 10.812 23.317 ;
     RECT  58.128 23.125 63.288 23.365 ;
     RECT  42.72 22.931 43.608 23.411 ;
     RECT  45.504 21.637 46.68 23.411 ;
     RECT  48.3 22.883 48.612 23.509 ;
     RECT  37.5 20.149 38.328 23.557 ;
     RECT  67.2 21.683 67.512 23.797 ;
     RECT  7.488 23.317 10.812 23.845 ;
     RECT  12.24 22.691 13.608 23.845 ;
     RECT  66.24 23.797 67.656 23.893 ;
     RECT  7.488 23.845 13.608 23.987 ;
     RECT  17.568 22.597 18.912 23.987 ;
     RECT  34.032 21.971 35.112 23.987 ;
     RECT  58.128 23.365 63.336 23.987 ;
     RECT  60.96 23.987 63.288 24.083 ;
     RECT  66.24 23.893 67.704 24.179 ;
     RECT  69.9 22.259 70.212 24.181 ;
     RECT  45.6 23.411 46.68 24.227 ;
     RECT  23.904 23.075 24.936 24.277 ;
     RECT  26.7 21.779 27.624 24.373 ;
     RECT  28.8 22.501 30.024 24.419 ;
     RECT  9.696 23.987 13.608 24.421 ;
     RECT  56.4 22.549 56.904 24.421 ;
     RECT  58.128 23.987 59.412 24.467 ;
     RECT  32.1 22.259 32.412 24.469 ;
     RECT  37.5 23.557 38.376 24.469 ;
     RECT  47.808 23.509 48.612 24.469 ;
     RECT  66.24 24.179 67.656 24.659 ;
     RECT  45.6 24.227 45.912 24.709 ;
     RECT  60.96 24.083 62.76 24.755 ;
     RECT  9.696 24.421 14.136 24.899 ;
     RECT  45.024 24.709 45.912 24.899 ;
     RECT  23.904 24.277 25.656 24.995 ;
     RECT  58.656 24.467 59.412 24.995 ;
     RECT  5.1 19.331 6.264 24.997 ;
     RECT  7.488 23.987 8.112 24.997 ;
     RECT  24 24.995 25.656 25.045 ;
     RECT  26.7 24.373 27.816 25.045 ;
     RECT  47.808 24.469 48.984 25.045 ;
     RECT  53.7 20.003 55.272 25.045 ;
     RECT  47.664 25.045 48.984 25.091 ;
     RECT  56.304 24.421 56.904 25.091 ;
     RECT  31.344 24.469 32.412 25.139 ;
     RECT  56.304 25.091 56.952 25.139 ;
     RECT  24 25.045 27.816 25.189 ;
     RECT  28.8 24.419 29.712 25.189 ;
     RECT  17.568 23.987 17.592 25.285 ;
     RECT  37.5 24.469 38.76 25.285 ;
     RECT  67.2 24.659 67.656 25.285 ;
     RECT  24 25.189 29.712 25.331 ;
     RECT  64.5 21.925 64.968 25.429 ;
     RECT  24 25.331 27.012 25.475 ;
     RECT  52.512 25.285 52.536 25.475 ;
     RECT  51 22.259 51.312 25.525 ;
     RECT  36.816 25.285 38.76 25.573 ;
     RECT  40.2 20.339 40.512 25.573 ;
     RECT  58.992 24.995 59.412 25.573 ;
     RECT  10.368 24.899 14.136 25.667 ;
     RECT  36.816 25.573 40.512 25.667 ;
     RECT  56.4 25.139 56.952 25.667 ;
     RECT  15.12 22.165 16.212 25.669 ;
     RECT  17.328 25.285 17.592 25.669 ;
     RECT  61.68 24.755 62.76 25.715 ;
     RECT  13.104 25.667 14.136 25.811 ;
     RECT  10.368 25.667 11.544 25.907 ;
     RECT  56.4 25.667 56.904 25.907 ;
     RECT  39.504 25.667 40.512 26.051 ;
     RECT  58.992 25.573 60.408 26.051 ;
     RECT  32.1 25.139 32.412 26.101 ;
     RECT  59.1 26.051 60.408 26.101 ;
     RECT  61.68 25.715 62.112 26.101 ;
     RECT  63.84 25.429 64.968 26.147 ;
     RECT  41.856 25.813 41.88 26.197 ;
     RECT  42.9 23.411 43.608 26.197 ;
     RECT  59.1 26.101 62.112 26.243 ;
     RECT  47.664 25.091 48.612 26.245 ;
     RECT  20.784 21.971 21.612 26.291 ;
     RECT  33.696 24.469 33.72 26.293 ;
     RECT  34.8 23.987 35.112 26.293 ;
     RECT  2.4 11.459 2.712 26.629 ;
     RECT  13.104 25.811 13.512 26.629 ;
     RECT  15.12 25.669 17.592 26.629 ;
     RECT  18.6 23.987 18.912 26.629 ;
     RECT  53.7 25.045 55.32 26.629 ;
     RECT  56.4 25.907 56.712 26.629 ;
     RECT  64.128 26.147 64.968 26.677 ;
     RECT  31.968 26.101 32.412 26.819 ;
     RECT  33.696 26.293 35.112 26.819 ;
     RECT  64.128 26.677 65.064 26.915 ;
     RECT  40.2 26.051 40.512 27.109 ;
     RECT  10.5 25.907 11.544 27.205 ;
     RECT  15.12 26.629 18.912 27.301 ;
     RECT  24 25.475 24.648 27.301 ;
     RECT  25.92 25.475 27.012 27.301 ;
     RECT  59.1 26.243 60.408 27.301 ;
     RECT  61.68 26.243 62.112 27.301 ;
     RECT  5.1 24.997 8.112 27.395 ;
     RECT  12.672 26.629 13.512 27.493 ;
     RECT  39.312 27.109 40.512 27.541 ;
     RECT  9.216 26.725 9.24 27.685 ;
     RECT  10.272 27.205 11.544 27.685 ;
     RECT  12.624 27.493 13.512 27.685 ;
     RECT  9.216 27.685 11.544 27.731 ;
     RECT  47.472 26.245 48.612 27.733 ;
     RECT  41.856 26.197 43.608 27.877 ;
     RECT  59.1 27.301 62.112 27.877 ;
     RECT  39.312 27.541 40.632 27.923 ;
     RECT  2.4 26.629 2.952 27.971 ;
     RECT  6.864 27.395 8.112 28.019 ;
     RECT  15.12 27.301 19.416 28.163 ;
     RECT  36.816 25.667 37.812 28.213 ;
     RECT  58.128 27.877 62.112 28.261 ;
     RECT  67.2 25.285 68.616 28.309 ;
     RECT  69.792 24.181 70.212 28.309 ;
     RECT  30.816 27.157 30.84 28.355 ;
     RECT  34.8 26.819 35.112 28.405 ;
     RECT  64.128 26.915 64.968 28.451 ;
     RECT  6.912 28.019 8.112 28.453 ;
     RECT  9.216 27.731 10.812 28.453 ;
     RECT  24 27.301 27.012 28.453 ;
     RECT  36.672 28.213 37.812 28.501 ;
     RECT  47.424 27.733 48.612 28.643 ;
     RECT  58.128 28.261 62.232 28.787 ;
     RECT  41.856 27.877 44.28 28.789 ;
     RECT  5.1 27.395 5.544 28.981 ;
     RECT  64.128 28.451 64.812 28.981 ;
     RECT  58.128 28.787 62.112 29.075 ;
     RECT  23.568 28.453 27.012 29.219 ;
     RECT  33.696 26.819 33.72 29.219 ;
     RECT  58.704 29.075 62.112 29.219 ;
     RECT  66.096 27.733 66.12 29.219 ;
     RECT  12.528 27.685 13.512 29.315 ;
     RECT  24 29.219 27.012 29.363 ;
     RECT  25.632 29.363 27.012 29.507 ;
     RECT  58.704 29.219 59.412 29.507 ;
     RECT  15.12 28.163 18.912 29.605 ;
     RECT  26.7 29.507 27.012 29.605 ;
     RECT  51 25.525 51.912 29.605 ;
     RECT  4.992 28.981 5.544 29.651 ;
     RECT  12.672 29.315 13.512 29.651 ;
     RECT  6.912 28.453 10.812 29.747 ;
     RECT  34.8 28.405 35.352 29.795 ;
     RECT  67.2 28.309 70.212 29.795 ;
     RECT  41.856 28.789 44.472 29.989 ;
     RECT  53.7 26.629 56.712 30.035 ;
     RECT  39.312 27.923 40.512 30.037 ;
     RECT  41.616 29.989 44.472 30.037 ;
     RECT  67.2 29.795 67.512 30.037 ;
     RECT  68.592 29.795 70.212 30.083 ;
     RECT  26.7 29.605 27.336 30.275 ;
     RECT  39.312 30.037 44.472 30.275 ;
     RECT  34.8 29.795 35.112 30.277 ;
     RECT  53.7 30.035 55.32 30.371 ;
     RECT  60.384 29.219 62.112 30.371 ;
     RECT  4.992 29.651 5.412 30.373 ;
     RECT  32.1 26.819 32.412 30.421 ;
     RECT  15.12 29.605 19.368 30.467 ;
     RECT  34.704 30.277 35.112 30.467 ;
     RECT  51 29.605 52.248 30.467 ;
     RECT  24 29.363 24.648 30.517 ;
     RECT  25.632 29.507 25.656 30.517 ;
     RECT  51 30.467 51.912 30.613 ;
     RECT  53.7 30.371 55.272 30.613 ;
     RECT  7.248 29.747 10.812 30.757 ;
     RECT  12.768 29.651 13.512 30.757 ;
     RECT  15.9 30.467 19.368 30.803 ;
     RECT  50.64 30.613 51.912 30.803 ;
     RECT  39.312 30.275 41.64 30.851 ;
     RECT  67.104 30.037 67.512 30.899 ;
     RECT  74.64 30.757 74.664 30.899 ;
     RECT  12.48 30.757 13.512 30.947 ;
     RECT  64.08 28.981 64.812 31.189 ;
     RECT  59.1 29.507 59.412 31.285 ;
     RECT  61.008 30.371 62.112 31.331 ;
     RECT  24 30.517 25.656 31.379 ;
     RECT  4.512 30.373 5.412 31.525 ;
     RECT  2.4 27.971 2.712 31.669 ;
     RECT  15.9 30.803 19.032 31.765 ;
     RECT  56.4 30.035 56.712 31.765 ;
     RECT  68.592 30.083 68.616 31.765 ;
     RECT  69.792 30.083 70.212 31.765 ;
     RECT  64.08 31.189 64.92 31.859 ;
     RECT  15.9 31.765 19.128 31.861 ;
     RECT  21.072 26.291 21.612 31.861 ;
     RECT  39.312 30.851 40.512 31.861 ;
     RECT  15.072 31.861 19.128 31.907 ;
     RECT  4.512 31.525 5.736 31.955 ;
     RECT  15.072 31.907 19.032 31.955 ;
     RECT  28.8 25.331 29.712 31.957 ;
     RECT  15.072 31.955 18.912 32.245 ;
     RECT  6.864 30.757 10.812 32.291 ;
     RECT  49.92 31.141 49.944 32.291 ;
     RECT  64.08 31.859 64.812 32.341 ;
     RECT  6.864 32.291 9.48 32.437 ;
     RECT  48.3 28.643 48.612 32.437 ;
     RECT  24 31.379 25.32 32.483 ;
     RECT  59.1 31.285 59.544 32.531 ;
     RECT  2.4 31.669 3.432 32.579 ;
     RECT  42.72 30.275 43.608 32.629 ;
     RECT  12.768 30.947 13.512 32.771 ;
     RECT  38.976 31.861 40.512 32.771 ;
     RECT  51 30.803 51.912 32.915 ;
     RECT  59.1 32.531 59.412 32.917 ;
     RECT  31.968 30.421 32.412 32.963 ;
     RECT  45.6 24.899 45.912 32.965 ;
     RECT  20.544 31.861 21.612 33.013 ;
     RECT  28.512 31.957 29.712 33.059 ;
     RECT  24 32.483 24.648 33.251 ;
     RECT  4.56 31.955 5.736 33.299 ;
     RECT  28.8 33.059 29.712 33.301 ;
     RECT  10.5 32.291 10.812 33.445 ;
     RECT  4.752 33.299 5.736 33.541 ;
     RECT  6.816 32.437 9.48 33.541 ;
     RECT  56.4 31.765 57 33.589 ;
     RECT  58.512 32.917 59.412 33.589 ;
     RECT  61.8 31.331 62.112 33.589 ;
     RECT  24 33.251 24.504 33.683 ;
     RECT  63.552 32.341 64.812 33.731 ;
     RECT  47.904 32.437 48.612 33.829 ;
     RECT  13.2 32.771 13.512 33.877 ;
     RECT  4.752 33.541 9.48 33.923 ;
     RECT  13.104 33.877 13.512 33.973 ;
     RECT  14.784 32.245 18.912 33.973 ;
     RECT  67.2 30.899 67.512 33.973 ;
     RECT  68.592 31.765 70.212 33.973 ;
     RECT  13.104 33.973 18.912 34.019 ;
     RECT  67.2 33.973 70.212 34.069 ;
     RECT  22.8 33.877 22.824 34.115 ;
     RECT  13.104 34.019 14.28 34.163 ;
     RECT  36.48 28.501 37.812 34.163 ;
     RECT  47.904 33.829 49.032 34.165 ;
     RECT  53.568 30.613 55.272 34.165 ;
     RECT  56.4 33.589 57.24 34.165 ;
     RECT  47.904 34.165 49.608 34.211 ;
     RECT  61.68 33.589 62.112 34.211 ;
     RECT  66.576 34.069 70.212 34.211 ;
     RECT  53.568 34.165 57.24 34.213 ;
     RECT  10.5 33.445 11.256 34.405 ;
     RECT  20.544 33.013 21.72 34.499 ;
     RECT  41.616 30.851 41.64 34.739 ;
     RECT  53.28 34.213 57.24 34.739 ;
     RECT  36.576 34.163 37.812 34.741 ;
     RECT  5.1 33.923 9.48 34.835 ;
     RECT  21.072 34.499 21.72 34.835 ;
     RECT  10.5 34.405 11.688 34.883 ;
     RECT  49.584 34.211 49.608 34.931 ;
     RECT  53.28 34.739 55.08 34.979 ;
     RECT  53.7 34.979 55.08 35.027 ;
     RECT  58.512 33.589 59.784 35.027 ;
     RECT  2.4 32.579 3.288 35.077 ;
     RECT  5.1 34.835 5.412 35.173 ;
     RECT  28.8 33.301 29.832 35.173 ;
     RECT  6.432 34.835 9.48 35.315 ;
     RECT  34.8 30.467 35.112 35.317 ;
     RECT  36.576 34.741 38.088 35.317 ;
     RECT  42.72 32.629 43.656 35.317 ;
     RECT  51 32.915 51.576 35.317 ;
     RECT  13.2 34.163 14.28 35.413 ;
     RECT  64.128 33.731 64.812 35.413 ;
     RECT  50.736 35.317 51.576 35.459 ;
     RECT  15.504 34.019 18.912 35.461 ;
     RECT  25.68 34.069 25.704 35.509 ;
     RECT  42.72 35.317 43.848 35.605 ;
     RECT  28.704 35.173 29.832 35.701 ;
     RECT  30.864 33.013 30.888 35.701 ;
     RECT  25.632 35.509 25.704 35.747 ;
     RECT  56.16 34.739 57.24 35.845 ;
     RECT  15.408 35.461 18.912 35.939 ;
     RECT  15.9 35.939 18.912 36.085 ;
     RECT  34.8 35.317 38.088 36.085 ;
     RECT  45.504 32.965 45.912 36.275 ;
     RECT  59.1 35.027 59.784 36.277 ;
     RECT  67.2 34.211 70.212 36.325 ;
     RECT  67.104 36.325 70.212 36.371 ;
     RECT  26.7 30.275 27.012 36.373 ;
     RECT  28.704 35.701 30.888 36.373 ;
     RECT  10.5 34.883 11.352 36.421 ;
     RECT  21.072 34.835 21.612 36.421 ;
     RECT  2.4 35.077 3.96 36.515 ;
     RECT  6.96 35.315 9.48 36.515 ;
     RECT  63.504 35.413 64.812 36.515 ;
     RECT  61.8 34.211 62.112 36.517 ;
     RECT  69.312 36.371 70.212 36.517 ;
     RECT  71.28 35.317 71.304 36.517 ;
     RECT  50.736 35.459 51.432 36.563 ;
     RECT  64.128 36.515 64.812 36.563 ;
     RECT  69.312 36.517 71.304 36.563 ;
     RECT  51 36.563 51.432 36.565 ;
     RECT  9.456 36.515 9.48 36.661 ;
     RECT  10.5 36.421 11.496 36.661 ;
     RECT  25.68 35.747 25.704 36.755 ;
     RECT  32.1 32.963 32.412 36.805 ;
     RECT  59.1 36.277 59.832 36.805 ;
     RECT  6.96 36.515 8.376 36.851 ;
     RECT  21.072 36.421 22.248 36.901 ;
     RECT  45.6 36.275 45.912 36.949 ;
     RECT  2.4 36.515 3.912 36.995 ;
     RECT  15.9 36.085 19.032 36.997 ;
     RECT  24 33.683 24.456 36.997 ;
     RECT  56.16 35.845 57.48 37.331 ;
     RECT  39.312 32.771 40.512 37.381 ;
     RECT  56.16 37.331 57.24 37.429 ;
     RECT  34.8 36.085 38.184 37.475 ;
     RECT  9.456 36.661 11.496 37.477 ;
     RECT  12.816 35.413 14.28 37.477 ;
     RECT  53.7 35.027 54.552 37.525 ;
     RECT  9.456 37.477 14.28 37.619 ;
     RECT  34.8 37.475 37.992 37.619 ;
     RECT  39.312 37.381 41.064 37.619 ;
     RECT  36.576 37.619 37.992 37.667 ;
     RECT  42.72 35.605 43.944 37.667 ;
     RECT  59.1 36.805 60.216 37.667 ;
     RECT  69.792 36.563 71.304 37.667 ;
     RECT  23.904 36.997 24.456 37.715 ;
     RECT  69.792 37.667 70.344 37.715 ;
     RECT  21.072 36.901 22.584 37.955 ;
     RECT  32.1 36.805 32.52 38.005 ;
     RECT  42.9 37.667 43.944 38.243 ;
     RECT  55.872 37.429 57.24 38.243 ;
     RECT  45.6 36.949 46.152 38.291 ;
     RECT  2.4 36.995 2.904 38.389 ;
     RECT  3.888 36.995 3.912 38.389 ;
     RECT  4.992 35.173 5.412 38.389 ;
     RECT  59.1 37.667 59.832 38.435 ;
     RECT  12.192 37.619 14.28 38.579 ;
     RECT  26.7 36.373 30.888 38.579 ;
     RECT  34.8 37.619 35.112 38.581 ;
     RECT  36.576 37.667 37.812 38.581 ;
     RECT  59.1 38.435 59.544 38.675 ;
     RECT  51 36.565 51.48 38.677 ;
     RECT  67.104 36.371 67.512 38.677 ;
     RECT  7.056 36.851 8.376 38.773 ;
     RECT  9.456 37.619 10.812 38.773 ;
     RECT  15.36 36.997 19.032 38.869 ;
     RECT  2.4 38.389 5.412 38.915 ;
     RECT  24 37.715 24.456 38.917 ;
     RECT  23.904 38.917 24.456 38.965 ;
     RECT  32.1 38.005 33.048 39.011 ;
     RECT  21.072 37.955 21.612 39.013 ;
     RECT  47.904 34.211 48.612 39.013 ;
     RECT  50.88 38.677 51.48 39.013 ;
     RECT  26.7 38.579 29.712 39.155 ;
     RECT  15.36 38.869 19.128 39.347 ;
     RECT  28.704 39.155 29.712 39.395 ;
     RECT  18.288 39.347 19.128 39.443 ;
     RECT  30.864 38.579 30.888 39.493 ;
     RECT  32.1 39.011 32.412 39.493 ;
     RECT  18.288 39.443 19.032 39.539 ;
     RECT  67.008 38.677 67.512 39.635 ;
     RECT  64.5 36.563 64.812 39.685 ;
     RECT  5.1 38.915 5.412 39.733 ;
     RECT  7.056 38.773 10.812 39.733 ;
     RECT  15.36 39.347 17.256 39.779 ;
     RECT  12.816 38.579 14.28 39.877 ;
     RECT  2.4 38.915 3.912 39.923 ;
     RECT  5.1 39.733 10.812 39.971 ;
     RECT  20.928 39.013 21.612 40.069 ;
     RECT  42.9 38.243 43.32 40.117 ;
     RECT  30.864 39.493 32.412 40.259 ;
     RECT  5.1 39.971 8.112 40.309 ;
     RECT  12.816 39.877 14.376 40.355 ;
     RECT  53.568 37.525 54.552 40.453 ;
     RECT  25.488 39.829 25.512 40.499 ;
     RECT  50.88 39.013 51.864 40.499 ;
     RECT  2.4 39.923 3.24 40.547 ;
     RECT  23.904 38.965 24.504 40.547 ;
     RECT  12.912 40.355 14.376 40.595 ;
     RECT  64.5 39.685 64.92 40.645 ;
     RECT  69.9 37.715 70.344 40.693 ;
     RECT  42.9 40.117 43.944 40.837 ;
     RECT  12.912 40.595 14.28 40.883 ;
     RECT  4.56 40.309 8.112 40.933 ;
     RECT  20.304 40.069 21.612 40.981 ;
     RECT  22.752 39.253 22.776 40.981 ;
     RECT  32.1 40.259 32.412 40.981 ;
     RECT  47.472 39.013 48.612 40.981 ;
     RECT  26.7 39.155 27.012 41.029 ;
     RECT  28.752 39.395 29.712 41.029 ;
     RECT  4.56 40.933 8.376 41.075 ;
     RECT  24 40.547 24.504 41.123 ;
     RECT  42.9 40.837 44.52 41.123 ;
     RECT  68.544 39.829 68.568 41.171 ;
     RECT  53.52 40.453 54.552 41.219 ;
     RECT  15.552 39.779 17.256 41.363 ;
     RECT  20.304 40.981 22.776 41.411 ;
     RECT  30.864 40.259 30.888 41.461 ;
     RECT  71.568 38.725 71.592 41.507 ;
     RECT  34.8 38.581 37.812 41.509 ;
     RECT  64.368 40.645 64.92 41.509 ;
     RECT  32.1 40.981 32.904 41.651 ;
     RECT  4.992 41.075 8.376 41.653 ;
     RECT  61.8 36.517 62.952 41.749 ;
     RECT  64.368 41.509 64.968 41.749 ;
     RECT  21.072 41.411 22.776 41.797 ;
     RECT  24 41.123 24.456 41.797 ;
     RECT  4.992 41.653 8.472 41.843 ;
     RECT  44.496 41.123 44.52 41.939 ;
     RECT  12.912 40.883 13.512 42.227 ;
     RECT  26.7 41.029 29.712 42.227 ;
     RECT  34.8 41.509 37.944 42.227 ;
     RECT  51 40.499 51.864 42.227 ;
     RECT  13.104 42.227 13.512 42.229 ;
     RECT  30.864 41.461 30.984 42.275 ;
     RECT  2.4 40.547 2.712 42.277 ;
     RECT  3.792 42.133 3.816 42.277 ;
     RECT  13.104 42.229 13.608 42.323 ;
     RECT  45.6 38.291 45.912 42.469 ;
     RECT  46.896 40.981 48.612 42.469 ;
     RECT  59.1 38.675 59.412 42.469 ;
     RECT  61.8 41.749 64.968 42.515 ;
     RECT  61.8 42.515 62.952 42.613 ;
     RECT  4.992 41.843 8.112 42.755 ;
     RECT  64.368 42.515 64.968 42.755 ;
     RECT  28.752 42.227 29.712 42.805 ;
     RECT  21.072 41.797 24.456 42.851 ;
     RECT  42.9 41.123 43.212 42.853 ;
     RECT  9.456 39.971 10.812 42.997 ;
     RECT  13.2 42.323 13.608 43.045 ;
     RECT  9.12 42.997 10.812 43.187 ;
     RECT  2.4 42.277 3.816 43.189 ;
     RECT  4.992 42.755 6.264 43.189 ;
     RECT  26.7 42.227 27.012 43.285 ;
     RECT  28.752 42.805 29.832 43.717 ;
     RECT  67.104 39.635 67.512 43.765 ;
     RECT  30.864 42.275 30.888 43.811 ;
     RECT  45.6 42.469 48.612 43.811 ;
     RECT  21.072 42.851 22.584 43.813 ;
     RECT  39.312 37.619 40.512 43.813 ;
     RECT  2.4 43.189 6.264 43.955 ;
     RECT  15.9 41.363 17.256 43.955 ;
     RECT  24 42.851 24.456 44.003 ;
     RECT  15.9 43.955 17.064 44.051 ;
     RECT  20.832 43.813 22.584 44.053 ;
     RECT  34.8 42.227 37.812 44.053 ;
     RECT  13.2 43.045 13.704 44.149 ;
     RECT  7.8 42.755 8.112 44.245 ;
     RECT  9.264 43.187 10.812 44.245 ;
     RECT  53.7 41.219 54.552 44.389 ;
     RECT  12.384 44.149 13.704 44.435 ;
     RECT  64.5 42.755 64.812 44.437 ;
     RECT  3.792 43.955 6.264 44.483 ;
     RECT  15.9 44.051 16.584 44.483 ;
     RECT  42.288 42.853 43.212 44.483 ;
     RECT  42.72 44.483 43.212 44.531 ;
     RECT  58.8 42.469 59.412 44.627 ;
     RECT  67.104 43.765 67.608 44.675 ;
     RECT  20.832 44.053 23.016 44.867 ;
     RECT  28.272 43.717 29.832 44.965 ;
     RECT  3.792 44.483 5.688 45.011 ;
     RECT  39.312 43.813 40.872 45.011 ;
     RECT  25.824 43.285 27.012 45.059 ;
     RECT  28.272 44.965 30.072 45.059 ;
     RECT  52.32 43.141 52.344 45.059 ;
     RECT  34.8 44.053 37.944 45.155 ;
     RECT  32.1 41.651 32.412 45.253 ;
     RECT  13.2 44.435 13.704 45.445 ;
     RECT  14.688 44.149 14.712 45.445 ;
     RECT  15.9 44.483 16.212 45.541 ;
     RECT  44.448 44.437 44.472 45.587 ;
     RECT  67.104 44.675 67.512 45.635 ;
     RECT  69.9 40.693 70.584 45.635 ;
     RECT  3.936 45.011 5.688 45.685 ;
     RECT  28.752 45.059 30.072 45.731 ;
     RECT  47.472 43.811 48.612 45.731 ;
     RECT  61.68 42.613 62.952 45.731 ;
     RECT  25.872 45.059 27.012 45.779 ;
     RECT  42.768 44.531 43.212 45.829 ;
     RECT  20.832 44.867 22.68 45.923 ;
     RECT  15.9 45.541 16.344 46.019 ;
     RECT  3.936 45.685 5.784 46.021 ;
     RECT  18.288 39.539 18.912 46.069 ;
     RECT  69.9 45.635 70.344 46.069 ;
     RECT  7.8 44.245 10.812 46.115 ;
     RECT  69.552 46.069 70.344 46.115 ;
     RECT  26.7 45.779 27.012 46.117 ;
     RECT  56.256 38.243 57.24 46.117 ;
     RECT  59.1 44.627 59.412 46.117 ;
     RECT  64.5 44.437 64.92 46.117 ;
     RECT  61.68 45.731 62.232 46.211 ;
     RECT  7.8 46.115 9.048 46.259 ;
     RECT  31.968 45.253 32.412 46.259 ;
     RECT  53.7 44.389 54.792 46.307 ;
     RECT  13.2 45.445 14.712 46.309 ;
     RECT  2.4 43.955 2.712 46.357 ;
     RECT  3.936 46.021 5.88 46.357 ;
     RECT  34.8 45.155 37.812 46.499 ;
     RECT  18.288 46.069 19.416 46.501 ;
     RECT  42.144 45.829 43.212 46.547 ;
     RECT  18.288 46.501 19.992 46.597 ;
     RECT  12.672 46.309 14.712 46.643 ;
     RECT  24 44.003 24.312 46.645 ;
     RECT  48.048 45.731 48.612 46.691 ;
     RECT  45.6 43.811 46.056 46.741 ;
     RECT  7.8 46.259 8.52 46.787 ;
     RECT  10.272 46.115 10.812 46.837 ;
     RECT  29.4 45.731 30.072 46.837 ;
     RECT  21.072 45.923 22.344 46.883 ;
     RECT  13.2 46.643 14.712 46.885 ;
     RECT  15.9 46.019 16.212 46.885 ;
     RECT  49.968 46.645 49.992 46.933 ;
     RECT  51 42.227 51.312 46.933 ;
     RECT  58.752 46.117 59.412 46.933 ;
     RECT  61.68 46.211 62.112 46.933 ;
     RECT  49.968 46.933 51.312 46.979 ;
     RECT  42.9 46.547 43.212 46.981 ;
     RECT  55.872 46.117 57.24 47.027 ;
     RECT  10.272 46.837 11.352 47.075 ;
     RECT  34.8 46.499 35.208 47.075 ;
     RECT  53.7 46.307 54.552 47.075 ;
     RECT  29.28 46.837 30.072 47.125 ;
     RECT  18.192 46.597 19.992 47.171 ;
     RECT  2.4 46.357 5.88 47.221 ;
     RECT  39.312 45.011 40.512 47.269 ;
     RECT  64.5 46.117 64.968 47.315 ;
     RECT  67.2 45.635 67.512 47.317 ;
     RECT  58.464 46.933 59.412 47.365 ;
     RECT  56.256 47.027 57.24 47.411 ;
     RECT  10.272 47.075 10.812 47.555 ;
     RECT  58.464 47.365 59.88 47.605 ;
     RECT  13.2 46.885 16.212 47.747 ;
     RECT  34.8 47.075 35.112 47.749 ;
     RECT  0.288 47.125 0.312 47.795 ;
     RECT  7.8 46.787 8.376 47.845 ;
     RECT  13.2 47.747 13.608 47.845 ;
     RECT  48.3 46.691 48.612 47.845 ;
     RECT  2.4 47.221 6.264 47.939 ;
     RECT  26.7 46.117 27.384 47.987 ;
     RECT  48.3 47.845 48.744 47.987 ;
     RECT  4.032 47.939 6.264 48.085 ;
     RECT  7.8 47.845 8.568 48.085 ;
     RECT  28.464 47.125 30.072 48.227 ;
     RECT  56.4 47.411 57.24 48.227 ;
     RECT  18.192 47.171 19.416 48.229 ;
     RECT  66.576 47.317 67.512 48.229 ;
     RECT  33.888 47.749 35.112 48.373 ;
     RECT  61.008 46.933 62.112 48.373 ;
     RECT  4.032 48.085 8.568 48.419 ;
     RECT  58.464 47.605 60.024 48.421 ;
     RECT  61.008 48.373 62.616 48.421 ;
     RECT  64.5 47.315 64.812 48.421 ;
     RECT  69.552 46.115 70.212 48.421 ;
     RECT  18.192 48.229 20.328 48.515 ;
     RECT  56.4 48.227 56.808 48.659 ;
     RECT  18.6 48.515 20.328 48.661 ;
     RECT  21.3 46.883 22.344 48.661 ;
     RECT  45.264 46.741 46.056 48.757 ;
     RECT  12.384 47.845 13.608 48.805 ;
     RECT  66.432 48.229 67.512 48.853 ;
     RECT  10.368 47.555 10.812 48.901 ;
     RECT  45.264 48.757 46.392 48.901 ;
     RECT  52.368 47.125 52.392 48.901 ;
     RECT  53.7 47.075 54.012 48.901 ;
     RECT  12.384 48.805 13.656 48.947 ;
     RECT  45.264 48.901 46.776 48.947 ;
     RECT  14.688 47.747 14.712 48.949 ;
     RECT  52.368 48.901 54.012 48.949 ;
     RECT  13.056 48.947 13.656 48.995 ;
     RECT  69.552 48.421 70.824 48.997 ;
     RECT  10.32 48.901 10.812 49.043 ;
     RECT  52.368 48.949 54.36 49.043 ;
     RECT  13.2 48.995 13.656 49.091 ;
     RECT  58.464 48.421 62.616 49.091 ;
     RECT  45.6 48.947 46.776 49.139 ;
     RECT  24 46.645 25.224 49.141 ;
     RECT  24 49.141 25.656 49.187 ;
     RECT  58.704 49.091 62.616 49.235 ;
     RECT  14.688 48.949 14.808 49.477 ;
     RECT  15.9 47.747 16.212 49.477 ;
     RECT  68.592 48.997 70.824 49.477 ;
     RECT  13.2 49.091 13.608 49.523 ;
     RECT  42.9 46.981 43.32 49.523 ;
     RECT  68.592 49.477 70.872 49.523 ;
     RECT  4.128 48.419 8.568 49.525 ;
     RECT  36.576 46.499 37.812 49.525 ;
     RECT  39.312 47.269 41.352 49.525 ;
     RECT  28.464 48.227 29.712 49.667 ;
     RECT  33.888 48.373 35.448 49.667 ;
     RECT  53.7 49.043 54.36 49.667 ;
     RECT  3.936 49.525 8.568 49.763 ;
     RECT  36.576 49.525 41.352 49.765 ;
     RECT  42.9 49.523 43.212 49.765 ;
     RECT  24 49.187 24.408 49.907 ;
     RECT  68.592 49.523 68.616 50.003 ;
     RECT  2.4 47.939 2.712 50.005 ;
     RECT  3.936 49.763 8.376 50.005 ;
     RECT  28.512 49.667 29.712 50.005 ;
     RECT  18.6 48.661 22.344 50.053 ;
     RECT  58.8 49.235 62.616 50.101 ;
     RECT  14.688 49.477 16.212 50.147 ;
     RECT  58.8 50.101 63.288 50.147 ;
     RECT  50.16 46.979 51.312 50.195 ;
     RECT  10.368 49.043 10.812 50.293 ;
     RECT  69.9 49.523 70.872 50.293 ;
     RECT  58.8 50.147 62.232 50.387 ;
     RECT  64.5 48.421 64.92 50.581 ;
     RECT  66.096 48.853 67.512 50.581 ;
     RECT  36.576 49.765 43.212 50.771 ;
     RECT  69.9 50.293 71.112 50.819 ;
     RECT  51 50.195 51.312 50.821 ;
     RECT  52.368 49.043 52.392 50.821 ;
     RECT  51 50.821 52.392 50.867 ;
     RECT  2.4 50.005 8.376 50.963 ;
     RECT  58.8 50.387 62.112 50.965 ;
     RECT  9.936 50.293 11.064 51.059 ;
     RECT  48.3 47.987 48.612 51.109 ;
     RECT  58.608 50.965 62.112 51.253 ;
     RECT  42.768 50.771 43.212 51.347 ;
     RECT  53.7 49.667 54.312 51.347 ;
     RECT  42.9 51.347 43.212 51.349 ;
     RECT  53.7 51.347 54.012 51.349 ;
     RECT  33.888 49.667 35.112 51.395 ;
     RECT  15.9 50.147 16.212 51.445 ;
     RECT  26.7 47.987 27.012 51.637 ;
     RECT  28.512 50.005 30.648 51.637 ;
     RECT  10.272 51.059 11.064 51.685 ;
     RECT  34.8 51.395 35.112 51.733 ;
     RECT  15.9 51.445 17.064 51.779 ;
     RECT  13.2 49.523 13.512 51.829 ;
     RECT  63.264 50.147 63.288 51.829 ;
     RECT  64.5 50.581 67.512 51.829 ;
     RECT  18.24 50.053 22.344 51.923 ;
     RECT  25.536 49.187 25.656 51.923 ;
     RECT  10.272 51.685 11.16 51.925 ;
     RECT  48.3 51.109 48.744 52.019 ;
     RECT  24 49.907 24.312 52.021 ;
     RECT  56.4 48.659 56.712 52.021 ;
     RECT  58.128 51.253 62.112 52.165 ;
     RECT  63.264 51.829 67.512 52.165 ;
     RECT  58.128 52.165 67.512 52.309 ;
     RECT  42.9 51.349 43.32 52.355 ;
     RECT  69.9 50.819 70.872 52.405 ;
     RECT  53.136 51.349 54.012 52.499 ;
     RECT  56.4 52.021 56.808 52.549 ;
     RECT  36.576 50.771 41.352 52.595 ;
     RECT  26.7 51.637 30.648 52.643 ;
     RECT  10.272 51.925 11.352 52.693 ;
     RECT  10.272 52.693 11.448 52.739 ;
     RECT  10.368 52.739 11.448 52.741 ;
     RECT  10.368 52.741 11.544 52.787 ;
     RECT  25.536 51.923 25.56 52.787 ;
     RECT  58.128 52.309 67.608 52.787 ;
     RECT  18.24 51.923 18.912 52.979 ;
     RECT  61.8 52.787 67.608 52.979 ;
     RECT  19.968 51.923 22.344 52.981 ;
     RECT  24 52.021 24.504 52.981 ;
     RECT  15.9 51.779 16.212 53.029 ;
     RECT  29.4 52.643 30.648 53.075 ;
     RECT  55.728 52.549 56.808 53.075 ;
     RECT  58.128 52.787 60.456 53.075 ;
     RECT  69.792 52.405 70.872 53.075 ;
     RECT  69.9 53.075 70.872 53.123 ;
     RECT  66.72 52.979 67.608 53.171 ;
     RECT  45.6 49.139 46.056 53.221 ;
     RECT  19.968 52.981 24.504 53.413 ;
     RECT  55.728 53.075 56.712 53.555 ;
     RECT  51 50.867 52.152 53.557 ;
     RECT  61.8 52.979 65.256 53.603 ;
     RECT  63.168 53.603 65.256 53.699 ;
     RECT  45.6 53.221 46.728 53.795 ;
     RECT  26.7 52.643 27.912 53.797 ;
     RECT  44.448 53.797 44.472 53.939 ;
     RECT  13.2 51.829 13.608 54.037 ;
     RECT  14.688 50.147 14.808 54.037 ;
     RECT  13.2 54.037 14.808 54.085 ;
     RECT  15.9 53.029 17.16 54.085 ;
     RECT  36.576 52.595 41.304 54.085 ;
     RECT  42.9 52.355 43.212 54.085 ;
     RECT  63.168 53.699 63.336 54.179 ;
     RECT  26.592 53.797 27.912 54.371 ;
     RECT  36.576 54.085 43.212 54.371 ;
     RECT  2.4 50.963 8.112 54.565 ;
     RECT  63.312 54.179 63.336 54.611 ;
     RECT  29.4 53.075 30.6 54.613 ;
     RECT  61.8 53.603 62.112 54.613 ;
     RECT  13.104 54.085 14.808 54.707 ;
     RECT  69.9 53.123 70.824 54.707 ;
     RECT  19.968 53.413 25.08 54.851 ;
     RECT  26.592 54.371 27.012 54.851 ;
     RECT  36.576 54.371 41.304 55.139 ;
     RECT  15.792 54.085 17.16 55.283 ;
     RECT  2.4 54.565 8.232 55.285 ;
     RECT  66.816 53.171 67.608 55.331 ;
     RECT  50.496 53.557 52.152 55.427 ;
     RECT  69.9 54.707 70.728 55.429 ;
     RECT  58.608 53.075 60.456 55.523 ;
     RECT  53.7 52.499 54.012 55.525 ;
     RECT  60.432 55.523 60.456 55.525 ;
     RECT  61.584 54.613 62.112 55.525 ;
     RECT  15.792 55.283 16.344 55.715 ;
     RECT  34.8 51.733 35.208 55.717 ;
     RECT  24 54.851 25.08 55.763 ;
     RECT  45.6 53.795 45.912 55.813 ;
     RECT  2.4 55.285 8.568 55.907 ;
     RECT  55.824 53.555 56.712 55.907 ;
     RECT  18.48 52.979 18.912 56.005 ;
     RECT  60.432 55.525 62.112 56.291 ;
     RECT  69.6 55.429 70.728 56.291 ;
     RECT  7.2 55.907 8.568 56.339 ;
     RECT  15.9 55.715 16.344 56.389 ;
     RECT  18.192 56.005 18.912 56.389 ;
     RECT  24 55.763 24.312 56.389 ;
     RECT  26.7 54.851 27.012 56.389 ;
     RECT  60.768 56.291 62.112 56.389 ;
     RECT  19.968 54.851 22.344 56.483 ;
     RECT  28.464 54.613 30.6 56.483 ;
     RECT  33.6 55.429 33.624 56.483 ;
     RECT  10.5 52.787 11.544 56.485 ;
     RECT  2.4 55.907 6.216 56.531 ;
     RECT  42.768 54.371 43.212 56.531 ;
     RECT  45.168 55.813 45.912 56.531 ;
     RECT  51 55.427 52.152 56.629 ;
     RECT  53.7 55.525 54.744 56.629 ;
     RECT  21.072 56.483 22.344 56.675 ;
     RECT  34.8 55.717 35.256 56.771 ;
     RECT  51 56.629 54.744 56.819 ;
     RECT  13.104 54.707 14.664 56.821 ;
     RECT  29.28 56.483 30.6 56.867 ;
     RECT  3.936 56.531 6.216 56.965 ;
     RECT  7.2 56.339 8.112 56.965 ;
     RECT  10.368 56.485 11.544 56.965 ;
     RECT  26.7 56.389 27.48 57.013 ;
     RECT  19.968 56.483 20.04 57.059 ;
     RECT  39.312 55.139 41.304 57.059 ;
     RECT  21.3 56.675 22.344 57.061 ;
     RECT  23.424 56.389 24.312 57.061 ;
     RECT  17.856 56.389 18.912 57.107 ;
     RECT  10.368 56.965 11.64 57.109 ;
     RECT  18.192 57.107 18.912 57.203 ;
     RECT  64.5 53.699 65.256 57.205 ;
     RECT  52.992 56.819 54.744 57.299 ;
     RECT  32.1 46.259 32.412 57.301 ;
     RECT  9.12 57.157 9.144 57.347 ;
     RECT  52.992 57.299 54.012 57.347 ;
     RECT  10.272 57.109 11.64 57.445 ;
     RECT  51 56.819 51.312 57.445 ;
     RECT  3.936 56.965 8.112 57.493 ;
     RECT  42.9 56.531 43.212 57.493 ;
     RECT  13.008 56.821 14.664 57.541 ;
     RECT  48.3 52.019 48.612 57.541 ;
     RECT  50.352 57.445 51.312 57.541 ;
     RECT  15.9 56.389 16.392 57.635 ;
     RECT  21.3 57.061 24.312 57.685 ;
     RECT  64.368 57.205 65.256 57.827 ;
     RECT  3.888 57.493 8.112 57.875 ;
     RECT  12.768 57.541 14.664 57.875 ;
     RECT  25.728 57.013 27.48 57.877 ;
     RECT  34.8 56.771 35.208 57.877 ;
     RECT  21.168 57.685 24.312 57.923 ;
     RECT  58.608 55.523 59.412 57.973 ;
     RECT  60.768 56.389 62.376 57.973 ;
     RECT  42.768 57.493 43.212 58.019 ;
     RECT  18.6 57.203 18.912 58.069 ;
     RECT  19.968 57.059 19.992 58.069 ;
     RECT  66.816 55.331 67.512 58.069 ;
     RECT  18.6 58.069 19.992 58.115 ;
     RECT  2.4 56.531 2.712 58.117 ;
     RECT  3.888 57.875 6.504 58.117 ;
     RECT  45.6 56.531 45.912 58.117 ;
     RECT  56.4 55.907 56.712 58.117 ;
     RECT  25.728 57.877 27.528 58.163 ;
     RECT  64.5 57.827 65.256 58.211 ;
     RECT  29.4 56.867 29.832 58.403 ;
     RECT  53.7 57.347 54.012 58.453 ;
     RECT  58.608 57.973 62.376 58.595 ;
     RECT  60.768 58.595 62.376 58.643 ;
     RECT  7.8 57.875 8.112 58.645 ;
     RECT  9.696 57.445 11.64 58.645 ;
     RECT  15.9 57.635 16.344 58.645 ;
     RECT  31.824 57.301 32.412 58.645 ;
     RECT  33.456 56.821 33.48 58.645 ;
     RECT  23.424 57.923 24.312 58.691 ;
     RECT  53.7 58.453 54.12 58.693 ;
     RECT  18.6 58.115 19.128 58.741 ;
     RECT  36.576 55.139 37.812 58.741 ;
     RECT  53.7 58.693 54.744 58.883 ;
     RECT  63.504 58.645 63.528 58.885 ;
     RECT  23.904 58.691 24.312 59.077 ;
     RECT  44.688 58.117 45.912 59.123 ;
     RECT  42.9 58.019 43.212 59.173 ;
     RECT  26.7 58.163 27.528 59.221 ;
     RECT  31.824 58.645 33.48 59.221 ;
     RECT  45.6 59.123 45.912 59.221 ;
     RECT  7.8 58.645 11.64 59.267 ;
     RECT  18.24 58.741 19.128 59.267 ;
     RECT  36.48 58.741 37.812 59.269 ;
     RECT  56.4 58.117 56.808 59.269 ;
     RECT  58.608 58.595 59.412 59.315 ;
     RECT  14.592 57.875 14.664 59.411 ;
     RECT  34.8 57.877 35.352 59.459 ;
     RECT  23.904 59.077 24.552 59.507 ;
     RECT  66.336 58.069 67.512 59.749 ;
     RECT  63.456 58.885 63.528 59.795 ;
     RECT  60.768 58.643 62.112 59.797 ;
     RECT  15.9 58.645 16.536 59.891 ;
     RECT  36.48 59.269 38.184 59.891 ;
     RECT  48.3 57.541 51.312 59.891 ;
     RECT  45.6 59.221 46.824 59.939 ;
     RECT  21.168 57.923 22.344 59.987 ;
     RECT  9.696 59.267 11.64 60.035 ;
     RECT  26.7 59.221 27.72 60.035 ;
     RECT  48.3 59.891 49.56 60.035 ;
     RECT  42.768 59.173 43.212 60.037 ;
     RECT  48.3 60.035 49.128 60.037 ;
     RECT  10.272 60.035 11.64 60.131 ;
     RECT  48.144 60.037 49.128 60.179 ;
     RECT  18.6 59.267 19.128 60.421 ;
     RECT  2.4 58.117 6.504 60.467 ;
     RECT  64.5 58.211 64.92 60.565 ;
     RECT  24 59.507 24.552 60.805 ;
     RECT  69.9 56.291 70.728 60.805 ;
     RECT  36.576 59.891 38.184 60.851 ;
     RECT  55.872 59.269 56.808 60.949 ;
     RECT  55.872 60.949 57.48 61.043 ;
     RECT  3.936 60.467 6.504 61.091 ;
     RECT  47.184 60.757 47.208 61.091 ;
     RECT  31.344 59.221 33.48 61.139 ;
     RECT  42.624 60.037 43.212 61.139 ;
     RECT  23.856 60.805 24.552 61.237 ;
     RECT  45.6 59.939 46.2 61.237 ;
     RECT  39.312 57.059 40.512 61.333 ;
     RECT  66.336 59.749 67.8 61.379 ;
     RECT  18 60.421 19.128 61.381 ;
     RECT  4.272 61.091 6.504 61.429 ;
     RECT  7.8 59.267 8.112 61.429 ;
     RECT  36.576 60.851 37.812 61.429 ;
     RECT  29.4 58.403 29.712 61.525 ;
     RECT  45.12 61.237 46.2 61.525 ;
     RECT  23.808 61.237 24.552 61.619 ;
     RECT  56.4 61.043 57.48 61.619 ;
     RECT  18 61.381 19.176 61.669 ;
     RECT  20.304 60.853 20.328 61.669 ;
     RECT  12.768 57.875 13.608 61.859 ;
     RECT  18 61.669 20.328 61.859 ;
     RECT  36.24 61.429 37.812 61.861 ;
     RECT  34.8 59.459 35.208 61.909 ;
     RECT  36.24 61.861 38.088 61.909 ;
     RECT  14.64 59.411 14.664 61.957 ;
     RECT  59.1 59.315 59.412 61.957 ;
     RECT  15.9 59.891 16.344 62.003 ;
     RECT  12.912 61.859 13.608 62.005 ;
     RECT  12.912 62.005 13.656 62.053 ;
     RECT  14.64 61.957 14.856 62.053 ;
     RECT  21.3 59.987 22.344 62.053 ;
     RECT  18 61.859 19.848 62.147 ;
     RECT  60.384 59.797 62.112 62.195 ;
     RECT  66.336 61.379 67.512 62.293 ;
     RECT  23.808 61.619 24.504 62.339 ;
     RECT  31.92 61.139 33.48 62.339 ;
     RECT  45.024 61.525 46.2 62.389 ;
     RECT  23.856 62.339 24.504 62.435 ;
     RECT  42.9 61.139 43.212 62.437 ;
     RECT  39.312 61.333 41.064 62.533 ;
     RECT  48.3 60.179 49.128 62.533 ;
     RECT  56.4 61.619 56.808 62.629 ;
     RECT  4.272 61.429 8.112 62.677 ;
     RECT  24 62.435 24.504 62.677 ;
     RECT  45.024 62.389 46.44 62.677 ;
     RECT  18 62.147 19.176 62.723 ;
     RECT  64.5 60.565 64.968 62.771 ;
     RECT  45.024 62.677 46.776 62.819 ;
     RECT  48.192 62.533 49.128 62.821 ;
     RECT  24 62.677 24.936 62.965 ;
     RECT  9.264 62.005 9.288 63.011 ;
     RECT  34.8 61.909 38.088 63.011 ;
     RECT  12.912 62.053 14.856 63.205 ;
     RECT  15.9 62.003 16.212 63.205 ;
     RECT  21.3 62.053 22.728 63.253 ;
     RECT  10.368 60.131 11.64 63.299 ;
     RECT  30.768 62.773 30.792 63.299 ;
     RECT  58.656 61.957 59.412 63.299 ;
     RECT  29.184 61.525 29.712 63.301 ;
     RECT  29.184 63.301 30.312 63.347 ;
     RECT  21.3 63.253 22.872 63.349 ;
     RECT  3.84 62.677 8.112 63.395 ;
     RECT  10.5 63.299 11.64 63.397 ;
     RECT  34.8 63.011 36.456 63.491 ;
     RECT  60.768 62.195 62.112 63.493 ;
     RECT  63.456 59.795 63.48 63.493 ;
     RECT  37.5 63.011 38.088 63.539 ;
     RECT  10.5 63.397 11.736 63.637 ;
     RECT  12.912 63.205 16.344 63.637 ;
     RECT  56.4 62.629 56.856 63.685 ;
     RECT  2.4 60.467 2.712 63.781 ;
     RECT  3.84 63.395 6.504 63.781 ;
     RECT  24 62.965 25.464 63.781 ;
     RECT  45.024 62.819 46.44 63.781 ;
     RECT  47.904 62.821 49.128 63.781 ;
     RECT  56.4 63.685 57.48 63.781 ;
     RECT  64.5 62.771 64.92 63.781 ;
     RECT  66.096 62.293 67.512 63.781 ;
     RECT  60.432 63.493 63.48 63.827 ;
     RECT  60.432 63.827 62.712 63.923 ;
     RECT  7.68 63.395 8.112 64.357 ;
     RECT  9.12 63.109 9.144 64.357 ;
     RECT  18 62.723 19.128 64.357 ;
     RECT  29.4 63.347 30.312 64.357 ;
     RECT  64.5 63.781 67.512 64.357 ;
     RECT  10.5 63.637 16.344 64.451 ;
     RECT  24 63.781 25.512 64.499 ;
     RECT  36.432 63.491 36.456 64.499 ;
     RECT  64.5 64.357 67.608 64.499 ;
     RECT  7.68 64.357 9.144 64.547 ;
     RECT  31.92 62.339 32.412 64.691 ;
     RECT  10.5 64.451 14.856 64.741 ;
     RECT  45.024 63.781 49.128 64.931 ;
     RECT  33.456 62.339 33.48 64.979 ;
     RECT  66.096 64.499 67.608 64.981 ;
     RECT  10.272 64.741 14.856 65.075 ;
     RECT  56.4 63.781 57.624 65.125 ;
     RECT  15.9 64.451 16.344 65.171 ;
     RECT  45.6 64.931 49.128 65.219 ;
     RECT  18 64.357 19.416 65.221 ;
     RECT  37.5 63.539 37.812 65.317 ;
     RECT  32.1 64.691 32.412 65.413 ;
     RECT  42.768 62.437 43.212 65.509 ;
     RECT  12.528 65.075 13.608 65.555 ;
     RECT  28.896 64.357 30.888 65.555 ;
     RECT  32.1 65.413 32.52 65.555 ;
     RECT  66.096 64.981 68.184 65.555 ;
     RECT  2.4 63.781 6.504 65.651 ;
     RECT  4.368 65.651 6.504 65.653 ;
     RECT  7.68 64.547 8.232 65.653 ;
     RECT  69.9 60.805 71.16 65.699 ;
     RECT  17.712 65.221 19.416 65.701 ;
     RECT  17.664 65.701 19.416 65.795 ;
     RECT  51 59.891 51.312 66.037 ;
     RECT  66.096 65.555 67.512 66.037 ;
     RECT  17.664 65.795 19.32 66.085 ;
     RECT  21.3 63.349 22.968 66.085 ;
     RECT  56.016 65.125 57.624 66.085 ;
     RECT  59.1 63.299 59.412 66.085 ;
     RECT  17.616 66.085 19.32 66.179 ;
     RECT  20.592 66.085 22.968 66.181 ;
     RECT  24 64.499 24.936 66.181 ;
     RECT  45.6 65.219 48.744 66.181 ;
     RECT  2.4 65.651 3.288 66.227 ;
     RECT  45.504 66.181 48.744 66.227 ;
     RECT  51 66.037 51.432 66.227 ;
     RECT  39.312 62.533 41.352 66.275 ;
     RECT  14.832 65.075 14.856 66.277 ;
     RECT  15.9 65.171 16.212 66.277 ;
     RECT  56.016 66.085 59.412 66.421 ;
     RECT  20.592 66.181 24.936 66.611 ;
     RECT  36.432 65.509 36.456 66.611 ;
     RECT  37.5 65.317 37.944 66.755 ;
     RECT  40.08 66.275 41.352 66.755 ;
     RECT  45.504 66.227 48.612 66.755 ;
     RECT  28.896 65.555 30.792 66.803 ;
     RECT  14.832 66.277 16.212 66.901 ;
     RECT  29.4 66.803 30.792 66.947 ;
     RECT  21.3 66.611 24.936 66.997 ;
     RECT  13.056 65.555 13.608 67.045 ;
     RECT  40.08 66.755 41.064 67.091 ;
     RECT  45.504 66.755 46.104 67.091 ;
     RECT  66.048 66.037 67.512 67.091 ;
     RECT  17.616 66.179 18.912 67.139 ;
     RECT  60.432 63.923 62.112 67.139 ;
     RECT  4.368 65.653 8.232 67.141 ;
     RECT  32.1 65.555 32.412 67.141 ;
     RECT  64.5 64.499 65.016 67.141 ;
     RECT  66.048 67.091 66.072 67.141 ;
     RECT  10.272 65.075 11.304 67.237 ;
     RECT  55.92 66.421 59.412 67.237 ;
     RECT  61.584 67.139 62.112 67.237 ;
     RECT  40.08 67.091 40.92 67.283 ;
     RECT  55.296 67.237 59.412 67.283 ;
     RECT  60.432 67.139 60.456 67.283 ;
     RECT  17.664 67.139 18.912 67.331 ;
     RECT  36.192 66.613 36.216 67.331 ;
     RECT  10.224 67.237 11.304 67.333 ;
     RECT  17.712 67.331 18.912 67.475 ;
     RECT  42.768 65.509 44.136 67.571 ;
     RECT  4.272 67.141 8.232 67.573 ;
     RECT  69.9 65.699 70.212 67.573 ;
     RECT  10.224 67.333 11.496 67.619 ;
     RECT  18 67.475 18.912 67.621 ;
     RECT  67.2 67.091 67.512 67.621 ;
     RECT  21.3 66.997 25.272 67.669 ;
     RECT  4.272 67.573 8.904 67.715 ;
     RECT  2.4 66.227 2.712 67.717 ;
     RECT  4.272 67.715 8.112 67.717 ;
     RECT  30.768 66.947 30.792 67.763 ;
     RECT  67.2 67.621 67.608 67.763 ;
     RECT  40.08 67.283 40.512 67.765 ;
     RECT  12.528 67.045 13.608 67.859 ;
     RECT  64.5 67.141 66.072 67.859 ;
     RECT  69.9 67.573 70.68 67.859 ;
     RECT  10.224 67.619 11.4 67.861 ;
     RECT  2.4 67.717 8.112 67.907 ;
     RECT  14.784 66.901 16.212 67.907 ;
     RECT  34.8 63.491 35.208 68.147 ;
     RECT  26.7 60.035 27.528 68.149 ;
     RECT  32.1 67.141 32.808 68.195 ;
     RECT  7.2 67.907 8.112 68.243 ;
     RECT  56.4 67.283 59.412 68.291 ;
     RECT  42.768 67.571 43.896 68.339 ;
     RECT  13.056 67.859 13.608 68.341 ;
     RECT  61.584 67.237 62.232 68.387 ;
     RECT  18 67.621 19.416 68.435 ;
     RECT  55.296 67.283 55.32 68.435 ;
     RECT  13.056 68.341 13.656 68.483 ;
     RECT  31.056 67.813 31.08 68.629 ;
     RECT  32.1 68.195 32.412 68.629 ;
     RECT  37.5 66.755 37.812 68.629 ;
     RECT  36.528 68.629 37.812 68.725 ;
     RECT  31.056 68.629 32.412 68.771 ;
     RECT  36.432 68.725 37.812 68.771 ;
     RECT  53.7 58.883 54.12 68.917 ;
     RECT  56.4 68.291 57.336 68.917 ;
     RECT  55.728 68.917 57.336 68.963 ;
     RECT  39.312 67.765 40.512 68.965 ;
     RECT  9.984 67.861 11.4 69.011 ;
     RECT  39.312 68.965 40.776 69.011 ;
     RECT  15.456 67.907 16.212 69.059 ;
     RECT  61.584 68.387 62.112 69.061 ;
     RECT  2.4 67.907 5.688 69.107 ;
     RECT  40.08 69.011 40.776 69.107 ;
     RECT  60.96 69.061 62.112 69.203 ;
     RECT  2.4 69.107 5.592 69.299 ;
     RECT  42.768 68.339 43.212 69.301 ;
     RECT  45.6 67.091 45.912 69.301 ;
     RECT  47.424 66.755 48.612 69.301 ;
     RECT  13.056 68.483 13.608 69.349 ;
     RECT  42.672 69.301 43.212 69.443 ;
     RECT  45.6 69.301 48.612 69.443 ;
     RECT  18 68.435 18.912 69.493 ;
     RECT  20.736 67.669 25.272 69.493 ;
     RECT  51 66.227 51.312 69.493 ;
     RECT  67.2 67.763 67.512 69.493 ;
     RECT  26.352 68.149 27.528 69.541 ;
     RECT  17.424 69.493 18.912 69.683 ;
     RECT  64.5 67.859 64.968 69.683 ;
     RECT  47.472 69.443 48.612 69.731 ;
     RECT  66.048 67.859 66.072 69.781 ;
     RECT  67.104 69.493 67.512 69.781 ;
     RECT  66.048 69.781 67.512 69.827 ;
     RECT  7.392 68.243 8.112 69.829 ;
     RECT  12.432 69.349 13.608 69.829 ;
     RECT  31.872 68.771 32.412 69.829 ;
     RECT  40.2 69.107 40.776 69.829 ;
     RECT  26.352 69.541 28.008 69.971 ;
     RECT  9.984 69.011 10.812 70.069 ;
     RECT  34.8 68.147 35.112 70.069 ;
     RECT  2.4 69.299 5.544 70.163 ;
     RECT  9.936 70.069 10.812 70.357 ;
     RECT  6.672 69.829 8.112 70.501 ;
     RECT  2.4 70.163 5.412 70.547 ;
     RECT  9.12 70.357 10.812 70.547 ;
     RECT  6.384 70.501 8.112 70.645 ;
     RECT  12.192 69.829 14.232 70.645 ;
     RECT  30.816 69.349 30.84 70.645 ;
     RECT  31.872 69.829 33.096 70.645 ;
     RECT  30.816 70.645 33.096 70.691 ;
     RECT  20.496 69.493 25.272 70.739 ;
     RECT  44.544 70.069 44.568 70.739 ;
     RECT  64.5 69.683 64.92 70.789 ;
     RECT  66.144 69.827 67.512 70.789 ;
     RECT  12.192 70.645 14.568 70.835 ;
     RECT  36.432 68.771 36.456 70.835 ;
     RECT  26.7 69.971 28.008 70.931 ;
     RECT  58.944 68.291 59.412 70.931 ;
     RECT  18.6 69.683 18.912 70.981 ;
     RECT  15.696 69.059 16.212 71.075 ;
     RECT  20.496 70.739 24.312 71.075 ;
     RECT  26.7 70.931 27.528 71.077 ;
     RECT  13.056 70.835 14.568 71.123 ;
     RECT  49.584 68.917 49.608 71.123 ;
     RECT  34.416 70.069 35.112 71.173 ;
     RECT  40.2 69.829 41.592 71.221 ;
     RECT  4.224 70.547 5.412 71.315 ;
     RECT  47.616 69.731 48.612 71.315 ;
     RECT  63.408 68.341 63.432 71.365 ;
     RECT  4.272 71.315 5.412 71.411 ;
     RECT  20.736 71.075 24.312 71.411 ;
     RECT  63.312 71.365 63.432 71.411 ;
     RECT  64.5 70.789 67.512 71.411 ;
     RECT  29.4 66.947 29.712 71.461 ;
     RECT  30.816 70.691 32.412 71.461 ;
     RECT  18.6 70.981 19.032 71.507 ;
     RECT  6.384 70.645 8.616 71.605 ;
     RECT  9.936 70.547 10.812 71.605 ;
     RECT  15.744 71.075 16.212 71.605 ;
     RECT  17.424 69.683 17.448 71.605 ;
     RECT  45.6 69.443 46.2 71.605 ;
     RECT  40.2 71.221 41.64 71.797 ;
     RECT  42.768 69.443 43.212 71.797 ;
     RECT  48.3 71.315 48.612 71.797 ;
     RECT  23.28 71.411 24.312 71.843 ;
     RECT  45.36 71.605 46.2 71.843 ;
     RECT  51 69.493 52.152 71.843 ;
     RECT  6.384 71.605 10.812 71.891 ;
     RECT  63.312 71.411 63.336 71.987 ;
     RECT  40.2 71.797 43.212 72.037 ;
     RECT  69.9 67.859 70.212 72.085 ;
     RECT  15.744 71.605 17.448 72.229 ;
     RECT  6.384 71.891 8.28 72.275 ;
     RECT  20.736 71.411 21.864 72.419 ;
     RECT  34.416 71.173 35.352 72.419 ;
     RECT  55.728 68.963 57.192 72.419 ;
     RECT  13.056 71.123 13.608 72.467 ;
     RECT  15.408 72.229 17.448 72.467 ;
     RECT  13.056 72.467 13.512 72.565 ;
     RECT  39.936 72.037 43.212 72.659 ;
     RECT  60.384 71.317 60.408 72.707 ;
     RECT  29.4 71.461 32.412 72.757 ;
     RECT  26.208 71.077 27.528 72.803 ;
     RECT  4.992 71.411 5.412 72.805 ;
     RECT  4.992 72.805 5.544 72.851 ;
     RECT  18.6 71.507 18.912 72.901 ;
     RECT  37.5 68.771 37.812 72.901 ;
     RECT  55.728 72.419 56.712 72.901 ;
     RECT  41.616 72.659 43.212 72.947 ;
     RECT  53.568 68.917 54.12 72.949 ;
     RECT  12.144 72.565 13.512 72.995 ;
     RECT  42.144 72.947 43.212 73.045 ;
     RECT  18.6 72.901 19.752 73.235 ;
     RECT  69.9 72.085 70.968 73.283 ;
     RECT  13.056 72.995 13.512 73.331 ;
     RECT  42.144 73.045 43.608 73.331 ;
     RECT  9.312 71.891 10.812 73.379 ;
     RECT  39.936 72.659 40.632 73.381 ;
     RECT  52.752 72.949 54.12 73.381 ;
     RECT  5.1 72.851 5.544 73.477 ;
     RECT  6.624 72.275 8.28 73.477 ;
     RECT  48.3 71.797 49.176 73.477 ;
     RECT  52.752 73.381 54.168 73.523 ;
     RECT  29.4 72.757 33.048 73.571 ;
     RECT  17.424 72.467 17.448 73.811 ;
     RECT  5.1 73.477 8.28 73.907 ;
     RECT  55.44 72.901 56.712 73.957 ;
     RECT  57.696 72.901 57.72 73.957 ;
     RECT  61.584 69.203 62.112 73.957 ;
     RECT  20.784 72.419 21.864 74.005 ;
     RECT  67.2 71.411 67.512 74.005 ;
     RECT  18.6 73.235 19.656 74.053 ;
     RECT  61.248 73.957 62.112 74.099 ;
     RECT  15.408 72.467 16.212 74.197 ;
     RECT  24 71.843 24.312 74.197 ;
     RECT  42.144 73.331 43.212 74.293 ;
     RECT  51 71.843 51.312 74.293 ;
     RECT  69.9 73.283 70.212 74.293 ;
     RECT  42.144 74.293 43.32 74.339 ;
     RECT  48.192 73.477 49.176 74.339 ;
     RECT  6.816 73.907 8.28 74.389 ;
     RECT  9.312 73.379 9.336 74.389 ;
     RECT  51 74.293 51.912 74.389 ;
     RECT  20.784 74.005 22.104 74.435 ;
     RECT  64.5 71.411 66.168 74.581 ;
     RECT  67.2 74.005 67.752 74.581 ;
     RECT  15.408 74.197 16.344 74.627 ;
     RECT  45.36 71.843 45.912 74.627 ;
     RECT  13.2 73.331 13.512 74.677 ;
     RECT  39.888 73.381 40.632 74.677 ;
     RECT  53.7 73.523 54.168 74.723 ;
     RECT  42.768 74.339 43.32 74.773 ;
     RECT  68.928 74.293 70.212 74.819 ;
     RECT  29.4 73.571 32.412 74.867 ;
     RECT  48.192 74.339 48.612 74.869 ;
     RECT  13.104 74.677 13.512 74.917 ;
     RECT  26.7 72.803 27.528 74.917 ;
     RECT  29.4 74.867 30.84 74.917 ;
     RECT  6.816 74.389 9.336 74.965 ;
     RECT  10.5 73.379 10.812 74.965 ;
     RECT  34.416 72.419 35.112 74.965 ;
     RECT  6.816 74.965 10.812 75.013 ;
     RECT  12.288 74.917 13.752 75.013 ;
     RECT  61.584 74.099 62.112 75.109 ;
     RECT  34.416 74.965 35.208 75.155 ;
     RECT  5.1 73.907 5.688 75.157 ;
     RECT  6.816 75.013 13.752 75.157 ;
     RECT  4.56 75.157 13.752 75.203 ;
     RECT  26.7 74.917 30.84 75.203 ;
     RECT  17.616 74.053 19.656 75.205 ;
     RECT  37.056 72.901 37.812 75.205 ;
     RECT  55.44 73.957 57.72 75.251 ;
     RECT  55.44 75.251 57.048 75.395 ;
     RECT  4.56 75.203 13.656 75.443 ;
     RECT  4.56 75.443 5.64 75.491 ;
     RECT  23.424 74.197 24.312 75.541 ;
     RECT  6.816 75.443 13.656 75.587 ;
     RECT  42.768 74.773 43.992 75.683 ;
     RECT  64.5 74.581 67.752 75.683 ;
     RECT  50.736 74.389 51.912 75.685 ;
     RECT  25.632 74.053 25.656 75.781 ;
     RECT  26.7 75.203 27.528 75.781 ;
     RECT  50.736 75.685 52.248 75.827 ;
     RECT  10.5 75.587 13.656 75.971 ;
     RECT  15.504 74.627 16.344 75.971 ;
     RECT  15.504 75.971 16.212 75.973 ;
     RECT  36.912 75.205 37.812 76.019 ;
     RECT  50.736 75.827 51.912 76.019 ;
     RECT  47.808 74.869 48.612 76.021 ;
     RECT  10.5 75.971 13.512 76.259 ;
     RECT  17.424 75.205 19.656 76.259 ;
     RECT  61.536 75.109 62.112 76.261 ;
     RECT  17.52 76.259 19.656 76.307 ;
     RECT  25.584 75.781 27.528 76.307 ;
     RECT  39.888 74.677 41.016 76.307 ;
     RECT  21.3 74.435 22.104 76.309 ;
     RECT  23.328 75.541 24.312 76.309 ;
     RECT  29.4 75.203 30.84 76.357 ;
     RECT  34.8 75.155 35.208 76.357 ;
     RECT  37.5 76.019 37.812 76.357 ;
     RECT  59.1 70.931 59.412 76.357 ;
     RECT  64.5 75.683 67.512 76.499 ;
     RECT  29.4 76.357 31.128 76.501 ;
     RECT  29.088 76.501 31.128 76.691 ;
     RECT  21.3 76.309 24.312 76.741 ;
     RECT  29.4 76.691 31.128 76.741 ;
     RECT  32.1 74.867 32.412 76.741 ;
     RECT  4.56 75.491 5.544 76.837 ;
     RECT  69.9 74.819 70.212 76.837 ;
     RECT  53.7 74.723 54.12 76.885 ;
     RECT  37.5 76.357 38.136 76.979 ;
     RECT  58.704 76.357 59.412 77.077 ;
     RECT  34.8 76.357 35.736 77.171 ;
     RECT  55.728 75.395 57.048 77.269 ;
     RECT  58.032 77.077 59.412 77.269 ;
     RECT  34.8 77.171 35.208 77.315 ;
     RECT  55.728 77.269 59.412 77.315 ;
     RECT  40.2 76.307 41.016 77.411 ;
     RECT  25.584 76.307 25.608 77.413 ;
     RECT  50.88 76.019 51.912 77.461 ;
     RECT  25.584 77.413 25.656 77.555 ;
     RECT  55.824 77.315 59.412 77.555 ;
     RECT  61.008 76.261 62.112 77.555 ;
     RECT  4.416 76.837 5.544 77.653 ;
     RECT  6.816 75.587 9.192 77.653 ;
     RECT  64.5 76.499 65.736 77.653 ;
     RECT  4.416 77.653 9.192 77.701 ;
     RECT  10.5 76.259 10.812 77.701 ;
     RECT  18.6 76.307 19.656 77.701 ;
     RECT  40.2 77.411 40.92 77.701 ;
     RECT  4.416 77.701 10.812 77.749 ;
     RECT  12.048 76.259 13.512 77.749 ;
     RECT  29.4 76.741 32.412 77.795 ;
     RECT  33.456 76.453 33.48 77.795 ;
     RECT  14.832 75.973 16.212 77.845 ;
     RECT  17.52 76.307 17.544 77.845 ;
     RECT  4.416 77.749 13.512 77.891 ;
     RECT  14.832 77.845 17.544 77.891 ;
     RECT  12 77.891 13.512 77.939 ;
     RECT  25.632 77.555 25.656 77.939 ;
     RECT  64.32 77.653 65.736 77.939 ;
     RECT  64.32 77.939 65.112 77.941 ;
     RECT  69.408 76.837 70.212 77.941 ;
     RECT  45.6 74.627 45.912 77.989 ;
     RECT  47.28 76.021 48.612 77.989 ;
     RECT  21.072 76.741 24.312 78.037 ;
     RECT  42.768 75.683 43.32 78.037 ;
     RECT  67.104 76.499 67.512 78.037 ;
     RECT  69.408 77.941 71.016 78.037 ;
     RECT  4.416 77.891 8.112 78.083 ;
     RECT  18.6 77.701 19.992 78.323 ;
     RECT  4.464 78.083 8.112 78.419 ;
     RECT  26.7 76.307 27.528 78.467 ;
     RECT  53.7 76.885 54.6 78.467 ;
     RECT  12 77.939 12.072 78.611 ;
     RECT  2.4 70.547 2.712 78.613 ;
     RECT  56.4 77.555 59.412 78.659 ;
     RECT  69.12 78.037 71.016 78.659 ;
     RECT  69.408 78.659 71.016 78.707 ;
     RECT  9.168 77.891 10.812 78.755 ;
     RECT  19.968 78.323 19.992 78.755 ;
     RECT  39.264 77.701 40.92 78.755 ;
     RECT  13.056 77.939 13.512 78.853 ;
     RECT  14.832 77.891 17.496 78.853 ;
     RECT  13.056 78.853 17.496 78.899 ;
     RECT  64.176 77.941 65.112 78.899 ;
     RECT  66.672 78.037 67.512 78.997 ;
     RECT  42.288 78.037 43.32 79.043 ;
     RECT  37.5 76.979 37.812 79.045 ;
     RECT  45.6 77.989 48.612 79.189 ;
     RECT  50.208 77.461 51.912 79.189 ;
     RECT  61.68 77.555 62.112 79.189 ;
     RECT  15.504 78.899 17.496 79.235 ;
     RECT  61.68 79.189 63.096 79.235 ;
     RECT  39.264 78.755 40.632 79.283 ;
     RECT  45.6 79.189 48.744 79.283 ;
     RECT  42.72 79.043 43.32 79.331 ;
     RECT  13.056 78.899 13.944 79.427 ;
     RECT  2.4 78.613 3.288 79.475 ;
     RECT  50.208 79.189 52.248 79.475 ;
     RECT  53.7 78.467 54.36 79.475 ;
     RECT  12 78.611 12.024 79.717 ;
     RECT  13.056 79.427 13.512 79.717 ;
     RECT  18.6 78.323 18.912 79.813 ;
     RECT  18.6 79.813 19.608 80.005 ;
     RECT  69.408 78.707 70.212 80.149 ;
     RECT  15.9 79.235 17.496 80.291 ;
     RECT  21.024 78.037 24.312 80.291 ;
     RECT  44.448 78.517 44.472 80.291 ;
     RECT  4.704 78.419 8.112 80.293 ;
     RECT  9.552 78.755 10.812 80.293 ;
     RECT  26.7 78.467 27.24 80.293 ;
     RECT  61.8 79.235 63.096 80.293 ;
     RECT  18.48 80.005 19.608 80.341 ;
     RECT  51 79.475 52.248 80.341 ;
     RECT  66.672 78.997 67.608 80.341 ;
     RECT  47.568 79.283 48.744 80.435 ;
     RECT  66.624 80.341 67.608 80.435 ;
     RECT  56.4 78.659 58.056 80.579 ;
     RECT  29.4 77.795 31.128 80.677 ;
     RECT  32.1 77.795 32.412 80.677 ;
     RECT  37.5 79.045 38.28 80.677 ;
     RECT  26.7 80.293 27.816 80.773 ;
     RECT  47.568 80.435 48.612 80.819 ;
     RECT  56.4 80.579 57.864 80.821 ;
     RECT  29.4 80.677 32.412 80.869 ;
     RECT  39.984 79.283 40.632 80.869 ;
     RECT  42.768 79.331 43.32 80.917 ;
     RECT  61.68 80.293 63.096 80.917 ;
     RECT  64.32 78.899 65.112 80.917 ;
     RECT  2.4 79.475 2.712 81.061 ;
     RECT  61.68 80.917 65.112 81.203 ;
     RECT  17.472 80.291 17.496 81.205 ;
     RECT  18.48 80.341 19.992 81.205 ;
     RECT  53.7 79.475 54.012 81.205 ;
     RECT  51 80.341 52.488 81.251 ;
     RECT  17.472 81.205 19.992 81.299 ;
     RECT  24 80.291 24.312 81.349 ;
     RECT  42.768 80.917 43.896 81.397 ;
     RECT  45.6 79.283 46.344 81.397 ;
     RECT  36.24 79.189 36.264 81.443 ;
     RECT  21.024 80.291 22.968 81.445 ;
     RECT  55.872 80.821 57.864 81.491 ;
     RECT  61.68 81.203 62.808 81.491 ;
     RECT  4.704 80.293 10.812 81.539 ;
     RECT  12 79.717 13.512 81.539 ;
     RECT  29.4 80.869 32.664 81.587 ;
     RECT  2.4 81.061 3.288 81.635 ;
     RECT  55.872 81.491 57.816 81.635 ;
     RECT  69.408 80.149 70.728 81.635 ;
     RECT  15.9 80.291 16.44 81.733 ;
     RECT  26.496 80.773 27.816 81.875 ;
     RECT  37.392 80.677 38.28 81.875 ;
     RECT  42.768 81.397 46.344 81.875 ;
     RECT  64.032 81.203 65.112 81.973 ;
     RECT  55.872 81.635 57.384 82.021 ;
     RECT  60.432 81.445 60.456 82.021 ;
     RECT  66.624 80.435 67.512 82.021 ;
     RECT  24 81.349 25.224 82.067 ;
     RECT  4.704 81.539 5.976 82.069 ;
     RECT  7.536 81.539 10.812 82.115 ;
     RECT  39.984 80.869 41.592 82.115 ;
     RECT  44.784 81.875 46.344 82.115 ;
     RECT  60.432 82.021 60.552 82.115 ;
     RECT  15.9 81.733 16.488 82.117 ;
     RECT  17.472 81.299 19.608 82.117 ;
     RECT  15.9 82.117 19.608 82.259 ;
     RECT  9.648 82.115 10.812 82.547 ;
     RECT  66.624 82.021 68.136 82.643 ;
     RECT  29.4 81.587 32.412 82.645 ;
     RECT  29.184 82.645 32.412 82.691 ;
     RECT  67.104 82.643 68.136 82.693 ;
     RECT  3.984 82.069 5.976 82.739 ;
     RECT  26.7 81.875 27.816 82.739 ;
     RECT  39.984 82.115 41.064 82.739 ;
     RECT  32.1 82.691 32.412 82.741 ;
     RECT  4.704 82.739 5.976 82.789 ;
     RECT  7.536 82.115 8.232 82.789 ;
     RECT  12.48 81.539 13.512 82.789 ;
     RECT  14.832 81.445 14.856 82.789 ;
     RECT  29.184 82.691 31.128 82.835 ;
     RECT  61.8 81.491 62.808 82.837 ;
     RECT  64.032 81.973 65.496 82.837 ;
     RECT  21.024 81.445 23.016 82.931 ;
     RECT  10.368 82.547 10.812 82.933 ;
     RECT  10.368 82.933 11.4 82.979 ;
     RECT  51 81.251 52.248 82.981 ;
     RECT  32.1 82.741 33.096 83.027 ;
     RECT  61.8 82.837 65.496 83.075 ;
     RECT  51 82.981 52.44 83.125 ;
     RECT  53.568 81.205 54.012 83.125 ;
     RECT  15.9 82.259 16.488 83.219 ;
     RECT  40.2 82.739 41.064 83.219 ;
     RECT  4.704 82.789 8.232 83.221 ;
     RECT  44.784 82.115 45.912 83.221 ;
     RECT  21.024 82.931 21.612 83.267 ;
     RECT  12.48 82.789 14.856 83.315 ;
     RECT  42.768 81.875 43.32 83.363 ;
     RECT  29.4 82.835 31.128 83.459 ;
     RECT  69.9 81.635 70.728 83.459 ;
     RECT  34.8 77.315 35.112 83.461 ;
     RECT  60.528 82.115 60.552 83.507 ;
     RECT  4.704 83.221 8.52 83.605 ;
     RECT  12.48 83.315 14.088 83.605 ;
     RECT  51 83.125 54.012 83.701 ;
     RECT  4.704 83.605 8.952 83.795 ;
     RECT  12.384 83.605 14.088 83.843 ;
     RECT  44.784 83.221 46.728 83.843 ;
     RECT  10.5 82.979 11.4 84.035 ;
     RECT  33.648 83.509 33.672 84.037 ;
     RECT  34.8 83.461 35.88 84.037 ;
     RECT  61.8 83.075 63.288 84.037 ;
     RECT  64.5 83.075 65.496 84.037 ;
     RECT  33.648 84.037 35.88 84.083 ;
     RECT  67.104 82.693 68.376 84.083 ;
     RECT  61.8 84.037 65.496 84.085 ;
     RECT  37.392 81.875 37.812 84.325 ;
     RECT  38.784 82.597 38.808 84.325 ;
     RECT  40.2 83.219 40.512 84.325 ;
     RECT  59.1 78.659 59.412 84.325 ;
     RECT  37.392 84.325 38.808 84.371 ;
     RECT  17.472 82.259 19.608 84.419 ;
     RECT  50.88 83.701 54.012 84.563 ;
     RECT  55.392 82.021 57.384 84.563 ;
     RECT  61.8 84.085 65.592 84.565 ;
     RECT  7.8 83.795 8.952 84.611 ;
     RECT  61.056 84.565 65.592 84.661 ;
     RECT  22.992 82.931 23.016 84.805 ;
     RECT  45.6 83.843 46.728 84.851 ;
     RECT  12.384 83.843 13.512 84.853 ;
     RECT  29.4 83.459 30.6 84.853 ;
     RECT  60.384 84.661 65.592 84.853 ;
     RECT  67.104 84.083 67.512 84.853 ;
     RECT  60.384 84.853 67.512 84.899 ;
     RECT  42.768 83.363 43.212 84.901 ;
     RECT  45.6 84.851 46.2 84.995 ;
     RECT  60.384 84.899 65.016 84.995 ;
     RECT  56.4 84.563 57.384 84.997 ;
     RECT  58.464 84.325 59.412 84.997 ;
     RECT  17.472 84.419 18.912 85.091 ;
     RECT  7.8 84.611 8.52 85.139 ;
     RECT  15.9 83.219 16.392 85.141 ;
     RECT  37.392 84.371 38.52 85.189 ;
     RECT  15.504 85.141 16.392 85.381 ;
     RECT  18.6 85.091 18.912 85.381 ;
     RECT  69.9 83.459 70.44 85.429 ;
     RECT  69.408 85.429 70.44 85.475 ;
     RECT  10.5 84.035 10.812 85.477 ;
     RECT  12 84.853 13.512 85.477 ;
     RECT  66.096 84.899 67.512 85.477 ;
     RECT  26.7 82.739 27.336 85.523 ;
     RECT  37.056 85.189 38.52 85.619 ;
     RECT  49.584 83.173 49.608 85.619 ;
     RECT  51 84.563 54.012 85.619 ;
     RECT  66.096 85.477 67.608 85.619 ;
     RECT  55.392 84.563 55.416 85.621 ;
     RECT  56.4 84.997 59.412 85.621 ;
     RECT  55.392 85.621 59.412 85.667 ;
     RECT  4.704 83.795 6.648 85.907 ;
     RECT  22.8 84.805 23.016 85.907 ;
     RECT  51 85.619 52.248 85.907 ;
     RECT  24 82.067 24.312 85.909 ;
     RECT  28.512 84.853 30.6 85.957 ;
     RECT  60.384 84.995 62.76 86.005 ;
     RECT  17.472 85.091 17.496 86.053 ;
     RECT  18.6 85.381 19.128 86.053 ;
     RECT  26.7 85.523 27.192 86.099 ;
     RECT  25.68 86.005 25.704 86.197 ;
     RECT  26.7 86.099 27.012 86.197 ;
     RECT  64.08 84.995 65.016 86.197 ;
     RECT  66.72 85.619 67.608 86.243 ;
     RECT  9.504 85.477 9.528 86.341 ;
     RECT  10.5 85.477 13.512 86.341 ;
     RECT  33.648 84.083 35.352 86.483 ;
     RECT  44.544 84.949 44.568 86.483 ;
     RECT  45.6 84.995 46.104 86.533 ;
     RECT  7.8 85.139 8.376 86.629 ;
     RECT  9.504 86.341 13.512 86.629 ;
     RECT  48.3 80.819 48.612 86.629 ;
     RECT  64.08 86.197 65.592 86.629 ;
     RECT  4.704 85.907 5.88 86.675 ;
     RECT  28.512 85.957 30.936 86.675 ;
     RECT  7.8 86.629 13.512 86.723 ;
     RECT  15.408 85.381 16.392 86.723 ;
     RECT  60.384 86.005 63 86.771 ;
     RECT  67.2 86.243 67.608 86.771 ;
     RECT  7.8 86.723 11.688 87.013 ;
     RECT  13.104 86.723 13.512 87.059 ;
     RECT  29.088 86.675 30.936 87.059 ;
     RECT  22.992 85.907 23.016 87.109 ;
     RECT  24 85.909 24.408 87.109 ;
     RECT  29.4 87.059 30.936 87.251 ;
     RECT  55.68 85.667 59.412 87.251 ;
     RECT  60.912 86.771 63 87.251 ;
     RECT  64.08 86.629 65.928 87.251 ;
     RECT  15.792 86.723 16.392 87.299 ;
     RECT  37.056 85.619 38.472 87.299 ;
     RECT  17.472 86.053 19.128 87.301 ;
     RECT  20.112 87.013 20.136 87.301 ;
     RECT  15.792 87.299 16.344 87.347 ;
     RECT  42.144 84.901 43.212 87.443 ;
     RECT  65.904 87.251 65.928 87.539 ;
     RECT  55.68 87.251 56.712 87.587 ;
     RECT  61.8 87.251 62.76 87.587 ;
     RECT  25.68 86.197 27.012 87.683 ;
     RECT  44.976 86.533 46.104 87.731 ;
     RECT  69.408 85.475 70.212 87.733 ;
     RECT  47.328 86.629 48.612 87.781 ;
     RECT  4.704 86.675 5.832 87.827 ;
     RECT  25.824 87.683 27.012 87.827 ;
     RECT  33.648 86.483 35.112 87.827 ;
     RECT  37.5 87.299 38.472 87.827 ;
     RECT  51 85.907 51.912 87.875 ;
     RECT  47.328 87.781 49.032 87.923 ;
     RECT  7.68 87.013 11.688 88.115 ;
     RECT  21.3 83.267 21.612 88.117 ;
     RECT  22.992 87.109 24.408 88.163 ;
     RECT  7.68 88.115 11.496 88.211 ;
     RECT  15.9 87.347 16.344 88.355 ;
     RECT  45.6 87.731 46.104 88.355 ;
     RECT  68.928 87.733 70.212 88.355 ;
     RECT  29.4 87.251 29.712 88.357 ;
     RECT  30.912 87.251 30.936 88.357 ;
     RECT  17.472 87.301 20.136 88.403 ;
     RECT  29.4 88.357 30.936 88.403 ;
     RECT  34.416 87.827 35.112 88.403 ;
     RECT  40.2 84.325 40.872 88.403 ;
     RECT  57.984 87.251 59.412 88.403 ;
     RECT  18 88.403 20.136 88.451 ;
     RECT  61.8 87.587 62.664 88.547 ;
     RECT  47.328 87.923 48.612 88.595 ;
     RECT  7.68 88.211 9.288 88.643 ;
     RECT  28.32 87.733 28.344 88.643 ;
     RECT  4.704 87.827 5.688 88.739 ;
     RECT  23.088 88.163 24.408 88.787 ;
     RECT  58.272 88.403 59.412 88.787 ;
     RECT  7.68 88.643 9.096 88.883 ;
     RECT  37.5 87.827 37.812 88.885 ;
     RECT  40.2 88.403 40.512 88.885 ;
     RECT  4.8 88.739 5.688 88.979 ;
     RECT  14.544 88.309 14.568 88.979 ;
     RECT  58.464 88.787 59.412 88.979 ;
     RECT  64.08 87.251 64.812 88.981 ;
     RECT  56.304 87.587 56.712 89.269 ;
     RECT  49.824 88.117 49.848 89.459 ;
     RECT  64.08 88.981 65.016 89.459 ;
     RECT  51 87.875 51.312 89.461 ;
     RECT  18.192 88.451 19.368 89.507 ;
     RECT  10.5 88.211 11.496 89.555 ;
     RECT  21.168 88.117 21.612 89.555 ;
     RECT  23.232 88.787 24.408 89.555 ;
     RECT  56.304 89.269 57.096 89.555 ;
     RECT  64.5 89.459 65.016 89.939 ;
     RECT  69.312 88.355 70.212 89.987 ;
     RECT  18.6 89.507 19.368 90.083 ;
     RECT  29.4 88.403 30.264 90.083 ;
     RECT  39.312 88.885 40.512 90.083 ;
     RECT  56.4 89.555 57.096 90.083 ;
     RECT  7.8 88.883 9.096 90.227 ;
     RECT  23.232 89.555 24.312 90.227 ;
     RECT  4.8 88.979 5.412 90.275 ;
     RECT  51 89.461 52.248 90.515 ;
     RECT  10.5 89.555 11.4 90.563 ;
     RECT  37.392 88.885 37.812 90.563 ;
     RECT  45.6 88.355 46.008 90.563 ;
     RECT  2.4 81.635 2.712 90.729 ;
     RECT  5.1 90.275 5.412 90.729 ;
     RECT  7.8 90.227 8.112 90.729 ;
     RECT  10.5 90.563 10.812 90.729 ;
     RECT  13.2 87.059 13.512 90.729 ;
     RECT  15.9 88.355 16.212 90.729 ;
     RECT  18.6 90.083 18.912 90.729 ;
     RECT  21.3 89.555 21.612 90.729 ;
     RECT  24 90.227 24.312 90.729 ;
     RECT  26.7 87.827 27.012 90.729 ;
     RECT  29.4 90.083 29.712 90.729 ;
     RECT  32.1 83.027 32.412 90.729 ;
     RECT  34.8 88.403 35.112 90.729 ;
     RECT  37.5 90.563 37.812 90.729 ;
     RECT  40.2 90.083 40.512 90.729 ;
     RECT  42.9 87.443 43.212 90.729 ;
     RECT  45.6 90.563 45.912 90.729 ;
     RECT  48.3 88.595 48.612 90.729 ;
     RECT  51 90.515 51.312 90.729 ;
     RECT  53.7 85.619 54.012 90.729 ;
     RECT  56.4 90.083 56.712 90.729 ;
     RECT  59.1 88.979 59.412 90.729 ;
     RECT  61.8 88.547 62.112 90.729 ;
     RECT  64.5 89.939 64.812 90.729 ;
     RECT  67.2 86.771 67.512 90.729 ;
     RECT  69.9 89.987 70.212 90.729 ;
     RECT  72.6 2.151 72.912 90.729 ;
     RECT  2.4 90.729 2.52 90.743 ;
     RECT  5.1 90.729 5.22 90.743 ;
     RECT  7.8 90.729 7.92 90.743 ;
     RECT  10.5 90.729 10.62 90.743 ;
     RECT  13.2 90.729 13.32 90.743 ;
     RECT  15.9 90.729 16.02 90.743 ;
     RECT  18.6 90.729 18.72 90.743 ;
     RECT  21.3 90.729 21.42 90.743 ;
     RECT  24 90.729 24.12 90.743 ;
     RECT  26.7 90.729 26.82 90.743 ;
     RECT  29.4 90.729 29.52 90.743 ;
     RECT  32.1 90.729 32.22 90.743 ;
     RECT  34.8 90.729 34.92 90.743 ;
     RECT  37.5 90.729 37.62 90.743 ;
     RECT  40.2 90.729 40.32 90.743 ;
     RECT  42.9 90.729 43.02 90.743 ;
     RECT  45.6 90.729 45.72 90.743 ;
     RECT  48.3 90.729 48.42 90.743 ;
     RECT  51 90.729 51.12 90.743 ;
     RECT  53.7 90.729 53.82 90.743 ;
     RECT  56.4 90.729 56.52 90.743 ;
     RECT  59.1 90.729 59.22 90.743 ;
     RECT  61.8 90.729 61.92 90.743 ;
     RECT  64.5 90.729 64.62 90.743 ;
     RECT  67.2 90.729 67.32 90.743 ;
     RECT  69.9 90.729 70.02 90.743 ;
     RECT  72.6 90.729 72.72 90.743 ;
  END
END dsfd_xstg_515
END LIBRARY
